# Scaled down LEF created by ScaleLEFMacro.pl
# Original LEF: 16nm/HDDP_1024X66M4B1.lef
# Don't forget to change metal layer LEF separately!

# Copyright (c) 1993 - 2021 ARM Limited. All Rights Reserved.
# Use of this Software is subject to the terms and conditions of the
# applicable license agreement with ARM Limited.

# PhyVGen V 8.22.0
# ARM Version r3p1
# Creation Date: Sat Sep 18 23:18:15 2021


# Memory Configuration:
# ~~~~~~~~~~~~~~~~~~~~~
#  -activity_factor 50 -atf off -back_biasing off -bits 66 -bmux on
# -bus_notation on -check_instname on -compiler_type dp -diodes on -drive 6
# -ema on -flexible_banking 1 -frequency 1000 -instname HDDP_1024X66M4B1
# -left_bus_delim "[" -lren_bankmask off -metal_stack 2Xa1Xd -mux 4 -mvt LP
# -name_case upper -pipeline off -power_gating off -power_type otc -prefix ""
# -pwr_gnd_rename vddpe:VDDPE,vddce:VDDCE,vsse:VSSE -rcols 2 -redundancy on
# -retention on -right_bus_delim "]" -rows_p_bl 256 -rrows 0 -scan on -ser none
# -site_def off -vmin_assist off -words 1024 -write_mask on -write_thru off
# -corners tt_0p80v_0p80v_25c
# 

VERSION 5.7 ;
BUSBITCHARS "[]" ;
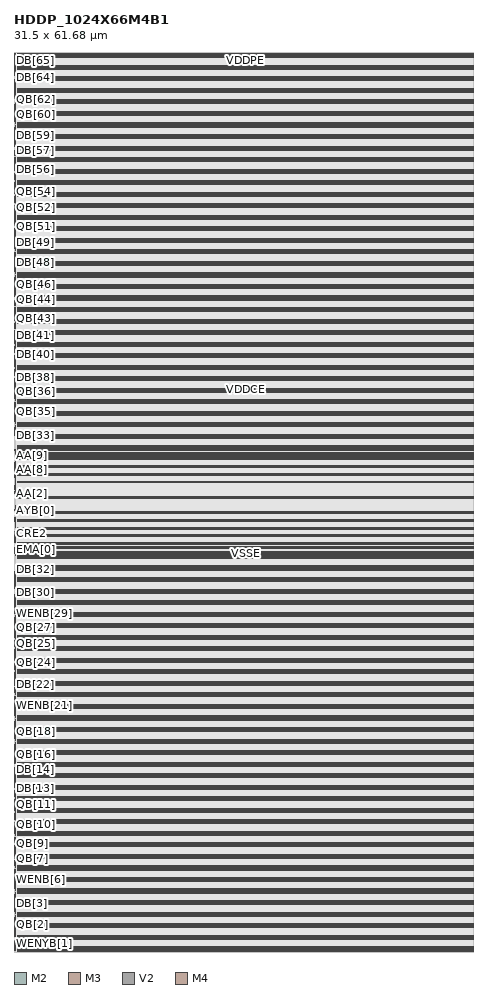
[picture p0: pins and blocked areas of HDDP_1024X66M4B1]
MACRO HDDP_1024X66M4B1
	FOREIGN HDDP_1024X66M4B1 0 0 ;
	SYMMETRY X Y ;
	SIZE 31.5 BY 61.68 ;
	CLASS BLOCK ;
	PIN AA[0]
		USE SIGNAL ;
		DIRECTION INPUT ;
		SHAPE ABUTMENT ;
		PORT
			 LAYER M2 ;
			RECT 0.0098 30.3184 0.0481 30.3561 ;
		END

		ANTENNAGATEAREA 0.00027817 ;
		ANTENNADIFFAREA 0.00194719 ;
		ANTENNAPARTIALMETALAREA 0.00195671 ;
	END AA[0]

	PIN AA[1]
		USE SIGNAL ;
		DIRECTION INPUT ;
		SHAPE ABUTMENT ;
		PORT
			 LAYER M2 ;
			RECT 0.0098 30.3812 0.0481 30.4188 ;
		END

		ANTENNAGATEAREA 0.00027817 ;
		ANTENNADIFFAREA 0.00194719 ;
		ANTENNAPARTIALMETALAREA 0.00195671 ;
	END AA[1]

	PIN AA[2]
		USE SIGNAL ;
		DIRECTION INPUT ;
		SHAPE ABUTMENT ;
		PORT
			 LAYER M2 ;
			RECT 0.0098 31.4353 0.0481 31.4729 ;
		END

		ANTENNAGATEAREA 0.00027817 ;
		ANTENNADIFFAREA 0.00194719 ;
		ANTENNAPARTIALMETALAREA 0.00195671 ;
	END AA[2]

	PIN AA[3]
		USE SIGNAL ;
		DIRECTION INPUT ;
		SHAPE ABUTMENT ;
		PORT
			 LAYER M2 ;
			RECT 0.0098 31.8996 0.0481 31.9373 ;
		END

		ANTENNAGATEAREA 0.00027817 ;
		ANTENNADIFFAREA 0.00194719 ;
		ANTENNAPARTIALMETALAREA 0.00195671 ;
	END AA[3]

	PIN AA[4]
		USE SIGNAL ;
		DIRECTION INPUT ;
		SHAPE ABUTMENT ;
		PORT
			 LAYER M2 ;
			RECT 0.0098 31.9624 0.0481 32 ;
		END

		ANTENNAGATEAREA 0.00027817 ;
		ANTENNADIFFAREA 0.00194719 ;
		ANTENNAPARTIALMETALAREA 0.00195671 ;
	END AA[4]

	PIN AA[5]
		USE SIGNAL ;
		DIRECTION INPUT ;
		SHAPE ABUTMENT ;
		PORT
			 LAYER M2 ;
			RECT 0.0098 32.4267 0.0481 32.4643 ;
		END

		ANTENNAGATEAREA 0.00027817 ;
		ANTENNADIFFAREA 0.00194719 ;
		ANTENNAPARTIALMETALAREA 0.00195671 ;
	END AA[5]

	PIN AA[6]
		USE SIGNAL ;
		DIRECTION INPUT ;
		SHAPE ABUTMENT ;
		PORT
			 LAYER M2 ;
			RECT 0.0098 32.4894 0.0481 32.5271 ;
		END

		ANTENNAGATEAREA 0.00027817 ;
		ANTENNADIFFAREA 0.00194719 ;
		ANTENNAPARTIALMETALAREA 0.00195671 ;
	END AA[6]

	PIN AA[7]
		USE SIGNAL ;
		DIRECTION INPUT ;
		SHAPE ABUTMENT ;
		PORT
			 LAYER M2 ;
			RECT 0.0098 32.9537 0.0481 32.9914 ;
		END

		ANTENNAGATEAREA 0.00027817 ;
		ANTENNADIFFAREA 0.00194719 ;
		ANTENNAPARTIALMETALAREA 0.00195671 ;
	END AA[7]

	PIN AA[8]
		USE SIGNAL ;
		DIRECTION INPUT ;
		SHAPE ABUTMENT ;
		PORT
			 LAYER M2 ;
			RECT 0.0098 33.0165 0.0481 33.0541 ;
		END

		ANTENNAGATEAREA 0.00027817 ;
		ANTENNADIFFAREA 0.00194719 ;
		ANTENNAPARTIALMETALAREA 0.00195671 ;
	END AA[8]

	PIN AA[9]
		USE SIGNAL ;
		DIRECTION INPUT ;
		SHAPE ABUTMENT ;
		PORT
			 LAYER M2 ;
			RECT 0.0098 33.4808 0.0481 33.5184 ;
		END

		ANTENNAGATEAREA 0.00027817 ;
		ANTENNADIFFAREA 0.00194719 ;
		ANTENNAPARTIALMETALAREA 0.00195671 ;
	END AA[9]

	PIN AB[0]
		USE SIGNAL ;
		DIRECTION INPUT ;
		SHAPE ABUTMENT ;
		PORT
			 LAYER M3 ;
			RECT 0.0714 30.1051 0.1097 30.2055 ;
		END

		ANTENNAGATEAREA 0.00027817 ;
		ANTENNADIFFAREA 0.00194719 ;
		ANTENNAPARTIALMETALAREA 0.00195671 ;
	END AB[0]

	PIN AB[1]
		USE SIGNAL ;
		DIRECTION INPUT ;
		SHAPE ABUTMENT ;
		PORT
			 LAYER M3 ;
			RECT 0.0714 30.5067 0.1097 30.6071 ;
		END

		ANTENNAGATEAREA 0.00027817 ;
		ANTENNADIFFAREA 0.00194719 ;
		ANTENNAPARTIALMETALAREA 0.00195671 ;
	END AB[1]

	PIN AB[2]
		USE SIGNAL ;
		DIRECTION INPUT ;
		SHAPE ABUTMENT ;
		PORT
			 LAYER M2 ;
			RECT 0.0098 34.3718 0.0481 34.4094 ;
		END

		ANTENNAGATEAREA 0.00027817 ;
		ANTENNADIFFAREA 0.00194719 ;
		ANTENNAPARTIALMETALAREA 0.00195671 ;
	END AB[2]

	PIN AB[3]
		USE SIGNAL ;
		DIRECTION INPUT ;
		SHAPE ABUTMENT ;
		PORT
			 LAYER M3 ;
			RECT 0.0714 31.7114 0.1097 31.8118 ;
		END

		ANTENNAGATEAREA 0.00027817 ;
		ANTENNADIFFAREA 0.00194719 ;
		ANTENNAPARTIALMETALAREA 0.00195671 ;
	END AB[3]

	PIN AB[4]
		USE SIGNAL ;
		DIRECTION INPUT ;
		SHAPE ABUTMENT ;
		PORT
			 LAYER M3 ;
			RECT 0.0714 32.0878 0.1097 32.1882 ;
		END

		ANTENNAGATEAREA 0.00027817 ;
		ANTENNADIFFAREA 0.00194719 ;
		ANTENNAPARTIALMETALAREA 0.00195671 ;
	END AB[4]

	PIN AB[5]
		USE SIGNAL ;
		DIRECTION INPUT ;
		SHAPE ABUTMENT ;
		PORT
			 LAYER M3 ;
			RECT 0.0714 32.2384 0.1097 32.3388 ;
		END

		ANTENNAGATEAREA 0.00027817 ;
		ANTENNADIFFAREA 0.00194719 ;
		ANTENNAPARTIALMETALAREA 0.00195671 ;
	END AB[5]

	PIN AB[6]
		USE SIGNAL ;
		DIRECTION INPUT ;
		SHAPE ABUTMENT ;
		PORT
			 LAYER M3 ;
			RECT 0.0714 32.6149 0.1097 32.7153 ;
		END

		ANTENNAGATEAREA 0.00027817 ;
		ANTENNADIFFAREA 0.00194719 ;
		ANTENNAPARTIALMETALAREA 0.00195671 ;
	END AB[6]

	PIN AB[7]
		USE SIGNAL ;
		DIRECTION INPUT ;
		SHAPE ABUTMENT ;
		PORT
			 LAYER M3 ;
			RECT 0.0714 32.7655 0.1097 32.8659 ;
		END

		ANTENNAGATEAREA 0.00027817 ;
		ANTENNADIFFAREA 0.00194719 ;
		ANTENNAPARTIALMETALAREA 0.00195671 ;
	END AB[7]

	PIN AB[8]
		USE SIGNAL ;
		DIRECTION INPUT ;
		SHAPE ABUTMENT ;
		PORT
			 LAYER M3 ;
			RECT 0.0714 33.142 0.1097 33.2424 ;
		END

		ANTENNAGATEAREA 0.00027817 ;
		ANTENNADIFFAREA 0.00194719 ;
		ANTENNAPARTIALMETALAREA 0.00195671 ;
	END AB[8]

	PIN AB[9]
		USE SIGNAL ;
		DIRECTION INPUT ;
		SHAPE ABUTMENT ;
		PORT
			 LAYER M3 ;
			RECT 0.0714 33.2925 0.1097 33.3929 ;
		END

		ANTENNAGATEAREA 0.00027817 ;
		ANTENNADIFFAREA 0.00194719 ;
		ANTENNAPARTIALMETALAREA 0.00195671 ;
	END AB[9]

	PIN AYA[0]
		USE SIGNAL ;
		DIRECTION OUTPUT ;
		SHAPE ABUTMENT ;
		PORT
			 LAYER M3 ;
			RECT 0.0714 30.2557 0.1097 30.3561 ;
		END

		ANTENNADIFFAREA 0.00194719 ;
		ANTENNAPARTIALMETALAREA 0.00195671 ;
	END AYA[0]

	PIN AYA[1]
		USE SIGNAL ;
		DIRECTION OUTPUT ;
		SHAPE ABUTMENT ;
		PORT
			 LAYER M3 ;
			RECT 0.0714 30.3812 0.1097 30.4816 ;
		END

		ANTENNADIFFAREA 0.00194719 ;
		ANTENNAPARTIALMETALAREA 0.00195671 ;
	END AYA[1]

	PIN AYA[2]
		USE SIGNAL ;
		DIRECTION OUTPUT ;
		SHAPE ABUTMENT ;
		PORT
			 LAYER M3 ;
			RECT 0.0714 31.4353 0.1097 31.5357 ;
		END

		ANTENNADIFFAREA 0.00194719 ;
		ANTENNAPARTIALMETALAREA 0.00195671 ;
	END AYA[2]

	PIN AYA[3]
		USE SIGNAL ;
		DIRECTION OUTPUT ;
		SHAPE ABUTMENT ;
		PORT
			 LAYER M3 ;
			RECT 0.0714 31.8369 0.1097 31.9373 ;
		END

		ANTENNADIFFAREA 0.00194719 ;
		ANTENNAPARTIALMETALAREA 0.00195671 ;
	END AYA[3]

	PIN AYA[4]
		USE SIGNAL ;
		DIRECTION OUTPUT ;
		SHAPE ABUTMENT ;
		PORT
			 LAYER M3 ;
			RECT 0.0714 31.9624 0.1097 32.0627 ;
		END

		ANTENNADIFFAREA 0.00194719 ;
		ANTENNAPARTIALMETALAREA 0.00195671 ;
	END AYA[4]

	PIN AYA[5]
		USE SIGNAL ;
		DIRECTION OUTPUT ;
		SHAPE ABUTMENT ;
		PORT
			 LAYER M3 ;
			RECT 0.0714 32.3639 0.1097 32.4643 ;
		END

		ANTENNADIFFAREA 0.00194719 ;
		ANTENNAPARTIALMETALAREA 0.00195671 ;
	END AYA[5]

	PIN AYA[6]
		USE SIGNAL ;
		DIRECTION OUTPUT ;
		SHAPE ABUTMENT ;
		PORT
			 LAYER M3 ;
			RECT 0.0714 32.4894 0.1097 32.5898 ;
		END

		ANTENNADIFFAREA 0.00194719 ;
		ANTENNAPARTIALMETALAREA 0.00195671 ;
	END AYA[6]

	PIN AYA[7]
		USE SIGNAL ;
		DIRECTION OUTPUT ;
		SHAPE ABUTMENT ;
		PORT
			 LAYER M3 ;
			RECT 0.0714 32.891 0.1097 32.9914 ;
		END

		ANTENNADIFFAREA 0.00194719 ;
		ANTENNAPARTIALMETALAREA 0.00195671 ;
	END AYA[7]

	PIN AYA[8]
		USE SIGNAL ;
		DIRECTION OUTPUT ;
		SHAPE ABUTMENT ;
		PORT
			 LAYER M3 ;
			RECT 0.0714 33.0165 0.1097 33.1169 ;
		END

		ANTENNADIFFAREA 0.00194719 ;
		ANTENNAPARTIALMETALAREA 0.00195671 ;
	END AYA[8]

	PIN AYA[9]
		USE SIGNAL ;
		DIRECTION OUTPUT ;
		SHAPE ABUTMENT ;
		PORT
			 LAYER M3 ;
			RECT 0.0714 33.418 0.1097 33.5184 ;
		END

		ANTENNADIFFAREA 0.00194719 ;
		ANTENNAPARTIALMETALAREA 0.00195671 ;
	END AYA[9]

	PIN AYB[0]
		USE SIGNAL ;
		DIRECTION OUTPUT ;
		SHAPE ABUTMENT ;
		PORT
			 LAYER M2 ;
			RECT 0.0098 30.2557 0.0481 30.2933 ;
		END

		ANTENNADIFFAREA 0.00194719 ;
		ANTENNAPARTIALMETALAREA 0.00195671 ;
	END AYB[0]

	PIN AYB[1]
		USE SIGNAL ;
		DIRECTION OUTPUT ;
		SHAPE ABUTMENT ;
		PORT
			 LAYER M2 ;
			RECT 0.0098 30.4439 0.0481 30.4816 ;
		END

		ANTENNADIFFAREA 0.00194719 ;
		ANTENNAPARTIALMETALAREA 0.00195671 ;
	END AYB[1]

	PIN AYB[2]
		USE SIGNAL ;
		DIRECTION OUTPUT ;
		SHAPE ABUTMENT ;
		PORT
			 LAYER M2 ;
			RECT 0.0098 31.498 0.0481 31.5357 ;
		END

		ANTENNADIFFAREA 0.00194719 ;
		ANTENNAPARTIALMETALAREA 0.00195671 ;
	END AYB[2]

	PIN AYB[3]
		USE SIGNAL ;
		DIRECTION OUTPUT ;
		SHAPE ABUTMENT ;
		PORT
			 LAYER M2 ;
			RECT 0.0098 31.8369 0.0481 31.8745 ;
		END

		ANTENNADIFFAREA 0.00194719 ;
		ANTENNAPARTIALMETALAREA 0.00195671 ;
	END AYB[3]

	PIN AYB[4]
		USE SIGNAL ;
		DIRECTION OUTPUT ;
		SHAPE ABUTMENT ;
		PORT
			 LAYER M2 ;
			RECT 0.0098 32.0251 0.0481 32.0627 ;
		END

		ANTENNADIFFAREA 0.00194719 ;
		ANTENNAPARTIALMETALAREA 0.00195671 ;
	END AYB[4]

	PIN AYB[5]
		USE SIGNAL ;
		DIRECTION OUTPUT ;
		SHAPE ABUTMENT ;
		PORT
			 LAYER M2 ;
			RECT 0.0098 32.3639 0.0481 32.4016 ;
		END

		ANTENNADIFFAREA 0.00194719 ;
		ANTENNAPARTIALMETALAREA 0.00195671 ;
	END AYB[5]

	PIN AYB[6]
		USE SIGNAL ;
		DIRECTION OUTPUT ;
		SHAPE ABUTMENT ;
		PORT
			 LAYER M2 ;
			RECT 0.0098 32.5522 0.0481 32.5898 ;
		END

		ANTENNADIFFAREA 0.00194719 ;
		ANTENNAPARTIALMETALAREA 0.00195671 ;
	END AYB[6]

	PIN AYB[7]
		USE SIGNAL ;
		DIRECTION OUTPUT ;
		SHAPE ABUTMENT ;
		PORT
			 LAYER M2 ;
			RECT 0.0098 32.891 0.0481 32.9286 ;
		END

		ANTENNADIFFAREA 0.00194719 ;
		ANTENNAPARTIALMETALAREA 0.00195671 ;
	END AYB[7]

	PIN AYB[8]
		USE SIGNAL ;
		DIRECTION OUTPUT ;
		SHAPE ABUTMENT ;
		PORT
			 LAYER M2 ;
			RECT 0.0098 33.0792 0.0481 33.1169 ;
		END

		ANTENNADIFFAREA 0.00194719 ;
		ANTENNAPARTIALMETALAREA 0.00195671 ;
	END AYB[8]

	PIN AYB[9]
		USE SIGNAL ;
		DIRECTION OUTPUT ;
		SHAPE ABUTMENT ;
		PORT
			 LAYER M2 ;
			RECT 0.0098 33.418 0.0481 33.4557 ;
		END

		ANTENNADIFFAREA 0.00194719 ;
		ANTENNAPARTIALMETALAREA 0.00195671 ;
	END AYB[9]

	PIN CENA
		USE SIGNAL ;
		DIRECTION INPUT ;
		SHAPE ABUTMENT ;
		PORT
			 LAYER M2 ;
			RECT 0.0098 33.5435 0.0481 33.5812 ;
		END

		ANTENNAGATEAREA 0.00027817 ;
		ANTENNADIFFAREA 0.00194719 ;
		ANTENNAPARTIALMETALAREA 0.00195671 ;
	END CENA

	PIN CENB
		USE SIGNAL ;
		DIRECTION INPUT ;
		SHAPE ABUTMENT ;
		PORT
			 LAYER M3 ;
			RECT 0.0714 33.669 0.1097 33.7694 ;
		END

		ANTENNAGATEAREA 0.00027817 ;
		ANTENNADIFFAREA 0.00194719 ;
		ANTENNAPARTIALMETALAREA 0.00195671 ;
	END CENB

	PIN CENYA
		USE SIGNAL ;
		DIRECTION OUTPUT ;
		SHAPE ABUTMENT ;
		PORT
			 LAYER M3 ;
			RECT 0.0714 33.5435 0.1097 33.6439 ;
		END

		ANTENNADIFFAREA 0.00194719 ;
		ANTENNAPARTIALMETALAREA 0.00195671 ;
	END CENYA

	PIN CENYB
		USE SIGNAL ;
		DIRECTION OUTPUT ;
		SHAPE ABUTMENT ;
		PORT
			 LAYER M2 ;
			RECT 0.0098 33.6063 0.0481 33.6439 ;
		END

		ANTENNADIFFAREA 0.00194719 ;
		ANTENNAPARTIALMETALAREA 0.00195671 ;
	END CENYB

	PIN CLK
		USE SIGNAL ;
		DIRECTION INPUT ;
		SHAPE ABUTMENT ;
		PORT
			 LAYER M3 ;
			RECT 0.0714 29.6533 0.1097 29.7537 ;
		END

		ANTENNAGATEAREA 0.00027817 ;
		ANTENNADIFFAREA 0.00194719 ;
		ANTENNAPARTIALMETALAREA 0.00195671 ;
	END CLK

	PIN CRE1
		USE SIGNAL ;
		DIRECTION INPUT ;
		SHAPE ABUTMENT ;
		PORT
			 LAYER M3 ;
			RECT 0.0714 28.0722 0.1097 28.1725 ;
		END

		ANTENNAGATEAREA 0.00027817 ;
		ANTENNADIFFAREA 0.00194719 ;
		ANTENNAPARTIALMETALAREA 0.00195671 ;
	END CRE1

	PIN CRE2
		USE SIGNAL ;
		DIRECTION INPUT ;
		SHAPE ABUTMENT ;
		PORT
			 LAYER M2 ;
			RECT 0.0098 28.6871 0.0481 28.7247 ;
		END

		ANTENNAGATEAREA 0.00027817 ;
		ANTENNADIFFAREA 0.00194719 ;
		ANTENNAPARTIALMETALAREA 0.00195671 ;
	END CRE2

	PIN DA[0]
		USE SIGNAL ;
		DIRECTION INPUT ;
		SHAPE ABUTMENT ;
		PORT
			 LAYER M2 ;
			RECT 0.0714 0.6024 0.1097 0.64 ;
			 LAYER M3 ;
			RECT 0.0714 0.5396 0.1097 0.64 ;
			 LAYER V2 ;
			RECT 0.0831 0.6153 0.098 0.6278 ;
		END

		ANTENNAGATEAREA 0.00027817 ;
		ANTENNADIFFAREA 0.00194719 ;
		ANTENNAPARTIALMETALAREA 0.00195671 ;
	END DA[0]

	PIN DA[10]
		USE SIGNAL ;
		DIRECTION INPUT ;
		SHAPE ABUTMENT ;
		PORT
			 LAYER M2 ;
			RECT 0.0714 8.5082 0.1097 8.5459 ;
			 LAYER M3 ;
			RECT 0.0714 8.4455 0.1097 8.5459 ;
			 LAYER V2 ;
			RECT 0.0831 8.5212 0.098 8.5337 ;
		END

		ANTENNAGATEAREA 0.00027817 ;
		ANTENNADIFFAREA 0.00194719 ;
		ANTENNAPARTIALMETALAREA 0.00195671 ;
	END DA[10]

	PIN DA[11]
		USE SIGNAL ;
		DIRECTION INPUT ;
		SHAPE ABUTMENT ;
		PORT
			 LAYER M2 ;
			RECT 0.0714 9.2988 0.1097 9.3365 ;
			 LAYER M3 ;
			RECT 0.0714 9.2361 0.1097 9.3365 ;
			 LAYER V2 ;
			RECT 0.0831 9.3118 0.098 9.3243 ;
		END

		ANTENNAGATEAREA 0.00027817 ;
		ANTENNADIFFAREA 0.00194719 ;
		ANTENNAPARTIALMETALAREA 0.00195671 ;
	END DA[11]

	PIN DA[12]
		USE SIGNAL ;
		DIRECTION INPUT ;
		SHAPE ABUTMENT ;
		PORT
			 LAYER M2 ;
			RECT 0.0714 10.0894 0.1097 10.1271 ;
			 LAYER M3 ;
			RECT 0.0714 10.0267 0.1097 10.1271 ;
			 LAYER V2 ;
			RECT 0.0831 10.1024 0.098 10.1149 ;
		END

		ANTENNAGATEAREA 0.00027817 ;
		ANTENNADIFFAREA 0.00194719 ;
		ANTENNAPARTIALMETALAREA 0.00195671 ;
	END DA[12]

	PIN DA[13]
		USE SIGNAL ;
		DIRECTION INPUT ;
		SHAPE ABUTMENT ;
		PORT
			 LAYER M2 ;
			RECT 0.0714 10.88 0.1097 10.9176 ;
			 LAYER M3 ;
			RECT 0.0714 10.8173 0.1097 10.9176 ;
			 LAYER V2 ;
			RECT 0.0831 10.8929 0.098 10.9055 ;
		END

		ANTENNAGATEAREA 0.00027817 ;
		ANTENNADIFFAREA 0.00194719 ;
		ANTENNAPARTIALMETALAREA 0.00195671 ;
	END DA[13]

	PIN DA[14]
		USE SIGNAL ;
		DIRECTION INPUT ;
		SHAPE ABUTMENT ;
		PORT
			 LAYER M2 ;
			RECT 0.0714 11.6706 0.1097 11.7082 ;
			 LAYER M3 ;
			RECT 0.0714 11.6078 0.1097 11.7082 ;
			 LAYER V2 ;
			RECT 0.0831 11.6835 0.098 11.6961 ;
		END

		ANTENNAGATEAREA 0.00027817 ;
		ANTENNADIFFAREA 0.00194719 ;
		ANTENNAPARTIALMETALAREA 0.00195671 ;
	END DA[14]

	PIN DA[15]
		USE SIGNAL ;
		DIRECTION INPUT ;
		SHAPE ABUTMENT ;
		PORT
			 LAYER M2 ;
			RECT 0.0714 12.4612 0.1097 12.4988 ;
			 LAYER M3 ;
			RECT 0.0714 12.3984 0.1097 12.4988 ;
			 LAYER V2 ;
			RECT 0.0831 12.4741 0.098 12.4867 ;
		END

		ANTENNAGATEAREA 0.00027817 ;
		ANTENNADIFFAREA 0.00194719 ;
		ANTENNAPARTIALMETALAREA 0.00195671 ;
	END DA[15]

	PIN DA[16]
		USE SIGNAL ;
		DIRECTION INPUT ;
		SHAPE ABUTMENT ;
		PORT
			 LAYER M2 ;
			RECT 0.0714 13.2518 0.1097 13.2894 ;
			 LAYER M3 ;
			RECT 0.0714 13.189 0.1097 13.2894 ;
			 LAYER V2 ;
			RECT 0.0831 13.2647 0.098 13.2773 ;
		END

		ANTENNAGATEAREA 0.00027817 ;
		ANTENNADIFFAREA 0.00194719 ;
		ANTENNAPARTIALMETALAREA 0.00195671 ;
	END DA[16]

	PIN DA[17]
		USE SIGNAL ;
		DIRECTION INPUT ;
		SHAPE ABUTMENT ;
		PORT
			 LAYER M2 ;
			RECT 0.0714 14.0424 0.1097 14.08 ;
			 LAYER M3 ;
			RECT 0.0714 13.9796 0.1097 14.08 ;
			 LAYER V2 ;
			RECT 0.0831 14.0553 0.098 14.0678 ;
		END

		ANTENNAGATEAREA 0.00027817 ;
		ANTENNADIFFAREA 0.00194719 ;
		ANTENNAPARTIALMETALAREA 0.00195671 ;
	END DA[17]

	PIN DA[18]
		USE SIGNAL ;
		DIRECTION INPUT ;
		SHAPE ABUTMENT ;
		PORT
			 LAYER M2 ;
			RECT 0.0714 14.8329 0.1097 14.8706 ;
			 LAYER M3 ;
			RECT 0.0714 14.7702 0.1097 14.8706 ;
			 LAYER V2 ;
			RECT 0.0831 14.8459 0.098 14.8584 ;
		END

		ANTENNAGATEAREA 0.00027817 ;
		ANTENNADIFFAREA 0.00194719 ;
		ANTENNAPARTIALMETALAREA 0.00195671 ;
	END DA[18]

	PIN DA[19]
		USE SIGNAL ;
		DIRECTION INPUT ;
		SHAPE ABUTMENT ;
		PORT
			 LAYER M2 ;
			RECT 0.0714 15.6235 0.1097 15.6612 ;
			 LAYER M3 ;
			RECT 0.0714 15.5608 0.1097 15.6612 ;
			 LAYER V2 ;
			RECT 0.0831 15.6365 0.098 15.649 ;
		END

		ANTENNAGATEAREA 0.00027817 ;
		ANTENNADIFFAREA 0.00194719 ;
		ANTENNAPARTIALMETALAREA 0.00195671 ;
	END DA[19]

	PIN DA[1]
		USE SIGNAL ;
		DIRECTION INPUT ;
		SHAPE ABUTMENT ;
		PORT
			 LAYER M2 ;
			RECT 0.0714 1.3929 0.1097 1.4306 ;
			 LAYER M3 ;
			RECT 0.0714 1.3302 0.1097 1.4306 ;
			 LAYER V2 ;
			RECT 0.0831 1.4059 0.098 1.4184 ;
		END

		ANTENNAGATEAREA 0.00027817 ;
		ANTENNADIFFAREA 0.00194719 ;
		ANTENNAPARTIALMETALAREA 0.00195671 ;
	END DA[1]

	PIN DA[20]
		USE SIGNAL ;
		DIRECTION INPUT ;
		SHAPE ABUTMENT ;
		PORT
			 LAYER M2 ;
			RECT 0.0714 16.4141 0.1097 16.4518 ;
			 LAYER M3 ;
			RECT 0.0714 16.3514 0.1097 16.4518 ;
			 LAYER V2 ;
			RECT 0.0831 16.4271 0.098 16.4396 ;
		END

		ANTENNAGATEAREA 0.00027817 ;
		ANTENNADIFFAREA 0.00194719 ;
		ANTENNAPARTIALMETALAREA 0.00195671 ;
	END DA[20]

	PIN DA[21]
		USE SIGNAL ;
		DIRECTION INPUT ;
		SHAPE ABUTMENT ;
		PORT
			 LAYER M2 ;
			RECT 0.0714 17.2047 0.1097 17.2424 ;
			 LAYER M3 ;
			RECT 0.0714 17.142 0.1097 17.2424 ;
			 LAYER V2 ;
			RECT 0.0831 17.2176 0.098 17.2302 ;
		END

		ANTENNAGATEAREA 0.00027817 ;
		ANTENNADIFFAREA 0.00194719 ;
		ANTENNAPARTIALMETALAREA 0.00195671 ;
	END DA[21]

	PIN DA[22]
		USE SIGNAL ;
		DIRECTION INPUT ;
		SHAPE ABUTMENT ;
		PORT
			 LAYER M2 ;
			RECT 0.0714 17.9953 0.1097 18.0329 ;
			 LAYER M3 ;
			RECT 0.0714 17.9325 0.1097 18.0329 ;
			 LAYER V2 ;
			RECT 0.0831 18.0082 0.098 18.0208 ;
		END

		ANTENNAGATEAREA 0.00027817 ;
		ANTENNADIFFAREA 0.00194719 ;
		ANTENNAPARTIALMETALAREA 0.00195671 ;
	END DA[22]

	PIN DA[23]
		USE SIGNAL ;
		DIRECTION INPUT ;
		SHAPE ABUTMENT ;
		PORT
			 LAYER M2 ;
			RECT 0.0714 18.7859 0.1097 18.8235 ;
			 LAYER M3 ;
			RECT 0.0714 18.7231 0.1097 18.8235 ;
			 LAYER V2 ;
			RECT 0.0831 18.7988 0.098 18.8114 ;
		END

		ANTENNAGATEAREA 0.00027817 ;
		ANTENNADIFFAREA 0.00194719 ;
		ANTENNAPARTIALMETALAREA 0.00195671 ;
	END DA[23]

	PIN DA[24]
		USE SIGNAL ;
		DIRECTION INPUT ;
		SHAPE ABUTMENT ;
		PORT
			 LAYER M2 ;
			RECT 0.0714 19.5765 0.1097 19.6141 ;
			 LAYER M3 ;
			RECT 0.0714 19.5137 0.1097 19.6141 ;
			 LAYER V2 ;
			RECT 0.0831 19.5894 0.098 19.602 ;
		END

		ANTENNAGATEAREA 0.00027817 ;
		ANTENNADIFFAREA 0.00194719 ;
		ANTENNAPARTIALMETALAREA 0.00195671 ;
	END DA[24]

	PIN DA[25]
		USE SIGNAL ;
		DIRECTION INPUT ;
		SHAPE ABUTMENT ;
		PORT
			 LAYER M2 ;
			RECT 0.0714 20.3671 0.1097 20.4047 ;
			 LAYER M3 ;
			RECT 0.0714 20.3043 0.1097 20.4047 ;
			 LAYER V2 ;
			RECT 0.0831 20.38 0.098 20.3925 ;
		END

		ANTENNAGATEAREA 0.00027817 ;
		ANTENNADIFFAREA 0.00194719 ;
		ANTENNAPARTIALMETALAREA 0.00195671 ;
	END DA[25]

	PIN DA[26]
		USE SIGNAL ;
		DIRECTION INPUT ;
		SHAPE ABUTMENT ;
		PORT
			 LAYER M2 ;
			RECT 0.0714 21.1576 0.1097 21.1953 ;
			 LAYER M3 ;
			RECT 0.0714 21.0949 0.1097 21.1953 ;
			 LAYER V2 ;
			RECT 0.0831 21.1706 0.098 21.1831 ;
		END

		ANTENNAGATEAREA 0.00027817 ;
		ANTENNADIFFAREA 0.00194719 ;
		ANTENNAPARTIALMETALAREA 0.00195671 ;
	END DA[26]

	PIN DA[27]
		USE SIGNAL ;
		DIRECTION INPUT ;
		SHAPE ABUTMENT ;
		PORT
			 LAYER M2 ;
			RECT 0.0714 21.9482 0.1097 21.9859 ;
			 LAYER M3 ;
			RECT 0.0714 21.8855 0.1097 21.9859 ;
			 LAYER V2 ;
			RECT 0.0831 21.9612 0.098 21.9737 ;
		END

		ANTENNAGATEAREA 0.00027817 ;
		ANTENNADIFFAREA 0.00194719 ;
		ANTENNAPARTIALMETALAREA 0.00195671 ;
	END DA[27]

	PIN DA[28]
		USE SIGNAL ;
		DIRECTION INPUT ;
		SHAPE ABUTMENT ;
		PORT
			 LAYER M2 ;
			RECT 0.0714 22.7388 0.1097 22.7765 ;
			 LAYER M3 ;
			RECT 0.0714 22.6761 0.1097 22.7765 ;
			 LAYER V2 ;
			RECT 0.0831 22.7518 0.098 22.7643 ;
		END

		ANTENNAGATEAREA 0.00027817 ;
		ANTENNADIFFAREA 0.00194719 ;
		ANTENNAPARTIALMETALAREA 0.00195671 ;
	END DA[28]

	PIN DA[29]
		USE SIGNAL ;
		DIRECTION INPUT ;
		SHAPE ABUTMENT ;
		PORT
			 LAYER M2 ;
			RECT 0.0714 23.5294 0.1097 23.5671 ;
			 LAYER M3 ;
			RECT 0.0714 23.4667 0.1097 23.5671 ;
			 LAYER V2 ;
			RECT 0.0831 23.5424 0.098 23.5549 ;
		END

		ANTENNAGATEAREA 0.00027817 ;
		ANTENNADIFFAREA 0.00194719 ;
		ANTENNAPARTIALMETALAREA 0.00195671 ;
	END DA[29]

	PIN DA[2]
		USE SIGNAL ;
		DIRECTION INPUT ;
		SHAPE ABUTMENT ;
		PORT
			 LAYER M2 ;
			RECT 0.0714 2.1835 0.1097 2.2212 ;
			 LAYER M3 ;
			RECT 0.0714 2.1208 0.1097 2.2212 ;
			 LAYER V2 ;
			RECT 0.0831 2.1965 0.098 2.209 ;
		END

		ANTENNAGATEAREA 0.00027817 ;
		ANTENNADIFFAREA 0.00194719 ;
		ANTENNAPARTIALMETALAREA 0.00195671 ;
	END DA[2]

	PIN DA[30]
		USE SIGNAL ;
		DIRECTION INPUT ;
		SHAPE ABUTMENT ;
		PORT
			 LAYER M2 ;
			RECT 0.0714 24.32 0.1097 24.3576 ;
			 LAYER M3 ;
			RECT 0.0714 24.2573 0.1097 24.3576 ;
			 LAYER V2 ;
			RECT 0.0831 24.3329 0.098 24.3455 ;
		END

		ANTENNAGATEAREA 0.00027817 ;
		ANTENNADIFFAREA 0.00194719 ;
		ANTENNAPARTIALMETALAREA 0.00195671 ;
	END DA[30]

	PIN DA[31]
		USE SIGNAL ;
		DIRECTION INPUT ;
		SHAPE ABUTMENT ;
		PORT
			 LAYER M2 ;
			RECT 0.0714 25.1106 0.1097 25.1482 ;
			 LAYER M3 ;
			RECT 0.0714 25.0478 0.1097 25.1482 ;
			 LAYER V2 ;
			RECT 0.0831 25.1235 0.098 25.1361 ;
		END

		ANTENNAGATEAREA 0.00027817 ;
		ANTENNADIFFAREA 0.00194719 ;
		ANTENNAPARTIALMETALAREA 0.00195671 ;
	END DA[31]

	PIN DA[32]
		USE SIGNAL ;
		DIRECTION INPUT ;
		SHAPE ABUTMENT ;
		PORT
			 LAYER M2 ;
			RECT 0.0714 25.9012 0.1097 25.9388 ;
			 LAYER M3 ;
			RECT 0.0714 25.8384 0.1097 25.9388 ;
			 LAYER V2 ;
			RECT 0.0831 25.9141 0.098 25.9267 ;
		END

		ANTENNAGATEAREA 0.00027817 ;
		ANTENNADIFFAREA 0.00194719 ;
		ANTENNAPARTIALMETALAREA 0.00195671 ;
	END DA[32]

	PIN DA[33]
		USE SIGNAL ;
		DIRECTION INPUT ;
		SHAPE ABUTMENT ;
		PORT
			 LAYER M2 ;
			RECT 0.0714 35.7082 0.1097 35.7459 ;
			 LAYER M3 ;
			RECT 0.0714 35.7082 0.1097 35.8086 ;
			 LAYER V2 ;
			RECT 0.0831 35.7204 0.098 35.7329 ;
		END

		ANTENNAGATEAREA 0.00027817 ;
		ANTENNADIFFAREA 0.00194719 ;
		ANTENNAPARTIALMETALAREA 0.00195671 ;
	END DA[33]

	PIN DA[34]
		USE SIGNAL ;
		DIRECTION INPUT ;
		SHAPE ABUTMENT ;
		PORT
			 LAYER M2 ;
			RECT 0.0714 36.4988 0.1097 36.5365 ;
			 LAYER M3 ;
			RECT 0.0714 36.4988 0.1097 36.5992 ;
			 LAYER V2 ;
			RECT 0.0831 36.511 0.098 36.5235 ;
		END

		ANTENNAGATEAREA 0.00027817 ;
		ANTENNADIFFAREA 0.00194719 ;
		ANTENNAPARTIALMETALAREA 0.00195671 ;
	END DA[34]

	PIN DA[35]
		USE SIGNAL ;
		DIRECTION INPUT ;
		SHAPE ABUTMENT ;
		PORT
			 LAYER M2 ;
			RECT 0.0714 37.2894 0.1097 37.3271 ;
			 LAYER M3 ;
			RECT 0.0714 37.2894 0.1097 37.3898 ;
			 LAYER V2 ;
			RECT 0.0831 37.3016 0.098 37.3141 ;
		END

		ANTENNAGATEAREA 0.00027817 ;
		ANTENNADIFFAREA 0.00194719 ;
		ANTENNAPARTIALMETALAREA 0.00195671 ;
	END DA[35]

	PIN DA[36]
		USE SIGNAL ;
		DIRECTION INPUT ;
		SHAPE ABUTMENT ;
		PORT
			 LAYER M2 ;
			RECT 0.0714 38.08 0.1097 38.1176 ;
			 LAYER M3 ;
			RECT 0.0714 38.08 0.1097 38.1804 ;
			 LAYER V2 ;
			RECT 0.0831 38.0922 0.098 38.1047 ;
		END

		ANTENNAGATEAREA 0.00027817 ;
		ANTENNADIFFAREA 0.00194719 ;
		ANTENNAPARTIALMETALAREA 0.00195671 ;
	END DA[36]

	PIN DA[37]
		USE SIGNAL ;
		DIRECTION INPUT ;
		SHAPE ABUTMENT ;
		PORT
			 LAYER M2 ;
			RECT 0.0714 38.8706 0.1097 38.9082 ;
			 LAYER M3 ;
			RECT 0.0714 38.8706 0.1097 38.971 ;
			 LAYER V2 ;
			RECT 0.0831 38.8827 0.098 38.8953 ;
		END

		ANTENNAGATEAREA 0.00027817 ;
		ANTENNADIFFAREA 0.00194719 ;
		ANTENNAPARTIALMETALAREA 0.00195671 ;
	END DA[37]

	PIN DA[38]
		USE SIGNAL ;
		DIRECTION INPUT ;
		SHAPE ABUTMENT ;
		PORT
			 LAYER M2 ;
			RECT 0.0714 39.6612 0.1097 39.6988 ;
			 LAYER M3 ;
			RECT 0.0714 39.6612 0.1097 39.7616 ;
			 LAYER V2 ;
			RECT 0.0831 39.6733 0.098 39.6859 ;
		END

		ANTENNAGATEAREA 0.00027817 ;
		ANTENNADIFFAREA 0.00194719 ;
		ANTENNAPARTIALMETALAREA 0.00195671 ;
	END DA[38]

	PIN DA[39]
		USE SIGNAL ;
		DIRECTION INPUT ;
		SHAPE ABUTMENT ;
		PORT
			 LAYER M2 ;
			RECT 0.0714 40.4518 0.1097 40.4894 ;
			 LAYER M3 ;
			RECT 0.0714 40.4518 0.1097 40.5522 ;
			 LAYER V2 ;
			RECT 0.0831 40.4639 0.098 40.4765 ;
		END

		ANTENNAGATEAREA 0.00027817 ;
		ANTENNADIFFAREA 0.00194719 ;
		ANTENNAPARTIALMETALAREA 0.00195671 ;
	END DA[39]

	PIN DA[3]
		USE SIGNAL ;
		DIRECTION INPUT ;
		SHAPE ABUTMENT ;
		PORT
			 LAYER M2 ;
			RECT 0.0714 2.9741 0.1097 3.0118 ;
			 LAYER M3 ;
			RECT 0.0714 2.9114 0.1097 3.0118 ;
			 LAYER V2 ;
			RECT 0.0831 2.9871 0.098 2.9996 ;
		END

		ANTENNAGATEAREA 0.00027817 ;
		ANTENNADIFFAREA 0.00194719 ;
		ANTENNAPARTIALMETALAREA 0.00195671 ;
	END DA[3]

	PIN DA[40]
		USE SIGNAL ;
		DIRECTION INPUT ;
		SHAPE ABUTMENT ;
		PORT
			 LAYER M2 ;
			RECT 0.0714 41.2424 0.1097 41.28 ;
			 LAYER M3 ;
			RECT 0.0714 41.2424 0.1097 41.3427 ;
			 LAYER V2 ;
			RECT 0.0831 41.2545 0.098 41.2671 ;
		END

		ANTENNAGATEAREA 0.00027817 ;
		ANTENNADIFFAREA 0.00194719 ;
		ANTENNAPARTIALMETALAREA 0.00195671 ;
	END DA[40]

	PIN DA[41]
		USE SIGNAL ;
		DIRECTION INPUT ;
		SHAPE ABUTMENT ;
		PORT
			 LAYER M2 ;
			RECT 0.0714 42.0329 0.1097 42.0706 ;
			 LAYER M3 ;
			RECT 0.0714 42.0329 0.1097 42.1333 ;
			 LAYER V2 ;
			RECT 0.0831 42.0451 0.098 42.0576 ;
		END

		ANTENNAGATEAREA 0.00027817 ;
		ANTENNADIFFAREA 0.00194719 ;
		ANTENNAPARTIALMETALAREA 0.00195671 ;
	END DA[41]

	PIN DA[42]
		USE SIGNAL ;
		DIRECTION INPUT ;
		SHAPE ABUTMENT ;
		PORT
			 LAYER M2 ;
			RECT 0.0714 42.8235 0.1097 42.8612 ;
			 LAYER M3 ;
			RECT 0.0714 42.8235 0.1097 42.9239 ;
			 LAYER V2 ;
			RECT 0.0831 42.8357 0.098 42.8482 ;
		END

		ANTENNAGATEAREA 0.00027817 ;
		ANTENNADIFFAREA 0.00194719 ;
		ANTENNAPARTIALMETALAREA 0.00195671 ;
	END DA[42]

	PIN DA[43]
		USE SIGNAL ;
		DIRECTION INPUT ;
		SHAPE ABUTMENT ;
		PORT
			 LAYER M2 ;
			RECT 0.0714 43.6141 0.1097 43.6518 ;
			 LAYER M3 ;
			RECT 0.0714 43.6141 0.1097 43.7145 ;
			 LAYER V2 ;
			RECT 0.0831 43.6263 0.098 43.6388 ;
		END

		ANTENNAGATEAREA 0.00027817 ;
		ANTENNADIFFAREA 0.00194719 ;
		ANTENNAPARTIALMETALAREA 0.00195671 ;
	END DA[43]

	PIN DA[44]
		USE SIGNAL ;
		DIRECTION INPUT ;
		SHAPE ABUTMENT ;
		PORT
			 LAYER M2 ;
			RECT 0.0714 44.4047 0.1097 44.4424 ;
			 LAYER M3 ;
			RECT 0.0714 44.4047 0.1097 44.5051 ;
			 LAYER V2 ;
			RECT 0.0831 44.4169 0.098 44.4294 ;
		END

		ANTENNAGATEAREA 0.00027817 ;
		ANTENNADIFFAREA 0.00194719 ;
		ANTENNAPARTIALMETALAREA 0.00195671 ;
	END DA[44]

	PIN DA[45]
		USE SIGNAL ;
		DIRECTION INPUT ;
		SHAPE ABUTMENT ;
		PORT
			 LAYER M2 ;
			RECT 0.0714 45.1953 0.1097 45.2329 ;
			 LAYER M3 ;
			RECT 0.0714 45.1953 0.1097 45.2957 ;
			 LAYER V2 ;
			RECT 0.0831 45.2075 0.098 45.22 ;
		END

		ANTENNAGATEAREA 0.00027817 ;
		ANTENNADIFFAREA 0.00194719 ;
		ANTENNAPARTIALMETALAREA 0.00195671 ;
	END DA[45]

	PIN DA[46]
		USE SIGNAL ;
		DIRECTION INPUT ;
		SHAPE ABUTMENT ;
		PORT
			 LAYER M2 ;
			RECT 0.0714 45.9859 0.1097 46.0235 ;
			 LAYER M3 ;
			RECT 0.0714 45.9859 0.1097 46.0863 ;
			 LAYER V2 ;
			RECT 0.0831 45.998 0.098 46.0106 ;
		END

		ANTENNAGATEAREA 0.00027817 ;
		ANTENNADIFFAREA 0.00194719 ;
		ANTENNAPARTIALMETALAREA 0.00195671 ;
	END DA[46]

	PIN DA[47]
		USE SIGNAL ;
		DIRECTION INPUT ;
		SHAPE ABUTMENT ;
		PORT
			 LAYER M2 ;
			RECT 0.0714 46.7765 0.1097 46.8141 ;
			 LAYER M3 ;
			RECT 0.0714 46.7765 0.1097 46.8769 ;
			 LAYER V2 ;
			RECT 0.0831 46.7886 0.098 46.8012 ;
		END

		ANTENNAGATEAREA 0.00027817 ;
		ANTENNADIFFAREA 0.00194719 ;
		ANTENNAPARTIALMETALAREA 0.00195671 ;
	END DA[47]

	PIN DA[48]
		USE SIGNAL ;
		DIRECTION INPUT ;
		SHAPE ABUTMENT ;
		PORT
			 LAYER M2 ;
			RECT 0.0714 47.5671 0.1097 47.6047 ;
			 LAYER M3 ;
			RECT 0.0714 47.5671 0.1097 47.6675 ;
			 LAYER V2 ;
			RECT 0.0831 47.5792 0.098 47.5918 ;
		END

		ANTENNAGATEAREA 0.00027817 ;
		ANTENNADIFFAREA 0.00194719 ;
		ANTENNAPARTIALMETALAREA 0.00195671 ;
	END DA[48]

	PIN DA[49]
		USE SIGNAL ;
		DIRECTION INPUT ;
		SHAPE ABUTMENT ;
		PORT
			 LAYER M2 ;
			RECT 0.0714 48.3576 0.1097 48.3953 ;
			 LAYER M3 ;
			RECT 0.0714 48.3576 0.1097 48.458 ;
			 LAYER V2 ;
			RECT 0.0831 48.3698 0.098 48.3824 ;
		END

		ANTENNAGATEAREA 0.00027817 ;
		ANTENNADIFFAREA 0.00194719 ;
		ANTENNAPARTIALMETALAREA 0.00195671 ;
	END DA[49]

	PIN DA[4]
		USE SIGNAL ;
		DIRECTION INPUT ;
		SHAPE ABUTMENT ;
		PORT
			 LAYER M2 ;
			RECT 0.0714 3.7647 0.1097 3.8024 ;
			 LAYER M3 ;
			RECT 0.0714 3.702 0.1097 3.8024 ;
			 LAYER V2 ;
			RECT 0.0831 3.7776 0.098 3.7902 ;
		END

		ANTENNAGATEAREA 0.00027817 ;
		ANTENNADIFFAREA 0.00194719 ;
		ANTENNAPARTIALMETALAREA 0.00195671 ;
	END DA[4]

	PIN DA[50]
		USE SIGNAL ;
		DIRECTION INPUT ;
		SHAPE ABUTMENT ;
		PORT
			 LAYER M2 ;
			RECT 0.0714 49.1482 0.1097 49.1859 ;
			 LAYER M3 ;
			RECT 0.0714 49.1482 0.1097 49.2486 ;
			 LAYER V2 ;
			RECT 0.0831 49.1604 0.098 49.1729 ;
		END

		ANTENNAGATEAREA 0.00027817 ;
		ANTENNADIFFAREA 0.00194719 ;
		ANTENNAPARTIALMETALAREA 0.00195671 ;
	END DA[50]

	PIN DA[51]
		USE SIGNAL ;
		DIRECTION INPUT ;
		SHAPE ABUTMENT ;
		PORT
			 LAYER M2 ;
			RECT 0.0714 49.9388 0.1097 49.9765 ;
			 LAYER M3 ;
			RECT 0.0714 49.9388 0.1097 50.0392 ;
			 LAYER V2 ;
			RECT 0.0831 49.951 0.098 49.9635 ;
		END

		ANTENNAGATEAREA 0.00027817 ;
		ANTENNADIFFAREA 0.00194719 ;
		ANTENNAPARTIALMETALAREA 0.00195671 ;
	END DA[51]

	PIN DA[52]
		USE SIGNAL ;
		DIRECTION INPUT ;
		SHAPE ABUTMENT ;
		PORT
			 LAYER M2 ;
			RECT 0.0714 50.7294 0.1097 50.7671 ;
			 LAYER M3 ;
			RECT 0.0714 50.7294 0.1097 50.8298 ;
			 LAYER V2 ;
			RECT 0.0831 50.7416 0.098 50.7541 ;
		END

		ANTENNAGATEAREA 0.00027817 ;
		ANTENNADIFFAREA 0.00194719 ;
		ANTENNAPARTIALMETALAREA 0.00195671 ;
	END DA[52]

	PIN DA[53]
		USE SIGNAL ;
		DIRECTION INPUT ;
		SHAPE ABUTMENT ;
		PORT
			 LAYER M2 ;
			RECT 0.0714 51.52 0.1097 51.5576 ;
			 LAYER M3 ;
			RECT 0.0714 51.52 0.1097 51.6204 ;
			 LAYER V2 ;
			RECT 0.0831 51.5322 0.098 51.5447 ;
		END

		ANTENNAGATEAREA 0.00027817 ;
		ANTENNADIFFAREA 0.00194719 ;
		ANTENNAPARTIALMETALAREA 0.00195671 ;
	END DA[53]

	PIN DA[54]
		USE SIGNAL ;
		DIRECTION INPUT ;
		SHAPE ABUTMENT ;
		PORT
			 LAYER M2 ;
			RECT 0.0714 52.3106 0.1097 52.3482 ;
			 LAYER M3 ;
			RECT 0.0714 52.3106 0.1097 52.411 ;
			 LAYER V2 ;
			RECT 0.0831 52.3227 0.098 52.3353 ;
		END

		ANTENNAGATEAREA 0.00027817 ;
		ANTENNADIFFAREA 0.00194719 ;
		ANTENNAPARTIALMETALAREA 0.00195671 ;
	END DA[54]

	PIN DA[55]
		USE SIGNAL ;
		DIRECTION INPUT ;
		SHAPE ABUTMENT ;
		PORT
			 LAYER M2 ;
			RECT 0.0714 53.1012 0.1097 53.1388 ;
			 LAYER M3 ;
			RECT 0.0714 53.1012 0.1097 53.2016 ;
			 LAYER V2 ;
			RECT 0.0831 53.1133 0.098 53.1259 ;
		END

		ANTENNAGATEAREA 0.00027817 ;
		ANTENNADIFFAREA 0.00194719 ;
		ANTENNAPARTIALMETALAREA 0.00195671 ;
	END DA[55]

	PIN DA[56]
		USE SIGNAL ;
		DIRECTION INPUT ;
		SHAPE ABUTMENT ;
		PORT
			 LAYER M2 ;
			RECT 0.0714 53.8918 0.1097 53.9294 ;
			 LAYER M3 ;
			RECT 0.0714 53.8918 0.1097 53.9922 ;
			 LAYER V2 ;
			RECT 0.0831 53.9039 0.098 53.9165 ;
		END

		ANTENNAGATEAREA 0.00027817 ;
		ANTENNADIFFAREA 0.00194719 ;
		ANTENNAPARTIALMETALAREA 0.00195671 ;
	END DA[56]

	PIN DA[57]
		USE SIGNAL ;
		DIRECTION INPUT ;
		SHAPE ABUTMENT ;
		PORT
			 LAYER M2 ;
			RECT 0.0714 54.6824 0.1097 54.72 ;
			 LAYER M3 ;
			RECT 0.0714 54.6824 0.1097 54.7827 ;
			 LAYER V2 ;
			RECT 0.0831 54.6945 0.098 54.7071 ;
		END

		ANTENNAGATEAREA 0.00027817 ;
		ANTENNADIFFAREA 0.00194719 ;
		ANTENNAPARTIALMETALAREA 0.00195671 ;
	END DA[57]

	PIN DA[58]
		USE SIGNAL ;
		DIRECTION INPUT ;
		SHAPE ABUTMENT ;
		PORT
			 LAYER M2 ;
			RECT 0.0714 55.4729 0.1097 55.5106 ;
			 LAYER M3 ;
			RECT 0.0714 55.4729 0.1097 55.5733 ;
			 LAYER V2 ;
			RECT 0.0831 55.4851 0.098 55.4976 ;
		END

		ANTENNAGATEAREA 0.00027817 ;
		ANTENNADIFFAREA 0.00194719 ;
		ANTENNAPARTIALMETALAREA 0.00195671 ;
	END DA[58]

	PIN DA[59]
		USE SIGNAL ;
		DIRECTION INPUT ;
		SHAPE ABUTMENT ;
		PORT
			 LAYER M2 ;
			RECT 0.0714 56.2635 0.1097 56.3012 ;
			 LAYER M3 ;
			RECT 0.0714 56.2635 0.1097 56.3639 ;
			 LAYER V2 ;
			RECT 0.0831 56.2757 0.098 56.2882 ;
		END

		ANTENNAGATEAREA 0.00027817 ;
		ANTENNADIFFAREA 0.00194719 ;
		ANTENNAPARTIALMETALAREA 0.00195671 ;
	END DA[59]

	PIN DA[5]
		USE SIGNAL ;
		DIRECTION INPUT ;
		SHAPE ABUTMENT ;
		PORT
			 LAYER M2 ;
			RECT 0.0714 4.5553 0.1097 4.5929 ;
			 LAYER M3 ;
			RECT 0.0714 4.4925 0.1097 4.5929 ;
			 LAYER V2 ;
			RECT 0.0831 4.5682 0.098 4.5808 ;
		END

		ANTENNAGATEAREA 0.00027817 ;
		ANTENNADIFFAREA 0.00194719 ;
		ANTENNAPARTIALMETALAREA 0.00195671 ;
	END DA[5]

	PIN DA[60]
		USE SIGNAL ;
		DIRECTION INPUT ;
		SHAPE ABUTMENT ;
		PORT
			 LAYER M2 ;
			RECT 0.0714 57.0541 0.1097 57.0918 ;
			 LAYER M3 ;
			RECT 0.0714 57.0541 0.1097 57.1545 ;
			 LAYER V2 ;
			RECT 0.0831 57.0663 0.098 57.0788 ;
		END

		ANTENNAGATEAREA 0.00027817 ;
		ANTENNADIFFAREA 0.00194719 ;
		ANTENNAPARTIALMETALAREA 0.00195671 ;
	END DA[60]

	PIN DA[61]
		USE SIGNAL ;
		DIRECTION INPUT ;
		SHAPE ABUTMENT ;
		PORT
			 LAYER M2 ;
			RECT 0.0714 57.8447 0.1097 57.8824 ;
			 LAYER M3 ;
			RECT 0.0714 57.8447 0.1097 57.9451 ;
			 LAYER V2 ;
			RECT 0.0831 57.8569 0.098 57.8694 ;
		END

		ANTENNAGATEAREA 0.00027817 ;
		ANTENNADIFFAREA 0.00194719 ;
		ANTENNAPARTIALMETALAREA 0.00195671 ;
	END DA[61]

	PIN DA[62]
		USE SIGNAL ;
		DIRECTION INPUT ;
		SHAPE ABUTMENT ;
		PORT
			 LAYER M2 ;
			RECT 0.0714 58.6353 0.1097 58.6729 ;
			 LAYER M3 ;
			RECT 0.0714 58.6353 0.1097 58.7357 ;
			 LAYER V2 ;
			RECT 0.0831 58.6475 0.098 58.66 ;
		END

		ANTENNAGATEAREA 0.00027817 ;
		ANTENNADIFFAREA 0.00194719 ;
		ANTENNAPARTIALMETALAREA 0.00195671 ;
	END DA[62]

	PIN DA[63]
		USE SIGNAL ;
		DIRECTION INPUT ;
		SHAPE ABUTMENT ;
		PORT
			 LAYER M2 ;
			RECT 0.0714 59.4259 0.1097 59.4635 ;
			 LAYER M3 ;
			RECT 0.0714 59.4259 0.1097 59.5263 ;
			 LAYER V2 ;
			RECT 0.0831 59.438 0.098 59.4506 ;
		END

		ANTENNAGATEAREA 0.00027817 ;
		ANTENNADIFFAREA 0.00194719 ;
		ANTENNAPARTIALMETALAREA 0.00195671 ;
	END DA[63]

	PIN DA[64]
		USE SIGNAL ;
		DIRECTION INPUT ;
		SHAPE ABUTMENT ;
		PORT
			 LAYER M2 ;
			RECT 0.0714 60.2165 0.1097 60.2541 ;
			 LAYER M3 ;
			RECT 0.0714 60.2165 0.1097 60.3169 ;
			 LAYER V2 ;
			RECT 0.0831 60.2286 0.098 60.2412 ;
		END

		ANTENNAGATEAREA 0.00027817 ;
		ANTENNADIFFAREA 0.00194719 ;
		ANTENNAPARTIALMETALAREA 0.00195671 ;
	END DA[64]

	PIN DA[65]
		USE SIGNAL ;
		DIRECTION INPUT ;
		SHAPE ABUTMENT ;
		PORT
			 LAYER M2 ;
			RECT 0.0714 61.0071 0.1097 61.0447 ;
			 LAYER M3 ;
			RECT 0.0714 61.0071 0.1097 61.1075 ;
			 LAYER V2 ;
			RECT 0.0831 61.0192 0.098 61.0318 ;
		END

		ANTENNAGATEAREA 0.00027817 ;
		ANTENNADIFFAREA 0.00194719 ;
		ANTENNAPARTIALMETALAREA 0.00195671 ;
	END DA[65]

	PIN DA[6]
		USE SIGNAL ;
		DIRECTION INPUT ;
		SHAPE ABUTMENT ;
		PORT
			 LAYER M2 ;
			RECT 0.0714 5.3459 0.1097 5.3835 ;
			 LAYER M3 ;
			RECT 0.0714 5.2831 0.1097 5.3835 ;
			 LAYER V2 ;
			RECT 0.0831 5.3588 0.098 5.3714 ;
		END

		ANTENNAGATEAREA 0.00027817 ;
		ANTENNADIFFAREA 0.00194719 ;
		ANTENNAPARTIALMETALAREA 0.00195671 ;
	END DA[6]

	PIN DA[7]
		USE SIGNAL ;
		DIRECTION INPUT ;
		SHAPE ABUTMENT ;
		PORT
			 LAYER M2 ;
			RECT 0.0714 6.1365 0.1097 6.1741 ;
			 LAYER M3 ;
			RECT 0.0714 6.0737 0.1097 6.1741 ;
			 LAYER V2 ;
			RECT 0.0831 6.1494 0.098 6.162 ;
		END

		ANTENNAGATEAREA 0.00027817 ;
		ANTENNADIFFAREA 0.00194719 ;
		ANTENNAPARTIALMETALAREA 0.00195671 ;
	END DA[7]

	PIN DA[8]
		USE SIGNAL ;
		DIRECTION INPUT ;
		SHAPE ABUTMENT ;
		PORT
			 LAYER M2 ;
			RECT 0.0714 6.9271 0.1097 6.9647 ;
			 LAYER M3 ;
			RECT 0.0714 6.8643 0.1097 6.9647 ;
			 LAYER V2 ;
			RECT 0.0831 6.94 0.098 6.9525 ;
		END

		ANTENNAGATEAREA 0.00027817 ;
		ANTENNADIFFAREA 0.00194719 ;
		ANTENNAPARTIALMETALAREA 0.00195671 ;
	END DA[8]

	PIN DA[9]
		USE SIGNAL ;
		DIRECTION INPUT ;
		SHAPE ABUTMENT ;
		PORT
			 LAYER M2 ;
			RECT 0.0714 7.7176 0.1097 7.7553 ;
			 LAYER M3 ;
			RECT 0.0714 7.6549 0.1097 7.7553 ;
			 LAYER V2 ;
			RECT 0.0831 7.7306 0.098 7.7431 ;
		END

		ANTENNAGATEAREA 0.00027817 ;
		ANTENNADIFFAREA 0.00194719 ;
		ANTENNAPARTIALMETALAREA 0.00195671 ;
	END DA[9]

	PIN DB[0]
		USE SIGNAL ;
		DIRECTION INPUT ;
		SHAPE ABUTMENT ;
		PORT
			 LAYER M2 ;
			RECT 0.0098 0.9035 0.0481 0.9412 ;
		END

		ANTENNAGATEAREA 0.00027817 ;
		ANTENNADIFFAREA 0.00194719 ;
		ANTENNAPARTIALMETALAREA 0.00195671 ;
	END DB[0]

	PIN DB[10]
		USE SIGNAL ;
		DIRECTION INPUT ;
		SHAPE ABUTMENT ;
		PORT
			 LAYER M2 ;
			RECT 0.0098 8.8094 0.0481 8.8471 ;
		END

		ANTENNAGATEAREA 0.00027817 ;
		ANTENNADIFFAREA 0.00194719 ;
		ANTENNAPARTIALMETALAREA 0.00195671 ;
	END DB[10]

	PIN DB[11]
		USE SIGNAL ;
		DIRECTION INPUT ;
		SHAPE ABUTMENT ;
		PORT
			 LAYER M2 ;
			RECT 0.0098 9.6 0.0481 9.6376 ;
		END

		ANTENNAGATEAREA 0.00027817 ;
		ANTENNADIFFAREA 0.00194719 ;
		ANTENNAPARTIALMETALAREA 0.00195671 ;
	END DB[11]

	PIN DB[12]
		USE SIGNAL ;
		DIRECTION INPUT ;
		SHAPE ABUTMENT ;
		PORT
			 LAYER M2 ;
			RECT 0.0098 10.3906 0.0481 10.4282 ;
		END

		ANTENNAGATEAREA 0.00027817 ;
		ANTENNADIFFAREA 0.00194719 ;
		ANTENNAPARTIALMETALAREA 0.00195671 ;
	END DB[12]

	PIN DB[13]
		USE SIGNAL ;
		DIRECTION INPUT ;
		SHAPE ABUTMENT ;
		PORT
			 LAYER M2 ;
			RECT 0.0098 11.1812 0.0481 11.2188 ;
		END

		ANTENNAGATEAREA 0.00027817 ;
		ANTENNADIFFAREA 0.00194719 ;
		ANTENNAPARTIALMETALAREA 0.00195671 ;
	END DB[13]

	PIN DB[14]
		USE SIGNAL ;
		DIRECTION INPUT ;
		SHAPE ABUTMENT ;
		PORT
			 LAYER M2 ;
			RECT 0.0098 11.9718 0.0481 12.0094 ;
		END

		ANTENNAGATEAREA 0.00027817 ;
		ANTENNADIFFAREA 0.00194719 ;
		ANTENNAPARTIALMETALAREA 0.00195671 ;
	END DB[14]

	PIN DB[15]
		USE SIGNAL ;
		DIRECTION INPUT ;
		SHAPE ABUTMENT ;
		PORT
			 LAYER M2 ;
			RECT 0.0098 12.7624 0.0481 12.8 ;
		END

		ANTENNAGATEAREA 0.00027817 ;
		ANTENNADIFFAREA 0.00194719 ;
		ANTENNAPARTIALMETALAREA 0.00195671 ;
	END DB[15]

	PIN DB[16]
		USE SIGNAL ;
		DIRECTION INPUT ;
		SHAPE ABUTMENT ;
		PORT
			 LAYER M2 ;
			RECT 0.0098 13.5529 0.0481 13.5906 ;
		END

		ANTENNAGATEAREA 0.00027817 ;
		ANTENNADIFFAREA 0.00194719 ;
		ANTENNAPARTIALMETALAREA 0.00195671 ;
	END DB[16]

	PIN DB[17]
		USE SIGNAL ;
		DIRECTION INPUT ;
		SHAPE ABUTMENT ;
		PORT
			 LAYER M2 ;
			RECT 0.0098 14.3435 0.0481 14.3812 ;
		END

		ANTENNAGATEAREA 0.00027817 ;
		ANTENNADIFFAREA 0.00194719 ;
		ANTENNAPARTIALMETALAREA 0.00195671 ;
	END DB[17]

	PIN DB[18]
		USE SIGNAL ;
		DIRECTION INPUT ;
		SHAPE ABUTMENT ;
		PORT
			 LAYER M2 ;
			RECT 0.0098 15.1341 0.0481 15.1718 ;
		END

		ANTENNAGATEAREA 0.00027817 ;
		ANTENNADIFFAREA 0.00194719 ;
		ANTENNAPARTIALMETALAREA 0.00195671 ;
	END DB[18]

	PIN DB[19]
		USE SIGNAL ;
		DIRECTION INPUT ;
		SHAPE ABUTMENT ;
		PORT
			 LAYER M2 ;
			RECT 0.0098 15.9247 0.0481 15.9624 ;
		END

		ANTENNAGATEAREA 0.00027817 ;
		ANTENNADIFFAREA 0.00194719 ;
		ANTENNAPARTIALMETALAREA 0.00195671 ;
	END DB[19]

	PIN DB[1]
		USE SIGNAL ;
		DIRECTION INPUT ;
		SHAPE ABUTMENT ;
		PORT
			 LAYER M2 ;
			RECT 0.0098 1.6941 0.0481 1.7318 ;
		END

		ANTENNAGATEAREA 0.00027817 ;
		ANTENNADIFFAREA 0.00194719 ;
		ANTENNAPARTIALMETALAREA 0.00195671 ;
	END DB[1]

	PIN DB[20]
		USE SIGNAL ;
		DIRECTION INPUT ;
		SHAPE ABUTMENT ;
		PORT
			 LAYER M2 ;
			RECT 0.0098 16.7153 0.0481 16.7529 ;
		END

		ANTENNAGATEAREA 0.00027817 ;
		ANTENNADIFFAREA 0.00194719 ;
		ANTENNAPARTIALMETALAREA 0.00195671 ;
	END DB[20]

	PIN DB[21]
		USE SIGNAL ;
		DIRECTION INPUT ;
		SHAPE ABUTMENT ;
		PORT
			 LAYER M2 ;
			RECT 0.0098 17.5059 0.0481 17.5435 ;
		END

		ANTENNAGATEAREA 0.00027817 ;
		ANTENNADIFFAREA 0.00194719 ;
		ANTENNAPARTIALMETALAREA 0.00195671 ;
	END DB[21]

	PIN DB[22]
		USE SIGNAL ;
		DIRECTION INPUT ;
		SHAPE ABUTMENT ;
		PORT
			 LAYER M2 ;
			RECT 0.0098 18.2965 0.0481 18.3341 ;
		END

		ANTENNAGATEAREA 0.00027817 ;
		ANTENNADIFFAREA 0.00194719 ;
		ANTENNAPARTIALMETALAREA 0.00195671 ;
	END DB[22]

	PIN DB[23]
		USE SIGNAL ;
		DIRECTION INPUT ;
		SHAPE ABUTMENT ;
		PORT
			 LAYER M2 ;
			RECT 0.0098 19.0871 0.0481 19.1247 ;
		END

		ANTENNAGATEAREA 0.00027817 ;
		ANTENNADIFFAREA 0.00194719 ;
		ANTENNAPARTIALMETALAREA 0.00195671 ;
	END DB[23]

	PIN DB[24]
		USE SIGNAL ;
		DIRECTION INPUT ;
		SHAPE ABUTMENT ;
		PORT
			 LAYER M2 ;
			RECT 0.0098 19.8776 0.0481 19.9153 ;
		END

		ANTENNAGATEAREA 0.00027817 ;
		ANTENNADIFFAREA 0.00194719 ;
		ANTENNAPARTIALMETALAREA 0.00195671 ;
	END DB[24]

	PIN DB[25]
		USE SIGNAL ;
		DIRECTION INPUT ;
		SHAPE ABUTMENT ;
		PORT
			 LAYER M2 ;
			RECT 0.0098 20.6682 0.0481 20.7059 ;
		END

		ANTENNAGATEAREA 0.00027817 ;
		ANTENNADIFFAREA 0.00194719 ;
		ANTENNAPARTIALMETALAREA 0.00195671 ;
	END DB[25]

	PIN DB[26]
		USE SIGNAL ;
		DIRECTION INPUT ;
		SHAPE ABUTMENT ;
		PORT
			 LAYER M2 ;
			RECT 0.0098 21.4588 0.0481 21.4965 ;
		END

		ANTENNAGATEAREA 0.00027817 ;
		ANTENNADIFFAREA 0.00194719 ;
		ANTENNAPARTIALMETALAREA 0.00195671 ;
	END DB[26]

	PIN DB[27]
		USE SIGNAL ;
		DIRECTION INPUT ;
		SHAPE ABUTMENT ;
		PORT
			 LAYER M2 ;
			RECT 0.0098 22.2494 0.0481 22.2871 ;
		END

		ANTENNAGATEAREA 0.00027817 ;
		ANTENNADIFFAREA 0.00194719 ;
		ANTENNAPARTIALMETALAREA 0.00195671 ;
	END DB[27]

	PIN DB[28]
		USE SIGNAL ;
		DIRECTION INPUT ;
		SHAPE ABUTMENT ;
		PORT
			 LAYER M2 ;
			RECT 0.0098 23.04 0.0481 23.0776 ;
		END

		ANTENNAGATEAREA 0.00027817 ;
		ANTENNADIFFAREA 0.00194719 ;
		ANTENNAPARTIALMETALAREA 0.00195671 ;
	END DB[28]

	PIN DB[29]
		USE SIGNAL ;
		DIRECTION INPUT ;
		SHAPE ABUTMENT ;
		PORT
			 LAYER M2 ;
			RECT 0.0098 23.8306 0.0481 23.8682 ;
		END

		ANTENNAGATEAREA 0.00027817 ;
		ANTENNADIFFAREA 0.00194719 ;
		ANTENNAPARTIALMETALAREA 0.00195671 ;
	END DB[29]

	PIN DB[2]
		USE SIGNAL ;
		DIRECTION INPUT ;
		SHAPE ABUTMENT ;
		PORT
			 LAYER M2 ;
			RECT 0.0098 2.4847 0.0481 2.5224 ;
		END

		ANTENNAGATEAREA 0.00027817 ;
		ANTENNADIFFAREA 0.00194719 ;
		ANTENNAPARTIALMETALAREA 0.00195671 ;
	END DB[2]

	PIN DB[30]
		USE SIGNAL ;
		DIRECTION INPUT ;
		SHAPE ABUTMENT ;
		PORT
			 LAYER M2 ;
			RECT 0.0098 24.6212 0.0481 24.6588 ;
		END

		ANTENNAGATEAREA 0.00027817 ;
		ANTENNADIFFAREA 0.00194719 ;
		ANTENNAPARTIALMETALAREA 0.00195671 ;
	END DB[30]

	PIN DB[31]
		USE SIGNAL ;
		DIRECTION INPUT ;
		SHAPE ABUTMENT ;
		PORT
			 LAYER M2 ;
			RECT 0.0098 25.4118 0.0481 25.4494 ;
		END

		ANTENNAGATEAREA 0.00027817 ;
		ANTENNADIFFAREA 0.00194719 ;
		ANTENNAPARTIALMETALAREA 0.00195671 ;
	END DB[31]

	PIN DB[32]
		USE SIGNAL ;
		DIRECTION INPUT ;
		SHAPE ABUTMENT ;
		PORT
			 LAYER M2 ;
			RECT 0.0098 26.2024 0.0481 26.24 ;
		END

		ANTENNAGATEAREA 0.00027817 ;
		ANTENNADIFFAREA 0.00194719 ;
		ANTENNAPARTIALMETALAREA 0.00195671 ;
	END DB[32]

	PIN DB[33]
		USE SIGNAL ;
		DIRECTION INPUT ;
		SHAPE ABUTMENT ;
		PORT
			 LAYER M2 ;
			RECT 0.0098 35.4071 0.0481 35.4447 ;
		END

		ANTENNAGATEAREA 0.00027817 ;
		ANTENNADIFFAREA 0.00194719 ;
		ANTENNAPARTIALMETALAREA 0.00195671 ;
	END DB[33]

	PIN DB[34]
		USE SIGNAL ;
		DIRECTION INPUT ;
		SHAPE ABUTMENT ;
		PORT
			 LAYER M2 ;
			RECT 0.0098 36.1976 0.0481 36.2353 ;
		END

		ANTENNAGATEAREA 0.00027817 ;
		ANTENNADIFFAREA 0.00194719 ;
		ANTENNAPARTIALMETALAREA 0.00195671 ;
	END DB[34]

	PIN DB[35]
		USE SIGNAL ;
		DIRECTION INPUT ;
		SHAPE ABUTMENT ;
		PORT
			 LAYER M2 ;
			RECT 0.0098 36.9882 0.0481 37.0259 ;
		END

		ANTENNAGATEAREA 0.00027817 ;
		ANTENNADIFFAREA 0.00194719 ;
		ANTENNAPARTIALMETALAREA 0.00195671 ;
	END DB[35]

	PIN DB[36]
		USE SIGNAL ;
		DIRECTION INPUT ;
		SHAPE ABUTMENT ;
		PORT
			 LAYER M2 ;
			RECT 0.0098 37.7788 0.0481 37.8165 ;
		END

		ANTENNAGATEAREA 0.00027817 ;
		ANTENNADIFFAREA 0.00194719 ;
		ANTENNAPARTIALMETALAREA 0.00195671 ;
	END DB[36]

	PIN DB[37]
		USE SIGNAL ;
		DIRECTION INPUT ;
		SHAPE ABUTMENT ;
		PORT
			 LAYER M2 ;
			RECT 0.0098 38.5694 0.0481 38.6071 ;
		END

		ANTENNAGATEAREA 0.00027817 ;
		ANTENNADIFFAREA 0.00194719 ;
		ANTENNAPARTIALMETALAREA 0.00195671 ;
	END DB[37]

	PIN DB[38]
		USE SIGNAL ;
		DIRECTION INPUT ;
		SHAPE ABUTMENT ;
		PORT
			 LAYER M2 ;
			RECT 0.0098 39.36 0.0481 39.3976 ;
		END

		ANTENNAGATEAREA 0.00027817 ;
		ANTENNADIFFAREA 0.00194719 ;
		ANTENNAPARTIALMETALAREA 0.00195671 ;
	END DB[38]

	PIN DB[39]
		USE SIGNAL ;
		DIRECTION INPUT ;
		SHAPE ABUTMENT ;
		PORT
			 LAYER M2 ;
			RECT 0.0098 40.1506 0.0481 40.1882 ;
		END

		ANTENNAGATEAREA 0.00027817 ;
		ANTENNADIFFAREA 0.00194719 ;
		ANTENNAPARTIALMETALAREA 0.00195671 ;
	END DB[39]

	PIN DB[3]
		USE SIGNAL ;
		DIRECTION INPUT ;
		SHAPE ABUTMENT ;
		PORT
			 LAYER M2 ;
			RECT 0.0098 3.2753 0.0481 3.3129 ;
		END

		ANTENNAGATEAREA 0.00027817 ;
		ANTENNADIFFAREA 0.00194719 ;
		ANTENNAPARTIALMETALAREA 0.00195671 ;
	END DB[3]

	PIN DB[40]
		USE SIGNAL ;
		DIRECTION INPUT ;
		SHAPE ABUTMENT ;
		PORT
			 LAYER M2 ;
			RECT 0.0098 40.9412 0.0481 40.9788 ;
		END

		ANTENNAGATEAREA 0.00027817 ;
		ANTENNADIFFAREA 0.00194719 ;
		ANTENNAPARTIALMETALAREA 0.00195671 ;
	END DB[40]

	PIN DB[41]
		USE SIGNAL ;
		DIRECTION INPUT ;
		SHAPE ABUTMENT ;
		PORT
			 LAYER M2 ;
			RECT 0.0098 41.7318 0.0481 41.7694 ;
		END

		ANTENNAGATEAREA 0.00027817 ;
		ANTENNADIFFAREA 0.00194719 ;
		ANTENNAPARTIALMETALAREA 0.00195671 ;
	END DB[41]

	PIN DB[42]
		USE SIGNAL ;
		DIRECTION INPUT ;
		SHAPE ABUTMENT ;
		PORT
			 LAYER M2 ;
			RECT 0.0098 42.5224 0.0481 42.56 ;
		END

		ANTENNAGATEAREA 0.00027817 ;
		ANTENNADIFFAREA 0.00194719 ;
		ANTENNAPARTIALMETALAREA 0.00195671 ;
	END DB[42]

	PIN DB[43]
		USE SIGNAL ;
		DIRECTION INPUT ;
		SHAPE ABUTMENT ;
		PORT
			 LAYER M2 ;
			RECT 0.0098 43.3129 0.0481 43.3506 ;
		END

		ANTENNAGATEAREA 0.00027817 ;
		ANTENNADIFFAREA 0.00194719 ;
		ANTENNAPARTIALMETALAREA 0.00195671 ;
	END DB[43]

	PIN DB[44]
		USE SIGNAL ;
		DIRECTION INPUT ;
		SHAPE ABUTMENT ;
		PORT
			 LAYER M2 ;
			RECT 0.0098 44.1035 0.0481 44.1412 ;
		END

		ANTENNAGATEAREA 0.00027817 ;
		ANTENNADIFFAREA 0.00194719 ;
		ANTENNAPARTIALMETALAREA 0.00195671 ;
	END DB[44]

	PIN DB[45]
		USE SIGNAL ;
		DIRECTION INPUT ;
		SHAPE ABUTMENT ;
		PORT
			 LAYER M2 ;
			RECT 0.0098 44.8941 0.0481 44.9318 ;
		END

		ANTENNAGATEAREA 0.00027817 ;
		ANTENNADIFFAREA 0.00194719 ;
		ANTENNAPARTIALMETALAREA 0.00195671 ;
	END DB[45]

	PIN DB[46]
		USE SIGNAL ;
		DIRECTION INPUT ;
		SHAPE ABUTMENT ;
		PORT
			 LAYER M2 ;
			RECT 0.0098 45.6847 0.0481 45.7224 ;
		END

		ANTENNAGATEAREA 0.00027817 ;
		ANTENNADIFFAREA 0.00194719 ;
		ANTENNAPARTIALMETALAREA 0.00195671 ;
	END DB[46]

	PIN DB[47]
		USE SIGNAL ;
		DIRECTION INPUT ;
		SHAPE ABUTMENT ;
		PORT
			 LAYER M2 ;
			RECT 0.0098 46.4753 0.0481 46.5129 ;
		END

		ANTENNAGATEAREA 0.00027817 ;
		ANTENNADIFFAREA 0.00194719 ;
		ANTENNAPARTIALMETALAREA 0.00195671 ;
	END DB[47]

	PIN DB[48]
		USE SIGNAL ;
		DIRECTION INPUT ;
		SHAPE ABUTMENT ;
		PORT
			 LAYER M2 ;
			RECT 0.0098 47.2659 0.0481 47.3035 ;
		END

		ANTENNAGATEAREA 0.00027817 ;
		ANTENNADIFFAREA 0.00194719 ;
		ANTENNAPARTIALMETALAREA 0.00195671 ;
	END DB[48]

	PIN DB[49]
		USE SIGNAL ;
		DIRECTION INPUT ;
		SHAPE ABUTMENT ;
		PORT
			 LAYER M2 ;
			RECT 0.0098 48.0565 0.0481 48.0941 ;
		END

		ANTENNAGATEAREA 0.00027817 ;
		ANTENNADIFFAREA 0.00194719 ;
		ANTENNAPARTIALMETALAREA 0.00195671 ;
	END DB[49]

	PIN DB[4]
		USE SIGNAL ;
		DIRECTION INPUT ;
		SHAPE ABUTMENT ;
		PORT
			 LAYER M2 ;
			RECT 0.0098 4.0659 0.0481 4.1035 ;
		END

		ANTENNAGATEAREA 0.00027817 ;
		ANTENNADIFFAREA 0.00194719 ;
		ANTENNAPARTIALMETALAREA 0.00195671 ;
	END DB[4]

	PIN DB[50]
		USE SIGNAL ;
		DIRECTION INPUT ;
		SHAPE ABUTMENT ;
		PORT
			 LAYER M2 ;
			RECT 0.0098 48.8471 0.0481 48.8847 ;
		END

		ANTENNAGATEAREA 0.00027817 ;
		ANTENNADIFFAREA 0.00194719 ;
		ANTENNAPARTIALMETALAREA 0.00195671 ;
	END DB[50]

	PIN DB[51]
		USE SIGNAL ;
		DIRECTION INPUT ;
		SHAPE ABUTMENT ;
		PORT
			 LAYER M2 ;
			RECT 0.0098 49.6376 0.0481 49.6753 ;
		END

		ANTENNAGATEAREA 0.00027817 ;
		ANTENNADIFFAREA 0.00194719 ;
		ANTENNAPARTIALMETALAREA 0.00195671 ;
	END DB[51]

	PIN DB[52]
		USE SIGNAL ;
		DIRECTION INPUT ;
		SHAPE ABUTMENT ;
		PORT
			 LAYER M2 ;
			RECT 0.0098 50.4282 0.0481 50.4659 ;
		END

		ANTENNAGATEAREA 0.00027817 ;
		ANTENNADIFFAREA 0.00194719 ;
		ANTENNAPARTIALMETALAREA 0.00195671 ;
	END DB[52]

	PIN DB[53]
		USE SIGNAL ;
		DIRECTION INPUT ;
		SHAPE ABUTMENT ;
		PORT
			 LAYER M2 ;
			RECT 0.0098 51.2188 0.0481 51.2565 ;
		END

		ANTENNAGATEAREA 0.00027817 ;
		ANTENNADIFFAREA 0.00194719 ;
		ANTENNAPARTIALMETALAREA 0.00195671 ;
	END DB[53]

	PIN DB[54]
		USE SIGNAL ;
		DIRECTION INPUT ;
		SHAPE ABUTMENT ;
		PORT
			 LAYER M2 ;
			RECT 0.0098 52.0094 0.0481 52.0471 ;
		END

		ANTENNAGATEAREA 0.00027817 ;
		ANTENNADIFFAREA 0.00194719 ;
		ANTENNAPARTIALMETALAREA 0.00195671 ;
	END DB[54]

	PIN DB[55]
		USE SIGNAL ;
		DIRECTION INPUT ;
		SHAPE ABUTMENT ;
		PORT
			 LAYER M2 ;
			RECT 0.0098 52.8 0.0481 52.8376 ;
		END

		ANTENNAGATEAREA 0.00027817 ;
		ANTENNADIFFAREA 0.00194719 ;
		ANTENNAPARTIALMETALAREA 0.00195671 ;
	END DB[55]

	PIN DB[56]
		USE SIGNAL ;
		DIRECTION INPUT ;
		SHAPE ABUTMENT ;
		PORT
			 LAYER M2 ;
			RECT 0.0098 53.5906 0.0481 53.6282 ;
		END

		ANTENNAGATEAREA 0.00027817 ;
		ANTENNADIFFAREA 0.00194719 ;
		ANTENNAPARTIALMETALAREA 0.00195671 ;
	END DB[56]

	PIN DB[57]
		USE SIGNAL ;
		DIRECTION INPUT ;
		SHAPE ABUTMENT ;
		PORT
			 LAYER M2 ;
			RECT 0.0098 54.3812 0.0481 54.4188 ;
		END

		ANTENNAGATEAREA 0.00027817 ;
		ANTENNADIFFAREA 0.00194719 ;
		ANTENNAPARTIALMETALAREA 0.00195671 ;
	END DB[57]

	PIN DB[58]
		USE SIGNAL ;
		DIRECTION INPUT ;
		SHAPE ABUTMENT ;
		PORT
			 LAYER M2 ;
			RECT 0.0098 55.1718 0.0481 55.2094 ;
		END

		ANTENNAGATEAREA 0.00027817 ;
		ANTENNADIFFAREA 0.00194719 ;
		ANTENNAPARTIALMETALAREA 0.00195671 ;
	END DB[58]

	PIN DB[59]
		USE SIGNAL ;
		DIRECTION INPUT ;
		SHAPE ABUTMENT ;
		PORT
			 LAYER M2 ;
			RECT 0.0098 55.9624 0.0481 56 ;
		END

		ANTENNAGATEAREA 0.00027817 ;
		ANTENNADIFFAREA 0.00194719 ;
		ANTENNAPARTIALMETALAREA 0.00195671 ;
	END DB[59]

	PIN DB[5]
		USE SIGNAL ;
		DIRECTION INPUT ;
		SHAPE ABUTMENT ;
		PORT
			 LAYER M2 ;
			RECT 0.0098 4.8565 0.0481 4.8941 ;
		END

		ANTENNAGATEAREA 0.00027817 ;
		ANTENNADIFFAREA 0.00194719 ;
		ANTENNAPARTIALMETALAREA 0.00195671 ;
	END DB[5]

	PIN DB[60]
		USE SIGNAL ;
		DIRECTION INPUT ;
		SHAPE ABUTMENT ;
		PORT
			 LAYER M2 ;
			RECT 0.0098 56.7529 0.0481 56.7906 ;
		END

		ANTENNAGATEAREA 0.00027817 ;
		ANTENNADIFFAREA 0.00194719 ;
		ANTENNAPARTIALMETALAREA 0.00195671 ;
	END DB[60]

	PIN DB[61]
		USE SIGNAL ;
		DIRECTION INPUT ;
		SHAPE ABUTMENT ;
		PORT
			 LAYER M2 ;
			RECT 0.0098 57.5435 0.0481 57.5812 ;
		END

		ANTENNAGATEAREA 0.00027817 ;
		ANTENNADIFFAREA 0.00194719 ;
		ANTENNAPARTIALMETALAREA 0.00195671 ;
	END DB[61]

	PIN DB[62]
		USE SIGNAL ;
		DIRECTION INPUT ;
		SHAPE ABUTMENT ;
		PORT
			 LAYER M2 ;
			RECT 0.0098 58.3341 0.0481 58.3718 ;
		END

		ANTENNAGATEAREA 0.00027817 ;
		ANTENNADIFFAREA 0.00194719 ;
		ANTENNAPARTIALMETALAREA 0.00195671 ;
	END DB[62]

	PIN DB[63]
		USE SIGNAL ;
		DIRECTION INPUT ;
		SHAPE ABUTMENT ;
		PORT
			 LAYER M2 ;
			RECT 0.0098 59.1247 0.0481 59.1624 ;
		END

		ANTENNAGATEAREA 0.00027817 ;
		ANTENNADIFFAREA 0.00194719 ;
		ANTENNAPARTIALMETALAREA 0.00195671 ;
	END DB[63]

	PIN DB[64]
		USE SIGNAL ;
		DIRECTION INPUT ;
		SHAPE ABUTMENT ;
		PORT
			 LAYER M2 ;
			RECT 0.0098 59.9153 0.0481 59.9529 ;
		END

		ANTENNAGATEAREA 0.00027817 ;
		ANTENNADIFFAREA 0.00194719 ;
		ANTENNAPARTIALMETALAREA 0.00195671 ;
	END DB[64]

	PIN DB[65]
		USE SIGNAL ;
		DIRECTION INPUT ;
		SHAPE ABUTMENT ;
		PORT
			 LAYER M2 ;
			RECT 0.0098 60.7059 0.0481 60.7435 ;
		END

		ANTENNAGATEAREA 0.00027817 ;
		ANTENNADIFFAREA 0.00194719 ;
		ANTENNAPARTIALMETALAREA 0.00195671 ;
	END DB[65]

	PIN DB[6]
		USE SIGNAL ;
		DIRECTION INPUT ;
		SHAPE ABUTMENT ;
		PORT
			 LAYER M2 ;
			RECT 0.0098 5.6471 0.0481 5.6847 ;
		END

		ANTENNAGATEAREA 0.00027817 ;
		ANTENNADIFFAREA 0.00194719 ;
		ANTENNAPARTIALMETALAREA 0.00195671 ;
	END DB[6]

	PIN DB[7]
		USE SIGNAL ;
		DIRECTION INPUT ;
		SHAPE ABUTMENT ;
		PORT
			 LAYER M2 ;
			RECT 0.0098 6.4376 0.0481 6.4753 ;
		END

		ANTENNAGATEAREA 0.00027817 ;
		ANTENNADIFFAREA 0.00194719 ;
		ANTENNAPARTIALMETALAREA 0.00195671 ;
	END DB[7]

	PIN DB[8]
		USE SIGNAL ;
		DIRECTION INPUT ;
		SHAPE ABUTMENT ;
		PORT
			 LAYER M2 ;
			RECT 0.0098 7.2282 0.0481 7.2659 ;
		END

		ANTENNAGATEAREA 0.00027817 ;
		ANTENNADIFFAREA 0.00194719 ;
		ANTENNAPARTIALMETALAREA 0.00195671 ;
	END DB[8]

	PIN DB[9]
		USE SIGNAL ;
		DIRECTION INPUT ;
		SHAPE ABUTMENT ;
		PORT
			 LAYER M2 ;
			RECT 0.0098 8.0188 0.0481 8.0565 ;
		END

		ANTENNAGATEAREA 0.00027817 ;
		ANTENNADIFFAREA 0.00194719 ;
		ANTENNAPARTIALMETALAREA 0.00195671 ;
	END DB[9]

	PIN DFTRAMBYP
		USE SIGNAL ;
		DIRECTION INPUT ;
		SHAPE ABUTMENT ;
		PORT
			 LAYER M2 ;
			RECT 0.0098 28.6243 0.0481 28.662 ;
		END

		ANTENNAGATEAREA 0.00027817 ;
		ANTENNADIFFAREA 0.00194719 ;
		ANTENNAPARTIALMETALAREA 0.00195671 ;
	END DFTRAMBYP

	PIN EMAP
		USE SIGNAL ;
		DIRECTION INPUT ;
		SHAPE ABUTMENT ;
		PORT
			 LAYER M2 ;
			RECT 0.0098 29.5027 0.0481 29.5404 ;
		END

		ANTENNAGATEAREA 0.00027817 ;
		ANTENNADIFFAREA 0.00194719 ;
		ANTENNAPARTIALMETALAREA 0.00195671 ;
	END EMAP

	PIN EMAS
		USE SIGNAL ;
		DIRECTION INPUT ;
		SHAPE ABUTMENT ;
		PORT
			 LAYER M3 ;
			RECT 0.0714 28.2227 0.1097 28.3231 ;
		END

		ANTENNAGATEAREA 0.00027817 ;
		ANTENNADIFFAREA 0.00194719 ;
		ANTENNAPARTIALMETALAREA 0.00195671 ;
	END EMAS

	PIN EMAW[0]
		USE SIGNAL ;
		DIRECTION INPUT ;
		SHAPE ABUTMENT ;
		PORT
			 LAYER M2 ;
			RECT 0.0098 28.2855 0.0481 28.3231 ;
		END

		ANTENNAGATEAREA 0.00027817 ;
		ANTENNADIFFAREA 0.00194719 ;
		ANTENNAPARTIALMETALAREA 0.00195671 ;
	END EMAW[0]

	PIN EMAW[1]
		USE SIGNAL ;
		DIRECTION INPUT ;
		SHAPE ABUTMENT ;
		PORT
			 LAYER M2 ;
			RECT 0.0098 28.2227 0.0481 28.2604 ;
		END

		ANTENNAGATEAREA 0.00027817 ;
		ANTENNADIFFAREA 0.00194719 ;
		ANTENNAPARTIALMETALAREA 0.00195671 ;
	END EMAW[1]

	PIN EMA[0]
		USE SIGNAL ;
		DIRECTION INPUT ;
		SHAPE ABUTMENT ;
		PORT
			 LAYER M2 ;
			RECT 0.0098 28.0722 0.0481 28.1098 ;
		END

		ANTENNAGATEAREA 0.00027817 ;
		ANTENNADIFFAREA 0.00194719 ;
		ANTENNAPARTIALMETALAREA 0.00195671 ;
	END EMA[0]

	PIN EMA[1]
		USE SIGNAL ;
		DIRECTION INPUT ;
		SHAPE ABUTMENT ;
		PORT
			 LAYER M2 ;
			RECT 0.0098 28.1349 0.0481 28.1725 ;
		END

		ANTENNAGATEAREA 0.00027817 ;
		ANTENNADIFFAREA 0.00194719 ;
		ANTENNAPARTIALMETALAREA 0.00195671 ;
	END EMA[1]

	PIN EMA[2]
		USE SIGNAL ;
		DIRECTION INPUT ;
		SHAPE ABUTMENT ;
		PORT
			 LAYER M3 ;
			RECT 0.0714 29.0761 0.1097 29.1765 ;
		END

		ANTENNAGATEAREA 0.00027817 ;
		ANTENNADIFFAREA 0.00194719 ;
		ANTENNAPARTIALMETALAREA 0.00195671 ;
	END EMA[2]

	PIN FCA1[0]
		USE SIGNAL ;
		DIRECTION INPUT ;
		SHAPE ABUTMENT ;
		PORT
			 LAYER M2 ;
			RECT 0.0098 31.6235 0.0481 31.6612 ;
		END

		ANTENNAGATEAREA 0.00027817 ;
		ANTENNADIFFAREA 0.00194719 ;
		ANTENNAPARTIALMETALAREA 0.00195671 ;
	END FCA1[0]

	PIN FCA1[1]
		USE SIGNAL ;
		DIRECTION INPUT ;
		SHAPE ABUTMENT ;
		PORT
			 LAYER M2 ;
			RECT 0.0098 27.3192 0.0481 27.4196 ;
			 LAYER M3 ;
			RECT 0.0098 27.3192 0.0481 27.4196 ;
			 LAYER V2 ;
			RECT 0.021 27.3941 0.0359 27.4067 ;
		END

		ANTENNAGATEAREA 0.00027817 ;
		ANTENNADIFFAREA 0.00194719 ;
		ANTENNAPARTIALMETALAREA 0.00195671 ;
	END FCA1[1]

	PIN FCA1[2]
		USE SIGNAL ;
		DIRECTION INPUT ;
		SHAPE ABUTMENT ;
		PORT
			 LAYER M2 ;
			RECT 0.0098 27.6831 0.0481 27.7208 ;
		END

		ANTENNAGATEAREA 0.00027817 ;
		ANTENNADIFFAREA 0.00194719 ;
		ANTENNAPARTIALMETALAREA 0.00195671 ;
	END FCA1[2]

	PIN FCA1[3]
		USE SIGNAL ;
		DIRECTION INPUT ;
		SHAPE ABUTMENT ;
		PORT
			 LAYER M3 ;
			RECT 0.0714 29.2267 0.1097 29.3271 ;
		END

		ANTENNAGATEAREA 0.00027817 ;
		ANTENNADIFFAREA 0.00194719 ;
		ANTENNAPARTIALMETALAREA 0.00195671 ;
	END FCA1[3]

	PIN FCA1[4]
		USE SIGNAL ;
		DIRECTION INPUT ;
		SHAPE ABUTMENT ;
		PORT
			 LAYER M2 ;
			RECT 0.0098 29.6533 0.0481 29.691 ;
		END

		ANTENNAGATEAREA 0.00027817 ;
		ANTENNADIFFAREA 0.00194719 ;
		ANTENNAPARTIALMETALAREA 0.00195671 ;
	END FCA1[4]

	PIN FCA1[5]
		USE SIGNAL ;
		DIRECTION INPUT ;
		SHAPE ABUTMENT ;
		PORT
			 LAYER M2 ;
			RECT 0.0098 27.4698 0.0481 27.5702 ;
			 LAYER M3 ;
			RECT 0.0098 27.4698 0.0481 27.5702 ;
			 LAYER V2 ;
			RECT 0.021 27.5447 0.0359 27.5573 ;
		END

		ANTENNAGATEAREA 0.00027817 ;
		ANTENNADIFFAREA 0.00194719 ;
		ANTENNAPARTIALMETALAREA 0.00195671 ;
	END FCA1[5]

	PIN FCA2[0]
		USE SIGNAL ;
		DIRECTION INPUT ;
		SHAPE ABUTMENT ;
		PORT
			 LAYER M3 ;
			RECT 0.0714 29.5027 0.1097 29.6031 ;
		END

		ANTENNAGATEAREA 0.00027817 ;
		ANTENNADIFFAREA 0.00194719 ;
		ANTENNAPARTIALMETALAREA 0.00195671 ;
	END FCA2[0]

	PIN FCA2[1]
		USE SIGNAL ;
		DIRECTION INPUT ;
		SHAPE ABUTMENT ;
		PORT
			 LAYER M2 ;
			RECT 0.0098 34.4345 0.0481 34.4722 ;
		END

		ANTENNAGATEAREA 0.00027817 ;
		ANTENNADIFFAREA 0.00194719 ;
		ANTENNAPARTIALMETALAREA 0.00195671 ;
	END FCA2[1]

	PIN FCA2[2]
		USE SIGNAL ;
		DIRECTION INPUT ;
		SHAPE ABUTMENT ;
		PORT
			 LAYER M2 ;
			RECT 0.0098 27.6204 0.0481 27.658 ;
		END

		ANTENNAGATEAREA 0.00027817 ;
		ANTENNADIFFAREA 0.00194719 ;
		ANTENNAPARTIALMETALAREA 0.00195671 ;
	END FCA2[2]

	PIN FCA2[3]
		USE SIGNAL ;
		DIRECTION INPUT ;
		SHAPE ABUTMENT ;
		PORT
			 LAYER M3 ;
			RECT 0.0714 34.0706 0.1097 34.171 ;
		END

		ANTENNAGATEAREA 0.00027817 ;
		ANTENNADIFFAREA 0.00194719 ;
		ANTENNAPARTIALMETALAREA 0.00195671 ;
	END FCA2[3]

	PIN FCA2[4]
		USE SIGNAL ;
		DIRECTION INPUT ;
		SHAPE ABUTMENT ;
		PORT
			 LAYER M2 ;
			RECT 0.0098 34.0706 0.0481 34.1082 ;
		END

		ANTENNAGATEAREA 0.00027817 ;
		ANTENNADIFFAREA 0.00194719 ;
		ANTENNAPARTIALMETALAREA 0.00195671 ;
	END FCA2[4]

	PIN FCA2[5]
		USE SIGNAL ;
		DIRECTION INPUT ;
		SHAPE ABUTMENT ;
		PORT
			 LAYER M2 ;
			RECT 0.0098 34.2839 0.0481 34.3216 ;
		END

		ANTENNAGATEAREA 0.00027817 ;
		ANTENNADIFFAREA 0.00194719 ;
		ANTENNAPARTIALMETALAREA 0.00195671 ;
	END FCA2[5]

	PIN GWENA
		USE SIGNAL ;
		DIRECTION INPUT ;
		SHAPE ABUTMENT ;
		PORT
			 LAYER M2 ;
			RECT 0.0098 28.4361 0.0481 28.4737 ;
			 LAYER M3 ;
			RECT 0.0098 28.3733 0.0481 28.4737 ;
			 LAYER V2 ;
			RECT 0.0215 28.4482 0.0364 28.4608 ;
		END

		ANTENNAGATEAREA 0.00027817 ;
		ANTENNADIFFAREA 0.00194719 ;
		ANTENNAPARTIALMETALAREA 0.00195671 ;
	END GWENA

	PIN GWENB
		USE SIGNAL ;
		DIRECTION INPUT ;
		SHAPE ABUTMENT ;
		PORT
			 LAYER M2 ;
			RECT 0.0098 28.7498 0.0481 28.7875 ;
			 LAYER M3 ;
			RECT 0.0098 28.7498 0.0481 28.8502 ;
			 LAYER V2 ;
			RECT 0.0215 28.7627 0.0364 28.7753 ;
		END

		ANTENNAGATEAREA 0.00027817 ;
		ANTENNADIFFAREA 0.00194719 ;
		ANTENNAPARTIALMETALAREA 0.00195671 ;
	END GWENB

	PIN GWENYA
		USE SIGNAL ;
		DIRECTION OUTPUT ;
		SHAPE ABUTMENT ;
		PORT
			 LAYER M2 ;
			RECT 0.0098 28.5616 0.0481 28.5992 ;
			 LAYER M3 ;
			RECT 0.0098 28.4988 0.0481 28.5992 ;
			 LAYER V2 ;
			RECT 0.0215 28.5737 0.0364 28.5863 ;
		END

		ANTENNADIFFAREA 0.00194719 ;
		ANTENNAPARTIALMETALAREA 0.00195671 ;
	END GWENYA

	PIN GWENYB
		USE SIGNAL ;
		DIRECTION OUTPUT ;
		SHAPE ABUTMENT ;
		PORT
			 LAYER M2 ;
			RECT 0.0714 28.8125 0.1097 28.8502 ;
			 LAYER M3 ;
			RECT 0.0714 28.7498 0.1097 28.8502 ;
			 LAYER V2 ;
			RECT 0.0831 28.8255 0.098 28.838 ;
		END

		ANTENNADIFFAREA 0.00194719 ;
		ANTENNAPARTIALMETALAREA 0.00195671 ;
	END GWENYB

	PIN QA[0]
		USE SIGNAL ;
		DIRECTION OUTPUT ;
		SHAPE ABUTMENT ;
		PORT
			 LAYER M2 ;
			RECT 0.0098 0.7278 0.0481 0.7655 ;
			 LAYER M3 ;
			RECT 0.0098 0.6651 0.0481 0.7655 ;
			 LAYER V2 ;
			RECT 0.0215 0.74 0.0364 0.7525 ;
		END

		ANTENNADIFFAREA 0.00194719 ;
		ANTENNAPARTIALMETALAREA 0.00195671 ;
	END QA[0]

	PIN QA[10]
		USE SIGNAL ;
		DIRECTION OUTPUT ;
		SHAPE ABUTMENT ;
		PORT
			 LAYER M2 ;
			RECT 0.0098 8.6337 0.0481 8.6714 ;
			 LAYER M3 ;
			RECT 0.0098 8.571 0.0481 8.6714 ;
			 LAYER V2 ;
			RECT 0.0215 8.6459 0.0364 8.6584 ;
		END

		ANTENNADIFFAREA 0.00194719 ;
		ANTENNAPARTIALMETALAREA 0.00195671 ;
	END QA[10]

	PIN QA[11]
		USE SIGNAL ;
		DIRECTION OUTPUT ;
		SHAPE ABUTMENT ;
		PORT
			 LAYER M2 ;
			RECT 0.0098 9.4243 0.0481 9.462 ;
			 LAYER M3 ;
			RECT 0.0098 9.3616 0.0481 9.462 ;
			 LAYER V2 ;
			RECT 0.0215 9.4365 0.0364 9.449 ;
		END

		ANTENNADIFFAREA 0.00194719 ;
		ANTENNAPARTIALMETALAREA 0.00195671 ;
	END QA[11]

	PIN QA[12]
		USE SIGNAL ;
		DIRECTION OUTPUT ;
		SHAPE ABUTMENT ;
		PORT
			 LAYER M2 ;
			RECT 0.0098 10.2149 0.0481 10.2525 ;
			 LAYER M3 ;
			RECT 0.0098 10.1522 0.0481 10.2525 ;
			 LAYER V2 ;
			RECT 0.0215 10.2271 0.0364 10.2396 ;
		END

		ANTENNADIFFAREA 0.00194719 ;
		ANTENNAPARTIALMETALAREA 0.00195671 ;
	END QA[12]

	PIN QA[13]
		USE SIGNAL ;
		DIRECTION OUTPUT ;
		SHAPE ABUTMENT ;
		PORT
			 LAYER M2 ;
			RECT 0.0098 11.0055 0.0481 11.0431 ;
			 LAYER M3 ;
			RECT 0.0098 10.9427 0.0481 11.0431 ;
			 LAYER V2 ;
			RECT 0.0215 11.0176 0.0364 11.0302 ;
		END

		ANTENNADIFFAREA 0.00194719 ;
		ANTENNAPARTIALMETALAREA 0.00195671 ;
	END QA[13]

	PIN QA[14]
		USE SIGNAL ;
		DIRECTION OUTPUT ;
		SHAPE ABUTMENT ;
		PORT
			 LAYER M2 ;
			RECT 0.0098 11.7961 0.0481 11.8337 ;
			 LAYER M3 ;
			RECT 0.0098 11.7333 0.0481 11.8337 ;
			 LAYER V2 ;
			RECT 0.0215 11.8082 0.0364 11.8208 ;
		END

		ANTENNADIFFAREA 0.00194719 ;
		ANTENNAPARTIALMETALAREA 0.00195671 ;
	END QA[14]

	PIN QA[15]
		USE SIGNAL ;
		DIRECTION OUTPUT ;
		SHAPE ABUTMENT ;
		PORT
			 LAYER M2 ;
			RECT 0.0098 12.5867 0.0481 12.6243 ;
			 LAYER M3 ;
			RECT 0.0098 12.5239 0.0481 12.6243 ;
			 LAYER V2 ;
			RECT 0.0215 12.5988 0.0364 12.6114 ;
		END

		ANTENNADIFFAREA 0.00194719 ;
		ANTENNAPARTIALMETALAREA 0.00195671 ;
	END QA[15]

	PIN QA[16]
		USE SIGNAL ;
		DIRECTION OUTPUT ;
		SHAPE ABUTMENT ;
		PORT
			 LAYER M2 ;
			RECT 0.0098 13.3773 0.0481 13.4149 ;
			 LAYER M3 ;
			RECT 0.0098 13.3145 0.0481 13.4149 ;
			 LAYER V2 ;
			RECT 0.0215 13.3894 0.0364 13.402 ;
		END

		ANTENNADIFFAREA 0.00194719 ;
		ANTENNAPARTIALMETALAREA 0.00195671 ;
	END QA[16]

	PIN QA[17]
		USE SIGNAL ;
		DIRECTION OUTPUT ;
		SHAPE ABUTMENT ;
		PORT
			 LAYER M2 ;
			RECT 0.0098 14.1678 0.0481 14.2055 ;
			 LAYER M3 ;
			RECT 0.0098 14.1051 0.0481 14.2055 ;
			 LAYER V2 ;
			RECT 0.0215 14.18 0.0364 14.1925 ;
		END

		ANTENNADIFFAREA 0.00194719 ;
		ANTENNAPARTIALMETALAREA 0.00195671 ;
	END QA[17]

	PIN QA[18]
		USE SIGNAL ;
		DIRECTION OUTPUT ;
		SHAPE ABUTMENT ;
		PORT
			 LAYER M2 ;
			RECT 0.0098 14.9584 0.0481 14.9961 ;
			 LAYER M3 ;
			RECT 0.0098 14.8957 0.0481 14.9961 ;
			 LAYER V2 ;
			RECT 0.0215 14.9706 0.0364 14.9831 ;
		END

		ANTENNADIFFAREA 0.00194719 ;
		ANTENNAPARTIALMETALAREA 0.00195671 ;
	END QA[18]

	PIN QA[19]
		USE SIGNAL ;
		DIRECTION OUTPUT ;
		SHAPE ABUTMENT ;
		PORT
			 LAYER M2 ;
			RECT 0.0098 15.749 0.0481 15.7867 ;
			 LAYER M3 ;
			RECT 0.0098 15.6863 0.0481 15.7867 ;
			 LAYER V2 ;
			RECT 0.0215 15.7612 0.0364 15.7737 ;
		END

		ANTENNADIFFAREA 0.00194719 ;
		ANTENNAPARTIALMETALAREA 0.00195671 ;
	END QA[19]

	PIN QA[1]
		USE SIGNAL ;
		DIRECTION OUTPUT ;
		SHAPE ABUTMENT ;
		PORT
			 LAYER M2 ;
			RECT 0.0098 1.5184 0.0481 1.5561 ;
			 LAYER M3 ;
			RECT 0.0098 1.4557 0.0481 1.5561 ;
			 LAYER V2 ;
			RECT 0.0215 1.5306 0.0364 1.5431 ;
		END

		ANTENNADIFFAREA 0.00194719 ;
		ANTENNAPARTIALMETALAREA 0.00195671 ;
	END QA[1]

	PIN QA[20]
		USE SIGNAL ;
		DIRECTION OUTPUT ;
		SHAPE ABUTMENT ;
		PORT
			 LAYER M2 ;
			RECT 0.0098 16.5396 0.0481 16.5773 ;
			 LAYER M3 ;
			RECT 0.0098 16.4769 0.0481 16.5773 ;
			 LAYER V2 ;
			RECT 0.0215 16.5518 0.0364 16.5643 ;
		END

		ANTENNADIFFAREA 0.00194719 ;
		ANTENNAPARTIALMETALAREA 0.00195671 ;
	END QA[20]

	PIN QA[21]
		USE SIGNAL ;
		DIRECTION OUTPUT ;
		SHAPE ABUTMENT ;
		PORT
			 LAYER M2 ;
			RECT 0.0098 17.3302 0.0481 17.3678 ;
			 LAYER M3 ;
			RECT 0.0098 17.2675 0.0481 17.3678 ;
			 LAYER V2 ;
			RECT 0.0215 17.3424 0.0364 17.3549 ;
		END

		ANTENNADIFFAREA 0.00194719 ;
		ANTENNAPARTIALMETALAREA 0.00195671 ;
	END QA[21]

	PIN QA[22]
		USE SIGNAL ;
		DIRECTION OUTPUT ;
		SHAPE ABUTMENT ;
		PORT
			 LAYER M2 ;
			RECT 0.0098 18.1208 0.0481 18.1584 ;
			 LAYER M3 ;
			RECT 0.0098 18.058 0.0481 18.1584 ;
			 LAYER V2 ;
			RECT 0.0215 18.1329 0.0364 18.1455 ;
		END

		ANTENNADIFFAREA 0.00194719 ;
		ANTENNAPARTIALMETALAREA 0.00195671 ;
	END QA[22]

	PIN QA[23]
		USE SIGNAL ;
		DIRECTION OUTPUT ;
		SHAPE ABUTMENT ;
		PORT
			 LAYER M2 ;
			RECT 0.0098 18.9114 0.0481 18.949 ;
			 LAYER M3 ;
			RECT 0.0098 18.8486 0.0481 18.949 ;
			 LAYER V2 ;
			RECT 0.0215 18.9235 0.0364 18.9361 ;
		END

		ANTENNADIFFAREA 0.00194719 ;
		ANTENNAPARTIALMETALAREA 0.00195671 ;
	END QA[23]

	PIN QA[24]
		USE SIGNAL ;
		DIRECTION OUTPUT ;
		SHAPE ABUTMENT ;
		PORT
			 LAYER M2 ;
			RECT 0.0098 19.702 0.0481 19.7396 ;
			 LAYER M3 ;
			RECT 0.0098 19.6392 0.0481 19.7396 ;
			 LAYER V2 ;
			RECT 0.0215 19.7141 0.0364 19.7267 ;
		END

		ANTENNADIFFAREA 0.00194719 ;
		ANTENNAPARTIALMETALAREA 0.00195671 ;
	END QA[24]

	PIN QA[25]
		USE SIGNAL ;
		DIRECTION OUTPUT ;
		SHAPE ABUTMENT ;
		PORT
			 LAYER M2 ;
			RECT 0.0098 20.4925 0.0481 20.5302 ;
			 LAYER M3 ;
			RECT 0.0098 20.4298 0.0481 20.5302 ;
			 LAYER V2 ;
			RECT 0.0215 20.5047 0.0364 20.5173 ;
		END

		ANTENNADIFFAREA 0.00194719 ;
		ANTENNAPARTIALMETALAREA 0.00195671 ;
	END QA[25]

	PIN QA[26]
		USE SIGNAL ;
		DIRECTION OUTPUT ;
		SHAPE ABUTMENT ;
		PORT
			 LAYER M2 ;
			RECT 0.0098 21.2831 0.0481 21.3208 ;
			 LAYER M3 ;
			RECT 0.0098 21.2204 0.0481 21.3208 ;
			 LAYER V2 ;
			RECT 0.0215 21.2953 0.0364 21.3078 ;
		END

		ANTENNADIFFAREA 0.00194719 ;
		ANTENNAPARTIALMETALAREA 0.00195671 ;
	END QA[26]

	PIN QA[27]
		USE SIGNAL ;
		DIRECTION OUTPUT ;
		SHAPE ABUTMENT ;
		PORT
			 LAYER M2 ;
			RECT 0.0098 22.0737 0.0481 22.1114 ;
			 LAYER M3 ;
			RECT 0.0098 22.011 0.0481 22.1114 ;
			 LAYER V2 ;
			RECT 0.0215 22.0859 0.0364 22.0984 ;
		END

		ANTENNADIFFAREA 0.00194719 ;
		ANTENNAPARTIALMETALAREA 0.00195671 ;
	END QA[27]

	PIN QA[28]
		USE SIGNAL ;
		DIRECTION OUTPUT ;
		SHAPE ABUTMENT ;
		PORT
			 LAYER M2 ;
			RECT 0.0098 22.8643 0.0481 22.902 ;
			 LAYER M3 ;
			RECT 0.0098 22.8016 0.0481 22.902 ;
			 LAYER V2 ;
			RECT 0.0215 22.8765 0.0364 22.889 ;
		END

		ANTENNADIFFAREA 0.00194719 ;
		ANTENNAPARTIALMETALAREA 0.00195671 ;
	END QA[28]

	PIN QA[29]
		USE SIGNAL ;
		DIRECTION OUTPUT ;
		SHAPE ABUTMENT ;
		PORT
			 LAYER M2 ;
			RECT 0.0098 23.6549 0.0481 23.6925 ;
			 LAYER M3 ;
			RECT 0.0098 23.5922 0.0481 23.6925 ;
			 LAYER V2 ;
			RECT 0.0215 23.6671 0.0364 23.6796 ;
		END

		ANTENNADIFFAREA 0.00194719 ;
		ANTENNAPARTIALMETALAREA 0.00195671 ;
	END QA[29]

	PIN QA[2]
		USE SIGNAL ;
		DIRECTION OUTPUT ;
		SHAPE ABUTMENT ;
		PORT
			 LAYER M2 ;
			RECT 0.0098 2.309 0.0481 2.3467 ;
			 LAYER M3 ;
			RECT 0.0098 2.2463 0.0481 2.3467 ;
			 LAYER V2 ;
			RECT 0.0215 2.3212 0.0364 2.3337 ;
		END

		ANTENNADIFFAREA 0.00194719 ;
		ANTENNAPARTIALMETALAREA 0.00195671 ;
	END QA[2]

	PIN QA[30]
		USE SIGNAL ;
		DIRECTION OUTPUT ;
		SHAPE ABUTMENT ;
		PORT
			 LAYER M2 ;
			RECT 0.0098 24.4455 0.0481 24.4831 ;
			 LAYER M3 ;
			RECT 0.0098 24.3827 0.0481 24.4831 ;
			 LAYER V2 ;
			RECT 0.0215 24.4576 0.0364 24.4702 ;
		END

		ANTENNADIFFAREA 0.00194719 ;
		ANTENNAPARTIALMETALAREA 0.00195671 ;
	END QA[30]

	PIN QA[31]
		USE SIGNAL ;
		DIRECTION OUTPUT ;
		SHAPE ABUTMENT ;
		PORT
			 LAYER M2 ;
			RECT 0.0098 25.2361 0.0481 25.2737 ;
			 LAYER M3 ;
			RECT 0.0098 25.1733 0.0481 25.2737 ;
			 LAYER V2 ;
			RECT 0.0215 25.2482 0.0364 25.2608 ;
		END

		ANTENNADIFFAREA 0.00194719 ;
		ANTENNAPARTIALMETALAREA 0.00195671 ;
	END QA[31]

	PIN QA[32]
		USE SIGNAL ;
		DIRECTION OUTPUT ;
		SHAPE ABUTMENT ;
		PORT
			 LAYER M2 ;
			RECT 0.0098 26.0267 0.0481 26.0643 ;
			 LAYER M3 ;
			RECT 0.0098 25.9639 0.0481 26.0643 ;
			 LAYER V2 ;
			RECT 0.0215 26.0388 0.0364 26.0514 ;
		END

		ANTENNADIFFAREA 0.00194719 ;
		ANTENNAPARTIALMETALAREA 0.00195671 ;
	END QA[32]

	PIN QA[33]
		USE SIGNAL ;
		DIRECTION OUTPUT ;
		SHAPE ABUTMENT ;
		PORT
			 LAYER M2 ;
			RECT 0.0098 35.5827 0.0481 35.6204 ;
			 LAYER M3 ;
			RECT 0.0098 35.5827 0.0481 35.6831 ;
			 LAYER V2 ;
			RECT 0.0215 35.5957 0.0364 35.6082 ;
		END

		ANTENNADIFFAREA 0.00194719 ;
		ANTENNAPARTIALMETALAREA 0.00195671 ;
	END QA[33]

	PIN QA[34]
		USE SIGNAL ;
		DIRECTION OUTPUT ;
		SHAPE ABUTMENT ;
		PORT
			 LAYER M2 ;
			RECT 0.0098 36.3733 0.0481 36.411 ;
			 LAYER M3 ;
			RECT 0.0098 36.3733 0.0481 36.4737 ;
			 LAYER V2 ;
			RECT 0.0215 36.3863 0.0364 36.3988 ;
		END

		ANTENNADIFFAREA 0.00194719 ;
		ANTENNAPARTIALMETALAREA 0.00195671 ;
	END QA[34]

	PIN QA[35]
		USE SIGNAL ;
		DIRECTION OUTPUT ;
		SHAPE ABUTMENT ;
		PORT
			 LAYER M2 ;
			RECT 0.0098 37.1639 0.0481 37.2016 ;
			 LAYER M3 ;
			RECT 0.0098 37.1639 0.0481 37.2643 ;
			 LAYER V2 ;
			RECT 0.0215 37.1769 0.0364 37.1894 ;
		END

		ANTENNADIFFAREA 0.00194719 ;
		ANTENNAPARTIALMETALAREA 0.00195671 ;
	END QA[35]

	PIN QA[36]
		USE SIGNAL ;
		DIRECTION OUTPUT ;
		SHAPE ABUTMENT ;
		PORT
			 LAYER M2 ;
			RECT 0.0098 37.9545 0.0481 37.9922 ;
			 LAYER M3 ;
			RECT 0.0098 37.9545 0.0481 38.0549 ;
			 LAYER V2 ;
			RECT 0.0215 37.9675 0.0364 37.98 ;
		END

		ANTENNADIFFAREA 0.00194719 ;
		ANTENNAPARTIALMETALAREA 0.00195671 ;
	END QA[36]

	PIN QA[37]
		USE SIGNAL ;
		DIRECTION OUTPUT ;
		SHAPE ABUTMENT ;
		PORT
			 LAYER M2 ;
			RECT 0.0098 38.7451 0.0481 38.7827 ;
			 LAYER M3 ;
			RECT 0.0098 38.7451 0.0481 38.8455 ;
			 LAYER V2 ;
			RECT 0.0215 38.758 0.0364 38.7706 ;
		END

		ANTENNADIFFAREA 0.00194719 ;
		ANTENNAPARTIALMETALAREA 0.00195671 ;
	END QA[37]

	PIN QA[38]
		USE SIGNAL ;
		DIRECTION OUTPUT ;
		SHAPE ABUTMENT ;
		PORT
			 LAYER M2 ;
			RECT 0.0098 39.5357 0.0481 39.5733 ;
			 LAYER M3 ;
			RECT 0.0098 39.5357 0.0481 39.6361 ;
			 LAYER V2 ;
			RECT 0.0215 39.5486 0.0364 39.5612 ;
		END

		ANTENNADIFFAREA 0.00194719 ;
		ANTENNAPARTIALMETALAREA 0.00195671 ;
	END QA[38]

	PIN QA[39]
		USE SIGNAL ;
		DIRECTION OUTPUT ;
		SHAPE ABUTMENT ;
		PORT
			 LAYER M2 ;
			RECT 0.0098 40.3263 0.0481 40.3639 ;
			 LAYER M3 ;
			RECT 0.0098 40.3263 0.0481 40.4267 ;
			 LAYER V2 ;
			RECT 0.0215 40.3392 0.0364 40.3518 ;
		END

		ANTENNADIFFAREA 0.00194719 ;
		ANTENNAPARTIALMETALAREA 0.00195671 ;
	END QA[39]

	PIN QA[3]
		USE SIGNAL ;
		DIRECTION OUTPUT ;
		SHAPE ABUTMENT ;
		PORT
			 LAYER M2 ;
			RECT 0.0098 3.0996 0.0481 3.1373 ;
			 LAYER M3 ;
			RECT 0.0098 3.0369 0.0481 3.1373 ;
			 LAYER V2 ;
			RECT 0.0215 3.1118 0.0364 3.1243 ;
		END

		ANTENNADIFFAREA 0.00194719 ;
		ANTENNAPARTIALMETALAREA 0.00195671 ;
	END QA[3]

	PIN QA[40]
		USE SIGNAL ;
		DIRECTION OUTPUT ;
		SHAPE ABUTMENT ;
		PORT
			 LAYER M2 ;
			RECT 0.0098 41.1169 0.0481 41.1545 ;
			 LAYER M3 ;
			RECT 0.0098 41.1169 0.0481 41.2173 ;
			 LAYER V2 ;
			RECT 0.0215 41.1298 0.0364 41.1424 ;
		END

		ANTENNADIFFAREA 0.00194719 ;
		ANTENNAPARTIALMETALAREA 0.00195671 ;
	END QA[40]

	PIN QA[41]
		USE SIGNAL ;
		DIRECTION OUTPUT ;
		SHAPE ABUTMENT ;
		PORT
			 LAYER M2 ;
			RECT 0.0098 41.9075 0.0481 41.9451 ;
			 LAYER M3 ;
			RECT 0.0098 41.9075 0.0481 42.0078 ;
			 LAYER V2 ;
			RECT 0.0215 41.9204 0.0364 41.9329 ;
		END

		ANTENNADIFFAREA 0.00194719 ;
		ANTENNAPARTIALMETALAREA 0.00195671 ;
	END QA[41]

	PIN QA[42]
		USE SIGNAL ;
		DIRECTION OUTPUT ;
		SHAPE ABUTMENT ;
		PORT
			 LAYER M2 ;
			RECT 0.0098 42.698 0.0481 42.7357 ;
			 LAYER M3 ;
			RECT 0.0098 42.698 0.0481 42.7984 ;
			 LAYER V2 ;
			RECT 0.0215 42.711 0.0364 42.7235 ;
		END

		ANTENNADIFFAREA 0.00194719 ;
		ANTENNAPARTIALMETALAREA 0.00195671 ;
	END QA[42]

	PIN QA[43]
		USE SIGNAL ;
		DIRECTION OUTPUT ;
		SHAPE ABUTMENT ;
		PORT
			 LAYER M2 ;
			RECT 0.0098 43.4886 0.0481 43.5263 ;
			 LAYER M3 ;
			RECT 0.0098 43.4886 0.0481 43.589 ;
			 LAYER V2 ;
			RECT 0.0215 43.5016 0.0364 43.5141 ;
		END

		ANTENNADIFFAREA 0.00194719 ;
		ANTENNAPARTIALMETALAREA 0.00195671 ;
	END QA[43]

	PIN QA[44]
		USE SIGNAL ;
		DIRECTION OUTPUT ;
		SHAPE ABUTMENT ;
		PORT
			 LAYER M2 ;
			RECT 0.0098 44.2792 0.0481 44.3169 ;
			 LAYER M3 ;
			RECT 0.0098 44.2792 0.0481 44.3796 ;
			 LAYER V2 ;
			RECT 0.0215 44.2922 0.0364 44.3047 ;
		END

		ANTENNADIFFAREA 0.00194719 ;
		ANTENNAPARTIALMETALAREA 0.00195671 ;
	END QA[44]

	PIN QA[45]
		USE SIGNAL ;
		DIRECTION OUTPUT ;
		SHAPE ABUTMENT ;
		PORT
			 LAYER M2 ;
			RECT 0.0098 45.0698 0.0481 45.1075 ;
			 LAYER M3 ;
			RECT 0.0098 45.0698 0.0481 45.1702 ;
			 LAYER V2 ;
			RECT 0.0215 45.0827 0.0364 45.0953 ;
		END

		ANTENNADIFFAREA 0.00194719 ;
		ANTENNAPARTIALMETALAREA 0.00195671 ;
	END QA[45]

	PIN QA[46]
		USE SIGNAL ;
		DIRECTION OUTPUT ;
		SHAPE ABUTMENT ;
		PORT
			 LAYER M2 ;
			RECT 0.0098 45.8604 0.0481 45.898 ;
			 LAYER M3 ;
			RECT 0.0098 45.8604 0.0481 45.9608 ;
			 LAYER V2 ;
			RECT 0.0215 45.8733 0.0364 45.8859 ;
		END

		ANTENNADIFFAREA 0.00194719 ;
		ANTENNAPARTIALMETALAREA 0.00195671 ;
	END QA[46]

	PIN QA[47]
		USE SIGNAL ;
		DIRECTION OUTPUT ;
		SHAPE ABUTMENT ;
		PORT
			 LAYER M2 ;
			RECT 0.0098 46.651 0.0481 46.6886 ;
			 LAYER M3 ;
			RECT 0.0098 46.651 0.0481 46.7514 ;
			 LAYER V2 ;
			RECT 0.0215 46.6639 0.0364 46.6765 ;
		END

		ANTENNADIFFAREA 0.00194719 ;
		ANTENNAPARTIALMETALAREA 0.00195671 ;
	END QA[47]

	PIN QA[48]
		USE SIGNAL ;
		DIRECTION OUTPUT ;
		SHAPE ABUTMENT ;
		PORT
			 LAYER M2 ;
			RECT 0.0098 47.4416 0.0481 47.4792 ;
			 LAYER M3 ;
			RECT 0.0098 47.4416 0.0481 47.542 ;
			 LAYER V2 ;
			RECT 0.0215 47.4545 0.0364 47.4671 ;
		END

		ANTENNADIFFAREA 0.00194719 ;
		ANTENNAPARTIALMETALAREA 0.00195671 ;
	END QA[48]

	PIN QA[49]
		USE SIGNAL ;
		DIRECTION OUTPUT ;
		SHAPE ABUTMENT ;
		PORT
			 LAYER M2 ;
			RECT 0.0098 48.2322 0.0481 48.2698 ;
			 LAYER M3 ;
			RECT 0.0098 48.2322 0.0481 48.3325 ;
			 LAYER V2 ;
			RECT 0.0215 48.2451 0.0364 48.2576 ;
		END

		ANTENNADIFFAREA 0.00194719 ;
		ANTENNAPARTIALMETALAREA 0.00195671 ;
	END QA[49]

	PIN QA[4]
		USE SIGNAL ;
		DIRECTION OUTPUT ;
		SHAPE ABUTMENT ;
		PORT
			 LAYER M2 ;
			RECT 0.0098 3.8902 0.0481 3.9278 ;
			 LAYER M3 ;
			RECT 0.0098 3.8275 0.0481 3.9278 ;
			 LAYER V2 ;
			RECT 0.0215 3.9024 0.0364 3.9149 ;
		END

		ANTENNADIFFAREA 0.00194719 ;
		ANTENNAPARTIALMETALAREA 0.00195671 ;
	END QA[4]

	PIN QA[50]
		USE SIGNAL ;
		DIRECTION OUTPUT ;
		SHAPE ABUTMENT ;
		PORT
			 LAYER M2 ;
			RECT 0.0098 49.0227 0.0481 49.0604 ;
			 LAYER M3 ;
			RECT 0.0098 49.0227 0.0481 49.1231 ;
			 LAYER V2 ;
			RECT 0.0215 49.0357 0.0364 49.0482 ;
		END

		ANTENNADIFFAREA 0.00194719 ;
		ANTENNAPARTIALMETALAREA 0.00195671 ;
	END QA[50]

	PIN QA[51]
		USE SIGNAL ;
		DIRECTION OUTPUT ;
		SHAPE ABUTMENT ;
		PORT
			 LAYER M2 ;
			RECT 0.0098 49.8133 0.0481 49.851 ;
			 LAYER M3 ;
			RECT 0.0098 49.8133 0.0481 49.9137 ;
			 LAYER V2 ;
			RECT 0.0215 49.8263 0.0364 49.8388 ;
		END

		ANTENNADIFFAREA 0.00194719 ;
		ANTENNAPARTIALMETALAREA 0.00195671 ;
	END QA[51]

	PIN QA[52]
		USE SIGNAL ;
		DIRECTION OUTPUT ;
		SHAPE ABUTMENT ;
		PORT
			 LAYER M2 ;
			RECT 0.0098 50.6039 0.0481 50.6416 ;
			 LAYER M3 ;
			RECT 0.0098 50.6039 0.0481 50.7043 ;
			 LAYER V2 ;
			RECT 0.0215 50.6169 0.0364 50.6294 ;
		END

		ANTENNADIFFAREA 0.00194719 ;
		ANTENNAPARTIALMETALAREA 0.00195671 ;
	END QA[52]

	PIN QA[53]
		USE SIGNAL ;
		DIRECTION OUTPUT ;
		SHAPE ABUTMENT ;
		PORT
			 LAYER M2 ;
			RECT 0.0098 51.3945 0.0481 51.4322 ;
			 LAYER M3 ;
			RECT 0.0098 51.3945 0.0481 51.4949 ;
			 LAYER V2 ;
			RECT 0.0215 51.4075 0.0364 51.42 ;
		END

		ANTENNADIFFAREA 0.00194719 ;
		ANTENNAPARTIALMETALAREA 0.00195671 ;
	END QA[53]

	PIN QA[54]
		USE SIGNAL ;
		DIRECTION OUTPUT ;
		SHAPE ABUTMENT ;
		PORT
			 LAYER M2 ;
			RECT 0.0098 52.1851 0.0481 52.2227 ;
			 LAYER M3 ;
			RECT 0.0098 52.1851 0.0481 52.2855 ;
			 LAYER V2 ;
			RECT 0.0215 52.198 0.0364 52.2106 ;
		END

		ANTENNADIFFAREA 0.00194719 ;
		ANTENNAPARTIALMETALAREA 0.00195671 ;
	END QA[54]

	PIN QA[55]
		USE SIGNAL ;
		DIRECTION OUTPUT ;
		SHAPE ABUTMENT ;
		PORT
			 LAYER M2 ;
			RECT 0.0098 52.9757 0.0481 53.0133 ;
			 LAYER M3 ;
			RECT 0.0098 52.9757 0.0481 53.0761 ;
			 LAYER V2 ;
			RECT 0.0215 52.9886 0.0364 53.0012 ;
		END

		ANTENNADIFFAREA 0.00194719 ;
		ANTENNAPARTIALMETALAREA 0.00195671 ;
	END QA[55]

	PIN QA[56]
		USE SIGNAL ;
		DIRECTION OUTPUT ;
		SHAPE ABUTMENT ;
		PORT
			 LAYER M2 ;
			RECT 0.0098 53.7663 0.0481 53.8039 ;
			 LAYER M3 ;
			RECT 0.0098 53.7663 0.0481 53.8667 ;
			 LAYER V2 ;
			RECT 0.0215 53.7792 0.0364 53.7918 ;
		END

		ANTENNADIFFAREA 0.00194719 ;
		ANTENNAPARTIALMETALAREA 0.00195671 ;
	END QA[56]

	PIN QA[57]
		USE SIGNAL ;
		DIRECTION OUTPUT ;
		SHAPE ABUTMENT ;
		PORT
			 LAYER M2 ;
			RECT 0.0098 54.5569 0.0481 54.5945 ;
			 LAYER M3 ;
			RECT 0.0098 54.5569 0.0481 54.6573 ;
			 LAYER V2 ;
			RECT 0.0215 54.5698 0.0364 54.5824 ;
		END

		ANTENNADIFFAREA 0.00194719 ;
		ANTENNAPARTIALMETALAREA 0.00195671 ;
	END QA[57]

	PIN QA[58]
		USE SIGNAL ;
		DIRECTION OUTPUT ;
		SHAPE ABUTMENT ;
		PORT
			 LAYER M2 ;
			RECT 0.0098 55.3475 0.0481 55.3851 ;
			 LAYER M3 ;
			RECT 0.0098 55.3475 0.0481 55.4478 ;
			 LAYER V2 ;
			RECT 0.0215 55.3604 0.0364 55.3729 ;
		END

		ANTENNADIFFAREA 0.00194719 ;
		ANTENNAPARTIALMETALAREA 0.00195671 ;
	END QA[58]

	PIN QA[59]
		USE SIGNAL ;
		DIRECTION OUTPUT ;
		SHAPE ABUTMENT ;
		PORT
			 LAYER M2 ;
			RECT 0.0098 56.138 0.0481 56.1757 ;
			 LAYER M3 ;
			RECT 0.0098 56.138 0.0481 56.2384 ;
			 LAYER V2 ;
			RECT 0.0215 56.151 0.0364 56.1635 ;
		END

		ANTENNADIFFAREA 0.00194719 ;
		ANTENNAPARTIALMETALAREA 0.00195671 ;
	END QA[59]

	PIN QA[5]
		USE SIGNAL ;
		DIRECTION OUTPUT ;
		SHAPE ABUTMENT ;
		PORT
			 LAYER M2 ;
			RECT 0.0098 4.6808 0.0481 4.7184 ;
			 LAYER M3 ;
			RECT 0.0098 4.618 0.0481 4.7184 ;
			 LAYER V2 ;
			RECT 0.0215 4.6929 0.0364 4.7055 ;
		END

		ANTENNADIFFAREA 0.00194719 ;
		ANTENNAPARTIALMETALAREA 0.00195671 ;
	END QA[5]

	PIN QA[60]
		USE SIGNAL ;
		DIRECTION OUTPUT ;
		SHAPE ABUTMENT ;
		PORT
			 LAYER M2 ;
			RECT 0.0098 56.9286 0.0481 56.9663 ;
			 LAYER M3 ;
			RECT 0.0098 56.9286 0.0481 57.029 ;
			 LAYER V2 ;
			RECT 0.0215 56.9416 0.0364 56.9541 ;
		END

		ANTENNADIFFAREA 0.00194719 ;
		ANTENNAPARTIALMETALAREA 0.00195671 ;
	END QA[60]

	PIN QA[61]
		USE SIGNAL ;
		DIRECTION OUTPUT ;
		SHAPE ABUTMENT ;
		PORT
			 LAYER M2 ;
			RECT 0.0098 57.7192 0.0481 57.7569 ;
			 LAYER M3 ;
			RECT 0.0098 57.7192 0.0481 57.8196 ;
			 LAYER V2 ;
			RECT 0.0215 57.7322 0.0364 57.7447 ;
		END

		ANTENNADIFFAREA 0.00194719 ;
		ANTENNAPARTIALMETALAREA 0.00195671 ;
	END QA[61]

	PIN QA[62]
		USE SIGNAL ;
		DIRECTION OUTPUT ;
		SHAPE ABUTMENT ;
		PORT
			 LAYER M2 ;
			RECT 0.0098 58.5098 0.0481 58.5475 ;
			 LAYER M3 ;
			RECT 0.0098 58.5098 0.0481 58.6102 ;
			 LAYER V2 ;
			RECT 0.0215 58.5227 0.0364 58.5353 ;
		END

		ANTENNADIFFAREA 0.00194719 ;
		ANTENNAPARTIALMETALAREA 0.00195671 ;
	END QA[62]

	PIN QA[63]
		USE SIGNAL ;
		DIRECTION OUTPUT ;
		SHAPE ABUTMENT ;
		PORT
			 LAYER M2 ;
			RECT 0.0098 59.3004 0.0481 59.338 ;
			 LAYER M3 ;
			RECT 0.0098 59.3004 0.0481 59.4008 ;
			 LAYER V2 ;
			RECT 0.0215 59.3133 0.0364 59.3259 ;
		END

		ANTENNADIFFAREA 0.00194719 ;
		ANTENNAPARTIALMETALAREA 0.00195671 ;
	END QA[63]

	PIN QA[64]
		USE SIGNAL ;
		DIRECTION OUTPUT ;
		SHAPE ABUTMENT ;
		PORT
			 LAYER M2 ;
			RECT 0.0098 60.091 0.0481 60.1286 ;
			 LAYER M3 ;
			RECT 0.0098 60.091 0.0481 60.1914 ;
			 LAYER V2 ;
			RECT 0.0215 60.1039 0.0364 60.1165 ;
		END

		ANTENNADIFFAREA 0.00194719 ;
		ANTENNAPARTIALMETALAREA 0.00195671 ;
	END QA[64]

	PIN QA[65]
		USE SIGNAL ;
		DIRECTION OUTPUT ;
		SHAPE ABUTMENT ;
		PORT
			 LAYER M2 ;
			RECT 0.0098 60.8816 0.0481 60.9192 ;
			 LAYER M3 ;
			RECT 0.0098 60.8816 0.0481 60.982 ;
			 LAYER V2 ;
			RECT 0.0215 60.8945 0.0364 60.9071 ;
		END

		ANTENNADIFFAREA 0.00194719 ;
		ANTENNAPARTIALMETALAREA 0.00195671 ;
	END QA[65]

	PIN QA[6]
		USE SIGNAL ;
		DIRECTION OUTPUT ;
		SHAPE ABUTMENT ;
		PORT
			 LAYER M2 ;
			RECT 0.0098 5.4714 0.0481 5.509 ;
			 LAYER M3 ;
			RECT 0.0098 5.4086 0.0481 5.509 ;
			 LAYER V2 ;
			RECT 0.0215 5.4835 0.0364 5.4961 ;
		END

		ANTENNADIFFAREA 0.00194719 ;
		ANTENNAPARTIALMETALAREA 0.00195671 ;
	END QA[6]

	PIN QA[7]
		USE SIGNAL ;
		DIRECTION OUTPUT ;
		SHAPE ABUTMENT ;
		PORT
			 LAYER M2 ;
			RECT 0.0098 6.262 0.0481 6.2996 ;
			 LAYER M3 ;
			RECT 0.0098 6.1992 0.0481 6.2996 ;
			 LAYER V2 ;
			RECT 0.0215 6.2741 0.0364 6.2867 ;
		END

		ANTENNADIFFAREA 0.00194719 ;
		ANTENNAPARTIALMETALAREA 0.00195671 ;
	END QA[7]

	PIN QA[8]
		USE SIGNAL ;
		DIRECTION OUTPUT ;
		SHAPE ABUTMENT ;
		PORT
			 LAYER M2 ;
			RECT 0.0098 7.0525 0.0481 7.0902 ;
			 LAYER M3 ;
			RECT 0.0098 6.9898 0.0481 7.0902 ;
			 LAYER V2 ;
			RECT 0.0215 7.0647 0.0364 7.0773 ;
		END

		ANTENNADIFFAREA 0.00194719 ;
		ANTENNAPARTIALMETALAREA 0.00195671 ;
	END QA[8]

	PIN QA[9]
		USE SIGNAL ;
		DIRECTION OUTPUT ;
		SHAPE ABUTMENT ;
		PORT
			 LAYER M2 ;
			RECT 0.0098 7.8431 0.0481 7.8808 ;
			 LAYER M3 ;
			RECT 0.0098 7.7804 0.0481 7.8808 ;
			 LAYER V2 ;
			RECT 0.0215 7.8553 0.0364 7.8678 ;
		END

		ANTENNADIFFAREA 0.00194719 ;
		ANTENNAPARTIALMETALAREA 0.00195671 ;
	END QA[9]

	PIN QB[0]
		USE SIGNAL ;
		DIRECTION OUTPUT ;
		SHAPE ABUTMENT ;
		PORT
			 LAYER M2 ;
			RECT 0.0098 0.8408 0.0481 0.8784 ;
		END

		ANTENNADIFFAREA 0.00194719 ;
		ANTENNAPARTIALMETALAREA 0.00195671 ;
	END QB[0]

	PIN QB[10]
		USE SIGNAL ;
		DIRECTION OUTPUT ;
		SHAPE ABUTMENT ;
		PORT
			 LAYER M2 ;
			RECT 0.0098 8.7467 0.0481 8.7843 ;
		END

		ANTENNADIFFAREA 0.00194719 ;
		ANTENNAPARTIALMETALAREA 0.00195671 ;
	END QB[10]

	PIN QB[11]
		USE SIGNAL ;
		DIRECTION OUTPUT ;
		SHAPE ABUTMENT ;
		PORT
			 LAYER M2 ;
			RECT 0.0098 9.5373 0.0481 9.5749 ;
		END

		ANTENNADIFFAREA 0.00194719 ;
		ANTENNAPARTIALMETALAREA 0.00195671 ;
	END QB[11]

	PIN QB[12]
		USE SIGNAL ;
		DIRECTION OUTPUT ;
		SHAPE ABUTMENT ;
		PORT
			 LAYER M2 ;
			RECT 0.0098 10.3278 0.0481 10.3655 ;
		END

		ANTENNADIFFAREA 0.00194719 ;
		ANTENNAPARTIALMETALAREA 0.00195671 ;
	END QB[12]

	PIN QB[13]
		USE SIGNAL ;
		DIRECTION OUTPUT ;
		SHAPE ABUTMENT ;
		PORT
			 LAYER M2 ;
			RECT 0.0098 11.1184 0.0481 11.1561 ;
		END

		ANTENNADIFFAREA 0.00194719 ;
		ANTENNAPARTIALMETALAREA 0.00195671 ;
	END QB[13]

	PIN QB[14]
		USE SIGNAL ;
		DIRECTION OUTPUT ;
		SHAPE ABUTMENT ;
		PORT
			 LAYER M2 ;
			RECT 0.0098 11.909 0.0481 11.9467 ;
		END

		ANTENNADIFFAREA 0.00194719 ;
		ANTENNAPARTIALMETALAREA 0.00195671 ;
	END QB[14]

	PIN QB[15]
		USE SIGNAL ;
		DIRECTION OUTPUT ;
		SHAPE ABUTMENT ;
		PORT
			 LAYER M2 ;
			RECT 0.0098 12.6996 0.0481 12.7373 ;
		END

		ANTENNADIFFAREA 0.00194719 ;
		ANTENNAPARTIALMETALAREA 0.00195671 ;
	END QB[15]

	PIN QB[16]
		USE SIGNAL ;
		DIRECTION OUTPUT ;
		SHAPE ABUTMENT ;
		PORT
			 LAYER M2 ;
			RECT 0.0098 13.4902 0.0481 13.5278 ;
		END

		ANTENNADIFFAREA 0.00194719 ;
		ANTENNAPARTIALMETALAREA 0.00195671 ;
	END QB[16]

	PIN QB[17]
		USE SIGNAL ;
		DIRECTION OUTPUT ;
		SHAPE ABUTMENT ;
		PORT
			 LAYER M2 ;
			RECT 0.0098 14.2808 0.0481 14.3184 ;
		END

		ANTENNADIFFAREA 0.00194719 ;
		ANTENNAPARTIALMETALAREA 0.00195671 ;
	END QB[17]

	PIN QB[18]
		USE SIGNAL ;
		DIRECTION OUTPUT ;
		SHAPE ABUTMENT ;
		PORT
			 LAYER M2 ;
			RECT 0.0098 15.0714 0.0481 15.109 ;
		END

		ANTENNADIFFAREA 0.00194719 ;
		ANTENNAPARTIALMETALAREA 0.00195671 ;
	END QB[18]

	PIN QB[19]
		USE SIGNAL ;
		DIRECTION OUTPUT ;
		SHAPE ABUTMENT ;
		PORT
			 LAYER M2 ;
			RECT 0.0098 15.862 0.0481 15.8996 ;
		END

		ANTENNADIFFAREA 0.00194719 ;
		ANTENNAPARTIALMETALAREA 0.00195671 ;
	END QB[19]

	PIN QB[1]
		USE SIGNAL ;
		DIRECTION OUTPUT ;
		SHAPE ABUTMENT ;
		PORT
			 LAYER M2 ;
			RECT 0.0098 1.6314 0.0481 1.669 ;
		END

		ANTENNADIFFAREA 0.00194719 ;
		ANTENNAPARTIALMETALAREA 0.00195671 ;
	END QB[1]

	PIN QB[20]
		USE SIGNAL ;
		DIRECTION OUTPUT ;
		SHAPE ABUTMENT ;
		PORT
			 LAYER M2 ;
			RECT 0.0098 16.6525 0.0481 16.6902 ;
		END

		ANTENNADIFFAREA 0.00194719 ;
		ANTENNAPARTIALMETALAREA 0.00195671 ;
	END QB[20]

	PIN QB[21]
		USE SIGNAL ;
		DIRECTION OUTPUT ;
		SHAPE ABUTMENT ;
		PORT
			 LAYER M2 ;
			RECT 0.0098 17.4431 0.0481 17.4808 ;
		END

		ANTENNADIFFAREA 0.00194719 ;
		ANTENNAPARTIALMETALAREA 0.00195671 ;
	END QB[21]

	PIN QB[22]
		USE SIGNAL ;
		DIRECTION OUTPUT ;
		SHAPE ABUTMENT ;
		PORT
			 LAYER M2 ;
			RECT 0.0098 18.2337 0.0481 18.2714 ;
		END

		ANTENNADIFFAREA 0.00194719 ;
		ANTENNAPARTIALMETALAREA 0.00195671 ;
	END QB[22]

	PIN QB[23]
		USE SIGNAL ;
		DIRECTION OUTPUT ;
		SHAPE ABUTMENT ;
		PORT
			 LAYER M2 ;
			RECT 0.0098 19.0243 0.0481 19.062 ;
		END

		ANTENNADIFFAREA 0.00194719 ;
		ANTENNAPARTIALMETALAREA 0.00195671 ;
	END QB[23]

	PIN QB[24]
		USE SIGNAL ;
		DIRECTION OUTPUT ;
		SHAPE ABUTMENT ;
		PORT
			 LAYER M2 ;
			RECT 0.0098 19.8149 0.0481 19.8525 ;
		END

		ANTENNADIFFAREA 0.00194719 ;
		ANTENNAPARTIALMETALAREA 0.00195671 ;
	END QB[24]

	PIN QB[25]
		USE SIGNAL ;
		DIRECTION OUTPUT ;
		SHAPE ABUTMENT ;
		PORT
			 LAYER M2 ;
			RECT 0.0098 20.6055 0.0481 20.6431 ;
		END

		ANTENNADIFFAREA 0.00194719 ;
		ANTENNAPARTIALMETALAREA 0.00195671 ;
	END QB[25]

	PIN QB[26]
		USE SIGNAL ;
		DIRECTION OUTPUT ;
		SHAPE ABUTMENT ;
		PORT
			 LAYER M2 ;
			RECT 0.0098 21.3961 0.0481 21.4337 ;
		END

		ANTENNADIFFAREA 0.00194719 ;
		ANTENNAPARTIALMETALAREA 0.00195671 ;
	END QB[26]

	PIN QB[27]
		USE SIGNAL ;
		DIRECTION OUTPUT ;
		SHAPE ABUTMENT ;
		PORT
			 LAYER M2 ;
			RECT 0.0098 22.1867 0.0481 22.2243 ;
		END

		ANTENNADIFFAREA 0.00194719 ;
		ANTENNAPARTIALMETALAREA 0.00195671 ;
	END QB[27]

	PIN QB[28]
		USE SIGNAL ;
		DIRECTION OUTPUT ;
		SHAPE ABUTMENT ;
		PORT
			 LAYER M2 ;
			RECT 0.0098 22.9773 0.0481 23.0149 ;
		END

		ANTENNADIFFAREA 0.00194719 ;
		ANTENNAPARTIALMETALAREA 0.00195671 ;
	END QB[28]

	PIN QB[29]
		USE SIGNAL ;
		DIRECTION OUTPUT ;
		SHAPE ABUTMENT ;
		PORT
			 LAYER M2 ;
			RECT 0.0098 23.7678 0.0481 23.8055 ;
		END

		ANTENNADIFFAREA 0.00194719 ;
		ANTENNAPARTIALMETALAREA 0.00195671 ;
	END QB[29]

	PIN QB[2]
		USE SIGNAL ;
		DIRECTION OUTPUT ;
		SHAPE ABUTMENT ;
		PORT
			 LAYER M2 ;
			RECT 0.0098 2.422 0.0481 2.4596 ;
		END

		ANTENNADIFFAREA 0.00194719 ;
		ANTENNAPARTIALMETALAREA 0.00195671 ;
	END QB[2]

	PIN QB[30]
		USE SIGNAL ;
		DIRECTION OUTPUT ;
		SHAPE ABUTMENT ;
		PORT
			 LAYER M2 ;
			RECT 0.0098 24.5584 0.0481 24.5961 ;
		END

		ANTENNADIFFAREA 0.00194719 ;
		ANTENNAPARTIALMETALAREA 0.00195671 ;
	END QB[30]

	PIN QB[31]
		USE SIGNAL ;
		DIRECTION OUTPUT ;
		SHAPE ABUTMENT ;
		PORT
			 LAYER M2 ;
			RECT 0.0098 25.349 0.0481 25.3867 ;
		END

		ANTENNADIFFAREA 0.00194719 ;
		ANTENNAPARTIALMETALAREA 0.00195671 ;
	END QB[31]

	PIN QB[32]
		USE SIGNAL ;
		DIRECTION OUTPUT ;
		SHAPE ABUTMENT ;
		PORT
			 LAYER M2 ;
			RECT 0.0098 26.1396 0.0481 26.1773 ;
		END

		ANTENNADIFFAREA 0.00194719 ;
		ANTENNAPARTIALMETALAREA 0.00195671 ;
	END QB[32]

	PIN QB[33]
		USE SIGNAL ;
		DIRECTION OUTPUT ;
		SHAPE ABUTMENT ;
		PORT
			 LAYER M2 ;
			RECT 0.0098 35.4698 0.0481 35.5075 ;
		END

		ANTENNADIFFAREA 0.00194719 ;
		ANTENNAPARTIALMETALAREA 0.00195671 ;
	END QB[33]

	PIN QB[34]
		USE SIGNAL ;
		DIRECTION OUTPUT ;
		SHAPE ABUTMENT ;
		PORT
			 LAYER M2 ;
			RECT 0.0098 36.2604 0.0481 36.298 ;
		END

		ANTENNADIFFAREA 0.00194719 ;
		ANTENNAPARTIALMETALAREA 0.00195671 ;
	END QB[34]

	PIN QB[35]
		USE SIGNAL ;
		DIRECTION OUTPUT ;
		SHAPE ABUTMENT ;
		PORT
			 LAYER M2 ;
			RECT 0.0098 37.051 0.0481 37.0886 ;
		END

		ANTENNADIFFAREA 0.00194719 ;
		ANTENNAPARTIALMETALAREA 0.00195671 ;
	END QB[35]

	PIN QB[36]
		USE SIGNAL ;
		DIRECTION OUTPUT ;
		SHAPE ABUTMENT ;
		PORT
			 LAYER M2 ;
			RECT 0.0098 37.8416 0.0481 37.8792 ;
		END

		ANTENNADIFFAREA 0.00194719 ;
		ANTENNAPARTIALMETALAREA 0.00195671 ;
	END QB[36]

	PIN QB[37]
		USE SIGNAL ;
		DIRECTION OUTPUT ;
		SHAPE ABUTMENT ;
		PORT
			 LAYER M2 ;
			RECT 0.0098 38.6322 0.0481 38.6698 ;
		END

		ANTENNADIFFAREA 0.00194719 ;
		ANTENNAPARTIALMETALAREA 0.00195671 ;
	END QB[37]

	PIN QB[38]
		USE SIGNAL ;
		DIRECTION OUTPUT ;
		SHAPE ABUTMENT ;
		PORT
			 LAYER M2 ;
			RECT 0.0098 39.4227 0.0481 39.4604 ;
		END

		ANTENNADIFFAREA 0.00194719 ;
		ANTENNAPARTIALMETALAREA 0.00195671 ;
	END QB[38]

	PIN QB[39]
		USE SIGNAL ;
		DIRECTION OUTPUT ;
		SHAPE ABUTMENT ;
		PORT
			 LAYER M2 ;
			RECT 0.0098 40.2133 0.0481 40.251 ;
		END

		ANTENNADIFFAREA 0.00194719 ;
		ANTENNAPARTIALMETALAREA 0.00195671 ;
	END QB[39]

	PIN QB[3]
		USE SIGNAL ;
		DIRECTION OUTPUT ;
		SHAPE ABUTMENT ;
		PORT
			 LAYER M2 ;
			RECT 0.0098 3.2125 0.0481 3.2502 ;
		END

		ANTENNADIFFAREA 0.00194719 ;
		ANTENNAPARTIALMETALAREA 0.00195671 ;
	END QB[3]

	PIN QB[40]
		USE SIGNAL ;
		DIRECTION OUTPUT ;
		SHAPE ABUTMENT ;
		PORT
			 LAYER M2 ;
			RECT 0.0098 41.0039 0.0481 41.0416 ;
		END

		ANTENNADIFFAREA 0.00194719 ;
		ANTENNAPARTIALMETALAREA 0.00195671 ;
	END QB[40]

	PIN QB[41]
		USE SIGNAL ;
		DIRECTION OUTPUT ;
		SHAPE ABUTMENT ;
		PORT
			 LAYER M2 ;
			RECT 0.0098 41.7945 0.0481 41.8322 ;
		END

		ANTENNADIFFAREA 0.00194719 ;
		ANTENNAPARTIALMETALAREA 0.00195671 ;
	END QB[41]

	PIN QB[42]
		USE SIGNAL ;
		DIRECTION OUTPUT ;
		SHAPE ABUTMENT ;
		PORT
			 LAYER M2 ;
			RECT 0.0098 42.5851 0.0481 42.6227 ;
		END

		ANTENNADIFFAREA 0.00194719 ;
		ANTENNAPARTIALMETALAREA 0.00195671 ;
	END QB[42]

	PIN QB[43]
		USE SIGNAL ;
		DIRECTION OUTPUT ;
		SHAPE ABUTMENT ;
		PORT
			 LAYER M2 ;
			RECT 0.0098 43.3757 0.0481 43.4133 ;
		END

		ANTENNADIFFAREA 0.00194719 ;
		ANTENNAPARTIALMETALAREA 0.00195671 ;
	END QB[43]

	PIN QB[44]
		USE SIGNAL ;
		DIRECTION OUTPUT ;
		SHAPE ABUTMENT ;
		PORT
			 LAYER M2 ;
			RECT 0.0098 44.1663 0.0481 44.2039 ;
		END

		ANTENNADIFFAREA 0.00194719 ;
		ANTENNAPARTIALMETALAREA 0.00195671 ;
	END QB[44]

	PIN QB[45]
		USE SIGNAL ;
		DIRECTION OUTPUT ;
		SHAPE ABUTMENT ;
		PORT
			 LAYER M2 ;
			RECT 0.0098 44.9569 0.0481 44.9945 ;
		END

		ANTENNADIFFAREA 0.00194719 ;
		ANTENNAPARTIALMETALAREA 0.00195671 ;
	END QB[45]

	PIN QB[46]
		USE SIGNAL ;
		DIRECTION OUTPUT ;
		SHAPE ABUTMENT ;
		PORT
			 LAYER M2 ;
			RECT 0.0098 45.7475 0.0481 45.7851 ;
		END

		ANTENNADIFFAREA 0.00194719 ;
		ANTENNAPARTIALMETALAREA 0.00195671 ;
	END QB[46]

	PIN QB[47]
		USE SIGNAL ;
		DIRECTION OUTPUT ;
		SHAPE ABUTMENT ;
		PORT
			 LAYER M2 ;
			RECT 0.0098 46.538 0.0481 46.5757 ;
		END

		ANTENNADIFFAREA 0.00194719 ;
		ANTENNAPARTIALMETALAREA 0.00195671 ;
	END QB[47]

	PIN QB[48]
		USE SIGNAL ;
		DIRECTION OUTPUT ;
		SHAPE ABUTMENT ;
		PORT
			 LAYER M2 ;
			RECT 0.0098 47.3286 0.0481 47.3663 ;
		END

		ANTENNADIFFAREA 0.00194719 ;
		ANTENNAPARTIALMETALAREA 0.00195671 ;
	END QB[48]

	PIN QB[49]
		USE SIGNAL ;
		DIRECTION OUTPUT ;
		SHAPE ABUTMENT ;
		PORT
			 LAYER M2 ;
			RECT 0.0098 48.1192 0.0481 48.1569 ;
		END

		ANTENNADIFFAREA 0.00194719 ;
		ANTENNAPARTIALMETALAREA 0.00195671 ;
	END QB[49]

	PIN QB[4]
		USE SIGNAL ;
		DIRECTION OUTPUT ;
		SHAPE ABUTMENT ;
		PORT
			 LAYER M2 ;
			RECT 0.0098 4.0031 0.0481 4.0408 ;
		END

		ANTENNADIFFAREA 0.00194719 ;
		ANTENNAPARTIALMETALAREA 0.00195671 ;
	END QB[4]

	PIN QB[50]
		USE SIGNAL ;
		DIRECTION OUTPUT ;
		SHAPE ABUTMENT ;
		PORT
			 LAYER M2 ;
			RECT 0.0098 48.9098 0.0481 48.9475 ;
		END

		ANTENNADIFFAREA 0.00194719 ;
		ANTENNAPARTIALMETALAREA 0.00195671 ;
	END QB[50]

	PIN QB[51]
		USE SIGNAL ;
		DIRECTION OUTPUT ;
		SHAPE ABUTMENT ;
		PORT
			 LAYER M2 ;
			RECT 0.0098 49.7004 0.0481 49.738 ;
		END

		ANTENNADIFFAREA 0.00194719 ;
		ANTENNAPARTIALMETALAREA 0.00195671 ;
	END QB[51]

	PIN QB[52]
		USE SIGNAL ;
		DIRECTION OUTPUT ;
		SHAPE ABUTMENT ;
		PORT
			 LAYER M2 ;
			RECT 0.0098 50.491 0.0481 50.5286 ;
		END

		ANTENNADIFFAREA 0.00194719 ;
		ANTENNAPARTIALMETALAREA 0.00195671 ;
	END QB[52]

	PIN QB[53]
		USE SIGNAL ;
		DIRECTION OUTPUT ;
		SHAPE ABUTMENT ;
		PORT
			 LAYER M2 ;
			RECT 0.0098 51.2816 0.0481 51.3192 ;
		END

		ANTENNADIFFAREA 0.00194719 ;
		ANTENNAPARTIALMETALAREA 0.00195671 ;
	END QB[53]

	PIN QB[54]
		USE SIGNAL ;
		DIRECTION OUTPUT ;
		SHAPE ABUTMENT ;
		PORT
			 LAYER M2 ;
			RECT 0.0098 52.0722 0.0481 52.1098 ;
		END

		ANTENNADIFFAREA 0.00194719 ;
		ANTENNAPARTIALMETALAREA 0.00195671 ;
	END QB[54]

	PIN QB[55]
		USE SIGNAL ;
		DIRECTION OUTPUT ;
		SHAPE ABUTMENT ;
		PORT
			 LAYER M2 ;
			RECT 0.0098 52.8627 0.0481 52.9004 ;
		END

		ANTENNADIFFAREA 0.00194719 ;
		ANTENNAPARTIALMETALAREA 0.00195671 ;
	END QB[55]

	PIN QB[56]
		USE SIGNAL ;
		DIRECTION OUTPUT ;
		SHAPE ABUTMENT ;
		PORT
			 LAYER M2 ;
			RECT 0.0098 53.6533 0.0481 53.691 ;
		END

		ANTENNADIFFAREA 0.00194719 ;
		ANTENNAPARTIALMETALAREA 0.00195671 ;
	END QB[56]

	PIN QB[57]
		USE SIGNAL ;
		DIRECTION OUTPUT ;
		SHAPE ABUTMENT ;
		PORT
			 LAYER M2 ;
			RECT 0.0098 54.4439 0.0481 54.4816 ;
		END

		ANTENNADIFFAREA 0.00194719 ;
		ANTENNAPARTIALMETALAREA 0.00195671 ;
	END QB[57]

	PIN QB[58]
		USE SIGNAL ;
		DIRECTION OUTPUT ;
		SHAPE ABUTMENT ;
		PORT
			 LAYER M2 ;
			RECT 0.0098 55.2345 0.0481 55.2722 ;
		END

		ANTENNADIFFAREA 0.00194719 ;
		ANTENNAPARTIALMETALAREA 0.00195671 ;
	END QB[58]

	PIN QB[59]
		USE SIGNAL ;
		DIRECTION OUTPUT ;
		SHAPE ABUTMENT ;
		PORT
			 LAYER M2 ;
			RECT 0.0098 56.0251 0.0481 56.0627 ;
		END

		ANTENNADIFFAREA 0.00194719 ;
		ANTENNAPARTIALMETALAREA 0.00195671 ;
	END QB[59]

	PIN QB[5]
		USE SIGNAL ;
		DIRECTION OUTPUT ;
		SHAPE ABUTMENT ;
		PORT
			 LAYER M2 ;
			RECT 0.0098 4.7937 0.0481 4.8314 ;
		END

		ANTENNADIFFAREA 0.00194719 ;
		ANTENNAPARTIALMETALAREA 0.00195671 ;
	END QB[5]

	PIN QB[60]
		USE SIGNAL ;
		DIRECTION OUTPUT ;
		SHAPE ABUTMENT ;
		PORT
			 LAYER M2 ;
			RECT 0.0098 56.8157 0.0481 56.8533 ;
		END

		ANTENNADIFFAREA 0.00194719 ;
		ANTENNAPARTIALMETALAREA 0.00195671 ;
	END QB[60]

	PIN QB[61]
		USE SIGNAL ;
		DIRECTION OUTPUT ;
		SHAPE ABUTMENT ;
		PORT
			 LAYER M2 ;
			RECT 0.0098 57.6063 0.0481 57.6439 ;
		END

		ANTENNADIFFAREA 0.00194719 ;
		ANTENNAPARTIALMETALAREA 0.00195671 ;
	END QB[61]

	PIN QB[62]
		USE SIGNAL ;
		DIRECTION OUTPUT ;
		SHAPE ABUTMENT ;
		PORT
			 LAYER M2 ;
			RECT 0.0098 58.3969 0.0481 58.4345 ;
		END

		ANTENNADIFFAREA 0.00194719 ;
		ANTENNAPARTIALMETALAREA 0.00195671 ;
	END QB[62]

	PIN QB[63]
		USE SIGNAL ;
		DIRECTION OUTPUT ;
		SHAPE ABUTMENT ;
		PORT
			 LAYER M2 ;
			RECT 0.0098 59.1875 0.0481 59.2251 ;
		END

		ANTENNADIFFAREA 0.00194719 ;
		ANTENNAPARTIALMETALAREA 0.00195671 ;
	END QB[63]

	PIN QB[64]
		USE SIGNAL ;
		DIRECTION OUTPUT ;
		SHAPE ABUTMENT ;
		PORT
			 LAYER M2 ;
			RECT 0.0098 59.978 0.0481 60.0157 ;
		END

		ANTENNADIFFAREA 0.00194719 ;
		ANTENNAPARTIALMETALAREA 0.00195671 ;
	END QB[64]

	PIN QB[65]
		USE SIGNAL ;
		DIRECTION OUTPUT ;
		SHAPE ABUTMENT ;
		PORT
			 LAYER M2 ;
			RECT 0.0098 60.7686 0.0481 60.8063 ;
		END

		ANTENNADIFFAREA 0.00194719 ;
		ANTENNAPARTIALMETALAREA 0.00195671 ;
	END QB[65]

	PIN QB[6]
		USE SIGNAL ;
		DIRECTION OUTPUT ;
		SHAPE ABUTMENT ;
		PORT
			 LAYER M2 ;
			RECT 0.0098 5.5843 0.0481 5.622 ;
		END

		ANTENNADIFFAREA 0.00194719 ;
		ANTENNAPARTIALMETALAREA 0.00195671 ;
	END QB[6]

	PIN QB[7]
		USE SIGNAL ;
		DIRECTION OUTPUT ;
		SHAPE ABUTMENT ;
		PORT
			 LAYER M2 ;
			RECT 0.0098 6.3749 0.0481 6.4125 ;
		END

		ANTENNADIFFAREA 0.00194719 ;
		ANTENNAPARTIALMETALAREA 0.00195671 ;
	END QB[7]

	PIN QB[8]
		USE SIGNAL ;
		DIRECTION OUTPUT ;
		SHAPE ABUTMENT ;
		PORT
			 LAYER M2 ;
			RECT 0.0098 7.1655 0.0481 7.2031 ;
		END

		ANTENNADIFFAREA 0.00194719 ;
		ANTENNAPARTIALMETALAREA 0.00195671 ;
	END QB[8]

	PIN QB[9]
		USE SIGNAL ;
		DIRECTION OUTPUT ;
		SHAPE ABUTMENT ;
		PORT
			 LAYER M2 ;
			RECT 0.0098 7.9561 0.0481 7.9937 ;
		END

		ANTENNADIFFAREA 0.00194719 ;
		ANTENNAPARTIALMETALAREA 0.00195671 ;
	END QB[9]

	PIN RET1N
		USE SIGNAL ;
		DIRECTION INPUT ;
		SHAPE ABUTMENT ;
		PORT
			 LAYER M2 ;
			RECT 0.0098 29.0761 0.0481 29.1137 ;
		END

		ANTENNAGATEAREA 0.00027817 ;
		ANTENNADIFFAREA 0.00194719 ;
		ANTENNAPARTIALMETALAREA 0.00195671 ;
	END RET1N

	PIN SE
		USE SIGNAL ;
		DIRECTION INPUT ;
		SHAPE ABUTMENT ;
		PORT
			 LAYER M2 ;
			RECT 0.0098 34.1333 0.0481 34.171 ;
		END

		ANTENNAGATEAREA 0.00027817 ;
		ANTENNADIFFAREA 0.00194719 ;
		ANTENNAPARTIALMETALAREA 0.00195671 ;
	END SE

	PIN SIA[0]
		USE SIGNAL ;
		DIRECTION INPUT ;
		SHAPE ABUTMENT ;
		PORT
			 LAYER M2 ;
			RECT 0.0714 0.1506 0.1097 0.1882 ;
			 LAYER M3 ;
			RECT 0.0714 0.0878 0.1097 0.1882 ;
			 LAYER V2 ;
			RECT 0.0831 0.1635 0.098 0.1761 ;
		END

		ANTENNAGATEAREA 0.00027817 ;
		ANTENNADIFFAREA 0.00194719 ;
		ANTENNAPARTIALMETALAREA 0.00195671 ;
	END SIA[0]

	PIN SIA[1]
		USE SIGNAL ;
		DIRECTION INPUT ;
		SHAPE ABUTMENT ;
		PORT
			 LAYER M2 ;
			RECT 0.0714 61.4588 0.1097 61.4965 ;
			 LAYER M3 ;
			RECT 0.0714 61.4588 0.1097 61.5592 ;
			 LAYER V2 ;
			RECT 0.0831 61.471 0.098 61.4835 ;
		END

		ANTENNAGATEAREA 0.00027817 ;
		ANTENNADIFFAREA 0.00194719 ;
		ANTENNAPARTIALMETALAREA 0.00195671 ;
	END SIA[1]

	PIN SIB[0]
		USE SIGNAL ;
		DIRECTION INPUT ;
		SHAPE ABUTMENT ;
		PORT
			 LAYER M2 ;
			RECT 0.0098 0.0878 0.0481 0.1255 ;
			 LAYER M3 ;
			RECT 0.0098 0.0878 0.0481 0.1882 ;
			 LAYER V2 ;
			RECT 0.0215 0.1008 0.0364 0.1133 ;
		END

		ANTENNAGATEAREA 0.00027817 ;
		ANTENNADIFFAREA 0.00194719 ;
		ANTENNAPARTIALMETALAREA 0.00195671 ;
	END SIB[0]

	PIN SIB[1]
		USE SIGNAL ;
		DIRECTION INPUT ;
		SHAPE ABUTMENT ;
		PORT
			 LAYER M2 ;
			RECT 0.0098 61.5216 0.0481 61.5592 ;
			 LAYER M3 ;
			RECT 0.0098 61.4588 0.0481 61.5592 ;
			 LAYER V2 ;
			RECT 0.0215 61.5337 0.0364 61.5463 ;
		END

		ANTENNAGATEAREA 0.00027817 ;
		ANTENNADIFFAREA 0.00194719 ;
		ANTENNAPARTIALMETALAREA 0.00195671 ;
	END SIB[1]

	PIN SOA[0]
		USE SIGNAL ;
		DIRECTION OUTPUT ;
		SHAPE ABUTMENT ;
		PORT
			 LAYER M3 ;
			RECT 0.0714 27.6204 0.1097 27.7208 ;
		END

		ANTENNADIFFAREA 0.00194719 ;
		ANTENNAPARTIALMETALAREA 0.00195671 ;
	END SOA[0]

	PIN SOA[1]
		USE SIGNAL ;
		DIRECTION OUTPUT ;
		SHAPE ABUTMENT ;
		PORT
			 LAYER M3 ;
			RECT 0.0714 34.2212 0.1097 34.3216 ;
		END

		ANTENNADIFFAREA 0.00194719 ;
		ANTENNAPARTIALMETALAREA 0.00195671 ;
	END SOA[1]

	PIN SOB[0]
		USE SIGNAL ;
		DIRECTION OUTPUT ;
		SHAPE ABUTMENT ;
		PORT
			 LAYER M2 ;
			RECT 0.0714 28.4988 0.1097 28.5365 ;
			 LAYER M3 ;
			RECT 0.0714 28.4988 0.1097 28.5992 ;
			 LAYER V2 ;
			RECT 0.0831 28.511 0.098 28.5235 ;
		END

		ANTENNADIFFAREA 0.00194719 ;
		ANTENNAPARTIALMETALAREA 0.00195671 ;
	END SOB[0]

	PIN SOB[1]
		USE SIGNAL ;
		DIRECTION OUTPUT ;
		SHAPE ABUTMENT ;
		PORT
			 LAYER M2 ;
			RECT 0.0714 29.44 0.1097 29.4776 ;
			 LAYER M3 ;
			RECT 0.0714 29.3773 0.1097 29.4776 ;
			 LAYER V2 ;
			RECT 0.0831 29.4529 0.098 29.4655 ;
		END

		ANTENNADIFFAREA 0.00194719 ;
		ANTENNAPARTIALMETALAREA 0.00195671 ;
	END SOB[1]

	PIN STOV
		USE SIGNAL ;
		DIRECTION INPUT ;
		SHAPE ABUTMENT ;
		PORT
			 LAYER M2 ;
			RECT 0.0098 29.7161 0.0481 29.7537 ;
		END

		ANTENNAGATEAREA 0.00027817 ;
		ANTENNADIFFAREA 0.00194719 ;
		ANTENNAPARTIALMETALAREA 0.00195671 ;
	END STOV

	PIN STOVAB
		USE SIGNAL ;
		DIRECTION INPUT ;
		SHAPE ABUTMENT ;
		PORT
			 LAYER M3 ;
			RECT 0.0714 31.1843 0.1097 31.2847 ;
		END

		ANTENNAGATEAREA 0.00027817 ;
		ANTENNADIFFAREA 0.00194719 ;
		ANTENNAPARTIALMETALAREA 0.00195671 ;
	END STOVAB

	PIN TAA[0]
		USE SIGNAL ;
		DIRECTION INPUT ;
		SHAPE ABUTMENT ;
		PORT
			 LAYER M2 ;
			RECT 0.0098 30.1678 0.0481 30.2055 ;
		END

		ANTENNAGATEAREA 0.00027817 ;
		ANTENNADIFFAREA 0.00194719 ;
		ANTENNAPARTIALMETALAREA 0.00195671 ;
	END TAA[0]

	PIN TAA[1]
		USE SIGNAL ;
		DIRECTION INPUT ;
		SHAPE ABUTMENT ;
		PORT
			 LAYER M2 ;
			RECT 0.0098 30.5067 0.0481 30.5443 ;
		END

		ANTENNAGATEAREA 0.00027817 ;
		ANTENNADIFFAREA 0.00194719 ;
		ANTENNAPARTIALMETALAREA 0.00195671 ;
	END TAA[1]

	PIN TAA[2]
		USE SIGNAL ;
		DIRECTION INPUT ;
		SHAPE ABUTMENT ;
		PORT
			 LAYER M3 ;
			RECT 0.0714 34.3718 0.1097 34.4722 ;
		END

		ANTENNAGATEAREA 0.00027817 ;
		ANTENNADIFFAREA 0.00194719 ;
		ANTENNAPARTIALMETALAREA 0.00195671 ;
	END TAA[2]

	PIN TAA[3]
		USE SIGNAL ;
		DIRECTION INPUT ;
		SHAPE ABUTMENT ;
		PORT
			 LAYER M2 ;
			RECT 0.0098 31.7741 0.0481 31.8118 ;
		END

		ANTENNAGATEAREA 0.00027817 ;
		ANTENNADIFFAREA 0.00194719 ;
		ANTENNAPARTIALMETALAREA 0.00195671 ;
	END TAA[3]

	PIN TAA[4]
		USE SIGNAL ;
		DIRECTION INPUT ;
		SHAPE ABUTMENT ;
		PORT
			 LAYER M2 ;
			RECT 0.0098 32.0878 0.0481 32.1255 ;
		END

		ANTENNAGATEAREA 0.00027817 ;
		ANTENNADIFFAREA 0.00194719 ;
		ANTENNAPARTIALMETALAREA 0.00195671 ;
	END TAA[4]

	PIN TAA[5]
		USE SIGNAL ;
		DIRECTION INPUT ;
		SHAPE ABUTMENT ;
		PORT
			 LAYER M2 ;
			RECT 0.0098 32.3012 0.0481 32.3388 ;
		END

		ANTENNAGATEAREA 0.00027817 ;
		ANTENNADIFFAREA 0.00194719 ;
		ANTENNAPARTIALMETALAREA 0.00195671 ;
	END TAA[5]

	PIN TAA[6]
		USE SIGNAL ;
		DIRECTION INPUT ;
		SHAPE ABUTMENT ;
		PORT
			 LAYER M2 ;
			RECT 0.0098 32.6149 0.0481 32.6525 ;
		END

		ANTENNAGATEAREA 0.00027817 ;
		ANTENNADIFFAREA 0.00194719 ;
		ANTENNAPARTIALMETALAREA 0.00195671 ;
	END TAA[6]

	PIN TAA[7]
		USE SIGNAL ;
		DIRECTION INPUT ;
		SHAPE ABUTMENT ;
		PORT
			 LAYER M2 ;
			RECT 0.0098 32.8282 0.0481 32.8659 ;
		END

		ANTENNAGATEAREA 0.00027817 ;
		ANTENNADIFFAREA 0.00194719 ;
		ANTENNAPARTIALMETALAREA 0.00195671 ;
	END TAA[7]

	PIN TAA[8]
		USE SIGNAL ;
		DIRECTION INPUT ;
		SHAPE ABUTMENT ;
		PORT
			 LAYER M2 ;
			RECT 0.0098 33.142 0.0481 33.1796 ;
		END

		ANTENNAGATEAREA 0.00027817 ;
		ANTENNADIFFAREA 0.00194719 ;
		ANTENNAPARTIALMETALAREA 0.00195671 ;
	END TAA[8]

	PIN TAA[9]
		USE SIGNAL ;
		DIRECTION INPUT ;
		SHAPE ABUTMENT ;
		PORT
			 LAYER M2 ;
			RECT 0.0098 33.3553 0.0481 33.3929 ;
		END

		ANTENNAGATEAREA 0.00027817 ;
		ANTENNADIFFAREA 0.00194719 ;
		ANTENNAPARTIALMETALAREA 0.00195671 ;
	END TAA[9]

	PIN TAB[0]
		USE SIGNAL ;
		DIRECTION INPUT ;
		SHAPE ABUTMENT ;
		PORT
			 LAYER M2 ;
			RECT 0.0098 30.1051 0.0481 30.1427 ;
		END

		ANTENNAGATEAREA 0.00027817 ;
		ANTENNADIFFAREA 0.00194719 ;
		ANTENNAPARTIALMETALAREA 0.00195671 ;
	END TAB[0]

	PIN TAB[1]
		USE SIGNAL ;
		DIRECTION INPUT ;
		SHAPE ABUTMENT ;
		PORT
			 LAYER M2 ;
			RECT 0.0098 30.5694 0.0481 30.6071 ;
		END

		ANTENNAGATEAREA 0.00027817 ;
		ANTENNADIFFAREA 0.00194719 ;
		ANTENNAPARTIALMETALAREA 0.00195671 ;
	END TAB[1]

	PIN TAB[2]
		USE SIGNAL ;
		DIRECTION INPUT ;
		SHAPE ABUTMENT ;
		PORT
			 LAYER M3 ;
			RECT 0.0714 31.5608 0.1097 31.6612 ;
		END

		ANTENNAGATEAREA 0.00027817 ;
		ANTENNADIFFAREA 0.00194719 ;
		ANTENNAPARTIALMETALAREA 0.00195671 ;
	END TAB[2]

	PIN TAB[3]
		USE SIGNAL ;
		DIRECTION INPUT ;
		SHAPE ABUTMENT ;
		PORT
			 LAYER M2 ;
			RECT 0.0098 31.7114 0.0481 31.749 ;
		END

		ANTENNAGATEAREA 0.00027817 ;
		ANTENNADIFFAREA 0.00194719 ;
		ANTENNAPARTIALMETALAREA 0.00195671 ;
	END TAB[3]

	PIN TAB[4]
		USE SIGNAL ;
		DIRECTION INPUT ;
		SHAPE ABUTMENT ;
		PORT
			 LAYER M2 ;
			RECT 0.0098 32.1506 0.0481 32.1882 ;
		END

		ANTENNAGATEAREA 0.00027817 ;
		ANTENNADIFFAREA 0.00194719 ;
		ANTENNAPARTIALMETALAREA 0.00195671 ;
	END TAB[4]

	PIN TAB[5]
		USE SIGNAL ;
		DIRECTION INPUT ;
		SHAPE ABUTMENT ;
		PORT
			 LAYER M2 ;
			RECT 0.0098 32.2384 0.0481 32.2761 ;
		END

		ANTENNAGATEAREA 0.00027817 ;
		ANTENNADIFFAREA 0.00194719 ;
		ANTENNAPARTIALMETALAREA 0.00195671 ;
	END TAB[5]

	PIN TAB[6]
		USE SIGNAL ;
		DIRECTION INPUT ;
		SHAPE ABUTMENT ;
		PORT
			 LAYER M2 ;
			RECT 0.0098 32.6776 0.0481 32.7153 ;
		END

		ANTENNAGATEAREA 0.00027817 ;
		ANTENNADIFFAREA 0.00194719 ;
		ANTENNAPARTIALMETALAREA 0.00195671 ;
	END TAB[6]

	PIN TAB[7]
		USE SIGNAL ;
		DIRECTION INPUT ;
		SHAPE ABUTMENT ;
		PORT
			 LAYER M2 ;
			RECT 0.0098 32.7655 0.0481 32.8031 ;
		END

		ANTENNAGATEAREA 0.00027817 ;
		ANTENNADIFFAREA 0.00194719 ;
		ANTENNAPARTIALMETALAREA 0.00195671 ;
	END TAB[7]

	PIN TAB[8]
		USE SIGNAL ;
		DIRECTION INPUT ;
		SHAPE ABUTMENT ;
		PORT
			 LAYER M2 ;
			RECT 0.0098 33.2047 0.0481 33.2424 ;
		END

		ANTENNAGATEAREA 0.00027817 ;
		ANTENNADIFFAREA 0.00194719 ;
		ANTENNAPARTIALMETALAREA 0.00195671 ;
	END TAB[8]

	PIN TAB[9]
		USE SIGNAL ;
		DIRECTION INPUT ;
		SHAPE ABUTMENT ;
		PORT
			 LAYER M2 ;
			RECT 0.0098 33.2925 0.0481 33.3302 ;
		END

		ANTENNAGATEAREA 0.00027817 ;
		ANTENNADIFFAREA 0.00194719 ;
		ANTENNAPARTIALMETALAREA 0.00195671 ;
	END TAB[9]

	PIN TCENA
		USE SIGNAL ;
		DIRECTION INPUT ;
		SHAPE ABUTMENT ;
		PORT
			 LAYER M2 ;
			RECT 0.0098 33.669 0.0481 33.7067 ;
		END

		ANTENNAGATEAREA 0.00027817 ;
		ANTENNADIFFAREA 0.00194719 ;
		ANTENNAPARTIALMETALAREA 0.00195671 ;
	END TCENA

	PIN TCENB
		USE SIGNAL ;
		DIRECTION INPUT ;
		SHAPE ABUTMENT ;
		PORT
			 LAYER M2 ;
			RECT 0.0098 33.7318 0.0481 33.7694 ;
		END

		ANTENNAGATEAREA 0.00027817 ;
		ANTENNADIFFAREA 0.00194719 ;
		ANTENNAPARTIALMETALAREA 0.00195671 ;
	END TCENB

	PIN TDA[0]
		USE SIGNAL ;
		DIRECTION INPUT ;
		SHAPE ABUTMENT ;
		PORT
			 LAYER M2 ;
			RECT 0.0714 0.6651 0.1097 0.7027 ;
			 LAYER M3 ;
			RECT 0.0714 0.6651 0.1097 0.7655 ;
			 LAYER V2 ;
			RECT 0.0831 0.6773 0.098 0.6898 ;
		END

		ANTENNAGATEAREA 0.00027817 ;
		ANTENNADIFFAREA 0.00194719 ;
		ANTENNAPARTIALMETALAREA 0.00195671 ;
	END TDA[0]

	PIN TDA[10]
		USE SIGNAL ;
		DIRECTION INPUT ;
		SHAPE ABUTMENT ;
		PORT
			 LAYER M2 ;
			RECT 0.0714 8.571 0.1097 8.6086 ;
			 LAYER M3 ;
			RECT 0.0714 8.571 0.1097 8.6714 ;
			 LAYER V2 ;
			RECT 0.0831 8.5831 0.098 8.5957 ;
		END

		ANTENNAGATEAREA 0.00027817 ;
		ANTENNADIFFAREA 0.00194719 ;
		ANTENNAPARTIALMETALAREA 0.00195671 ;
	END TDA[10]

	PIN TDA[11]
		USE SIGNAL ;
		DIRECTION INPUT ;
		SHAPE ABUTMENT ;
		PORT
			 LAYER M2 ;
			RECT 0.0714 9.3616 0.1097 9.3992 ;
			 LAYER M3 ;
			RECT 0.0714 9.3616 0.1097 9.462 ;
			 LAYER V2 ;
			RECT 0.0831 9.3737 0.098 9.3863 ;
		END

		ANTENNAGATEAREA 0.00027817 ;
		ANTENNADIFFAREA 0.00194719 ;
		ANTENNAPARTIALMETALAREA 0.00195671 ;
	END TDA[11]

	PIN TDA[12]
		USE SIGNAL ;
		DIRECTION INPUT ;
		SHAPE ABUTMENT ;
		PORT
			 LAYER M2 ;
			RECT 0.0714 10.1522 0.1097 10.1898 ;
			 LAYER M3 ;
			RECT 0.0714 10.1522 0.1097 10.2525 ;
			 LAYER V2 ;
			RECT 0.0831 10.1643 0.098 10.1769 ;
		END

		ANTENNAGATEAREA 0.00027817 ;
		ANTENNADIFFAREA 0.00194719 ;
		ANTENNAPARTIALMETALAREA 0.00195671 ;
	END TDA[12]

	PIN TDA[13]
		USE SIGNAL ;
		DIRECTION INPUT ;
		SHAPE ABUTMENT ;
		PORT
			 LAYER M2 ;
			RECT 0.0714 10.9427 0.1097 10.9804 ;
			 LAYER M3 ;
			RECT 0.0714 10.9427 0.1097 11.0431 ;
			 LAYER V2 ;
			RECT 0.0831 10.9549 0.098 10.9675 ;
		END

		ANTENNAGATEAREA 0.00027817 ;
		ANTENNADIFFAREA 0.00194719 ;
		ANTENNAPARTIALMETALAREA 0.00195671 ;
	END TDA[13]

	PIN TDA[14]
		USE SIGNAL ;
		DIRECTION INPUT ;
		SHAPE ABUTMENT ;
		PORT
			 LAYER M2 ;
			RECT 0.0714 11.7333 0.1097 11.771 ;
			 LAYER M3 ;
			RECT 0.0714 11.7333 0.1097 11.8337 ;
			 LAYER V2 ;
			RECT 0.0831 11.7455 0.098 11.758 ;
		END

		ANTENNAGATEAREA 0.00027817 ;
		ANTENNADIFFAREA 0.00194719 ;
		ANTENNAPARTIALMETALAREA 0.00195671 ;
	END TDA[14]

	PIN TDA[15]
		USE SIGNAL ;
		DIRECTION INPUT ;
		SHAPE ABUTMENT ;
		PORT
			 LAYER M2 ;
			RECT 0.0714 12.5239 0.1097 12.5616 ;
			 LAYER M3 ;
			RECT 0.0714 12.5239 0.1097 12.6243 ;
			 LAYER V2 ;
			RECT 0.0831 12.5361 0.098 12.5486 ;
		END

		ANTENNAGATEAREA 0.00027817 ;
		ANTENNADIFFAREA 0.00194719 ;
		ANTENNAPARTIALMETALAREA 0.00195671 ;
	END TDA[15]

	PIN TDA[16]
		USE SIGNAL ;
		DIRECTION INPUT ;
		SHAPE ABUTMENT ;
		PORT
			 LAYER M2 ;
			RECT 0.0714 13.3145 0.1097 13.3522 ;
			 LAYER M3 ;
			RECT 0.0714 13.3145 0.1097 13.4149 ;
			 LAYER V2 ;
			RECT 0.0831 13.3267 0.098 13.3392 ;
		END

		ANTENNAGATEAREA 0.00027817 ;
		ANTENNADIFFAREA 0.00194719 ;
		ANTENNAPARTIALMETALAREA 0.00195671 ;
	END TDA[16]

	PIN TDA[17]
		USE SIGNAL ;
		DIRECTION INPUT ;
		SHAPE ABUTMENT ;
		PORT
			 LAYER M2 ;
			RECT 0.0714 14.1051 0.1097 14.1427 ;
			 LAYER M3 ;
			RECT 0.0714 14.1051 0.1097 14.2055 ;
			 LAYER V2 ;
			RECT 0.0831 14.1173 0.098 14.1298 ;
		END

		ANTENNAGATEAREA 0.00027817 ;
		ANTENNADIFFAREA 0.00194719 ;
		ANTENNAPARTIALMETALAREA 0.00195671 ;
	END TDA[17]

	PIN TDA[18]
		USE SIGNAL ;
		DIRECTION INPUT ;
		SHAPE ABUTMENT ;
		PORT
			 LAYER M2 ;
			RECT 0.0714 14.8957 0.1097 14.9333 ;
			 LAYER M3 ;
			RECT 0.0714 14.8957 0.1097 14.9961 ;
			 LAYER V2 ;
			RECT 0.0831 14.9078 0.098 14.9204 ;
		END

		ANTENNAGATEAREA 0.00027817 ;
		ANTENNADIFFAREA 0.00194719 ;
		ANTENNAPARTIALMETALAREA 0.00195671 ;
	END TDA[18]

	PIN TDA[19]
		USE SIGNAL ;
		DIRECTION INPUT ;
		SHAPE ABUTMENT ;
		PORT
			 LAYER M2 ;
			RECT 0.0714 15.6863 0.1097 15.7239 ;
			 LAYER M3 ;
			RECT 0.0714 15.6863 0.1097 15.7867 ;
			 LAYER V2 ;
			RECT 0.0831 15.6984 0.098 15.711 ;
		END

		ANTENNAGATEAREA 0.00027817 ;
		ANTENNADIFFAREA 0.00194719 ;
		ANTENNAPARTIALMETALAREA 0.00195671 ;
	END TDA[19]

	PIN TDA[1]
		USE SIGNAL ;
		DIRECTION INPUT ;
		SHAPE ABUTMENT ;
		PORT
			 LAYER M2 ;
			RECT 0.0714 1.4557 0.1097 1.4933 ;
			 LAYER M3 ;
			RECT 0.0714 1.4557 0.1097 1.5561 ;
			 LAYER V2 ;
			RECT 0.0831 1.4678 0.098 1.4804 ;
		END

		ANTENNAGATEAREA 0.00027817 ;
		ANTENNADIFFAREA 0.00194719 ;
		ANTENNAPARTIALMETALAREA 0.00195671 ;
	END TDA[1]

	PIN TDA[20]
		USE SIGNAL ;
		DIRECTION INPUT ;
		SHAPE ABUTMENT ;
		PORT
			 LAYER M2 ;
			RECT 0.0714 16.4769 0.1097 16.5145 ;
			 LAYER M3 ;
			RECT 0.0714 16.4769 0.1097 16.5773 ;
			 LAYER V2 ;
			RECT 0.0831 16.489 0.098 16.5016 ;
		END

		ANTENNAGATEAREA 0.00027817 ;
		ANTENNADIFFAREA 0.00194719 ;
		ANTENNAPARTIALMETALAREA 0.00195671 ;
	END TDA[20]

	PIN TDA[21]
		USE SIGNAL ;
		DIRECTION INPUT ;
		SHAPE ABUTMENT ;
		PORT
			 LAYER M2 ;
			RECT 0.0714 17.2675 0.1097 17.3051 ;
			 LAYER M3 ;
			RECT 0.0714 17.2675 0.1097 17.3678 ;
			 LAYER V2 ;
			RECT 0.0831 17.2796 0.098 17.2922 ;
		END

		ANTENNAGATEAREA 0.00027817 ;
		ANTENNADIFFAREA 0.00194719 ;
		ANTENNAPARTIALMETALAREA 0.00195671 ;
	END TDA[21]

	PIN TDA[22]
		USE SIGNAL ;
		DIRECTION INPUT ;
		SHAPE ABUTMENT ;
		PORT
			 LAYER M2 ;
			RECT 0.0714 18.058 0.1097 18.0957 ;
			 LAYER M3 ;
			RECT 0.0714 18.058 0.1097 18.1584 ;
			 LAYER V2 ;
			RECT 0.0831 18.0702 0.098 18.0827 ;
		END

		ANTENNAGATEAREA 0.00027817 ;
		ANTENNADIFFAREA 0.00194719 ;
		ANTENNAPARTIALMETALAREA 0.00195671 ;
	END TDA[22]

	PIN TDA[23]
		USE SIGNAL ;
		DIRECTION INPUT ;
		SHAPE ABUTMENT ;
		PORT
			 LAYER M2 ;
			RECT 0.0714 18.8486 0.1097 18.8863 ;
			 LAYER M3 ;
			RECT 0.0714 18.8486 0.1097 18.949 ;
			 LAYER V2 ;
			RECT 0.0831 18.8608 0.098 18.8733 ;
		END

		ANTENNAGATEAREA 0.00027817 ;
		ANTENNADIFFAREA 0.00194719 ;
		ANTENNAPARTIALMETALAREA 0.00195671 ;
	END TDA[23]

	PIN TDA[24]
		USE SIGNAL ;
		DIRECTION INPUT ;
		SHAPE ABUTMENT ;
		PORT
			 LAYER M2 ;
			RECT 0.0714 19.6392 0.1097 19.6769 ;
			 LAYER M3 ;
			RECT 0.0714 19.6392 0.1097 19.7396 ;
			 LAYER V2 ;
			RECT 0.0831 19.6514 0.098 19.6639 ;
		END

		ANTENNAGATEAREA 0.00027817 ;
		ANTENNADIFFAREA 0.00194719 ;
		ANTENNAPARTIALMETALAREA 0.00195671 ;
	END TDA[24]

	PIN TDA[25]
		USE SIGNAL ;
		DIRECTION INPUT ;
		SHAPE ABUTMENT ;
		PORT
			 LAYER M2 ;
			RECT 0.0714 20.4298 0.1097 20.4675 ;
			 LAYER M3 ;
			RECT 0.0714 20.4298 0.1097 20.5302 ;
			 LAYER V2 ;
			RECT 0.0831 20.442 0.098 20.4545 ;
		END

		ANTENNAGATEAREA 0.00027817 ;
		ANTENNADIFFAREA 0.00194719 ;
		ANTENNAPARTIALMETALAREA 0.00195671 ;
	END TDA[25]

	PIN TDA[26]
		USE SIGNAL ;
		DIRECTION INPUT ;
		SHAPE ABUTMENT ;
		PORT
			 LAYER M2 ;
			RECT 0.0714 21.2204 0.1097 21.258 ;
			 LAYER M3 ;
			RECT 0.0714 21.2204 0.1097 21.3208 ;
			 LAYER V2 ;
			RECT 0.0831 21.2325 0.098 21.2451 ;
		END

		ANTENNAGATEAREA 0.00027817 ;
		ANTENNADIFFAREA 0.00194719 ;
		ANTENNAPARTIALMETALAREA 0.00195671 ;
	END TDA[26]

	PIN TDA[27]
		USE SIGNAL ;
		DIRECTION INPUT ;
		SHAPE ABUTMENT ;
		PORT
			 LAYER M2 ;
			RECT 0.0714 22.011 0.1097 22.0486 ;
			 LAYER M3 ;
			RECT 0.0714 22.011 0.1097 22.1114 ;
			 LAYER V2 ;
			RECT 0.0831 22.0231 0.098 22.0357 ;
		END

		ANTENNAGATEAREA 0.00027817 ;
		ANTENNADIFFAREA 0.00194719 ;
		ANTENNAPARTIALMETALAREA 0.00195671 ;
	END TDA[27]

	PIN TDA[28]
		USE SIGNAL ;
		DIRECTION INPUT ;
		SHAPE ABUTMENT ;
		PORT
			 LAYER M2 ;
			RECT 0.0714 22.8016 0.1097 22.8392 ;
			 LAYER M3 ;
			RECT 0.0714 22.8016 0.1097 22.902 ;
			 LAYER V2 ;
			RECT 0.0831 22.8137 0.098 22.8263 ;
		END

		ANTENNAGATEAREA 0.00027817 ;
		ANTENNADIFFAREA 0.00194719 ;
		ANTENNAPARTIALMETALAREA 0.00195671 ;
	END TDA[28]

	PIN TDA[29]
		USE SIGNAL ;
		DIRECTION INPUT ;
		SHAPE ABUTMENT ;
		PORT
			 LAYER M2 ;
			RECT 0.0714 23.5922 0.1097 23.6298 ;
			 LAYER M3 ;
			RECT 0.0714 23.5922 0.1097 23.6925 ;
			 LAYER V2 ;
			RECT 0.0831 23.6043 0.098 23.6169 ;
		END

		ANTENNAGATEAREA 0.00027817 ;
		ANTENNADIFFAREA 0.00194719 ;
		ANTENNAPARTIALMETALAREA 0.00195671 ;
	END TDA[29]

	PIN TDA[2]
		USE SIGNAL ;
		DIRECTION INPUT ;
		SHAPE ABUTMENT ;
		PORT
			 LAYER M2 ;
			RECT 0.0714 2.2463 0.1097 2.2839 ;
			 LAYER M3 ;
			RECT 0.0714 2.2463 0.1097 2.3467 ;
			 LAYER V2 ;
			RECT 0.0831 2.2584 0.098 2.271 ;
		END

		ANTENNAGATEAREA 0.00027817 ;
		ANTENNADIFFAREA 0.00194719 ;
		ANTENNAPARTIALMETALAREA 0.00195671 ;
	END TDA[2]

	PIN TDA[30]
		USE SIGNAL ;
		DIRECTION INPUT ;
		SHAPE ABUTMENT ;
		PORT
			 LAYER M2 ;
			RECT 0.0714 24.3827 0.1097 24.4204 ;
			 LAYER M3 ;
			RECT 0.0714 24.3827 0.1097 24.4831 ;
			 LAYER V2 ;
			RECT 0.0831 24.3949 0.098 24.4075 ;
		END

		ANTENNAGATEAREA 0.00027817 ;
		ANTENNADIFFAREA 0.00194719 ;
		ANTENNAPARTIALMETALAREA 0.00195671 ;
	END TDA[30]

	PIN TDA[31]
		USE SIGNAL ;
		DIRECTION INPUT ;
		SHAPE ABUTMENT ;
		PORT
			 LAYER M2 ;
			RECT 0.0714 25.1733 0.1097 25.211 ;
			 LAYER M3 ;
			RECT 0.0714 25.1733 0.1097 25.2737 ;
			 LAYER V2 ;
			RECT 0.0831 25.1855 0.098 25.198 ;
		END

		ANTENNAGATEAREA 0.00027817 ;
		ANTENNADIFFAREA 0.00194719 ;
		ANTENNAPARTIALMETALAREA 0.00195671 ;
	END TDA[31]

	PIN TDA[32]
		USE SIGNAL ;
		DIRECTION INPUT ;
		SHAPE ABUTMENT ;
		PORT
			 LAYER M2 ;
			RECT 0.0714 25.9639 0.1097 26.0016 ;
			 LAYER M3 ;
			RECT 0.0714 25.9639 0.1097 26.0643 ;
			 LAYER V2 ;
			RECT 0.0831 25.9761 0.098 25.9886 ;
		END

		ANTENNAGATEAREA 0.00027817 ;
		ANTENNADIFFAREA 0.00194719 ;
		ANTENNAPARTIALMETALAREA 0.00195671 ;
	END TDA[32]

	PIN TDA[33]
		USE SIGNAL ;
		DIRECTION INPUT ;
		SHAPE ABUTMENT ;
		PORT
			 LAYER M2 ;
			RECT 0.0714 35.6455 0.1097 35.6831 ;
			 LAYER M3 ;
			RECT 0.0714 35.5827 0.1097 35.6831 ;
			 LAYER V2 ;
			RECT 0.0831 35.6584 0.098 35.671 ;
		END

		ANTENNAGATEAREA 0.00027817 ;
		ANTENNADIFFAREA 0.00194719 ;
		ANTENNAPARTIALMETALAREA 0.00195671 ;
	END TDA[33]

	PIN TDA[34]
		USE SIGNAL ;
		DIRECTION INPUT ;
		SHAPE ABUTMENT ;
		PORT
			 LAYER M2 ;
			RECT 0.0714 36.4361 0.1097 36.4737 ;
			 LAYER M3 ;
			RECT 0.0714 36.3733 0.1097 36.4737 ;
			 LAYER V2 ;
			RECT 0.0831 36.449 0.098 36.4616 ;
		END

		ANTENNAGATEAREA 0.00027817 ;
		ANTENNADIFFAREA 0.00194719 ;
		ANTENNAPARTIALMETALAREA 0.00195671 ;
	END TDA[34]

	PIN TDA[35]
		USE SIGNAL ;
		DIRECTION INPUT ;
		SHAPE ABUTMENT ;
		PORT
			 LAYER M2 ;
			RECT 0.0714 37.2267 0.1097 37.2643 ;
			 LAYER M3 ;
			RECT 0.0714 37.1639 0.1097 37.2643 ;
			 LAYER V2 ;
			RECT 0.0831 37.2396 0.098 37.2522 ;
		END

		ANTENNAGATEAREA 0.00027817 ;
		ANTENNADIFFAREA 0.00194719 ;
		ANTENNAPARTIALMETALAREA 0.00195671 ;
	END TDA[35]

	PIN TDA[36]
		USE SIGNAL ;
		DIRECTION INPUT ;
		SHAPE ABUTMENT ;
		PORT
			 LAYER M2 ;
			RECT 0.0714 38.0173 0.1097 38.0549 ;
			 LAYER M3 ;
			RECT 0.0714 37.9545 0.1097 38.0549 ;
			 LAYER V2 ;
			RECT 0.0831 38.0302 0.098 38.0427 ;
		END

		ANTENNAGATEAREA 0.00027817 ;
		ANTENNADIFFAREA 0.00194719 ;
		ANTENNAPARTIALMETALAREA 0.00195671 ;
	END TDA[36]

	PIN TDA[37]
		USE SIGNAL ;
		DIRECTION INPUT ;
		SHAPE ABUTMENT ;
		PORT
			 LAYER M2 ;
			RECT 0.0714 38.8078 0.1097 38.8455 ;
			 LAYER M3 ;
			RECT 0.0714 38.7451 0.1097 38.8455 ;
			 LAYER V2 ;
			RECT 0.0831 38.8208 0.098 38.8333 ;
		END

		ANTENNAGATEAREA 0.00027817 ;
		ANTENNADIFFAREA 0.00194719 ;
		ANTENNAPARTIALMETALAREA 0.00195671 ;
	END TDA[37]

	PIN TDA[38]
		USE SIGNAL ;
		DIRECTION INPUT ;
		SHAPE ABUTMENT ;
		PORT
			 LAYER M2 ;
			RECT 0.0714 39.5984 0.1097 39.6361 ;
			 LAYER M3 ;
			RECT 0.0714 39.5357 0.1097 39.6361 ;
			 LAYER V2 ;
			RECT 0.0831 39.6114 0.098 39.6239 ;
		END

		ANTENNAGATEAREA 0.00027817 ;
		ANTENNADIFFAREA 0.00194719 ;
		ANTENNAPARTIALMETALAREA 0.00195671 ;
	END TDA[38]

	PIN TDA[39]
		USE SIGNAL ;
		DIRECTION INPUT ;
		SHAPE ABUTMENT ;
		PORT
			 LAYER M2 ;
			RECT 0.0714 40.389 0.1097 40.4267 ;
			 LAYER M3 ;
			RECT 0.0714 40.3263 0.1097 40.4267 ;
			 LAYER V2 ;
			RECT 0.0831 40.402 0.098 40.4145 ;
		END

		ANTENNAGATEAREA 0.00027817 ;
		ANTENNADIFFAREA 0.00194719 ;
		ANTENNAPARTIALMETALAREA 0.00195671 ;
	END TDA[39]

	PIN TDA[3]
		USE SIGNAL ;
		DIRECTION INPUT ;
		SHAPE ABUTMENT ;
		PORT
			 LAYER M2 ;
			RECT 0.0714 3.0369 0.1097 3.0745 ;
			 LAYER M3 ;
			RECT 0.0714 3.0369 0.1097 3.1373 ;
			 LAYER V2 ;
			RECT 0.0831 3.049 0.098 3.0616 ;
		END

		ANTENNAGATEAREA 0.00027817 ;
		ANTENNADIFFAREA 0.00194719 ;
		ANTENNAPARTIALMETALAREA 0.00195671 ;
	END TDA[3]

	PIN TDA[40]
		USE SIGNAL ;
		DIRECTION INPUT ;
		SHAPE ABUTMENT ;
		PORT
			 LAYER M2 ;
			RECT 0.0714 41.1796 0.1097 41.2173 ;
			 LAYER M3 ;
			RECT 0.0714 41.1169 0.1097 41.2173 ;
			 LAYER V2 ;
			RECT 0.0831 41.1925 0.098 41.2051 ;
		END

		ANTENNAGATEAREA 0.00027817 ;
		ANTENNADIFFAREA 0.00194719 ;
		ANTENNAPARTIALMETALAREA 0.00195671 ;
	END TDA[40]

	PIN TDA[41]
		USE SIGNAL ;
		DIRECTION INPUT ;
		SHAPE ABUTMENT ;
		PORT
			 LAYER M2 ;
			RECT 0.0714 41.9702 0.1097 42.0078 ;
			 LAYER M3 ;
			RECT 0.0714 41.9075 0.1097 42.0078 ;
			 LAYER V2 ;
			RECT 0.0831 41.9831 0.098 41.9957 ;
		END

		ANTENNAGATEAREA 0.00027817 ;
		ANTENNADIFFAREA 0.00194719 ;
		ANTENNAPARTIALMETALAREA 0.00195671 ;
	END TDA[41]

	PIN TDA[42]
		USE SIGNAL ;
		DIRECTION INPUT ;
		SHAPE ABUTMENT ;
		PORT
			 LAYER M2 ;
			RECT 0.0714 42.7608 0.1097 42.7984 ;
			 LAYER M3 ;
			RECT 0.0714 42.698 0.1097 42.7984 ;
			 LAYER V2 ;
			RECT 0.0831 42.7737 0.098 42.7863 ;
		END

		ANTENNAGATEAREA 0.00027817 ;
		ANTENNADIFFAREA 0.00194719 ;
		ANTENNAPARTIALMETALAREA 0.00195671 ;
	END TDA[42]

	PIN TDA[43]
		USE SIGNAL ;
		DIRECTION INPUT ;
		SHAPE ABUTMENT ;
		PORT
			 LAYER M2 ;
			RECT 0.0714 43.5514 0.1097 43.589 ;
			 LAYER M3 ;
			RECT 0.0714 43.4886 0.1097 43.589 ;
			 LAYER V2 ;
			RECT 0.0831 43.5643 0.098 43.5769 ;
		END

		ANTENNAGATEAREA 0.00027817 ;
		ANTENNADIFFAREA 0.00194719 ;
		ANTENNAPARTIALMETALAREA 0.00195671 ;
	END TDA[43]

	PIN TDA[44]
		USE SIGNAL ;
		DIRECTION INPUT ;
		SHAPE ABUTMENT ;
		PORT
			 LAYER M2 ;
			RECT 0.0714 44.342 0.1097 44.3796 ;
			 LAYER M3 ;
			RECT 0.0714 44.2792 0.1097 44.3796 ;
			 LAYER V2 ;
			RECT 0.0831 44.3549 0.098 44.3675 ;
		END

		ANTENNAGATEAREA 0.00027817 ;
		ANTENNADIFFAREA 0.00194719 ;
		ANTENNAPARTIALMETALAREA 0.00195671 ;
	END TDA[44]

	PIN TDA[45]
		USE SIGNAL ;
		DIRECTION INPUT ;
		SHAPE ABUTMENT ;
		PORT
			 LAYER M2 ;
			RECT 0.0714 45.1325 0.1097 45.1702 ;
			 LAYER M3 ;
			RECT 0.0714 45.0698 0.1097 45.1702 ;
			 LAYER V2 ;
			RECT 0.0831 45.1455 0.098 45.158 ;
		END

		ANTENNAGATEAREA 0.00027817 ;
		ANTENNADIFFAREA 0.00194719 ;
		ANTENNAPARTIALMETALAREA 0.00195671 ;
	END TDA[45]

	PIN TDA[46]
		USE SIGNAL ;
		DIRECTION INPUT ;
		SHAPE ABUTMENT ;
		PORT
			 LAYER M2 ;
			RECT 0.0714 45.9231 0.1097 45.9608 ;
			 LAYER M3 ;
			RECT 0.0714 45.8604 0.1097 45.9608 ;
			 LAYER V2 ;
			RECT 0.0831 45.9361 0.098 45.9486 ;
		END

		ANTENNAGATEAREA 0.00027817 ;
		ANTENNADIFFAREA 0.00194719 ;
		ANTENNAPARTIALMETALAREA 0.00195671 ;
	END TDA[46]

	PIN TDA[47]
		USE SIGNAL ;
		DIRECTION INPUT ;
		SHAPE ABUTMENT ;
		PORT
			 LAYER M2 ;
			RECT 0.0714 46.7137 0.1097 46.7514 ;
			 LAYER M3 ;
			RECT 0.0714 46.651 0.1097 46.7514 ;
			 LAYER V2 ;
			RECT 0.0831 46.7267 0.098 46.7392 ;
		END

		ANTENNAGATEAREA 0.00027817 ;
		ANTENNADIFFAREA 0.00194719 ;
		ANTENNAPARTIALMETALAREA 0.00195671 ;
	END TDA[47]

	PIN TDA[48]
		USE SIGNAL ;
		DIRECTION INPUT ;
		SHAPE ABUTMENT ;
		PORT
			 LAYER M2 ;
			RECT 0.0714 47.5043 0.1097 47.542 ;
			 LAYER M3 ;
			RECT 0.0714 47.4416 0.1097 47.542 ;
			 LAYER V2 ;
			RECT 0.0831 47.5173 0.098 47.5298 ;
		END

		ANTENNAGATEAREA 0.00027817 ;
		ANTENNADIFFAREA 0.00194719 ;
		ANTENNAPARTIALMETALAREA 0.00195671 ;
	END TDA[48]

	PIN TDA[49]
		USE SIGNAL ;
		DIRECTION INPUT ;
		SHAPE ABUTMENT ;
		PORT
			 LAYER M2 ;
			RECT 0.0714 48.2949 0.1097 48.3325 ;
			 LAYER M3 ;
			RECT 0.0714 48.2322 0.1097 48.3325 ;
			 LAYER V2 ;
			RECT 0.0831 48.3078 0.098 48.3204 ;
		END

		ANTENNAGATEAREA 0.00027817 ;
		ANTENNADIFFAREA 0.00194719 ;
		ANTENNAPARTIALMETALAREA 0.00195671 ;
	END TDA[49]

	PIN TDA[4]
		USE SIGNAL ;
		DIRECTION INPUT ;
		SHAPE ABUTMENT ;
		PORT
			 LAYER M2 ;
			RECT 0.0714 3.8275 0.1097 3.8651 ;
			 LAYER M3 ;
			RECT 0.0714 3.8275 0.1097 3.9278 ;
			 LAYER V2 ;
			RECT 0.0831 3.8396 0.098 3.8522 ;
		END

		ANTENNAGATEAREA 0.00027817 ;
		ANTENNADIFFAREA 0.00194719 ;
		ANTENNAPARTIALMETALAREA 0.00195671 ;
	END TDA[4]

	PIN TDA[50]
		USE SIGNAL ;
		DIRECTION INPUT ;
		SHAPE ABUTMENT ;
		PORT
			 LAYER M2 ;
			RECT 0.0714 49.0855 0.1097 49.1231 ;
			 LAYER M3 ;
			RECT 0.0714 49.0227 0.1097 49.1231 ;
			 LAYER V2 ;
			RECT 0.0831 49.0984 0.098 49.111 ;
		END

		ANTENNAGATEAREA 0.00027817 ;
		ANTENNADIFFAREA 0.00194719 ;
		ANTENNAPARTIALMETALAREA 0.00195671 ;
	END TDA[50]

	PIN TDA[51]
		USE SIGNAL ;
		DIRECTION INPUT ;
		SHAPE ABUTMENT ;
		PORT
			 LAYER M2 ;
			RECT 0.0714 49.8761 0.1097 49.9137 ;
			 LAYER M3 ;
			RECT 0.0714 49.8133 0.1097 49.9137 ;
			 LAYER V2 ;
			RECT 0.0831 49.889 0.098 49.9016 ;
		END

		ANTENNAGATEAREA 0.00027817 ;
		ANTENNADIFFAREA 0.00194719 ;
		ANTENNAPARTIALMETALAREA 0.00195671 ;
	END TDA[51]

	PIN TDA[52]
		USE SIGNAL ;
		DIRECTION INPUT ;
		SHAPE ABUTMENT ;
		PORT
			 LAYER M2 ;
			RECT 0.0714 50.6667 0.1097 50.7043 ;
			 LAYER M3 ;
			RECT 0.0714 50.6039 0.1097 50.7043 ;
			 LAYER V2 ;
			RECT 0.0831 50.6796 0.098 50.6922 ;
		END

		ANTENNAGATEAREA 0.00027817 ;
		ANTENNADIFFAREA 0.00194719 ;
		ANTENNAPARTIALMETALAREA 0.00195671 ;
	END TDA[52]

	PIN TDA[53]
		USE SIGNAL ;
		DIRECTION INPUT ;
		SHAPE ABUTMENT ;
		PORT
			 LAYER M2 ;
			RECT 0.0714 51.4573 0.1097 51.4949 ;
			 LAYER M3 ;
			RECT 0.0714 51.3945 0.1097 51.4949 ;
			 LAYER V2 ;
			RECT 0.0831 51.4702 0.098 51.4827 ;
		END

		ANTENNAGATEAREA 0.00027817 ;
		ANTENNADIFFAREA 0.00194719 ;
		ANTENNAPARTIALMETALAREA 0.00195671 ;
	END TDA[53]

	PIN TDA[54]
		USE SIGNAL ;
		DIRECTION INPUT ;
		SHAPE ABUTMENT ;
		PORT
			 LAYER M2 ;
			RECT 0.0714 52.2478 0.1097 52.2855 ;
			 LAYER M3 ;
			RECT 0.0714 52.1851 0.1097 52.2855 ;
			 LAYER V2 ;
			RECT 0.0831 52.2608 0.098 52.2733 ;
		END

		ANTENNAGATEAREA 0.00027817 ;
		ANTENNADIFFAREA 0.00194719 ;
		ANTENNAPARTIALMETALAREA 0.00195671 ;
	END TDA[54]

	PIN TDA[55]
		USE SIGNAL ;
		DIRECTION INPUT ;
		SHAPE ABUTMENT ;
		PORT
			 LAYER M2 ;
			RECT 0.0714 53.0384 0.1097 53.0761 ;
			 LAYER M3 ;
			RECT 0.0714 52.9757 0.1097 53.0761 ;
			 LAYER V2 ;
			RECT 0.0831 53.0514 0.098 53.0639 ;
		END

		ANTENNAGATEAREA 0.00027817 ;
		ANTENNADIFFAREA 0.00194719 ;
		ANTENNAPARTIALMETALAREA 0.00195671 ;
	END TDA[55]

	PIN TDA[56]
		USE SIGNAL ;
		DIRECTION INPUT ;
		SHAPE ABUTMENT ;
		PORT
			 LAYER M2 ;
			RECT 0.0714 53.829 0.1097 53.8667 ;
			 LAYER M3 ;
			RECT 0.0714 53.7663 0.1097 53.8667 ;
			 LAYER V2 ;
			RECT 0.0831 53.842 0.098 53.8545 ;
		END

		ANTENNAGATEAREA 0.00027817 ;
		ANTENNADIFFAREA 0.00194719 ;
		ANTENNAPARTIALMETALAREA 0.00195671 ;
	END TDA[56]

	PIN TDA[57]
		USE SIGNAL ;
		DIRECTION INPUT ;
		SHAPE ABUTMENT ;
		PORT
			 LAYER M2 ;
			RECT 0.0714 54.6196 0.1097 54.6573 ;
			 LAYER M3 ;
			RECT 0.0714 54.5569 0.1097 54.6573 ;
			 LAYER V2 ;
			RECT 0.0831 54.6325 0.098 54.6451 ;
		END

		ANTENNAGATEAREA 0.00027817 ;
		ANTENNADIFFAREA 0.00194719 ;
		ANTENNAPARTIALMETALAREA 0.00195671 ;
	END TDA[57]

	PIN TDA[58]
		USE SIGNAL ;
		DIRECTION INPUT ;
		SHAPE ABUTMENT ;
		PORT
			 LAYER M2 ;
			RECT 0.0714 55.4102 0.1097 55.4478 ;
			 LAYER M3 ;
			RECT 0.0714 55.3475 0.1097 55.4478 ;
			 LAYER V2 ;
			RECT 0.0831 55.4231 0.098 55.4357 ;
		END

		ANTENNAGATEAREA 0.00027817 ;
		ANTENNADIFFAREA 0.00194719 ;
		ANTENNAPARTIALMETALAREA 0.00195671 ;
	END TDA[58]

	PIN TDA[59]
		USE SIGNAL ;
		DIRECTION INPUT ;
		SHAPE ABUTMENT ;
		PORT
			 LAYER M2 ;
			RECT 0.0714 56.2008 0.1097 56.2384 ;
			 LAYER M3 ;
			RECT 0.0714 56.138 0.1097 56.2384 ;
			 LAYER V2 ;
			RECT 0.0831 56.2137 0.098 56.2263 ;
		END

		ANTENNAGATEAREA 0.00027817 ;
		ANTENNADIFFAREA 0.00194719 ;
		ANTENNAPARTIALMETALAREA 0.00195671 ;
	END TDA[59]

	PIN TDA[5]
		USE SIGNAL ;
		DIRECTION INPUT ;
		SHAPE ABUTMENT ;
		PORT
			 LAYER M2 ;
			RECT 0.0714 4.618 0.1097 4.6557 ;
			 LAYER M3 ;
			RECT 0.0714 4.618 0.1097 4.7184 ;
			 LAYER V2 ;
			RECT 0.0831 4.6302 0.098 4.6427 ;
		END

		ANTENNAGATEAREA 0.00027817 ;
		ANTENNADIFFAREA 0.00194719 ;
		ANTENNAPARTIALMETALAREA 0.00195671 ;
	END TDA[5]

	PIN TDA[60]
		USE SIGNAL ;
		DIRECTION INPUT ;
		SHAPE ABUTMENT ;
		PORT
			 LAYER M2 ;
			RECT 0.0714 56.9914 0.1097 57.029 ;
			 LAYER M3 ;
			RECT 0.0714 56.9286 0.1097 57.029 ;
			 LAYER V2 ;
			RECT 0.0831 57.0043 0.098 57.0169 ;
		END

		ANTENNAGATEAREA 0.00027817 ;
		ANTENNADIFFAREA 0.00194719 ;
		ANTENNAPARTIALMETALAREA 0.00195671 ;
	END TDA[60]

	PIN TDA[61]
		USE SIGNAL ;
		DIRECTION INPUT ;
		SHAPE ABUTMENT ;
		PORT
			 LAYER M2 ;
			RECT 0.0714 57.782 0.1097 57.8196 ;
			 LAYER M3 ;
			RECT 0.0714 57.7192 0.1097 57.8196 ;
			 LAYER V2 ;
			RECT 0.0831 57.7949 0.098 57.8075 ;
		END

		ANTENNAGATEAREA 0.00027817 ;
		ANTENNADIFFAREA 0.00194719 ;
		ANTENNAPARTIALMETALAREA 0.00195671 ;
	END TDA[61]

	PIN TDA[62]
		USE SIGNAL ;
		DIRECTION INPUT ;
		SHAPE ABUTMENT ;
		PORT
			 LAYER M2 ;
			RECT 0.0714 58.5725 0.1097 58.6102 ;
			 LAYER M3 ;
			RECT 0.0714 58.5098 0.1097 58.6102 ;
			 LAYER V2 ;
			RECT 0.0831 58.5855 0.098 58.598 ;
		END

		ANTENNAGATEAREA 0.00027817 ;
		ANTENNADIFFAREA 0.00194719 ;
		ANTENNAPARTIALMETALAREA 0.00195671 ;
	END TDA[62]

	PIN TDA[63]
		USE SIGNAL ;
		DIRECTION INPUT ;
		SHAPE ABUTMENT ;
		PORT
			 LAYER M2 ;
			RECT 0.0714 59.3631 0.1097 59.4008 ;
			 LAYER M3 ;
			RECT 0.0714 59.3004 0.1097 59.4008 ;
			 LAYER V2 ;
			RECT 0.0831 59.3761 0.098 59.3886 ;
		END

		ANTENNAGATEAREA 0.00027817 ;
		ANTENNADIFFAREA 0.00194719 ;
		ANTENNAPARTIALMETALAREA 0.00195671 ;
	END TDA[63]

	PIN TDA[64]
		USE SIGNAL ;
		DIRECTION INPUT ;
		SHAPE ABUTMENT ;
		PORT
			 LAYER M2 ;
			RECT 0.0714 60.1537 0.1097 60.1914 ;
			 LAYER M3 ;
			RECT 0.0714 60.091 0.1097 60.1914 ;
			 LAYER V2 ;
			RECT 0.0831 60.1667 0.098 60.1792 ;
		END

		ANTENNAGATEAREA 0.00027817 ;
		ANTENNADIFFAREA 0.00194719 ;
		ANTENNAPARTIALMETALAREA 0.00195671 ;
	END TDA[64]

	PIN TDA[65]
		USE SIGNAL ;
		DIRECTION INPUT ;
		SHAPE ABUTMENT ;
		PORT
			 LAYER M2 ;
			RECT 0.0714 60.9443 0.1097 60.982 ;
			 LAYER M3 ;
			RECT 0.0714 60.8816 0.1097 60.982 ;
			 LAYER V2 ;
			RECT 0.0831 60.9573 0.098 60.9698 ;
		END

		ANTENNAGATEAREA 0.00027817 ;
		ANTENNADIFFAREA 0.00194719 ;
		ANTENNAPARTIALMETALAREA 0.00195671 ;
	END TDA[65]

	PIN TDA[6]
		USE SIGNAL ;
		DIRECTION INPUT ;
		SHAPE ABUTMENT ;
		PORT
			 LAYER M2 ;
			RECT 0.0714 5.4086 0.1097 5.4463 ;
			 LAYER M3 ;
			RECT 0.0714 5.4086 0.1097 5.509 ;
			 LAYER V2 ;
			RECT 0.0831 5.4208 0.098 5.4333 ;
		END

		ANTENNAGATEAREA 0.00027817 ;
		ANTENNADIFFAREA 0.00194719 ;
		ANTENNAPARTIALMETALAREA 0.00195671 ;
	END TDA[6]

	PIN TDA[7]
		USE SIGNAL ;
		DIRECTION INPUT ;
		SHAPE ABUTMENT ;
		PORT
			 LAYER M2 ;
			RECT 0.0714 6.1992 0.1097 6.2369 ;
			 LAYER M3 ;
			RECT 0.0714 6.1992 0.1097 6.2996 ;
			 LAYER V2 ;
			RECT 0.0831 6.2114 0.098 6.2239 ;
		END

		ANTENNAGATEAREA 0.00027817 ;
		ANTENNADIFFAREA 0.00194719 ;
		ANTENNAPARTIALMETALAREA 0.00195671 ;
	END TDA[7]

	PIN TDA[8]
		USE SIGNAL ;
		DIRECTION INPUT ;
		SHAPE ABUTMENT ;
		PORT
			 LAYER M2 ;
			RECT 0.0714 6.9898 0.1097 7.0275 ;
			 LAYER M3 ;
			RECT 0.0714 6.9898 0.1097 7.0902 ;
			 LAYER V2 ;
			RECT 0.0831 7.002 0.098 7.0145 ;
		END

		ANTENNAGATEAREA 0.00027817 ;
		ANTENNADIFFAREA 0.00194719 ;
		ANTENNAPARTIALMETALAREA 0.00195671 ;
	END TDA[8]

	PIN TDA[9]
		USE SIGNAL ;
		DIRECTION INPUT ;
		SHAPE ABUTMENT ;
		PORT
			 LAYER M2 ;
			RECT 0.0714 7.7804 0.1097 7.818 ;
			 LAYER M3 ;
			RECT 0.0714 7.7804 0.1097 7.8808 ;
			 LAYER V2 ;
			RECT 0.0831 7.7925 0.098 7.8051 ;
		END

		ANTENNAGATEAREA 0.00027817 ;
		ANTENNADIFFAREA 0.00194719 ;
		ANTENNAPARTIALMETALAREA 0.00195671 ;
	END TDA[9]

	PIN TDB[0]
		USE SIGNAL ;
		DIRECTION INPUT ;
		SHAPE ABUTMENT ;
		PORT
			 LAYER M3 ;
			RECT 0.0714 0.8408 0.1097 0.9412 ;
		END

		ANTENNAGATEAREA 0.00027817 ;
		ANTENNADIFFAREA 0.00194719 ;
		ANTENNAPARTIALMETALAREA 0.00195671 ;
	END TDB[0]

	PIN TDB[10]
		USE SIGNAL ;
		DIRECTION INPUT ;
		SHAPE ABUTMENT ;
		PORT
			 LAYER M3 ;
			RECT 0.0714 8.7467 0.1097 8.8471 ;
		END

		ANTENNAGATEAREA 0.00027817 ;
		ANTENNADIFFAREA 0.00194719 ;
		ANTENNAPARTIALMETALAREA 0.00195671 ;
	END TDB[10]

	PIN TDB[11]
		USE SIGNAL ;
		DIRECTION INPUT ;
		SHAPE ABUTMENT ;
		PORT
			 LAYER M3 ;
			RECT 0.0714 9.5373 0.1097 9.6376 ;
		END

		ANTENNAGATEAREA 0.00027817 ;
		ANTENNADIFFAREA 0.00194719 ;
		ANTENNAPARTIALMETALAREA 0.00195671 ;
	END TDB[11]

	PIN TDB[12]
		USE SIGNAL ;
		DIRECTION INPUT ;
		SHAPE ABUTMENT ;
		PORT
			 LAYER M3 ;
			RECT 0.0714 10.3278 0.1097 10.4282 ;
		END

		ANTENNAGATEAREA 0.00027817 ;
		ANTENNADIFFAREA 0.00194719 ;
		ANTENNAPARTIALMETALAREA 0.00195671 ;
	END TDB[12]

	PIN TDB[13]
		USE SIGNAL ;
		DIRECTION INPUT ;
		SHAPE ABUTMENT ;
		PORT
			 LAYER M3 ;
			RECT 0.0714 11.1184 0.1097 11.2188 ;
		END

		ANTENNAGATEAREA 0.00027817 ;
		ANTENNADIFFAREA 0.00194719 ;
		ANTENNAPARTIALMETALAREA 0.00195671 ;
	END TDB[13]

	PIN TDB[14]
		USE SIGNAL ;
		DIRECTION INPUT ;
		SHAPE ABUTMENT ;
		PORT
			 LAYER M3 ;
			RECT 0.0714 11.909 0.1097 12.0094 ;
		END

		ANTENNAGATEAREA 0.00027817 ;
		ANTENNADIFFAREA 0.00194719 ;
		ANTENNAPARTIALMETALAREA 0.00195671 ;
	END TDB[14]

	PIN TDB[15]
		USE SIGNAL ;
		DIRECTION INPUT ;
		SHAPE ABUTMENT ;
		PORT
			 LAYER M3 ;
			RECT 0.0714 12.6996 0.1097 12.8 ;
		END

		ANTENNAGATEAREA 0.00027817 ;
		ANTENNADIFFAREA 0.00194719 ;
		ANTENNAPARTIALMETALAREA 0.00195671 ;
	END TDB[15]

	PIN TDB[16]
		USE SIGNAL ;
		DIRECTION INPUT ;
		SHAPE ABUTMENT ;
		PORT
			 LAYER M3 ;
			RECT 0.0714 13.4902 0.1097 13.5906 ;
		END

		ANTENNAGATEAREA 0.00027817 ;
		ANTENNADIFFAREA 0.00194719 ;
		ANTENNAPARTIALMETALAREA 0.00195671 ;
	END TDB[16]

	PIN TDB[17]
		USE SIGNAL ;
		DIRECTION INPUT ;
		SHAPE ABUTMENT ;
		PORT
			 LAYER M3 ;
			RECT 0.0714 14.2808 0.1097 14.3812 ;
		END

		ANTENNAGATEAREA 0.00027817 ;
		ANTENNADIFFAREA 0.00194719 ;
		ANTENNAPARTIALMETALAREA 0.00195671 ;
	END TDB[17]

	PIN TDB[18]
		USE SIGNAL ;
		DIRECTION INPUT ;
		SHAPE ABUTMENT ;
		PORT
			 LAYER M3 ;
			RECT 0.0714 15.0714 0.1097 15.1718 ;
		END

		ANTENNAGATEAREA 0.00027817 ;
		ANTENNADIFFAREA 0.00194719 ;
		ANTENNAPARTIALMETALAREA 0.00195671 ;
	END TDB[18]

	PIN TDB[19]
		USE SIGNAL ;
		DIRECTION INPUT ;
		SHAPE ABUTMENT ;
		PORT
			 LAYER M3 ;
			RECT 0.0714 15.862 0.1097 15.9624 ;
		END

		ANTENNAGATEAREA 0.00027817 ;
		ANTENNADIFFAREA 0.00194719 ;
		ANTENNAPARTIALMETALAREA 0.00195671 ;
	END TDB[19]

	PIN TDB[1]
		USE SIGNAL ;
		DIRECTION INPUT ;
		SHAPE ABUTMENT ;
		PORT
			 LAYER M3 ;
			RECT 0.0714 1.6314 0.1097 1.7318 ;
		END

		ANTENNAGATEAREA 0.00027817 ;
		ANTENNADIFFAREA 0.00194719 ;
		ANTENNAPARTIALMETALAREA 0.00195671 ;
	END TDB[1]

	PIN TDB[20]
		USE SIGNAL ;
		DIRECTION INPUT ;
		SHAPE ABUTMENT ;
		PORT
			 LAYER M3 ;
			RECT 0.0714 16.6525 0.1097 16.7529 ;
		END

		ANTENNAGATEAREA 0.00027817 ;
		ANTENNADIFFAREA 0.00194719 ;
		ANTENNAPARTIALMETALAREA 0.00195671 ;
	END TDB[20]

	PIN TDB[21]
		USE SIGNAL ;
		DIRECTION INPUT ;
		SHAPE ABUTMENT ;
		PORT
			 LAYER M3 ;
			RECT 0.0714 17.4431 0.1097 17.5435 ;
		END

		ANTENNAGATEAREA 0.00027817 ;
		ANTENNADIFFAREA 0.00194719 ;
		ANTENNAPARTIALMETALAREA 0.00195671 ;
	END TDB[21]

	PIN TDB[22]
		USE SIGNAL ;
		DIRECTION INPUT ;
		SHAPE ABUTMENT ;
		PORT
			 LAYER M3 ;
			RECT 0.0714 18.2337 0.1097 18.3341 ;
		END

		ANTENNAGATEAREA 0.00027817 ;
		ANTENNADIFFAREA 0.00194719 ;
		ANTENNAPARTIALMETALAREA 0.00195671 ;
	END TDB[22]

	PIN TDB[23]
		USE SIGNAL ;
		DIRECTION INPUT ;
		SHAPE ABUTMENT ;
		PORT
			 LAYER M3 ;
			RECT 0.0714 19.0243 0.1097 19.1247 ;
		END

		ANTENNAGATEAREA 0.00027817 ;
		ANTENNADIFFAREA 0.00194719 ;
		ANTENNAPARTIALMETALAREA 0.00195671 ;
	END TDB[23]

	PIN TDB[24]
		USE SIGNAL ;
		DIRECTION INPUT ;
		SHAPE ABUTMENT ;
		PORT
			 LAYER M3 ;
			RECT 0.0714 19.8149 0.1097 19.9153 ;
		END

		ANTENNAGATEAREA 0.00027817 ;
		ANTENNADIFFAREA 0.00194719 ;
		ANTENNAPARTIALMETALAREA 0.00195671 ;
	END TDB[24]

	PIN TDB[25]
		USE SIGNAL ;
		DIRECTION INPUT ;
		SHAPE ABUTMENT ;
		PORT
			 LAYER M3 ;
			RECT 0.0714 20.6055 0.1097 20.7059 ;
		END

		ANTENNAGATEAREA 0.00027817 ;
		ANTENNADIFFAREA 0.00194719 ;
		ANTENNAPARTIALMETALAREA 0.00195671 ;
	END TDB[25]

	PIN TDB[26]
		USE SIGNAL ;
		DIRECTION INPUT ;
		SHAPE ABUTMENT ;
		PORT
			 LAYER M3 ;
			RECT 0.0714 21.3961 0.1097 21.4965 ;
		END

		ANTENNAGATEAREA 0.00027817 ;
		ANTENNADIFFAREA 0.00194719 ;
		ANTENNAPARTIALMETALAREA 0.00195671 ;
	END TDB[26]

	PIN TDB[27]
		USE SIGNAL ;
		DIRECTION INPUT ;
		SHAPE ABUTMENT ;
		PORT
			 LAYER M3 ;
			RECT 0.0714 22.1867 0.1097 22.2871 ;
		END

		ANTENNAGATEAREA 0.00027817 ;
		ANTENNADIFFAREA 0.00194719 ;
		ANTENNAPARTIALMETALAREA 0.00195671 ;
	END TDB[27]

	PIN TDB[28]
		USE SIGNAL ;
		DIRECTION INPUT ;
		SHAPE ABUTMENT ;
		PORT
			 LAYER M3 ;
			RECT 0.0714 22.9773 0.1097 23.0776 ;
		END

		ANTENNAGATEAREA 0.00027817 ;
		ANTENNADIFFAREA 0.00194719 ;
		ANTENNAPARTIALMETALAREA 0.00195671 ;
	END TDB[28]

	PIN TDB[29]
		USE SIGNAL ;
		DIRECTION INPUT ;
		SHAPE ABUTMENT ;
		PORT
			 LAYER M3 ;
			RECT 0.0714 23.7678 0.1097 23.8682 ;
		END

		ANTENNAGATEAREA 0.00027817 ;
		ANTENNADIFFAREA 0.00194719 ;
		ANTENNAPARTIALMETALAREA 0.00195671 ;
	END TDB[29]

	PIN TDB[2]
		USE SIGNAL ;
		DIRECTION INPUT ;
		SHAPE ABUTMENT ;
		PORT
			 LAYER M3 ;
			RECT 0.0714 2.422 0.1097 2.5224 ;
		END

		ANTENNAGATEAREA 0.00027817 ;
		ANTENNADIFFAREA 0.00194719 ;
		ANTENNAPARTIALMETALAREA 0.00195671 ;
	END TDB[2]

	PIN TDB[30]
		USE SIGNAL ;
		DIRECTION INPUT ;
		SHAPE ABUTMENT ;
		PORT
			 LAYER M3 ;
			RECT 0.0714 24.5584 0.1097 24.6588 ;
		END

		ANTENNAGATEAREA 0.00027817 ;
		ANTENNADIFFAREA 0.00194719 ;
		ANTENNAPARTIALMETALAREA 0.00195671 ;
	END TDB[30]

	PIN TDB[31]
		USE SIGNAL ;
		DIRECTION INPUT ;
		SHAPE ABUTMENT ;
		PORT
			 LAYER M3 ;
			RECT 0.0714 25.349 0.1097 25.4494 ;
		END

		ANTENNAGATEAREA 0.00027817 ;
		ANTENNADIFFAREA 0.00194719 ;
		ANTENNAPARTIALMETALAREA 0.00195671 ;
	END TDB[31]

	PIN TDB[32]
		USE SIGNAL ;
		DIRECTION INPUT ;
		SHAPE ABUTMENT ;
		PORT
			 LAYER M3 ;
			RECT 0.0714 26.1396 0.1097 26.24 ;
		END

		ANTENNAGATEAREA 0.00027817 ;
		ANTENNADIFFAREA 0.00194719 ;
		ANTENNAPARTIALMETALAREA 0.00195671 ;
	END TDB[32]

	PIN TDB[33]
		USE SIGNAL ;
		DIRECTION INPUT ;
		SHAPE ABUTMENT ;
		PORT
			 LAYER M3 ;
			RECT 0.0714 35.4071 0.1097 35.5075 ;
		END

		ANTENNAGATEAREA 0.00027817 ;
		ANTENNADIFFAREA 0.00194719 ;
		ANTENNAPARTIALMETALAREA 0.00195671 ;
	END TDB[33]

	PIN TDB[34]
		USE SIGNAL ;
		DIRECTION INPUT ;
		SHAPE ABUTMENT ;
		PORT
			 LAYER M3 ;
			RECT 0.0714 36.1976 0.1097 36.298 ;
		END

		ANTENNAGATEAREA 0.00027817 ;
		ANTENNADIFFAREA 0.00194719 ;
		ANTENNAPARTIALMETALAREA 0.00195671 ;
	END TDB[34]

	PIN TDB[35]
		USE SIGNAL ;
		DIRECTION INPUT ;
		SHAPE ABUTMENT ;
		PORT
			 LAYER M3 ;
			RECT 0.0714 36.9882 0.1097 37.0886 ;
		END

		ANTENNAGATEAREA 0.00027817 ;
		ANTENNADIFFAREA 0.00194719 ;
		ANTENNAPARTIALMETALAREA 0.00195671 ;
	END TDB[35]

	PIN TDB[36]
		USE SIGNAL ;
		DIRECTION INPUT ;
		SHAPE ABUTMENT ;
		PORT
			 LAYER M3 ;
			RECT 0.0714 37.7788 0.1097 37.8792 ;
		END

		ANTENNAGATEAREA 0.00027817 ;
		ANTENNADIFFAREA 0.00194719 ;
		ANTENNAPARTIALMETALAREA 0.00195671 ;
	END TDB[36]

	PIN TDB[37]
		USE SIGNAL ;
		DIRECTION INPUT ;
		SHAPE ABUTMENT ;
		PORT
			 LAYER M3 ;
			RECT 0.0714 38.5694 0.1097 38.6698 ;
		END

		ANTENNAGATEAREA 0.00027817 ;
		ANTENNADIFFAREA 0.00194719 ;
		ANTENNAPARTIALMETALAREA 0.00195671 ;
	END TDB[37]

	PIN TDB[38]
		USE SIGNAL ;
		DIRECTION INPUT ;
		SHAPE ABUTMENT ;
		PORT
			 LAYER M3 ;
			RECT 0.0714 39.36 0.1097 39.4604 ;
		END

		ANTENNAGATEAREA 0.00027817 ;
		ANTENNADIFFAREA 0.00194719 ;
		ANTENNAPARTIALMETALAREA 0.00195671 ;
	END TDB[38]

	PIN TDB[39]
		USE SIGNAL ;
		DIRECTION INPUT ;
		SHAPE ABUTMENT ;
		PORT
			 LAYER M3 ;
			RECT 0.0714 40.1506 0.1097 40.251 ;
		END

		ANTENNAGATEAREA 0.00027817 ;
		ANTENNADIFFAREA 0.00194719 ;
		ANTENNAPARTIALMETALAREA 0.00195671 ;
	END TDB[39]

	PIN TDB[3]
		USE SIGNAL ;
		DIRECTION INPUT ;
		SHAPE ABUTMENT ;
		PORT
			 LAYER M3 ;
			RECT 0.0714 3.2125 0.1097 3.3129 ;
		END

		ANTENNAGATEAREA 0.00027817 ;
		ANTENNADIFFAREA 0.00194719 ;
		ANTENNAPARTIALMETALAREA 0.00195671 ;
	END TDB[3]

	PIN TDB[40]
		USE SIGNAL ;
		DIRECTION INPUT ;
		SHAPE ABUTMENT ;
		PORT
			 LAYER M3 ;
			RECT 0.0714 40.9412 0.1097 41.0416 ;
		END

		ANTENNAGATEAREA 0.00027817 ;
		ANTENNADIFFAREA 0.00194719 ;
		ANTENNAPARTIALMETALAREA 0.00195671 ;
	END TDB[40]

	PIN TDB[41]
		USE SIGNAL ;
		DIRECTION INPUT ;
		SHAPE ABUTMENT ;
		PORT
			 LAYER M3 ;
			RECT 0.0714 41.7318 0.1097 41.8322 ;
		END

		ANTENNAGATEAREA 0.00027817 ;
		ANTENNADIFFAREA 0.00194719 ;
		ANTENNAPARTIALMETALAREA 0.00195671 ;
	END TDB[41]

	PIN TDB[42]
		USE SIGNAL ;
		DIRECTION INPUT ;
		SHAPE ABUTMENT ;
		PORT
			 LAYER M3 ;
			RECT 0.0714 42.5224 0.1097 42.6227 ;
		END

		ANTENNAGATEAREA 0.00027817 ;
		ANTENNADIFFAREA 0.00194719 ;
		ANTENNAPARTIALMETALAREA 0.00195671 ;
	END TDB[42]

	PIN TDB[43]
		USE SIGNAL ;
		DIRECTION INPUT ;
		SHAPE ABUTMENT ;
		PORT
			 LAYER M3 ;
			RECT 0.0714 43.3129 0.1097 43.4133 ;
		END

		ANTENNAGATEAREA 0.00027817 ;
		ANTENNADIFFAREA 0.00194719 ;
		ANTENNAPARTIALMETALAREA 0.00195671 ;
	END TDB[43]

	PIN TDB[44]
		USE SIGNAL ;
		DIRECTION INPUT ;
		SHAPE ABUTMENT ;
		PORT
			 LAYER M3 ;
			RECT 0.0714 44.1035 0.1097 44.2039 ;
		END

		ANTENNAGATEAREA 0.00027817 ;
		ANTENNADIFFAREA 0.00194719 ;
		ANTENNAPARTIALMETALAREA 0.00195671 ;
	END TDB[44]

	PIN TDB[45]
		USE SIGNAL ;
		DIRECTION INPUT ;
		SHAPE ABUTMENT ;
		PORT
			 LAYER M3 ;
			RECT 0.0714 44.8941 0.1097 44.9945 ;
		END

		ANTENNAGATEAREA 0.00027817 ;
		ANTENNADIFFAREA 0.00194719 ;
		ANTENNAPARTIALMETALAREA 0.00195671 ;
	END TDB[45]

	PIN TDB[46]
		USE SIGNAL ;
		DIRECTION INPUT ;
		SHAPE ABUTMENT ;
		PORT
			 LAYER M3 ;
			RECT 0.0714 45.6847 0.1097 45.7851 ;
		END

		ANTENNAGATEAREA 0.00027817 ;
		ANTENNADIFFAREA 0.00194719 ;
		ANTENNAPARTIALMETALAREA 0.00195671 ;
	END TDB[46]

	PIN TDB[47]
		USE SIGNAL ;
		DIRECTION INPUT ;
		SHAPE ABUTMENT ;
		PORT
			 LAYER M3 ;
			RECT 0.0714 46.4753 0.1097 46.5757 ;
		END

		ANTENNAGATEAREA 0.00027817 ;
		ANTENNADIFFAREA 0.00194719 ;
		ANTENNAPARTIALMETALAREA 0.00195671 ;
	END TDB[47]

	PIN TDB[48]
		USE SIGNAL ;
		DIRECTION INPUT ;
		SHAPE ABUTMENT ;
		PORT
			 LAYER M3 ;
			RECT 0.0714 47.2659 0.1097 47.3663 ;
		END

		ANTENNAGATEAREA 0.00027817 ;
		ANTENNADIFFAREA 0.00194719 ;
		ANTENNAPARTIALMETALAREA 0.00195671 ;
	END TDB[48]

	PIN TDB[49]
		USE SIGNAL ;
		DIRECTION INPUT ;
		SHAPE ABUTMENT ;
		PORT
			 LAYER M3 ;
			RECT 0.0714 48.0565 0.1097 48.1569 ;
		END

		ANTENNAGATEAREA 0.00027817 ;
		ANTENNADIFFAREA 0.00194719 ;
		ANTENNAPARTIALMETALAREA 0.00195671 ;
	END TDB[49]

	PIN TDB[4]
		USE SIGNAL ;
		DIRECTION INPUT ;
		SHAPE ABUTMENT ;
		PORT
			 LAYER M3 ;
			RECT 0.0714 4.0031 0.1097 4.1035 ;
		END

		ANTENNAGATEAREA 0.00027817 ;
		ANTENNADIFFAREA 0.00194719 ;
		ANTENNAPARTIALMETALAREA 0.00195671 ;
	END TDB[4]

	PIN TDB[50]
		USE SIGNAL ;
		DIRECTION INPUT ;
		SHAPE ABUTMENT ;
		PORT
			 LAYER M3 ;
			RECT 0.0714 48.8471 0.1097 48.9475 ;
		END

		ANTENNAGATEAREA 0.00027817 ;
		ANTENNADIFFAREA 0.00194719 ;
		ANTENNAPARTIALMETALAREA 0.00195671 ;
	END TDB[50]

	PIN TDB[51]
		USE SIGNAL ;
		DIRECTION INPUT ;
		SHAPE ABUTMENT ;
		PORT
			 LAYER M3 ;
			RECT 0.0714 49.6376 0.1097 49.738 ;
		END

		ANTENNAGATEAREA 0.00027817 ;
		ANTENNADIFFAREA 0.00194719 ;
		ANTENNAPARTIALMETALAREA 0.00195671 ;
	END TDB[51]

	PIN TDB[52]
		USE SIGNAL ;
		DIRECTION INPUT ;
		SHAPE ABUTMENT ;
		PORT
			 LAYER M3 ;
			RECT 0.0714 50.4282 0.1097 50.5286 ;
		END

		ANTENNAGATEAREA 0.00027817 ;
		ANTENNADIFFAREA 0.00194719 ;
		ANTENNAPARTIALMETALAREA 0.00195671 ;
	END TDB[52]

	PIN TDB[53]
		USE SIGNAL ;
		DIRECTION INPUT ;
		SHAPE ABUTMENT ;
		PORT
			 LAYER M3 ;
			RECT 0.0714 51.2188 0.1097 51.3192 ;
		END

		ANTENNAGATEAREA 0.00027817 ;
		ANTENNADIFFAREA 0.00194719 ;
		ANTENNAPARTIALMETALAREA 0.00195671 ;
	END TDB[53]

	PIN TDB[54]
		USE SIGNAL ;
		DIRECTION INPUT ;
		SHAPE ABUTMENT ;
		PORT
			 LAYER M3 ;
			RECT 0.0714 52.0094 0.1097 52.1098 ;
		END

		ANTENNAGATEAREA 0.00027817 ;
		ANTENNADIFFAREA 0.00194719 ;
		ANTENNAPARTIALMETALAREA 0.00195671 ;
	END TDB[54]

	PIN TDB[55]
		USE SIGNAL ;
		DIRECTION INPUT ;
		SHAPE ABUTMENT ;
		PORT
			 LAYER M3 ;
			RECT 0.0714 52.8 0.1097 52.9004 ;
		END

		ANTENNAGATEAREA 0.00027817 ;
		ANTENNADIFFAREA 0.00194719 ;
		ANTENNAPARTIALMETALAREA 0.00195671 ;
	END TDB[55]

	PIN TDB[56]
		USE SIGNAL ;
		DIRECTION INPUT ;
		SHAPE ABUTMENT ;
		PORT
			 LAYER M3 ;
			RECT 0.0714 53.5906 0.1097 53.691 ;
		END

		ANTENNAGATEAREA 0.00027817 ;
		ANTENNADIFFAREA 0.00194719 ;
		ANTENNAPARTIALMETALAREA 0.00195671 ;
	END TDB[56]

	PIN TDB[57]
		USE SIGNAL ;
		DIRECTION INPUT ;
		SHAPE ABUTMENT ;
		PORT
			 LAYER M3 ;
			RECT 0.0714 54.3812 0.1097 54.4816 ;
		END

		ANTENNAGATEAREA 0.00027817 ;
		ANTENNADIFFAREA 0.00194719 ;
		ANTENNAPARTIALMETALAREA 0.00195671 ;
	END TDB[57]

	PIN TDB[58]
		USE SIGNAL ;
		DIRECTION INPUT ;
		SHAPE ABUTMENT ;
		PORT
			 LAYER M3 ;
			RECT 0.0714 55.1718 0.1097 55.2722 ;
		END

		ANTENNAGATEAREA 0.00027817 ;
		ANTENNADIFFAREA 0.00194719 ;
		ANTENNAPARTIALMETALAREA 0.00195671 ;
	END TDB[58]

	PIN TDB[59]
		USE SIGNAL ;
		DIRECTION INPUT ;
		SHAPE ABUTMENT ;
		PORT
			 LAYER M3 ;
			RECT 0.0714 55.9624 0.1097 56.0627 ;
		END

		ANTENNAGATEAREA 0.00027817 ;
		ANTENNADIFFAREA 0.00194719 ;
		ANTENNAPARTIALMETALAREA 0.00195671 ;
	END TDB[59]

	PIN TDB[5]
		USE SIGNAL ;
		DIRECTION INPUT ;
		SHAPE ABUTMENT ;
		PORT
			 LAYER M3 ;
			RECT 0.0714 4.7937 0.1097 4.8941 ;
		END

		ANTENNAGATEAREA 0.00027817 ;
		ANTENNADIFFAREA 0.00194719 ;
		ANTENNAPARTIALMETALAREA 0.00195671 ;
	END TDB[5]

	PIN TDB[60]
		USE SIGNAL ;
		DIRECTION INPUT ;
		SHAPE ABUTMENT ;
		PORT
			 LAYER M3 ;
			RECT 0.0714 56.7529 0.1097 56.8533 ;
		END

		ANTENNAGATEAREA 0.00027817 ;
		ANTENNADIFFAREA 0.00194719 ;
		ANTENNAPARTIALMETALAREA 0.00195671 ;
	END TDB[60]

	PIN TDB[61]
		USE SIGNAL ;
		DIRECTION INPUT ;
		SHAPE ABUTMENT ;
		PORT
			 LAYER M3 ;
			RECT 0.0714 57.5435 0.1097 57.6439 ;
		END

		ANTENNAGATEAREA 0.00027817 ;
		ANTENNADIFFAREA 0.00194719 ;
		ANTENNAPARTIALMETALAREA 0.00195671 ;
	END TDB[61]

	PIN TDB[62]
		USE SIGNAL ;
		DIRECTION INPUT ;
		SHAPE ABUTMENT ;
		PORT
			 LAYER M3 ;
			RECT 0.0714 58.3341 0.1097 58.4345 ;
		END

		ANTENNAGATEAREA 0.00027817 ;
		ANTENNADIFFAREA 0.00194719 ;
		ANTENNAPARTIALMETALAREA 0.00195671 ;
	END TDB[62]

	PIN TDB[63]
		USE SIGNAL ;
		DIRECTION INPUT ;
		SHAPE ABUTMENT ;
		PORT
			 LAYER M3 ;
			RECT 0.0714 59.1247 0.1097 59.2251 ;
		END

		ANTENNAGATEAREA 0.00027817 ;
		ANTENNADIFFAREA 0.00194719 ;
		ANTENNAPARTIALMETALAREA 0.00195671 ;
	END TDB[63]

	PIN TDB[64]
		USE SIGNAL ;
		DIRECTION INPUT ;
		SHAPE ABUTMENT ;
		PORT
			 LAYER M3 ;
			RECT 0.0714 59.9153 0.1097 60.0157 ;
		END

		ANTENNAGATEAREA 0.00027817 ;
		ANTENNADIFFAREA 0.00194719 ;
		ANTENNAPARTIALMETALAREA 0.00195671 ;
	END TDB[64]

	PIN TDB[65]
		USE SIGNAL ;
		DIRECTION INPUT ;
		SHAPE ABUTMENT ;
		PORT
			 LAYER M3 ;
			RECT 0.0714 60.7059 0.1097 60.8063 ;
		END

		ANTENNAGATEAREA 0.00027817 ;
		ANTENNADIFFAREA 0.00194719 ;
		ANTENNAPARTIALMETALAREA 0.00195671 ;
	END TDB[65]

	PIN TDB[6]
		USE SIGNAL ;
		DIRECTION INPUT ;
		SHAPE ABUTMENT ;
		PORT
			 LAYER M3 ;
			RECT 0.0714 5.5843 0.1097 5.6847 ;
		END

		ANTENNAGATEAREA 0.00027817 ;
		ANTENNADIFFAREA 0.00194719 ;
		ANTENNAPARTIALMETALAREA 0.00195671 ;
	END TDB[6]

	PIN TDB[7]
		USE SIGNAL ;
		DIRECTION INPUT ;
		SHAPE ABUTMENT ;
		PORT
			 LAYER M3 ;
			RECT 0.0714 6.3749 0.1097 6.4753 ;
		END

		ANTENNAGATEAREA 0.00027817 ;
		ANTENNADIFFAREA 0.00194719 ;
		ANTENNAPARTIALMETALAREA 0.00195671 ;
	END TDB[7]

	PIN TDB[8]
		USE SIGNAL ;
		DIRECTION INPUT ;
		SHAPE ABUTMENT ;
		PORT
			 LAYER M3 ;
			RECT 0.0714 7.1655 0.1097 7.2659 ;
		END

		ANTENNAGATEAREA 0.00027817 ;
		ANTENNADIFFAREA 0.00194719 ;
		ANTENNAPARTIALMETALAREA 0.00195671 ;
	END TDB[8]

	PIN TDB[9]
		USE SIGNAL ;
		DIRECTION INPUT ;
		SHAPE ABUTMENT ;
		PORT
			 LAYER M3 ;
			RECT 0.0714 7.9561 0.1097 8.0565 ;
		END

		ANTENNAGATEAREA 0.00027817 ;
		ANTENNADIFFAREA 0.00194719 ;
		ANTENNAPARTIALMETALAREA 0.00195671 ;
	END TDB[9]

	PIN TEN
		USE SIGNAL ;
		DIRECTION INPUT ;
		SHAPE ABUTMENT ;
		PORT
			 LAYER M2 ;
			RECT 0.0098 29.1388 0.0481 29.1765 ;
		END

		ANTENNAGATEAREA 0.00027817 ;
		ANTENNADIFFAREA 0.00194719 ;
		ANTENNAPARTIALMETALAREA 0.00195671 ;
	END TEN

	PIN TGWENA
		USE SIGNAL ;
		DIRECTION INPUT ;
		SHAPE ABUTMENT ;
		PORT
			 LAYER M2 ;
			RECT 0.0714 28.3733 0.1097 28.411 ;
			 LAYER M3 ;
			RECT 0.0714 28.3733 0.1097 28.4737 ;
			 LAYER V2 ;
			RECT 0.0831 28.3855 0.098 28.398 ;
		END

		ANTENNAGATEAREA 0.00027817 ;
		ANTENNADIFFAREA 0.00194719 ;
		ANTENNAPARTIALMETALAREA 0.00195671 ;
	END TGWENA

	PIN TGWENB
		USE SIGNAL ;
		DIRECTION INPUT ;
		SHAPE ABUTMENT ;
		PORT
			 LAYER M2 ;
			RECT 0.0714 27.1686 0.1097 27.2063 ;
			 LAYER M3 ;
			RECT 0.0714 27.1686 0.1097 27.269 ;
			 LAYER V2 ;
			RECT 0.0831 27.1808 0.098 27.1933 ;
		END

		ANTENNAGATEAREA 0.00027817 ;
		ANTENNADIFFAREA 0.00194719 ;
		ANTENNAPARTIALMETALAREA 0.00195671 ;
	END TGWENB

	PIN TWENA[0]
		USE SIGNAL ;
		DIRECTION INPUT ;
		SHAPE ABUTMENT ;
		PORT
			 LAYER M2 ;
			RECT 0.0714 0.4518 0.1097 0.4894 ;
			 LAYER M3 ;
			RECT 0.0714 0.389 0.1097 0.4894 ;
			 LAYER V2 ;
			RECT 0.0831 0.4647 0.098 0.4773 ;
		END

		ANTENNAGATEAREA 0.00027817 ;
		ANTENNADIFFAREA 0.00194719 ;
		ANTENNAPARTIALMETALAREA 0.00195671 ;
	END TWENA[0]

	PIN TWENA[10]
		USE SIGNAL ;
		DIRECTION INPUT ;
		SHAPE ABUTMENT ;
		PORT
			 LAYER M2 ;
			RECT 0.0714 8.3576 0.1097 8.3953 ;
			 LAYER M3 ;
			RECT 0.0714 8.2949 0.1097 8.3953 ;
			 LAYER V2 ;
			RECT 0.0831 8.3706 0.098 8.3831 ;
		END

		ANTENNAGATEAREA 0.00027817 ;
		ANTENNADIFFAREA 0.00194719 ;
		ANTENNAPARTIALMETALAREA 0.00195671 ;
	END TWENA[10]

	PIN TWENA[11]
		USE SIGNAL ;
		DIRECTION INPUT ;
		SHAPE ABUTMENT ;
		PORT
			 LAYER M2 ;
			RECT 0.0714 9.1482 0.1097 9.1859 ;
			 LAYER M3 ;
			RECT 0.0714 9.0855 0.1097 9.1859 ;
			 LAYER V2 ;
			RECT 0.0831 9.1612 0.098 9.1737 ;
		END

		ANTENNAGATEAREA 0.00027817 ;
		ANTENNADIFFAREA 0.00194719 ;
		ANTENNAPARTIALMETALAREA 0.00195671 ;
	END TWENA[11]

	PIN TWENA[12]
		USE SIGNAL ;
		DIRECTION INPUT ;
		SHAPE ABUTMENT ;
		PORT
			 LAYER M2 ;
			RECT 0.0714 9.9388 0.1097 9.9765 ;
			 LAYER M3 ;
			RECT 0.0714 9.8761 0.1097 9.9765 ;
			 LAYER V2 ;
			RECT 0.0831 9.9518 0.098 9.9643 ;
		END

		ANTENNAGATEAREA 0.00027817 ;
		ANTENNADIFFAREA 0.00194719 ;
		ANTENNAPARTIALMETALAREA 0.00195671 ;
	END TWENA[12]

	PIN TWENA[13]
		USE SIGNAL ;
		DIRECTION INPUT ;
		SHAPE ABUTMENT ;
		PORT
			 LAYER M2 ;
			RECT 0.0714 10.7294 0.1097 10.7671 ;
			 LAYER M3 ;
			RECT 0.0714 10.6667 0.1097 10.7671 ;
			 LAYER V2 ;
			RECT 0.0831 10.7424 0.098 10.7549 ;
		END

		ANTENNAGATEAREA 0.00027817 ;
		ANTENNADIFFAREA 0.00194719 ;
		ANTENNAPARTIALMETALAREA 0.00195671 ;
	END TWENA[13]

	PIN TWENA[14]
		USE SIGNAL ;
		DIRECTION INPUT ;
		SHAPE ABUTMENT ;
		PORT
			 LAYER M2 ;
			RECT 0.0714 11.52 0.1097 11.5576 ;
			 LAYER M3 ;
			RECT 0.0714 11.4573 0.1097 11.5576 ;
			 LAYER V2 ;
			RECT 0.0831 11.5329 0.098 11.5455 ;
		END

		ANTENNAGATEAREA 0.00027817 ;
		ANTENNADIFFAREA 0.00194719 ;
		ANTENNAPARTIALMETALAREA 0.00195671 ;
	END TWENA[14]

	PIN TWENA[15]
		USE SIGNAL ;
		DIRECTION INPUT ;
		SHAPE ABUTMENT ;
		PORT
			 LAYER M2 ;
			RECT 0.0714 12.3106 0.1097 12.3482 ;
			 LAYER M3 ;
			RECT 0.0714 12.2478 0.1097 12.3482 ;
			 LAYER V2 ;
			RECT 0.0831 12.3235 0.098 12.3361 ;
		END

		ANTENNAGATEAREA 0.00027817 ;
		ANTENNADIFFAREA 0.00194719 ;
		ANTENNAPARTIALMETALAREA 0.00195671 ;
	END TWENA[15]

	PIN TWENA[16]
		USE SIGNAL ;
		DIRECTION INPUT ;
		SHAPE ABUTMENT ;
		PORT
			 LAYER M2 ;
			RECT 0.0714 13.1012 0.1097 13.1388 ;
			 LAYER M3 ;
			RECT 0.0714 13.0384 0.1097 13.1388 ;
			 LAYER V2 ;
			RECT 0.0831 13.1141 0.098 13.1267 ;
		END

		ANTENNAGATEAREA 0.00027817 ;
		ANTENNADIFFAREA 0.00194719 ;
		ANTENNAPARTIALMETALAREA 0.00195671 ;
	END TWENA[16]

	PIN TWENA[17]
		USE SIGNAL ;
		DIRECTION INPUT ;
		SHAPE ABUTMENT ;
		PORT
			 LAYER M2 ;
			RECT 0.0714 13.8918 0.1097 13.9294 ;
			 LAYER M3 ;
			RECT 0.0714 13.829 0.1097 13.9294 ;
			 LAYER V2 ;
			RECT 0.0831 13.9047 0.098 13.9173 ;
		END

		ANTENNAGATEAREA 0.00027817 ;
		ANTENNADIFFAREA 0.00194719 ;
		ANTENNAPARTIALMETALAREA 0.00195671 ;
	END TWENA[17]

	PIN TWENA[18]
		USE SIGNAL ;
		DIRECTION INPUT ;
		SHAPE ABUTMENT ;
		PORT
			 LAYER M2 ;
			RECT 0.0714 14.6824 0.1097 14.72 ;
			 LAYER M3 ;
			RECT 0.0714 14.6196 0.1097 14.72 ;
			 LAYER V2 ;
			RECT 0.0831 14.6953 0.098 14.7078 ;
		END

		ANTENNAGATEAREA 0.00027817 ;
		ANTENNADIFFAREA 0.00194719 ;
		ANTENNAPARTIALMETALAREA 0.00195671 ;
	END TWENA[18]

	PIN TWENA[19]
		USE SIGNAL ;
		DIRECTION INPUT ;
		SHAPE ABUTMENT ;
		PORT
			 LAYER M2 ;
			RECT 0.0714 15.4729 0.1097 15.5106 ;
			 LAYER M3 ;
			RECT 0.0714 15.4102 0.1097 15.5106 ;
			 LAYER V2 ;
			RECT 0.0831 15.4859 0.098 15.4984 ;
		END

		ANTENNAGATEAREA 0.00027817 ;
		ANTENNADIFFAREA 0.00194719 ;
		ANTENNAPARTIALMETALAREA 0.00195671 ;
	END TWENA[19]

	PIN TWENA[1]
		USE SIGNAL ;
		DIRECTION INPUT ;
		SHAPE ABUTMENT ;
		PORT
			 LAYER M2 ;
			RECT 0.0714 1.2424 0.1097 1.28 ;
			 LAYER M3 ;
			RECT 0.0714 1.1796 0.1097 1.28 ;
			 LAYER V2 ;
			RECT 0.0831 1.2553 0.098 1.2678 ;
		END

		ANTENNAGATEAREA 0.00027817 ;
		ANTENNADIFFAREA 0.00194719 ;
		ANTENNAPARTIALMETALAREA 0.00195671 ;
	END TWENA[1]

	PIN TWENA[20]
		USE SIGNAL ;
		DIRECTION INPUT ;
		SHAPE ABUTMENT ;
		PORT
			 LAYER M2 ;
			RECT 0.0714 16.2635 0.1097 16.3012 ;
			 LAYER M3 ;
			RECT 0.0714 16.2008 0.1097 16.3012 ;
			 LAYER V2 ;
			RECT 0.0831 16.2765 0.098 16.289 ;
		END

		ANTENNAGATEAREA 0.00027817 ;
		ANTENNADIFFAREA 0.00194719 ;
		ANTENNAPARTIALMETALAREA 0.00195671 ;
	END TWENA[20]

	PIN TWENA[21]
		USE SIGNAL ;
		DIRECTION INPUT ;
		SHAPE ABUTMENT ;
		PORT
			 LAYER M2 ;
			RECT 0.0714 17.0541 0.1097 17.0918 ;
			 LAYER M3 ;
			RECT 0.0714 16.9914 0.1097 17.0918 ;
			 LAYER V2 ;
			RECT 0.0831 17.0671 0.098 17.0796 ;
		END

		ANTENNAGATEAREA 0.00027817 ;
		ANTENNADIFFAREA 0.00194719 ;
		ANTENNAPARTIALMETALAREA 0.00195671 ;
	END TWENA[21]

	PIN TWENA[22]
		USE SIGNAL ;
		DIRECTION INPUT ;
		SHAPE ABUTMENT ;
		PORT
			 LAYER M2 ;
			RECT 0.0714 17.8447 0.1097 17.8824 ;
			 LAYER M3 ;
			RECT 0.0714 17.782 0.1097 17.8824 ;
			 LAYER V2 ;
			RECT 0.0831 17.8576 0.098 17.8702 ;
		END

		ANTENNAGATEAREA 0.00027817 ;
		ANTENNADIFFAREA 0.00194719 ;
		ANTENNAPARTIALMETALAREA 0.00195671 ;
	END TWENA[22]

	PIN TWENA[23]
		USE SIGNAL ;
		DIRECTION INPUT ;
		SHAPE ABUTMENT ;
		PORT
			 LAYER M2 ;
			RECT 0.0714 18.6353 0.1097 18.6729 ;
			 LAYER M3 ;
			RECT 0.0714 18.5725 0.1097 18.6729 ;
			 LAYER V2 ;
			RECT 0.0831 18.6482 0.098 18.6608 ;
		END

		ANTENNAGATEAREA 0.00027817 ;
		ANTENNADIFFAREA 0.00194719 ;
		ANTENNAPARTIALMETALAREA 0.00195671 ;
	END TWENA[23]

	PIN TWENA[24]
		USE SIGNAL ;
		DIRECTION INPUT ;
		SHAPE ABUTMENT ;
		PORT
			 LAYER M2 ;
			RECT 0.0714 19.4259 0.1097 19.4635 ;
			 LAYER M3 ;
			RECT 0.0714 19.3631 0.1097 19.4635 ;
			 LAYER V2 ;
			RECT 0.0831 19.4388 0.098 19.4514 ;
		END

		ANTENNAGATEAREA 0.00027817 ;
		ANTENNADIFFAREA 0.00194719 ;
		ANTENNAPARTIALMETALAREA 0.00195671 ;
	END TWENA[24]

	PIN TWENA[25]
		USE SIGNAL ;
		DIRECTION INPUT ;
		SHAPE ABUTMENT ;
		PORT
			 LAYER M2 ;
			RECT 0.0714 20.2165 0.1097 20.2541 ;
			 LAYER M3 ;
			RECT 0.0714 20.1537 0.1097 20.2541 ;
			 LAYER V2 ;
			RECT 0.0831 20.2294 0.098 20.242 ;
		END

		ANTENNAGATEAREA 0.00027817 ;
		ANTENNADIFFAREA 0.00194719 ;
		ANTENNAPARTIALMETALAREA 0.00195671 ;
	END TWENA[25]

	PIN TWENA[26]
		USE SIGNAL ;
		DIRECTION INPUT ;
		SHAPE ABUTMENT ;
		PORT
			 LAYER M2 ;
			RECT 0.0714 21.0071 0.1097 21.0447 ;
			 LAYER M3 ;
			RECT 0.0714 20.9443 0.1097 21.0447 ;
			 LAYER V2 ;
			RECT 0.0831 21.02 0.098 21.0325 ;
		END

		ANTENNAGATEAREA 0.00027817 ;
		ANTENNADIFFAREA 0.00194719 ;
		ANTENNAPARTIALMETALAREA 0.00195671 ;
	END TWENA[26]

	PIN TWENA[27]
		USE SIGNAL ;
		DIRECTION INPUT ;
		SHAPE ABUTMENT ;
		PORT
			 LAYER M2 ;
			RECT 0.0714 21.7976 0.1097 21.8353 ;
			 LAYER M3 ;
			RECT 0.0714 21.7349 0.1097 21.8353 ;
			 LAYER V2 ;
			RECT 0.0831 21.8106 0.098 21.8231 ;
		END

		ANTENNAGATEAREA 0.00027817 ;
		ANTENNADIFFAREA 0.00194719 ;
		ANTENNAPARTIALMETALAREA 0.00195671 ;
	END TWENA[27]

	PIN TWENA[28]
		USE SIGNAL ;
		DIRECTION INPUT ;
		SHAPE ABUTMENT ;
		PORT
			 LAYER M2 ;
			RECT 0.0714 22.5882 0.1097 22.6259 ;
			 LAYER M3 ;
			RECT 0.0714 22.5255 0.1097 22.6259 ;
			 LAYER V2 ;
			RECT 0.0831 22.6012 0.098 22.6137 ;
		END

		ANTENNAGATEAREA 0.00027817 ;
		ANTENNADIFFAREA 0.00194719 ;
		ANTENNAPARTIALMETALAREA 0.00195671 ;
	END TWENA[28]

	PIN TWENA[29]
		USE SIGNAL ;
		DIRECTION INPUT ;
		SHAPE ABUTMENT ;
		PORT
			 LAYER M2 ;
			RECT 0.0714 23.3788 0.1097 23.4165 ;
			 LAYER M3 ;
			RECT 0.0714 23.3161 0.1097 23.4165 ;
			 LAYER V2 ;
			RECT 0.0831 23.3918 0.098 23.4043 ;
		END

		ANTENNAGATEAREA 0.00027817 ;
		ANTENNADIFFAREA 0.00194719 ;
		ANTENNAPARTIALMETALAREA 0.00195671 ;
	END TWENA[29]

	PIN TWENA[2]
		USE SIGNAL ;
		DIRECTION INPUT ;
		SHAPE ABUTMENT ;
		PORT
			 LAYER M2 ;
			RECT 0.0714 2.0329 0.1097 2.0706 ;
			 LAYER M3 ;
			RECT 0.0714 1.9702 0.1097 2.0706 ;
			 LAYER V2 ;
			RECT 0.0831 2.0459 0.098 2.0584 ;
		END

		ANTENNAGATEAREA 0.00027817 ;
		ANTENNADIFFAREA 0.00194719 ;
		ANTENNAPARTIALMETALAREA 0.00195671 ;
	END TWENA[2]

	PIN TWENA[30]
		USE SIGNAL ;
		DIRECTION INPUT ;
		SHAPE ABUTMENT ;
		PORT
			 LAYER M2 ;
			RECT 0.0714 24.1694 0.1097 24.2071 ;
			 LAYER M3 ;
			RECT 0.0714 24.1067 0.1097 24.2071 ;
			 LAYER V2 ;
			RECT 0.0831 24.1824 0.098 24.1949 ;
		END

		ANTENNAGATEAREA 0.00027817 ;
		ANTENNADIFFAREA 0.00194719 ;
		ANTENNAPARTIALMETALAREA 0.00195671 ;
	END TWENA[30]

	PIN TWENA[31]
		USE SIGNAL ;
		DIRECTION INPUT ;
		SHAPE ABUTMENT ;
		PORT
			 LAYER M2 ;
			RECT 0.0714 24.96 0.1097 24.9976 ;
			 LAYER M3 ;
			RECT 0.0714 24.8973 0.1097 24.9976 ;
			 LAYER V2 ;
			RECT 0.0831 24.9729 0.098 24.9855 ;
		END

		ANTENNAGATEAREA 0.00027817 ;
		ANTENNADIFFAREA 0.00194719 ;
		ANTENNAPARTIALMETALAREA 0.00195671 ;
	END TWENA[31]

	PIN TWENA[32]
		USE SIGNAL ;
		DIRECTION INPUT ;
		SHAPE ABUTMENT ;
		PORT
			 LAYER M2 ;
			RECT 0.0714 25.7506 0.1097 25.7882 ;
			 LAYER M3 ;
			RECT 0.0714 25.6878 0.1097 25.7882 ;
			 LAYER V2 ;
			RECT 0.0831 25.7635 0.098 25.7761 ;
		END

		ANTENNAGATEAREA 0.00027817 ;
		ANTENNADIFFAREA 0.00194719 ;
		ANTENNAPARTIALMETALAREA 0.00195671 ;
	END TWENA[32]

	PIN TWENA[33]
		USE SIGNAL ;
		DIRECTION INPUT ;
		SHAPE ABUTMENT ;
		PORT
			 LAYER M2 ;
			RECT 0.0714 35.8588 0.1097 35.8965 ;
			 LAYER M3 ;
			RECT 0.0714 35.8588 0.1097 35.9592 ;
			 LAYER V2 ;
			RECT 0.0831 35.871 0.098 35.8835 ;
		END

		ANTENNAGATEAREA 0.00027817 ;
		ANTENNADIFFAREA 0.00194719 ;
		ANTENNAPARTIALMETALAREA 0.00195671 ;
	END TWENA[33]

	PIN TWENA[34]
		USE SIGNAL ;
		DIRECTION INPUT ;
		SHAPE ABUTMENT ;
		PORT
			 LAYER M2 ;
			RECT 0.0714 36.6494 0.1097 36.6871 ;
			 LAYER M3 ;
			RECT 0.0714 36.6494 0.1097 36.7498 ;
			 LAYER V2 ;
			RECT 0.0831 36.6616 0.098 36.6741 ;
		END

		ANTENNAGATEAREA 0.00027817 ;
		ANTENNADIFFAREA 0.00194719 ;
		ANTENNAPARTIALMETALAREA 0.00195671 ;
	END TWENA[34]

	PIN TWENA[35]
		USE SIGNAL ;
		DIRECTION INPUT ;
		SHAPE ABUTMENT ;
		PORT
			 LAYER M2 ;
			RECT 0.0714 37.44 0.1097 37.4776 ;
			 LAYER M3 ;
			RECT 0.0714 37.44 0.1097 37.5404 ;
			 LAYER V2 ;
			RECT 0.0831 37.4522 0.098 37.4647 ;
		END

		ANTENNAGATEAREA 0.00027817 ;
		ANTENNADIFFAREA 0.00194719 ;
		ANTENNAPARTIALMETALAREA 0.00195671 ;
	END TWENA[35]

	PIN TWENA[36]
		USE SIGNAL ;
		DIRECTION INPUT ;
		SHAPE ABUTMENT ;
		PORT
			 LAYER M2 ;
			RECT 0.0714 38.2306 0.1097 38.2682 ;
			 LAYER M3 ;
			RECT 0.0714 38.2306 0.1097 38.331 ;
			 LAYER V2 ;
			RECT 0.0831 38.2427 0.098 38.2553 ;
		END

		ANTENNAGATEAREA 0.00027817 ;
		ANTENNADIFFAREA 0.00194719 ;
		ANTENNAPARTIALMETALAREA 0.00195671 ;
	END TWENA[36]

	PIN TWENA[37]
		USE SIGNAL ;
		DIRECTION INPUT ;
		SHAPE ABUTMENT ;
		PORT
			 LAYER M2 ;
			RECT 0.0714 39.0212 0.1097 39.0588 ;
			 LAYER M3 ;
			RECT 0.0714 39.0212 0.1097 39.1216 ;
			 LAYER V2 ;
			RECT 0.0831 39.0333 0.098 39.0459 ;
		END

		ANTENNAGATEAREA 0.00027817 ;
		ANTENNADIFFAREA 0.00194719 ;
		ANTENNAPARTIALMETALAREA 0.00195671 ;
	END TWENA[37]

	PIN TWENA[38]
		USE SIGNAL ;
		DIRECTION INPUT ;
		SHAPE ABUTMENT ;
		PORT
			 LAYER M2 ;
			RECT 0.0714 39.8118 0.1097 39.8494 ;
			 LAYER M3 ;
			RECT 0.0714 39.8118 0.1097 39.9122 ;
			 LAYER V2 ;
			RECT 0.0831 39.8239 0.098 39.8365 ;
		END

		ANTENNAGATEAREA 0.00027817 ;
		ANTENNADIFFAREA 0.00194719 ;
		ANTENNAPARTIALMETALAREA 0.00195671 ;
	END TWENA[38]

	PIN TWENA[39]
		USE SIGNAL ;
		DIRECTION INPUT ;
		SHAPE ABUTMENT ;
		PORT
			 LAYER M2 ;
			RECT 0.0714 40.6024 0.1097 40.64 ;
			 LAYER M3 ;
			RECT 0.0714 40.6024 0.1097 40.7027 ;
			 LAYER V2 ;
			RECT 0.0831 40.6145 0.098 40.6271 ;
		END

		ANTENNAGATEAREA 0.00027817 ;
		ANTENNADIFFAREA 0.00194719 ;
		ANTENNAPARTIALMETALAREA 0.00195671 ;
	END TWENA[39]

	PIN TWENA[3]
		USE SIGNAL ;
		DIRECTION INPUT ;
		SHAPE ABUTMENT ;
		PORT
			 LAYER M2 ;
			RECT 0.0714 2.8235 0.1097 2.8612 ;
			 LAYER M3 ;
			RECT 0.0714 2.7608 0.1097 2.8612 ;
			 LAYER V2 ;
			RECT 0.0831 2.8365 0.098 2.849 ;
		END

		ANTENNAGATEAREA 0.00027817 ;
		ANTENNADIFFAREA 0.00194719 ;
		ANTENNAPARTIALMETALAREA 0.00195671 ;
	END TWENA[3]

	PIN TWENA[40]
		USE SIGNAL ;
		DIRECTION INPUT ;
		SHAPE ABUTMENT ;
		PORT
			 LAYER M2 ;
			RECT 0.0714 41.3929 0.1097 41.4306 ;
			 LAYER M3 ;
			RECT 0.0714 41.3929 0.1097 41.4933 ;
			 LAYER V2 ;
			RECT 0.0831 41.4051 0.098 41.4176 ;
		END

		ANTENNAGATEAREA 0.00027817 ;
		ANTENNADIFFAREA 0.00194719 ;
		ANTENNAPARTIALMETALAREA 0.00195671 ;
	END TWENA[40]

	PIN TWENA[41]
		USE SIGNAL ;
		DIRECTION INPUT ;
		SHAPE ABUTMENT ;
		PORT
			 LAYER M2 ;
			RECT 0.0714 42.1835 0.1097 42.2212 ;
			 LAYER M3 ;
			RECT 0.0714 42.1835 0.1097 42.2839 ;
			 LAYER V2 ;
			RECT 0.0831 42.1957 0.098 42.2082 ;
		END

		ANTENNAGATEAREA 0.00027817 ;
		ANTENNADIFFAREA 0.00194719 ;
		ANTENNAPARTIALMETALAREA 0.00195671 ;
	END TWENA[41]

	PIN TWENA[42]
		USE SIGNAL ;
		DIRECTION INPUT ;
		SHAPE ABUTMENT ;
		PORT
			 LAYER M2 ;
			RECT 0.0714 42.9741 0.1097 43.0118 ;
			 LAYER M3 ;
			RECT 0.0714 42.9741 0.1097 43.0745 ;
			 LAYER V2 ;
			RECT 0.0831 42.9863 0.098 42.9988 ;
		END

		ANTENNAGATEAREA 0.00027817 ;
		ANTENNADIFFAREA 0.00194719 ;
		ANTENNAPARTIALMETALAREA 0.00195671 ;
	END TWENA[42]

	PIN TWENA[43]
		USE SIGNAL ;
		DIRECTION INPUT ;
		SHAPE ABUTMENT ;
		PORT
			 LAYER M2 ;
			RECT 0.0714 43.7647 0.1097 43.8024 ;
			 LAYER M3 ;
			RECT 0.0714 43.7647 0.1097 43.8651 ;
			 LAYER V2 ;
			RECT 0.0831 43.7769 0.098 43.7894 ;
		END

		ANTENNAGATEAREA 0.00027817 ;
		ANTENNADIFFAREA 0.00194719 ;
		ANTENNAPARTIALMETALAREA 0.00195671 ;
	END TWENA[43]

	PIN TWENA[44]
		USE SIGNAL ;
		DIRECTION INPUT ;
		SHAPE ABUTMENT ;
		PORT
			 LAYER M2 ;
			RECT 0.0714 44.5553 0.1097 44.5929 ;
			 LAYER M3 ;
			RECT 0.0714 44.5553 0.1097 44.6557 ;
			 LAYER V2 ;
			RECT 0.0831 44.5675 0.098 44.58 ;
		END

		ANTENNAGATEAREA 0.00027817 ;
		ANTENNADIFFAREA 0.00194719 ;
		ANTENNAPARTIALMETALAREA 0.00195671 ;
	END TWENA[44]

	PIN TWENA[45]
		USE SIGNAL ;
		DIRECTION INPUT ;
		SHAPE ABUTMENT ;
		PORT
			 LAYER M2 ;
			RECT 0.0714 45.3459 0.1097 45.3835 ;
			 LAYER M3 ;
			RECT 0.0714 45.3459 0.1097 45.4463 ;
			 LAYER V2 ;
			RECT 0.0831 45.358 0.098 45.3706 ;
		END

		ANTENNAGATEAREA 0.00027817 ;
		ANTENNADIFFAREA 0.00194719 ;
		ANTENNAPARTIALMETALAREA 0.00195671 ;
	END TWENA[45]

	PIN TWENA[46]
		USE SIGNAL ;
		DIRECTION INPUT ;
		SHAPE ABUTMENT ;
		PORT
			 LAYER M2 ;
			RECT 0.0714 46.1365 0.1097 46.1741 ;
			 LAYER M3 ;
			RECT 0.0714 46.1365 0.1097 46.2369 ;
			 LAYER V2 ;
			RECT 0.0831 46.1486 0.098 46.1612 ;
		END

		ANTENNAGATEAREA 0.00027817 ;
		ANTENNADIFFAREA 0.00194719 ;
		ANTENNAPARTIALMETALAREA 0.00195671 ;
	END TWENA[46]

	PIN TWENA[47]
		USE SIGNAL ;
		DIRECTION INPUT ;
		SHAPE ABUTMENT ;
		PORT
			 LAYER M2 ;
			RECT 0.0714 46.9271 0.1097 46.9647 ;
			 LAYER M3 ;
			RECT 0.0714 46.9271 0.1097 47.0275 ;
			 LAYER V2 ;
			RECT 0.0831 46.9392 0.098 46.9518 ;
		END

		ANTENNAGATEAREA 0.00027817 ;
		ANTENNADIFFAREA 0.00194719 ;
		ANTENNAPARTIALMETALAREA 0.00195671 ;
	END TWENA[47]

	PIN TWENA[48]
		USE SIGNAL ;
		DIRECTION INPUT ;
		SHAPE ABUTMENT ;
		PORT
			 LAYER M2 ;
			RECT 0.0714 47.7176 0.1097 47.7553 ;
			 LAYER M3 ;
			RECT 0.0714 47.7176 0.1097 47.818 ;
			 LAYER V2 ;
			RECT 0.0831 47.7298 0.098 47.7424 ;
		END

		ANTENNAGATEAREA 0.00027817 ;
		ANTENNADIFFAREA 0.00194719 ;
		ANTENNAPARTIALMETALAREA 0.00195671 ;
	END TWENA[48]

	PIN TWENA[49]
		USE SIGNAL ;
		DIRECTION INPUT ;
		SHAPE ABUTMENT ;
		PORT
			 LAYER M2 ;
			RECT 0.0714 48.5082 0.1097 48.5459 ;
			 LAYER M3 ;
			RECT 0.0714 48.5082 0.1097 48.6086 ;
			 LAYER V2 ;
			RECT 0.0831 48.5204 0.098 48.5329 ;
		END

		ANTENNAGATEAREA 0.00027817 ;
		ANTENNADIFFAREA 0.00194719 ;
		ANTENNAPARTIALMETALAREA 0.00195671 ;
	END TWENA[49]

	PIN TWENA[4]
		USE SIGNAL ;
		DIRECTION INPUT ;
		SHAPE ABUTMENT ;
		PORT
			 LAYER M2 ;
			RECT 0.0714 3.6141 0.1097 3.6518 ;
			 LAYER M3 ;
			RECT 0.0714 3.5514 0.1097 3.6518 ;
			 LAYER V2 ;
			RECT 0.0831 3.6271 0.098 3.6396 ;
		END

		ANTENNAGATEAREA 0.00027817 ;
		ANTENNADIFFAREA 0.00194719 ;
		ANTENNAPARTIALMETALAREA 0.00195671 ;
	END TWENA[4]

	PIN TWENA[50]
		USE SIGNAL ;
		DIRECTION INPUT ;
		SHAPE ABUTMENT ;
		PORT
			 LAYER M2 ;
			RECT 0.0714 49.2988 0.1097 49.3365 ;
			 LAYER M3 ;
			RECT 0.0714 49.2988 0.1097 49.3992 ;
			 LAYER V2 ;
			RECT 0.0831 49.311 0.098 49.3235 ;
		END

		ANTENNAGATEAREA 0.00027817 ;
		ANTENNADIFFAREA 0.00194719 ;
		ANTENNAPARTIALMETALAREA 0.00195671 ;
	END TWENA[50]

	PIN TWENA[51]
		USE SIGNAL ;
		DIRECTION INPUT ;
		SHAPE ABUTMENT ;
		PORT
			 LAYER M2 ;
			RECT 0.0714 50.0894 0.1097 50.1271 ;
			 LAYER M3 ;
			RECT 0.0714 50.0894 0.1097 50.1898 ;
			 LAYER V2 ;
			RECT 0.0831 50.1016 0.098 50.1141 ;
		END

		ANTENNAGATEAREA 0.00027817 ;
		ANTENNADIFFAREA 0.00194719 ;
		ANTENNAPARTIALMETALAREA 0.00195671 ;
	END TWENA[51]

	PIN TWENA[52]
		USE SIGNAL ;
		DIRECTION INPUT ;
		SHAPE ABUTMENT ;
		PORT
			 LAYER M2 ;
			RECT 0.0714 50.88 0.1097 50.9176 ;
			 LAYER M3 ;
			RECT 0.0714 50.88 0.1097 50.9804 ;
			 LAYER V2 ;
			RECT 0.0831 50.8922 0.098 50.9047 ;
		END

		ANTENNAGATEAREA 0.00027817 ;
		ANTENNADIFFAREA 0.00194719 ;
		ANTENNAPARTIALMETALAREA 0.00195671 ;
	END TWENA[52]

	PIN TWENA[53]
		USE SIGNAL ;
		DIRECTION INPUT ;
		SHAPE ABUTMENT ;
		PORT
			 LAYER M2 ;
			RECT 0.0714 51.6706 0.1097 51.7082 ;
			 LAYER M3 ;
			RECT 0.0714 51.6706 0.1097 51.771 ;
			 LAYER V2 ;
			RECT 0.0831 51.6827 0.098 51.6953 ;
		END

		ANTENNAGATEAREA 0.00027817 ;
		ANTENNADIFFAREA 0.00194719 ;
		ANTENNAPARTIALMETALAREA 0.00195671 ;
	END TWENA[53]

	PIN TWENA[54]
		USE SIGNAL ;
		DIRECTION INPUT ;
		SHAPE ABUTMENT ;
		PORT
			 LAYER M2 ;
			RECT 0.0714 52.4612 0.1097 52.4988 ;
			 LAYER M3 ;
			RECT 0.0714 52.4612 0.1097 52.5616 ;
			 LAYER V2 ;
			RECT 0.0831 52.4733 0.098 52.4859 ;
		END

		ANTENNAGATEAREA 0.00027817 ;
		ANTENNADIFFAREA 0.00194719 ;
		ANTENNAPARTIALMETALAREA 0.00195671 ;
	END TWENA[54]

	PIN TWENA[55]
		USE SIGNAL ;
		DIRECTION INPUT ;
		SHAPE ABUTMENT ;
		PORT
			 LAYER M2 ;
			RECT 0.0714 53.2518 0.1097 53.2894 ;
			 LAYER M3 ;
			RECT 0.0714 53.2518 0.1097 53.3522 ;
			 LAYER V2 ;
			RECT 0.0831 53.2639 0.098 53.2765 ;
		END

		ANTENNAGATEAREA 0.00027817 ;
		ANTENNADIFFAREA 0.00194719 ;
		ANTENNAPARTIALMETALAREA 0.00195671 ;
	END TWENA[55]

	PIN TWENA[56]
		USE SIGNAL ;
		DIRECTION INPUT ;
		SHAPE ABUTMENT ;
		PORT
			 LAYER M2 ;
			RECT 0.0714 54.0424 0.1097 54.08 ;
			 LAYER M3 ;
			RECT 0.0714 54.0424 0.1097 54.1427 ;
			 LAYER V2 ;
			RECT 0.0831 54.0545 0.098 54.0671 ;
		END

		ANTENNAGATEAREA 0.00027817 ;
		ANTENNADIFFAREA 0.00194719 ;
		ANTENNAPARTIALMETALAREA 0.00195671 ;
	END TWENA[56]

	PIN TWENA[57]
		USE SIGNAL ;
		DIRECTION INPUT ;
		SHAPE ABUTMENT ;
		PORT
			 LAYER M2 ;
			RECT 0.0714 54.8329 0.1097 54.8706 ;
			 LAYER M3 ;
			RECT 0.0714 54.8329 0.1097 54.9333 ;
			 LAYER V2 ;
			RECT 0.0831 54.8451 0.098 54.8576 ;
		END

		ANTENNAGATEAREA 0.00027817 ;
		ANTENNADIFFAREA 0.00194719 ;
		ANTENNAPARTIALMETALAREA 0.00195671 ;
	END TWENA[57]

	PIN TWENA[58]
		USE SIGNAL ;
		DIRECTION INPUT ;
		SHAPE ABUTMENT ;
		PORT
			 LAYER M2 ;
			RECT 0.0714 55.6235 0.1097 55.6612 ;
			 LAYER M3 ;
			RECT 0.0714 55.6235 0.1097 55.7239 ;
			 LAYER V2 ;
			RECT 0.0831 55.6357 0.098 55.6482 ;
		END

		ANTENNAGATEAREA 0.00027817 ;
		ANTENNADIFFAREA 0.00194719 ;
		ANTENNAPARTIALMETALAREA 0.00195671 ;
	END TWENA[58]

	PIN TWENA[59]
		USE SIGNAL ;
		DIRECTION INPUT ;
		SHAPE ABUTMENT ;
		PORT
			 LAYER M2 ;
			RECT 0.0714 56.4141 0.1097 56.4518 ;
			 LAYER M3 ;
			RECT 0.0714 56.4141 0.1097 56.5145 ;
			 LAYER V2 ;
			RECT 0.0831 56.4263 0.098 56.4388 ;
		END

		ANTENNAGATEAREA 0.00027817 ;
		ANTENNADIFFAREA 0.00194719 ;
		ANTENNAPARTIALMETALAREA 0.00195671 ;
	END TWENA[59]

	PIN TWENA[5]
		USE SIGNAL ;
		DIRECTION INPUT ;
		SHAPE ABUTMENT ;
		PORT
			 LAYER M2 ;
			RECT 0.0714 4.4047 0.1097 4.4424 ;
			 LAYER M3 ;
			RECT 0.0714 4.342 0.1097 4.4424 ;
			 LAYER V2 ;
			RECT 0.0831 4.4176 0.098 4.4302 ;
		END

		ANTENNAGATEAREA 0.00027817 ;
		ANTENNADIFFAREA 0.00194719 ;
		ANTENNAPARTIALMETALAREA 0.00195671 ;
	END TWENA[5]

	PIN TWENA[60]
		USE SIGNAL ;
		DIRECTION INPUT ;
		SHAPE ABUTMENT ;
		PORT
			 LAYER M2 ;
			RECT 0.0714 57.2047 0.1097 57.2424 ;
			 LAYER M3 ;
			RECT 0.0714 57.2047 0.1097 57.3051 ;
			 LAYER V2 ;
			RECT 0.0831 57.2169 0.098 57.2294 ;
		END

		ANTENNAGATEAREA 0.00027817 ;
		ANTENNADIFFAREA 0.00194719 ;
		ANTENNAPARTIALMETALAREA 0.00195671 ;
	END TWENA[60]

	PIN TWENA[61]
		USE SIGNAL ;
		DIRECTION INPUT ;
		SHAPE ABUTMENT ;
		PORT
			 LAYER M2 ;
			RECT 0.0714 57.9953 0.1097 58.0329 ;
			 LAYER M3 ;
			RECT 0.0714 57.9953 0.1097 58.0957 ;
			 LAYER V2 ;
			RECT 0.0831 58.0075 0.098 58.02 ;
		END

		ANTENNAGATEAREA 0.00027817 ;
		ANTENNADIFFAREA 0.00194719 ;
		ANTENNAPARTIALMETALAREA 0.00195671 ;
	END TWENA[61]

	PIN TWENA[62]
		USE SIGNAL ;
		DIRECTION INPUT ;
		SHAPE ABUTMENT ;
		PORT
			 LAYER M2 ;
			RECT 0.0714 58.7859 0.1097 58.8235 ;
			 LAYER M3 ;
			RECT 0.0714 58.7859 0.1097 58.8863 ;
			 LAYER V2 ;
			RECT 0.0831 58.798 0.098 58.8106 ;
		END

		ANTENNAGATEAREA 0.00027817 ;
		ANTENNADIFFAREA 0.00194719 ;
		ANTENNAPARTIALMETALAREA 0.00195671 ;
	END TWENA[62]

	PIN TWENA[63]
		USE SIGNAL ;
		DIRECTION INPUT ;
		SHAPE ABUTMENT ;
		PORT
			 LAYER M2 ;
			RECT 0.0714 59.5765 0.1097 59.6141 ;
			 LAYER M3 ;
			RECT 0.0714 59.5765 0.1097 59.6769 ;
			 LAYER V2 ;
			RECT 0.0831 59.5886 0.098 59.6012 ;
		END

		ANTENNAGATEAREA 0.00027817 ;
		ANTENNADIFFAREA 0.00194719 ;
		ANTENNAPARTIALMETALAREA 0.00195671 ;
	END TWENA[63]

	PIN TWENA[64]
		USE SIGNAL ;
		DIRECTION INPUT ;
		SHAPE ABUTMENT ;
		PORT
			 LAYER M2 ;
			RECT 0.0714 60.3671 0.1097 60.4047 ;
			 LAYER M3 ;
			RECT 0.0714 60.3671 0.1097 60.4675 ;
			 LAYER V2 ;
			RECT 0.0831 60.3792 0.098 60.3918 ;
		END

		ANTENNAGATEAREA 0.00027817 ;
		ANTENNADIFFAREA 0.00194719 ;
		ANTENNAPARTIALMETALAREA 0.00195671 ;
	END TWENA[64]

	PIN TWENA[65]
		USE SIGNAL ;
		DIRECTION INPUT ;
		SHAPE ABUTMENT ;
		PORT
			 LAYER M2 ;
			RECT 0.0714 61.1576 0.1097 61.1953 ;
			 LAYER M3 ;
			RECT 0.0714 61.1576 0.1097 61.258 ;
			 LAYER V2 ;
			RECT 0.0831 61.1698 0.098 61.1824 ;
		END

		ANTENNAGATEAREA 0.00027817 ;
		ANTENNADIFFAREA 0.00194719 ;
		ANTENNAPARTIALMETALAREA 0.00195671 ;
	END TWENA[65]

	PIN TWENA[6]
		USE SIGNAL ;
		DIRECTION INPUT ;
		SHAPE ABUTMENT ;
		PORT
			 LAYER M2 ;
			RECT 0.0714 5.1953 0.1097 5.2329 ;
			 LAYER M3 ;
			RECT 0.0714 5.1325 0.1097 5.2329 ;
			 LAYER V2 ;
			RECT 0.0831 5.2082 0.098 5.2208 ;
		END

		ANTENNAGATEAREA 0.00027817 ;
		ANTENNADIFFAREA 0.00194719 ;
		ANTENNAPARTIALMETALAREA 0.00195671 ;
	END TWENA[6]

	PIN TWENA[7]
		USE SIGNAL ;
		DIRECTION INPUT ;
		SHAPE ABUTMENT ;
		PORT
			 LAYER M2 ;
			RECT 0.0714 5.9859 0.1097 6.0235 ;
			 LAYER M3 ;
			RECT 0.0714 5.9231 0.1097 6.0235 ;
			 LAYER V2 ;
			RECT 0.0831 5.9988 0.098 6.0114 ;
		END

		ANTENNAGATEAREA 0.00027817 ;
		ANTENNADIFFAREA 0.00194719 ;
		ANTENNAPARTIALMETALAREA 0.00195671 ;
	END TWENA[7]

	PIN TWENA[8]
		USE SIGNAL ;
		DIRECTION INPUT ;
		SHAPE ABUTMENT ;
		PORT
			 LAYER M2 ;
			RECT 0.0714 6.7765 0.1097 6.8141 ;
			 LAYER M3 ;
			RECT 0.0714 6.7137 0.1097 6.8141 ;
			 LAYER V2 ;
			RECT 0.0831 6.7894 0.098 6.802 ;
		END

		ANTENNAGATEAREA 0.00027817 ;
		ANTENNADIFFAREA 0.00194719 ;
		ANTENNAPARTIALMETALAREA 0.00195671 ;
	END TWENA[8]

	PIN TWENA[9]
		USE SIGNAL ;
		DIRECTION INPUT ;
		SHAPE ABUTMENT ;
		PORT
			 LAYER M2 ;
			RECT 0.0714 7.5671 0.1097 7.6047 ;
			 LAYER M3 ;
			RECT 0.0714 7.5043 0.1097 7.6047 ;
			 LAYER V2 ;
			RECT 0.0831 7.58 0.098 7.5925 ;
		END

		ANTENNAGATEAREA 0.00027817 ;
		ANTENNADIFFAREA 0.00194719 ;
		ANTENNAPARTIALMETALAREA 0.00195671 ;
	END TWENA[9]

	PIN TWENB[0]
		USE SIGNAL ;
		DIRECTION INPUT ;
		SHAPE ABUTMENT ;
		PORT
			 LAYER M3 ;
			RECT 0.0714 0.2384 0.1097 0.3388 ;
		END

		ANTENNAGATEAREA 0.00027817 ;
		ANTENNADIFFAREA 0.00194719 ;
		ANTENNAPARTIALMETALAREA 0.00195671 ;
	END TWENB[0]

	PIN TWENB[10]
		USE SIGNAL ;
		DIRECTION INPUT ;
		SHAPE ABUTMENT ;
		PORT
			 LAYER M3 ;
			RECT 0.0714 8.1443 0.1097 8.2447 ;
		END

		ANTENNAGATEAREA 0.00027817 ;
		ANTENNADIFFAREA 0.00194719 ;
		ANTENNAPARTIALMETALAREA 0.00195671 ;
	END TWENB[10]

	PIN TWENB[11]
		USE SIGNAL ;
		DIRECTION INPUT ;
		SHAPE ABUTMENT ;
		PORT
			 LAYER M3 ;
			RECT 0.0714 8.9349 0.1097 9.0353 ;
		END

		ANTENNAGATEAREA 0.00027817 ;
		ANTENNADIFFAREA 0.00194719 ;
		ANTENNAPARTIALMETALAREA 0.00195671 ;
	END TWENB[11]

	PIN TWENB[12]
		USE SIGNAL ;
		DIRECTION INPUT ;
		SHAPE ABUTMENT ;
		PORT
			 LAYER M3 ;
			RECT 0.0714 9.7255 0.1097 9.8259 ;
		END

		ANTENNAGATEAREA 0.00027817 ;
		ANTENNADIFFAREA 0.00194719 ;
		ANTENNAPARTIALMETALAREA 0.00195671 ;
	END TWENB[12]

	PIN TWENB[13]
		USE SIGNAL ;
		DIRECTION INPUT ;
		SHAPE ABUTMENT ;
		PORT
			 LAYER M3 ;
			RECT 0.0714 10.5161 0.1097 10.6165 ;
		END

		ANTENNAGATEAREA 0.00027817 ;
		ANTENNADIFFAREA 0.00194719 ;
		ANTENNAPARTIALMETALAREA 0.00195671 ;
	END TWENB[13]

	PIN TWENB[14]
		USE SIGNAL ;
		DIRECTION INPUT ;
		SHAPE ABUTMENT ;
		PORT
			 LAYER M3 ;
			RECT 0.0714 11.3067 0.1097 11.4071 ;
		END

		ANTENNAGATEAREA 0.00027817 ;
		ANTENNADIFFAREA 0.00194719 ;
		ANTENNAPARTIALMETALAREA 0.00195671 ;
	END TWENB[14]

	PIN TWENB[15]
		USE SIGNAL ;
		DIRECTION INPUT ;
		SHAPE ABUTMENT ;
		PORT
			 LAYER M3 ;
			RECT 0.0714 12.0973 0.1097 12.1976 ;
		END

		ANTENNAGATEAREA 0.00027817 ;
		ANTENNADIFFAREA 0.00194719 ;
		ANTENNAPARTIALMETALAREA 0.00195671 ;
	END TWENB[15]

	PIN TWENB[16]
		USE SIGNAL ;
		DIRECTION INPUT ;
		SHAPE ABUTMENT ;
		PORT
			 LAYER M3 ;
			RECT 0.0714 12.8878 0.1097 12.9882 ;
		END

		ANTENNAGATEAREA 0.00027817 ;
		ANTENNADIFFAREA 0.00194719 ;
		ANTENNAPARTIALMETALAREA 0.00195671 ;
	END TWENB[16]

	PIN TWENB[17]
		USE SIGNAL ;
		DIRECTION INPUT ;
		SHAPE ABUTMENT ;
		PORT
			 LAYER M3 ;
			RECT 0.0714 13.6784 0.1097 13.7788 ;
		END

		ANTENNAGATEAREA 0.00027817 ;
		ANTENNADIFFAREA 0.00194719 ;
		ANTENNAPARTIALMETALAREA 0.00195671 ;
	END TWENB[17]

	PIN TWENB[18]
		USE SIGNAL ;
		DIRECTION INPUT ;
		SHAPE ABUTMENT ;
		PORT
			 LAYER M3 ;
			RECT 0.0714 14.469 0.1097 14.5694 ;
		END

		ANTENNAGATEAREA 0.00027817 ;
		ANTENNADIFFAREA 0.00194719 ;
		ANTENNAPARTIALMETALAREA 0.00195671 ;
	END TWENB[18]

	PIN TWENB[19]
		USE SIGNAL ;
		DIRECTION INPUT ;
		SHAPE ABUTMENT ;
		PORT
			 LAYER M3 ;
			RECT 0.0714 15.2596 0.1097 15.36 ;
		END

		ANTENNAGATEAREA 0.00027817 ;
		ANTENNADIFFAREA 0.00194719 ;
		ANTENNAPARTIALMETALAREA 0.00195671 ;
	END TWENB[19]

	PIN TWENB[1]
		USE SIGNAL ;
		DIRECTION INPUT ;
		SHAPE ABUTMENT ;
		PORT
			 LAYER M3 ;
			RECT 0.0714 1.029 0.1097 1.1294 ;
		END

		ANTENNAGATEAREA 0.00027817 ;
		ANTENNADIFFAREA 0.00194719 ;
		ANTENNAPARTIALMETALAREA 0.00195671 ;
	END TWENB[1]

	PIN TWENB[20]
		USE SIGNAL ;
		DIRECTION INPUT ;
		SHAPE ABUTMENT ;
		PORT
			 LAYER M3 ;
			RECT 0.0714 16.0502 0.1097 16.1506 ;
		END

		ANTENNAGATEAREA 0.00027817 ;
		ANTENNADIFFAREA 0.00194719 ;
		ANTENNAPARTIALMETALAREA 0.00195671 ;
	END TWENB[20]

	PIN TWENB[21]
		USE SIGNAL ;
		DIRECTION INPUT ;
		SHAPE ABUTMENT ;
		PORT
			 LAYER M3 ;
			RECT 0.0714 16.8408 0.1097 16.9412 ;
		END

		ANTENNAGATEAREA 0.00027817 ;
		ANTENNADIFFAREA 0.00194719 ;
		ANTENNAPARTIALMETALAREA 0.00195671 ;
	END TWENB[21]

	PIN TWENB[22]
		USE SIGNAL ;
		DIRECTION INPUT ;
		SHAPE ABUTMENT ;
		PORT
			 LAYER M3 ;
			RECT 0.0714 17.6314 0.1097 17.7318 ;
		END

		ANTENNAGATEAREA 0.00027817 ;
		ANTENNADIFFAREA 0.00194719 ;
		ANTENNAPARTIALMETALAREA 0.00195671 ;
	END TWENB[22]

	PIN TWENB[23]
		USE SIGNAL ;
		DIRECTION INPUT ;
		SHAPE ABUTMENT ;
		PORT
			 LAYER M3 ;
			RECT 0.0714 18.422 0.1097 18.5224 ;
		END

		ANTENNAGATEAREA 0.00027817 ;
		ANTENNADIFFAREA 0.00194719 ;
		ANTENNAPARTIALMETALAREA 0.00195671 ;
	END TWENB[23]

	PIN TWENB[24]
		USE SIGNAL ;
		DIRECTION INPUT ;
		SHAPE ABUTMENT ;
		PORT
			 LAYER M3 ;
			RECT 0.0714 19.2125 0.1097 19.3129 ;
		END

		ANTENNAGATEAREA 0.00027817 ;
		ANTENNADIFFAREA 0.00194719 ;
		ANTENNAPARTIALMETALAREA 0.00195671 ;
	END TWENB[24]

	PIN TWENB[25]
		USE SIGNAL ;
		DIRECTION INPUT ;
		SHAPE ABUTMENT ;
		PORT
			 LAYER M3 ;
			RECT 0.0714 20.0031 0.1097 20.1035 ;
		END

		ANTENNAGATEAREA 0.00027817 ;
		ANTENNADIFFAREA 0.00194719 ;
		ANTENNAPARTIALMETALAREA 0.00195671 ;
	END TWENB[25]

	PIN TWENB[26]
		USE SIGNAL ;
		DIRECTION INPUT ;
		SHAPE ABUTMENT ;
		PORT
			 LAYER M3 ;
			RECT 0.0714 20.7937 0.1097 20.8941 ;
		END

		ANTENNAGATEAREA 0.00027817 ;
		ANTENNADIFFAREA 0.00194719 ;
		ANTENNAPARTIALMETALAREA 0.00195671 ;
	END TWENB[26]

	PIN TWENB[27]
		USE SIGNAL ;
		DIRECTION INPUT ;
		SHAPE ABUTMENT ;
		PORT
			 LAYER M3 ;
			RECT 0.0714 21.5843 0.1097 21.6847 ;
		END

		ANTENNAGATEAREA 0.00027817 ;
		ANTENNADIFFAREA 0.00194719 ;
		ANTENNAPARTIALMETALAREA 0.00195671 ;
	END TWENB[27]

	PIN TWENB[28]
		USE SIGNAL ;
		DIRECTION INPUT ;
		SHAPE ABUTMENT ;
		PORT
			 LAYER M3 ;
			RECT 0.0714 22.3749 0.1097 22.4753 ;
		END

		ANTENNAGATEAREA 0.00027817 ;
		ANTENNADIFFAREA 0.00194719 ;
		ANTENNAPARTIALMETALAREA 0.00195671 ;
	END TWENB[28]

	PIN TWENB[29]
		USE SIGNAL ;
		DIRECTION INPUT ;
		SHAPE ABUTMENT ;
		PORT
			 LAYER M3 ;
			RECT 0.0714 23.1655 0.1097 23.2659 ;
		END

		ANTENNAGATEAREA 0.00027817 ;
		ANTENNADIFFAREA 0.00194719 ;
		ANTENNAPARTIALMETALAREA 0.00195671 ;
	END TWENB[29]

	PIN TWENB[2]
		USE SIGNAL ;
		DIRECTION INPUT ;
		SHAPE ABUTMENT ;
		PORT
			 LAYER M3 ;
			RECT 0.0714 1.8196 0.1097 1.92 ;
		END

		ANTENNAGATEAREA 0.00027817 ;
		ANTENNADIFFAREA 0.00194719 ;
		ANTENNAPARTIALMETALAREA 0.00195671 ;
	END TWENB[2]

	PIN TWENB[30]
		USE SIGNAL ;
		DIRECTION INPUT ;
		SHAPE ABUTMENT ;
		PORT
			 LAYER M3 ;
			RECT 0.0714 23.9561 0.1097 24.0565 ;
		END

		ANTENNAGATEAREA 0.00027817 ;
		ANTENNADIFFAREA 0.00194719 ;
		ANTENNAPARTIALMETALAREA 0.00195671 ;
	END TWENB[30]

	PIN TWENB[31]
		USE SIGNAL ;
		DIRECTION INPUT ;
		SHAPE ABUTMENT ;
		PORT
			 LAYER M3 ;
			RECT 0.0714 24.7467 0.1097 24.8471 ;
		END

		ANTENNAGATEAREA 0.00027817 ;
		ANTENNADIFFAREA 0.00194719 ;
		ANTENNAPARTIALMETALAREA 0.00195671 ;
	END TWENB[31]

	PIN TWENB[32]
		USE SIGNAL ;
		DIRECTION INPUT ;
		SHAPE ABUTMENT ;
		PORT
			 LAYER M3 ;
			RECT 0.0714 25.5373 0.1097 25.6376 ;
		END

		ANTENNAGATEAREA 0.00027817 ;
		ANTENNADIFFAREA 0.00194719 ;
		ANTENNAPARTIALMETALAREA 0.00195671 ;
	END TWENB[32]

	PIN TWENB[33]
		USE SIGNAL ;
		DIRECTION INPUT ;
		SHAPE ABUTMENT ;
		PORT
			 LAYER M3 ;
			RECT 0.0714 36.0094 0.1097 36.1098 ;
		END

		ANTENNAGATEAREA 0.00027817 ;
		ANTENNADIFFAREA 0.00194719 ;
		ANTENNAPARTIALMETALAREA 0.00195671 ;
	END TWENB[33]

	PIN TWENB[34]
		USE SIGNAL ;
		DIRECTION INPUT ;
		SHAPE ABUTMENT ;
		PORT
			 LAYER M3 ;
			RECT 0.0714 36.8 0.1097 36.9004 ;
		END

		ANTENNAGATEAREA 0.00027817 ;
		ANTENNADIFFAREA 0.00194719 ;
		ANTENNAPARTIALMETALAREA 0.00195671 ;
	END TWENB[34]

	PIN TWENB[35]
		USE SIGNAL ;
		DIRECTION INPUT ;
		SHAPE ABUTMENT ;
		PORT
			 LAYER M3 ;
			RECT 0.0714 37.5906 0.1097 37.691 ;
		END

		ANTENNAGATEAREA 0.00027817 ;
		ANTENNADIFFAREA 0.00194719 ;
		ANTENNAPARTIALMETALAREA 0.00195671 ;
	END TWENB[35]

	PIN TWENB[36]
		USE SIGNAL ;
		DIRECTION INPUT ;
		SHAPE ABUTMENT ;
		PORT
			 LAYER M3 ;
			RECT 0.0714 38.3812 0.1097 38.4816 ;
		END

		ANTENNAGATEAREA 0.00027817 ;
		ANTENNADIFFAREA 0.00194719 ;
		ANTENNAPARTIALMETALAREA 0.00195671 ;
	END TWENB[36]

	PIN TWENB[37]
		USE SIGNAL ;
		DIRECTION INPUT ;
		SHAPE ABUTMENT ;
		PORT
			 LAYER M3 ;
			RECT 0.0714 39.1718 0.1097 39.2722 ;
		END

		ANTENNAGATEAREA 0.00027817 ;
		ANTENNADIFFAREA 0.00194719 ;
		ANTENNAPARTIALMETALAREA 0.00195671 ;
	END TWENB[37]

	PIN TWENB[38]
		USE SIGNAL ;
		DIRECTION INPUT ;
		SHAPE ABUTMENT ;
		PORT
			 LAYER M3 ;
			RECT 0.0714 39.9624 0.1097 40.0627 ;
		END

		ANTENNAGATEAREA 0.00027817 ;
		ANTENNADIFFAREA 0.00194719 ;
		ANTENNAPARTIALMETALAREA 0.00195671 ;
	END TWENB[38]

	PIN TWENB[39]
		USE SIGNAL ;
		DIRECTION INPUT ;
		SHAPE ABUTMENT ;
		PORT
			 LAYER M3 ;
			RECT 0.0714 40.7529 0.1097 40.8533 ;
		END

		ANTENNAGATEAREA 0.00027817 ;
		ANTENNADIFFAREA 0.00194719 ;
		ANTENNAPARTIALMETALAREA 0.00195671 ;
	END TWENB[39]

	PIN TWENB[3]
		USE SIGNAL ;
		DIRECTION INPUT ;
		SHAPE ABUTMENT ;
		PORT
			 LAYER M3 ;
			RECT 0.0714 2.6102 0.1097 2.7106 ;
		END

		ANTENNAGATEAREA 0.00027817 ;
		ANTENNADIFFAREA 0.00194719 ;
		ANTENNAPARTIALMETALAREA 0.00195671 ;
	END TWENB[3]

	PIN TWENB[40]
		USE SIGNAL ;
		DIRECTION INPUT ;
		SHAPE ABUTMENT ;
		PORT
			 LAYER M3 ;
			RECT 0.0714 41.5435 0.1097 41.6439 ;
		END

		ANTENNAGATEAREA 0.00027817 ;
		ANTENNADIFFAREA 0.00194719 ;
		ANTENNAPARTIALMETALAREA 0.00195671 ;
	END TWENB[40]

	PIN TWENB[41]
		USE SIGNAL ;
		DIRECTION INPUT ;
		SHAPE ABUTMENT ;
		PORT
			 LAYER M3 ;
			RECT 0.0714 42.3341 0.1097 42.4345 ;
		END

		ANTENNAGATEAREA 0.00027817 ;
		ANTENNADIFFAREA 0.00194719 ;
		ANTENNAPARTIALMETALAREA 0.00195671 ;
	END TWENB[41]

	PIN TWENB[42]
		USE SIGNAL ;
		DIRECTION INPUT ;
		SHAPE ABUTMENT ;
		PORT
			 LAYER M3 ;
			RECT 0.0714 43.1247 0.1097 43.2251 ;
		END

		ANTENNAGATEAREA 0.00027817 ;
		ANTENNADIFFAREA 0.00194719 ;
		ANTENNAPARTIALMETALAREA 0.00195671 ;
	END TWENB[42]

	PIN TWENB[43]
		USE SIGNAL ;
		DIRECTION INPUT ;
		SHAPE ABUTMENT ;
		PORT
			 LAYER M3 ;
			RECT 0.0714 43.9153 0.1097 44.0157 ;
		END

		ANTENNAGATEAREA 0.00027817 ;
		ANTENNADIFFAREA 0.00194719 ;
		ANTENNAPARTIALMETALAREA 0.00195671 ;
	END TWENB[43]

	PIN TWENB[44]
		USE SIGNAL ;
		DIRECTION INPUT ;
		SHAPE ABUTMENT ;
		PORT
			 LAYER M3 ;
			RECT 0.0714 44.7059 0.1097 44.8063 ;
		END

		ANTENNAGATEAREA 0.00027817 ;
		ANTENNADIFFAREA 0.00194719 ;
		ANTENNAPARTIALMETALAREA 0.00195671 ;
	END TWENB[44]

	PIN TWENB[45]
		USE SIGNAL ;
		DIRECTION INPUT ;
		SHAPE ABUTMENT ;
		PORT
			 LAYER M3 ;
			RECT 0.0714 45.4965 0.1097 45.5969 ;
		END

		ANTENNAGATEAREA 0.00027817 ;
		ANTENNADIFFAREA 0.00194719 ;
		ANTENNAPARTIALMETALAREA 0.00195671 ;
	END TWENB[45]

	PIN TWENB[46]
		USE SIGNAL ;
		DIRECTION INPUT ;
		SHAPE ABUTMENT ;
		PORT
			 LAYER M3 ;
			RECT 0.0714 46.2871 0.1097 46.3875 ;
		END

		ANTENNAGATEAREA 0.00027817 ;
		ANTENNADIFFAREA 0.00194719 ;
		ANTENNAPARTIALMETALAREA 0.00195671 ;
	END TWENB[46]

	PIN TWENB[47]
		USE SIGNAL ;
		DIRECTION INPUT ;
		SHAPE ABUTMENT ;
		PORT
			 LAYER M3 ;
			RECT 0.0714 47.0776 0.1097 47.178 ;
		END

		ANTENNAGATEAREA 0.00027817 ;
		ANTENNADIFFAREA 0.00194719 ;
		ANTENNAPARTIALMETALAREA 0.00195671 ;
	END TWENB[47]

	PIN TWENB[48]
		USE SIGNAL ;
		DIRECTION INPUT ;
		SHAPE ABUTMENT ;
		PORT
			 LAYER M3 ;
			RECT 0.0714 47.8682 0.1097 47.9686 ;
		END

		ANTENNAGATEAREA 0.00027817 ;
		ANTENNADIFFAREA 0.00194719 ;
		ANTENNAPARTIALMETALAREA 0.00195671 ;
	END TWENB[48]

	PIN TWENB[49]
		USE SIGNAL ;
		DIRECTION INPUT ;
		SHAPE ABUTMENT ;
		PORT
			 LAYER M3 ;
			RECT 0.0714 48.6588 0.1097 48.7592 ;
		END

		ANTENNAGATEAREA 0.00027817 ;
		ANTENNADIFFAREA 0.00194719 ;
		ANTENNAPARTIALMETALAREA 0.00195671 ;
	END TWENB[49]

	PIN TWENB[4]
		USE SIGNAL ;
		DIRECTION INPUT ;
		SHAPE ABUTMENT ;
		PORT
			 LAYER M3 ;
			RECT 0.0714 3.4008 0.1097 3.5012 ;
		END

		ANTENNAGATEAREA 0.00027817 ;
		ANTENNADIFFAREA 0.00194719 ;
		ANTENNAPARTIALMETALAREA 0.00195671 ;
	END TWENB[4]

	PIN TWENB[50]
		USE SIGNAL ;
		DIRECTION INPUT ;
		SHAPE ABUTMENT ;
		PORT
			 LAYER M3 ;
			RECT 0.0714 49.4494 0.1097 49.5498 ;
		END

		ANTENNAGATEAREA 0.00027817 ;
		ANTENNADIFFAREA 0.00194719 ;
		ANTENNAPARTIALMETALAREA 0.00195671 ;
	END TWENB[50]

	PIN TWENB[51]
		USE SIGNAL ;
		DIRECTION INPUT ;
		SHAPE ABUTMENT ;
		PORT
			 LAYER M3 ;
			RECT 0.0714 50.24 0.1097 50.3404 ;
		END

		ANTENNAGATEAREA 0.00027817 ;
		ANTENNADIFFAREA 0.00194719 ;
		ANTENNAPARTIALMETALAREA 0.00195671 ;
	END TWENB[51]

	PIN TWENB[52]
		USE SIGNAL ;
		DIRECTION INPUT ;
		SHAPE ABUTMENT ;
		PORT
			 LAYER M3 ;
			RECT 0.0714 51.0306 0.1097 51.131 ;
		END

		ANTENNAGATEAREA 0.00027817 ;
		ANTENNADIFFAREA 0.00194719 ;
		ANTENNAPARTIALMETALAREA 0.00195671 ;
	END TWENB[52]

	PIN TWENB[53]
		USE SIGNAL ;
		DIRECTION INPUT ;
		SHAPE ABUTMENT ;
		PORT
			 LAYER M3 ;
			RECT 0.0714 51.8212 0.1097 51.9216 ;
		END

		ANTENNAGATEAREA 0.00027817 ;
		ANTENNADIFFAREA 0.00194719 ;
		ANTENNAPARTIALMETALAREA 0.00195671 ;
	END TWENB[53]

	PIN TWENB[54]
		USE SIGNAL ;
		DIRECTION INPUT ;
		SHAPE ABUTMENT ;
		PORT
			 LAYER M3 ;
			RECT 0.0714 52.6118 0.1097 52.7122 ;
		END

		ANTENNAGATEAREA 0.00027817 ;
		ANTENNADIFFAREA 0.00194719 ;
		ANTENNAPARTIALMETALAREA 0.00195671 ;
	END TWENB[54]

	PIN TWENB[55]
		USE SIGNAL ;
		DIRECTION INPUT ;
		SHAPE ABUTMENT ;
		PORT
			 LAYER M3 ;
			RECT 0.0714 53.4024 0.1097 53.5027 ;
		END

		ANTENNAGATEAREA 0.00027817 ;
		ANTENNADIFFAREA 0.00194719 ;
		ANTENNAPARTIALMETALAREA 0.00195671 ;
	END TWENB[55]

	PIN TWENB[56]
		USE SIGNAL ;
		DIRECTION INPUT ;
		SHAPE ABUTMENT ;
		PORT
			 LAYER M3 ;
			RECT 0.0714 54.1929 0.1097 54.2933 ;
		END

		ANTENNAGATEAREA 0.00027817 ;
		ANTENNADIFFAREA 0.00194719 ;
		ANTENNAPARTIALMETALAREA 0.00195671 ;
	END TWENB[56]

	PIN TWENB[57]
		USE SIGNAL ;
		DIRECTION INPUT ;
		SHAPE ABUTMENT ;
		PORT
			 LAYER M3 ;
			RECT 0.0714 54.9835 0.1097 55.0839 ;
		END

		ANTENNAGATEAREA 0.00027817 ;
		ANTENNADIFFAREA 0.00194719 ;
		ANTENNAPARTIALMETALAREA 0.00195671 ;
	END TWENB[57]

	PIN TWENB[58]
		USE SIGNAL ;
		DIRECTION INPUT ;
		SHAPE ABUTMENT ;
		PORT
			 LAYER M3 ;
			RECT 0.0714 55.7741 0.1097 55.8745 ;
		END

		ANTENNAGATEAREA 0.00027817 ;
		ANTENNADIFFAREA 0.00194719 ;
		ANTENNAPARTIALMETALAREA 0.00195671 ;
	END TWENB[58]

	PIN TWENB[59]
		USE SIGNAL ;
		DIRECTION INPUT ;
		SHAPE ABUTMENT ;
		PORT
			 LAYER M3 ;
			RECT 0.0714 56.5647 0.1097 56.6651 ;
		END

		ANTENNAGATEAREA 0.00027817 ;
		ANTENNADIFFAREA 0.00194719 ;
		ANTENNAPARTIALMETALAREA 0.00195671 ;
	END TWENB[59]

	PIN TWENB[5]
		USE SIGNAL ;
		DIRECTION INPUT ;
		SHAPE ABUTMENT ;
		PORT
			 LAYER M3 ;
			RECT 0.0714 4.1914 0.1097 4.2918 ;
		END

		ANTENNAGATEAREA 0.00027817 ;
		ANTENNADIFFAREA 0.00194719 ;
		ANTENNAPARTIALMETALAREA 0.00195671 ;
	END TWENB[5]

	PIN TWENB[60]
		USE SIGNAL ;
		DIRECTION INPUT ;
		SHAPE ABUTMENT ;
		PORT
			 LAYER M3 ;
			RECT 0.0714 57.3553 0.1097 57.4557 ;
		END

		ANTENNAGATEAREA 0.00027817 ;
		ANTENNADIFFAREA 0.00194719 ;
		ANTENNAPARTIALMETALAREA 0.00195671 ;
	END TWENB[60]

	PIN TWENB[61]
		USE SIGNAL ;
		DIRECTION INPUT ;
		SHAPE ABUTMENT ;
		PORT
			 LAYER M3 ;
			RECT 0.0714 58.1459 0.1097 58.2463 ;
		END

		ANTENNAGATEAREA 0.00027817 ;
		ANTENNADIFFAREA 0.00194719 ;
		ANTENNAPARTIALMETALAREA 0.00195671 ;
	END TWENB[61]

	PIN TWENB[62]
		USE SIGNAL ;
		DIRECTION INPUT ;
		SHAPE ABUTMENT ;
		PORT
			 LAYER M3 ;
			RECT 0.0714 58.9365 0.1097 59.0369 ;
		END

		ANTENNAGATEAREA 0.00027817 ;
		ANTENNADIFFAREA 0.00194719 ;
		ANTENNAPARTIALMETALAREA 0.00195671 ;
	END TWENB[62]

	PIN TWENB[63]
		USE SIGNAL ;
		DIRECTION INPUT ;
		SHAPE ABUTMENT ;
		PORT
			 LAYER M3 ;
			RECT 0.0714 59.7271 0.1097 59.8275 ;
		END

		ANTENNAGATEAREA 0.00027817 ;
		ANTENNADIFFAREA 0.00194719 ;
		ANTENNAPARTIALMETALAREA 0.00195671 ;
	END TWENB[63]

	PIN TWENB[64]
		USE SIGNAL ;
		DIRECTION INPUT ;
		SHAPE ABUTMENT ;
		PORT
			 LAYER M3 ;
			RECT 0.0714 60.5176 0.1097 60.618 ;
		END

		ANTENNAGATEAREA 0.00027817 ;
		ANTENNADIFFAREA 0.00194719 ;
		ANTENNAPARTIALMETALAREA 0.00195671 ;
	END TWENB[64]

	PIN TWENB[65]
		USE SIGNAL ;
		DIRECTION INPUT ;
		SHAPE ABUTMENT ;
		PORT
			 LAYER M3 ;
			RECT 0.0714 61.3082 0.1097 61.4086 ;
		END

		ANTENNAGATEAREA 0.00027817 ;
		ANTENNADIFFAREA 0.00194719 ;
		ANTENNAPARTIALMETALAREA 0.00195671 ;
	END TWENB[65]

	PIN TWENB[6]
		USE SIGNAL ;
		DIRECTION INPUT ;
		SHAPE ABUTMENT ;
		PORT
			 LAYER M3 ;
			RECT 0.0714 4.982 0.1097 5.0824 ;
		END

		ANTENNAGATEAREA 0.00027817 ;
		ANTENNADIFFAREA 0.00194719 ;
		ANTENNAPARTIALMETALAREA 0.00195671 ;
	END TWENB[6]

	PIN TWENB[7]
		USE SIGNAL ;
		DIRECTION INPUT ;
		SHAPE ABUTMENT ;
		PORT
			 LAYER M3 ;
			RECT 0.0714 5.7725 0.1097 5.8729 ;
		END

		ANTENNAGATEAREA 0.00027817 ;
		ANTENNADIFFAREA 0.00194719 ;
		ANTENNAPARTIALMETALAREA 0.00195671 ;
	END TWENB[7]

	PIN TWENB[8]
		USE SIGNAL ;
		DIRECTION INPUT ;
		SHAPE ABUTMENT ;
		PORT
			 LAYER M3 ;
			RECT 0.0714 6.5631 0.1097 6.6635 ;
		END

		ANTENNAGATEAREA 0.00027817 ;
		ANTENNADIFFAREA 0.00194719 ;
		ANTENNAPARTIALMETALAREA 0.00195671 ;
	END TWENB[8]

	PIN TWENB[9]
		USE SIGNAL ;
		DIRECTION INPUT ;
		SHAPE ABUTMENT ;
		PORT
			 LAYER M3 ;
			RECT 0.0714 7.3537 0.1097 7.4541 ;
		END

		ANTENNAGATEAREA 0.00027817 ;
		ANTENNADIFFAREA 0.00194719 ;
		ANTENNAPARTIALMETALAREA 0.00195671 ;
	END TWENB[9]

	PIN VDDCE
		USE POWER ;
		DIRECTION INOUT ;
		PORT
			 LAYER M4 ;
			RECT 0.2105 60.6463 31.521 60.6933 ;
		END

		PORT
			 LAYER M4 ;
			RECT 0.2105 59.8557 31.521 59.9027 ;
		END

		PORT
			 LAYER M4 ;
			RECT 0.2105 41.6722 31.521 41.7192 ;
		END

		PORT
			 LAYER M4 ;
			RECT 0.2105 40.8816 31.521 40.9286 ;
		END

		PORT
			 LAYER M4 ;
			RECT 0.2105 40.091 31.521 40.138 ;
		END

		PORT
			 LAYER M4 ;
			RECT 0.2105 39.3004 31.521 39.3475 ;
		END

		PORT
			 LAYER M4 ;
			RECT 0.2105 38.5098 31.521 38.5569 ;
		END

		PORT
			 LAYER M4 ;
			RECT 0.2105 37.7192 31.521 37.7663 ;
		END

		PORT
			 LAYER M4 ;
			RECT 0.2105 36.9286 31.521 36.9757 ;
		END

		PORT
			 LAYER M4 ;
			RECT 0.2105 36.138 31.521 36.1851 ;
		END

		PORT
			 LAYER M4 ;
			RECT 0.2105 35.3475 31.521 35.3945 ;
		END

		PORT
			 LAYER M4 ;
			RECT 0.2105 34.5569 31.521 34.6039 ;
		END

		PORT
			 LAYER M4 ;
			RECT 0.2105 59.0651 31.521 59.1122 ;
		END

		PORT
			 LAYER M4 ;
			RECT 0.2105 27.0431 31.521 27.0902 ;
		END

		PORT
			 LAYER M4 ;
			RECT 0.2105 26.2525 31.521 26.2996 ;
		END

		PORT
			 LAYER M4 ;
			RECT 0.2105 58.2745 31.521 58.3216 ;
		END

		PORT
			 LAYER M4 ;
			RECT 0.2105 25.462 31.521 25.509 ;
		END

		PORT
			 LAYER M4 ;
			RECT 0.2105 24.6714 31.521 24.7184 ;
		END

		PORT
			 LAYER M4 ;
			RECT 0.2105 23.8808 31.521 23.9278 ;
		END

		PORT
			 LAYER M4 ;
			RECT 0.2105 23.0902 31.521 23.1373 ;
		END

		PORT
			 LAYER M4 ;
			RECT 0.2105 22.2996 31.521 22.3467 ;
		END

		PORT
			 LAYER M4 ;
			RECT 0.2105 21.509 31.521 21.5561 ;
		END

		PORT
			 LAYER M4 ;
			RECT 0.2105 20.7184 31.521 20.7655 ;
		END

		PORT
			 LAYER M4 ;
			RECT 0.2105 19.9278 31.521 19.9749 ;
		END

		PORT
			 LAYER M4 ;
			RECT 0.2105 19.1373 31.521 19.1843 ;
		END

		PORT
			 LAYER M4 ;
			RECT 0.2105 18.3467 31.521 18.3937 ;
		END

		PORT
			 LAYER M4 ;
			RECT 0.2105 57.4839 31.521 57.531 ;
		END

		PORT
			 LAYER M4 ;
			RECT 0.2105 17.5561 31.521 17.6031 ;
		END

		PORT
			 LAYER M4 ;
			RECT 0.2105 16.7655 31.521 16.8125 ;
		END

		PORT
			 LAYER M4 ;
			RECT 0.2105 15.9749 31.521 16.022 ;
		END

		PORT
			 LAYER M4 ;
			RECT 0.2105 15.1843 31.521 15.2314 ;
		END

		PORT
			 LAYER M4 ;
			RECT 0.2105 14.3937 31.521 14.4408 ;
		END

		PORT
			 LAYER M4 ;
			RECT 0.2105 13.6031 31.521 13.6502 ;
		END

		PORT
			 LAYER M4 ;
			RECT 0.2105 12.8125 31.521 12.8596 ;
		END

		PORT
			 LAYER M4 ;
			RECT 0.2105 12.022 31.521 12.069 ;
		END

		PORT
			 LAYER M4 ;
			RECT 0.2105 11.2314 31.521 11.2784 ;
		END

		PORT
			 LAYER M4 ;
			RECT 0.2105 10.4408 31.521 10.4878 ;
		END

		PORT
			 LAYER M4 ;
			RECT 0.2105 56.6933 31.521 56.7404 ;
		END

		PORT
			 LAYER M4 ;
			RECT 0.2105 9.6502 31.521 9.6973 ;
		END

		PORT
			 LAYER M4 ;
			RECT 0.2105 8.8596 31.521 8.9067 ;
		END

		PORT
			 LAYER M4 ;
			RECT 0.2105 8.069 31.521 8.1161 ;
		END

		PORT
			 LAYER M4 ;
			RECT 0.2105 7.2784 31.521 7.3255 ;
		END

		PORT
			 LAYER M4 ;
			RECT 0.2105 6.4878 31.521 6.5349 ;
		END

		PORT
			 LAYER M4 ;
			RECT 0.2105 5.6973 31.521 5.7443 ;
		END

		PORT
			 LAYER M4 ;
			RECT 0.2105 4.9067 31.521 4.9537 ;
		END

		PORT
			 LAYER M4 ;
			RECT 0.2105 4.1161 31.521 4.1631 ;
		END

		PORT
			 LAYER M4 ;
			RECT 0.2105 3.3255 31.521 3.3725 ;
		END

		PORT
			 LAYER M4 ;
			RECT 0.2105 2.5349 31.521 2.582 ;
		END

		PORT
			 LAYER M4 ;
			RECT 0.2105 55.9027 31.521 55.9498 ;
		END

		PORT
			 LAYER M4 ;
			RECT 0.2105 1.7443 31.521 1.7914 ;
		END

		PORT
			 LAYER M4 ;
			RECT 0.2105 0.9537 31.521 1.0008 ;
		END

		PORT
			 LAYER M4 ;
			RECT 0.2105 55.1122 31.521 55.1592 ;
		END

		PORT
			 LAYER M4 ;
			RECT 0.2105 54.3216 31.521 54.3686 ;
		END

		PORT
			 LAYER M4 ;
			RECT 0.2105 53.531 31.521 53.578 ;
		END

		PORT
			 LAYER M4 ;
			RECT 0.2105 52.7404 31.521 52.7875 ;
		END

		PORT
			 LAYER M4 ;
			RECT 0.2105 51.9498 31.521 51.9969 ;
		END

		PORT
			 LAYER M4 ;
			RECT 0.2105 51.1592 31.521 51.2063 ;
		END

		PORT
			 LAYER M4 ;
			RECT 0.2105 50.3686 31.521 50.4157 ;
		END

		PORT
			 LAYER M4 ;
			RECT 0.2105 49.578 31.521 49.6251 ;
		END

		PORT
			 LAYER M4 ;
			RECT 0.2105 48.7875 31.521 48.8345 ;
		END

		PORT
			 LAYER M4 ;
			RECT 0.2105 47.9969 31.521 48.0439 ;
		END

		PORT
			 LAYER M4 ;
			RECT 0.2105 47.2063 31.521 47.2533 ;
		END

		PORT
			 LAYER M4 ;
			RECT 0.2105 46.4157 31.521 46.4627 ;
		END

		PORT
			 LAYER M4 ;
			RECT 0.2105 45.6251 31.521 45.6722 ;
		END

		PORT
			 LAYER M4 ;
			RECT 0.2105 44.8345 31.521 44.8816 ;
		END

		PORT
			 LAYER M4 ;
			RECT 0.2105 44.0439 31.521 44.091 ;
		END

		PORT
			 LAYER M4 ;
			RECT 0.2105 43.2533 31.521 43.3004 ;
		END

		PORT
			 LAYER M4 ;
			RECT 0.2105 42.4627 31.521 42.5098 ;
		END

		PORT
			 LAYER M4 ;
			RECT 0.2105 27.6345 31.521 27.6816 ;
		END

		PORT
			 LAYER M4 ;
			RECT 0.2105 27.9263 31.521 27.9733 ;
		END

		PORT
			 LAYER M4 ;
			RECT 0.2105 33.8808 31.521 33.9278 ;
		END

		PORT
			 LAYER M4 ;
			RECT 0.2105 34.1725 31.521 34.2196 ;
		END

		PORT
			 LAYER M4 ;
			RECT 0.2105 27.1843 31.521 27.2157 ;
		END

		PORT
			 LAYER M4 ;
			RECT 0.2105 34.4314 31.521 34.4627 ;
		END

		PORT
			 LAYER M4 ;
			RECT 0.2105 61.4369 31.521 61.4682 ;
		END

		PORT
			 LAYER M4 ;
			RECT 0.2105 0.1788 31.521 0.2102 ;
		END

	END VDDCE

	PIN VDDPE
		USE POWER ;
		DIRECTION INOUT ;
		PORT
			 LAYER M4 ;
			RECT 0.2105 61.28 31.521 61.3271 ;
		END

		PORT
			 LAYER M4 ;
			RECT 0.2105 42.3059 31.521 42.3529 ;
		END

		PORT
			 LAYER M4 ;
			RECT 0.2105 41.5153 31.521 41.5624 ;
		END

		PORT
			 LAYER M4 ;
			RECT 0.2105 40.7247 31.521 40.7718 ;
		END

		PORT
			 LAYER M4 ;
			RECT 0.2105 39.9341 31.521 39.9812 ;
		END

		PORT
			 LAYER M4 ;
			RECT 0.2105 39.1435 31.521 39.1906 ;
		END

		PORT
			 LAYER M4 ;
			RECT 0.2105 59.6988 31.521 59.7459 ;
		END

		PORT
			 LAYER M4 ;
			RECT 0.2105 38.3529 31.521 38.4 ;
		END

		PORT
			 LAYER M4 ;
			RECT 0.2105 37.5624 31.521 37.6094 ;
		END

		PORT
			 LAYER M4 ;
			RECT 0.2105 36.7718 31.521 36.8188 ;
		END

		PORT
			 LAYER M4 ;
			RECT 0.2105 35.9812 31.521 36.0282 ;
		END

		PORT
			 LAYER M4 ;
			RECT 0.2105 35.1906 31.521 35.2376 ;
		END

		PORT
			 LAYER M4 ;
			RECT 0.2105 58.9082 31.521 58.9553 ;
		END

		PORT
			 LAYER M4 ;
			RECT 0.2105 26.4094 31.521 26.4565 ;
		END

		PORT
			 LAYER M4 ;
			RECT 0.2105 25.6188 31.521 25.6659 ;
		END

		PORT
			 LAYER M4 ;
			RECT 0.2105 24.8282 31.521 24.8753 ;
		END

		PORT
			 LAYER M4 ;
			RECT 0.2105 24.0376 31.521 24.0847 ;
		END

		PORT
			 LAYER M4 ;
			RECT 0.2105 23.2471 31.521 23.2941 ;
		END

		PORT
			 LAYER M4 ;
			RECT 0.2105 22.4565 31.521 22.5035 ;
		END

		PORT
			 LAYER M4 ;
			RECT 0.2105 21.6659 31.521 21.7129 ;
		END

		PORT
			 LAYER M4 ;
			RECT 0.2105 58.1176 31.521 58.1647 ;
		END

		PORT
			 LAYER M4 ;
			RECT 0.2105 20.8753 31.521 20.9224 ;
		END

		PORT
			 LAYER M4 ;
			RECT 0.2105 20.0847 31.521 20.1318 ;
		END

		PORT
			 LAYER M4 ;
			RECT 0.2105 19.2941 31.521 19.3412 ;
		END

		PORT
			 LAYER M4 ;
			RECT 0.2105 18.5035 31.521 18.5506 ;
		END

		PORT
			 LAYER M4 ;
			RECT 0.2105 17.7129 31.521 17.76 ;
		END

		PORT
			 LAYER M4 ;
			RECT 0.2105 16.9224 31.521 16.9694 ;
		END

		PORT
			 LAYER M4 ;
			RECT 0.2105 16.1318 31.521 16.1788 ;
		END

		PORT
			 LAYER M4 ;
			RECT 0.2105 15.3412 31.521 15.3882 ;
		END

		PORT
			 LAYER M4 ;
			RECT 0.2105 14.5506 31.521 14.5976 ;
		END

		PORT
			 LAYER M4 ;
			RECT 0.2105 13.76 31.521 13.8071 ;
		END

		PORT
			 LAYER M4 ;
			RECT 0.2105 57.3271 31.521 57.3741 ;
		END

		PORT
			 LAYER M4 ;
			RECT 0.2105 12.9694 31.521 13.0165 ;
		END

		PORT
			 LAYER M4 ;
			RECT 0.2105 12.1788 31.521 12.2259 ;
		END

		PORT
			 LAYER M4 ;
			RECT 0.2105 11.3882 31.521 11.4353 ;
		END

		PORT
			 LAYER M4 ;
			RECT 0.2105 10.5976 31.521 10.6447 ;
		END

		PORT
			 LAYER M4 ;
			RECT 0.2105 9.8071 31.521 9.8541 ;
		END

		PORT
			 LAYER M4 ;
			RECT 0.2105 9.0165 31.521 9.0635 ;
		END

		PORT
			 LAYER M4 ;
			RECT 0.2105 8.2259 31.521 8.2729 ;
		END

		PORT
			 LAYER M4 ;
			RECT 0.2105 7.4353 31.521 7.4824 ;
		END

		PORT
			 LAYER M4 ;
			RECT 0.2105 6.6447 31.521 6.6918 ;
		END

		PORT
			 LAYER M4 ;
			RECT 0.2105 5.8541 31.521 5.9012 ;
		END

		PORT
			 LAYER M4 ;
			RECT 0.2105 56.5365 31.521 56.5835 ;
		END

		PORT
			 LAYER M4 ;
			RECT 0.2105 5.0635 31.521 5.1106 ;
		END

		PORT
			 LAYER M4 ;
			RECT 0.2105 4.2729 31.521 4.32 ;
		END

		PORT
			 LAYER M4 ;
			RECT 0.2105 3.4824 31.521 3.5294 ;
		END

		PORT
			 LAYER M4 ;
			RECT 0.2105 2.6918 31.521 2.7388 ;
		END

		PORT
			 LAYER M4 ;
			RECT 0.2105 1.9012 31.521 1.9482 ;
		END

		PORT
			 LAYER M4 ;
			RECT 0.2105 1.1106 31.521 1.1576 ;
		END

		PORT
			 LAYER M4 ;
			RECT 0.2105 0.32 31.521 0.3671 ;
		END

		PORT
			 LAYER M4 ;
			RECT 0.2105 55.7459 31.521 55.7929 ;
		END

		PORT
			 LAYER M4 ;
			RECT 0.2105 54.9553 31.521 55.0024 ;
		END

		PORT
			 LAYER M4 ;
			RECT 0.2105 54.1647 31.521 54.2118 ;
		END

		PORT
			 LAYER M4 ;
			RECT 0.2105 53.3741 31.521 53.4212 ;
		END

		PORT
			 LAYER M4 ;
			RECT 0.2105 52.5835 31.521 52.6306 ;
		END

		PORT
			 LAYER M4 ;
			RECT 0.2105 51.7929 31.521 51.84 ;
		END

		PORT
			 LAYER M4 ;
			RECT 0.2105 51.0024 31.521 51.0494 ;
		END

		PORT
			 LAYER M4 ;
			RECT 0.2105 50.2118 31.521 50.2588 ;
		END

		PORT
			 LAYER M4 ;
			RECT 0.2105 49.4212 31.521 49.4682 ;
		END

		PORT
			 LAYER M4 ;
			RECT 0.2105 48.6306 31.521 48.6776 ;
		END

		PORT
			 LAYER M4 ;
			RECT 0.2105 47.84 31.521 47.8871 ;
		END

		PORT
			 LAYER M4 ;
			RECT 0.2105 47.0494 31.521 47.0965 ;
		END

		PORT
			 LAYER M4 ;
			RECT 0.2105 60.4894 31.521 60.5365 ;
		END

		PORT
			 LAYER M4 ;
			RECT 0.2105 46.2588 31.521 46.3059 ;
		END

		PORT
			 LAYER M4 ;
			RECT 0.2105 45.4682 31.521 45.5153 ;
		END

		PORT
			 LAYER M4 ;
			RECT 0.2105 44.6776 31.521 44.7247 ;
		END

		PORT
			 LAYER M4 ;
			RECT 0.2105 43.8871 31.521 43.9341 ;
		END

		PORT
			 LAYER M4 ;
			RECT 0.2105 43.0965 31.521 43.1435 ;
		END

		PORT
			 LAYER M4 ;
			RECT 0.2105 60.7247 31.521 60.7718 ;
		END

		PORT
			 LAYER M4 ;
			RECT 0.2105 41.7506 31.521 41.7976 ;
		END

		PORT
			 LAYER M4 ;
			RECT 0.2105 40.96 31.521 41.0071 ;
		END

		PORT
			 LAYER M4 ;
			RECT 0.2105 40.1694 31.521 40.2165 ;
		END

		PORT
			 LAYER M4 ;
			RECT 0.2105 39.3788 31.521 39.4259 ;
		END

		PORT
			 LAYER M4 ;
			RECT 0.2105 38.5882 31.521 38.6353 ;
		END

		PORT
			 LAYER M4 ;
			RECT 0.2105 37.7976 31.521 37.8447 ;
		END

		PORT
			 LAYER M4 ;
			RECT 0.2105 37.0071 31.521 37.0541 ;
		END

		PORT
			 LAYER M4 ;
			RECT 0.2105 36.2165 31.521 36.2635 ;
		END

		PORT
			 LAYER M4 ;
			RECT 0.2105 59.1435 31.521 59.1906 ;
		END

		PORT
			 LAYER M4 ;
			RECT 0.2105 35.4259 31.521 35.4729 ;
		END

		PORT
			 LAYER M4 ;
			RECT 0.2105 34.6353 31.521 34.6824 ;
		END

		PORT
			 LAYER M4 ;
			RECT 0.2105 58.3529 31.521 58.4 ;
		END

		PORT
			 LAYER M4 ;
			RECT 0.2105 26.9647 31.521 27.0118 ;
		END

		PORT
			 LAYER M4 ;
			RECT 0.2105 26.1741 31.521 26.2212 ;
		END

		PORT
			 LAYER M4 ;
			RECT 0.2105 25.3835 31.521 25.4306 ;
		END

		PORT
			 LAYER M4 ;
			RECT 0.2105 24.5929 31.521 24.64 ;
		END

		PORT
			 LAYER M4 ;
			RECT 0.2105 23.8024 31.521 23.8494 ;
		END

		PORT
			 LAYER M4 ;
			RECT 0.2105 23.0118 31.521 23.0588 ;
		END

		PORT
			 LAYER M4 ;
			RECT 0.2105 22.2212 31.521 22.2682 ;
		END

		PORT
			 LAYER M4 ;
			RECT 0.2105 21.4306 31.521 21.4776 ;
		END

		PORT
			 LAYER M4 ;
			RECT 0.2105 20.64 31.521 20.6871 ;
		END

		PORT
			 LAYER M4 ;
			RECT 0.2105 57.5624 31.521 57.6094 ;
		END

		PORT
			 LAYER M4 ;
			RECT 0.2105 19.8494 31.521 19.8965 ;
		END

		PORT
			 LAYER M4 ;
			RECT 0.2105 19.0588 31.521 19.1059 ;
		END

		PORT
			 LAYER M4 ;
			RECT 0.2105 18.2682 31.521 18.3153 ;
		END

		PORT
			 LAYER M4 ;
			RECT 0.2105 17.4776 31.521 17.5247 ;
		END

		PORT
			 LAYER M4 ;
			RECT 0.2105 16.6871 31.521 16.7341 ;
		END

		PORT
			 LAYER M4 ;
			RECT 0.2105 15.8965 31.521 15.9435 ;
		END

		PORT
			 LAYER M4 ;
			RECT 0.2105 15.1059 31.521 15.1529 ;
		END

		PORT
			 LAYER M4 ;
			RECT 0.2105 14.3153 31.521 14.3624 ;
		END

		PORT
			 LAYER M4 ;
			RECT 0.2105 13.5247 31.521 13.5718 ;
		END

		PORT
			 LAYER M4 ;
			RECT 0.2105 12.7341 31.521 12.7812 ;
		END

		PORT
			 LAYER M4 ;
			RECT 0.2105 56.7718 31.521 56.8188 ;
		END

		PORT
			 LAYER M4 ;
			RECT 0.2105 11.9435 31.521 11.9906 ;
		END

		PORT
			 LAYER M4 ;
			RECT 0.2105 11.1529 31.521 11.2 ;
		END

		PORT
			 LAYER M4 ;
			RECT 0.2105 10.3624 31.521 10.4094 ;
		END

		PORT
			 LAYER M4 ;
			RECT 0.2105 9.5718 31.521 9.6188 ;
		END

		PORT
			 LAYER M4 ;
			RECT 0.2105 8.7812 31.521 8.8282 ;
		END

		PORT
			 LAYER M4 ;
			RECT 0.2105 7.9906 31.521 8.0376 ;
		END

		PORT
			 LAYER M4 ;
			RECT 0.2105 7.2 31.521 7.2471 ;
		END

		PORT
			 LAYER M4 ;
			RECT 0.2105 6.4094 31.521 6.4565 ;
		END

		PORT
			 LAYER M4 ;
			RECT 0.2105 5.6188 31.521 5.6659 ;
		END

		PORT
			 LAYER M4 ;
			RECT 0.2105 4.8282 31.521 4.8753 ;
		END

		PORT
			 LAYER M4 ;
			RECT 0.2105 55.9812 31.521 56.0282 ;
		END

		PORT
			 LAYER M4 ;
			RECT 0.2105 4.0376 31.521 4.0847 ;
		END

		PORT
			 LAYER M4 ;
			RECT 0.2105 3.2471 31.521 3.2941 ;
		END

		PORT
			 LAYER M4 ;
			RECT 0.2105 2.4565 31.521 2.5035 ;
		END

		PORT
			 LAYER M4 ;
			RECT 0.2105 1.6659 31.521 1.7129 ;
		END

		PORT
			 LAYER M4 ;
			RECT 0.2105 0.8753 31.521 0.9224 ;
		END

		PORT
			 LAYER M4 ;
			RECT 0.2105 55.1906 31.521 55.2376 ;
		END

		PORT
			 LAYER M4 ;
			RECT 0.2105 54.4 31.521 54.4471 ;
		END

		PORT
			 LAYER M4 ;
			RECT 0.2105 53.6094 31.521 53.6565 ;
		END

		PORT
			 LAYER M4 ;
			RECT 0.2105 52.8188 31.521 52.8659 ;
		END

		PORT
			 LAYER M4 ;
			RECT 0.2105 52.0282 31.521 52.0753 ;
		END

		PORT
			 LAYER M4 ;
			RECT 0.2105 51.2376 31.521 51.2847 ;
		END

		PORT
			 LAYER M4 ;
			RECT 0.2105 50.4471 31.521 50.4941 ;
		END

		PORT
			 LAYER M4 ;
			RECT 0.2105 49.6565 31.521 49.7035 ;
		END

		PORT
			 LAYER M4 ;
			RECT 0.2105 48.8659 31.521 48.9129 ;
		END

		PORT
			 LAYER M4 ;
			RECT 0.2105 48.0753 31.521 48.1224 ;
		END

		PORT
			 LAYER M4 ;
			RECT 0.2105 47.2847 31.521 47.3318 ;
		END

		PORT
			 LAYER M4 ;
			RECT 0.2105 46.4941 31.521 46.5412 ;
		END

		PORT
			 LAYER M4 ;
			RECT 0.2105 45.7035 31.521 45.7506 ;
		END

		PORT
			 LAYER M4 ;
			RECT 0.2105 44.9129 31.521 44.96 ;
		END

		PORT
			 LAYER M4 ;
			RECT 0.2105 44.1224 31.521 44.1694 ;
		END

		PORT
			 LAYER M4 ;
			RECT 0.2105 59.9341 31.521 59.9812 ;
		END

		PORT
			 LAYER M4 ;
			RECT 0.2105 43.3318 31.521 43.3788 ;
		END

		PORT
			 LAYER M4 ;
			RECT 0.2105 42.5412 31.521 42.5882 ;
		END

		PORT
			 LAYER M4 ;
			RECT 0.2105 27.3882 31.521 27.4353 ;
		END

		PORT
			 LAYER M4 ;
			RECT 0.2105 28.0047 31.521 28.0518 ;
		END

		PORT
			 LAYER M4 ;
			RECT 0.2105 28.5318 31.521 28.5788 ;
		END

		PORT
			 LAYER M4 ;
			RECT 0.2105 29.0588 31.521 29.1059 ;
		END

		PORT
			 LAYER M4 ;
			RECT 0.2105 29.5859 31.521 29.6329 ;
		END

		PORT
			 LAYER M4 ;
			RECT 0.2105 30.1129 31.521 30.16 ;
		END

		PORT
			 LAYER M4 ;
			RECT 0.2105 31.1671 31.521 31.2141 ;
		END

		PORT
			 LAYER M4 ;
			RECT 0.2105 32.2212 31.521 32.2682 ;
		END

		PORT
			 LAYER M4 ;
			RECT 0.2105 32.7482 31.521 32.7953 ;
		END

		PORT
			 LAYER M4 ;
			RECT 0.2105 33.2753 31.521 33.3224 ;
		END

		PORT
			 LAYER M4 ;
			RECT 0.2105 33.8024 31.521 33.8494 ;
		END

		PORT
			 LAYER M4 ;
			RECT 0.2105 33.9592 31.521 34.0063 ;
		END

		PORT
			 LAYER M4 ;
			RECT 0.2105 27.2471 31.521 27.2784 ;
		END

		PORT
			 LAYER M4 ;
			RECT 0.2105 34.3686 31.521 34.4 ;
		END

		PORT
			 LAYER M4 ;
			RECT 0.2105 61.5624 31.521 61.5937 ;
		END

		PORT
			 LAYER M4 ;
			RECT 0.2105 0.0533 31.521 0.0847 ;
		END

	END VDDPE

	PIN VSSE
		USE GROUND ;
		DIRECTION INOUT ;
		PORT
			 LAYER M4 ;
			RECT 0.2105 27.1216 31.521 27.1529 ;
		END

		PORT
			 LAYER M4 ;
			RECT 0.2105 34.4941 31.521 34.5255 ;
		END

		PORT
			 LAYER M4 ;
			RECT 0.2105 61.4996 31.521 61.531 ;
		END

		PORT
			 LAYER M4 ;
			RECT 0.2105 0.1161 31.521 0.1475 ;
		END

		PORT
			 LAYER M4 ;
			RECT 0.2105 27.3098 31.521 27.3569 ;
		END

		PORT
			 LAYER M4 ;
			RECT 0.2105 27.7129 31.521 27.76 ;
		END

		PORT
			 LAYER M4 ;
			RECT 0.2105 28.4533 31.521 28.5004 ;
		END

		PORT
			 LAYER M4 ;
			RECT 0.2105 28.9804 31.521 29.0275 ;
		END

		PORT
			 LAYER M4 ;
			RECT 0.2105 29.5075 31.521 29.5545 ;
		END

		PORT
			 LAYER M4 ;
			RECT 0.2105 30.0345 31.521 30.0816 ;
		END

		PORT
			 LAYER M4 ;
			RECT 0.2105 31.0886 31.521 31.1357 ;
		END

		PORT
			 LAYER M4 ;
			RECT 0.2105 32.1427 31.521 32.1898 ;
		END

		PORT
			 LAYER M4 ;
			RECT 0.2105 32.6698 31.521 32.7169 ;
		END

		PORT
			 LAYER M4 ;
			RECT 0.2105 33.1969 31.521 33.2439 ;
		END

		PORT
			 LAYER M4 ;
			RECT 0.2105 33.7239 31.521 33.771 ;
		END

		PORT
			 LAYER M4 ;
			RECT 0.2105 34.0941 31.521 34.1412 ;
		END

		PORT
			 LAYER M4 ;
			RECT 0.2105 61.3584 31.521 61.4055 ;
		END

		PORT
			 LAYER M4 ;
			RECT 0.2105 41.5937 31.521 41.6408 ;
		END

		PORT
			 LAYER M4 ;
			RECT 0.2105 40.8031 31.521 40.8502 ;
		END

		PORT
			 LAYER M4 ;
			RECT 0.2105 59.7773 31.521 59.8243 ;
		END

		PORT
			 LAYER M4 ;
			RECT 0.2105 40.0125 31.521 40.0596 ;
		END

		PORT
			 LAYER M4 ;
			RECT 0.2105 39.222 31.521 39.269 ;
		END

		PORT
			 LAYER M4 ;
			RECT 0.2105 38.4314 31.521 38.4784 ;
		END

		PORT
			 LAYER M4 ;
			RECT 0.2105 37.6408 31.521 37.6878 ;
		END

		PORT
			 LAYER M4 ;
			RECT 0.2105 36.8502 31.521 36.8973 ;
		END

		PORT
			 LAYER M4 ;
			RECT 0.2105 36.0596 31.521 36.1067 ;
		END

		PORT
			 LAYER M4 ;
			RECT 0.2105 35.269 31.521 35.3161 ;
		END

		PORT
			 LAYER M4 ;
			RECT 0.2105 58.9867 31.521 59.0337 ;
		END

		PORT
			 LAYER M4 ;
			RECT 0.2105 26.331 31.521 26.378 ;
		END

		PORT
			 LAYER M4 ;
			RECT 0.2105 25.5404 31.521 25.5875 ;
		END

		PORT
			 LAYER M4 ;
			RECT 0.2105 24.7498 31.521 24.7969 ;
		END

		PORT
			 LAYER M4 ;
			RECT 0.2105 23.9592 31.521 24.0063 ;
		END

		PORT
			 LAYER M4 ;
			RECT 0.2105 58.1961 31.521 58.2431 ;
		END

		PORT
			 LAYER M4 ;
			RECT 0.2105 23.1686 31.521 23.2157 ;
		END

		PORT
			 LAYER M4 ;
			RECT 0.2105 22.378 31.521 22.4251 ;
		END

		PORT
			 LAYER M4 ;
			RECT 0.2105 21.5875 31.521 21.6345 ;
		END

		PORT
			 LAYER M4 ;
			RECT 0.2105 20.7969 31.521 20.8439 ;
		END

		PORT
			 LAYER M4 ;
			RECT 0.2105 20.0063 31.521 20.0533 ;
		END

		PORT
			 LAYER M4 ;
			RECT 0.2105 19.2157 31.521 19.2627 ;
		END

		PORT
			 LAYER M4 ;
			RECT 0.2105 18.4251 31.521 18.4722 ;
		END

		PORT
			 LAYER M4 ;
			RECT 0.2105 17.6345 31.521 17.6816 ;
		END

		PORT
			 LAYER M4 ;
			RECT 0.2105 16.8439 31.521 16.891 ;
		END

		PORT
			 LAYER M4 ;
			RECT 0.2105 16.0533 31.521 16.1004 ;
		END

		PORT
			 LAYER M4 ;
			RECT 0.2105 57.4055 31.521 57.4525 ;
		END

		PORT
			 LAYER M4 ;
			RECT 0.2105 15.2627 31.521 15.3098 ;
		END

		PORT
			 LAYER M4 ;
			RECT 0.2105 14.4722 31.521 14.5192 ;
		END

		PORT
			 LAYER M4 ;
			RECT 0.2105 13.6816 31.521 13.7286 ;
		END

		PORT
			 LAYER M4 ;
			RECT 0.2105 12.891 31.521 12.938 ;
		END

		PORT
			 LAYER M4 ;
			RECT 0.2105 12.1004 31.521 12.1475 ;
		END

		PORT
			 LAYER M4 ;
			RECT 0.2105 11.3098 31.521 11.3569 ;
		END

		PORT
			 LAYER M4 ;
			RECT 0.2105 10.5192 31.521 10.5663 ;
		END

		PORT
			 LAYER M4 ;
			RECT 0.2105 9.7286 31.521 9.7757 ;
		END

		PORT
			 LAYER M4 ;
			RECT 0.2105 8.938 31.521 8.9851 ;
		END

		PORT
			 LAYER M4 ;
			RECT 0.2105 8.1475 31.521 8.1945 ;
		END

		PORT
			 LAYER M4 ;
			RECT 0.2105 56.6149 31.521 56.662 ;
		END

		PORT
			 LAYER M4 ;
			RECT 0.2105 7.3569 31.521 7.4039 ;
		END

		PORT
			 LAYER M4 ;
			RECT 0.2105 6.5663 31.521 6.6133 ;
		END

		PORT
			 LAYER M4 ;
			RECT 0.2105 5.7757 31.521 5.8227 ;
		END

		PORT
			 LAYER M4 ;
			RECT 0.2105 4.9851 31.521 5.0322 ;
		END

		PORT
			 LAYER M4 ;
			RECT 0.2105 4.1945 31.521 4.2416 ;
		END

		PORT
			 LAYER M4 ;
			RECT 0.2105 3.4039 31.521 3.451 ;
		END

		PORT
			 LAYER M4 ;
			RECT 0.2105 2.6133 31.521 2.6604 ;
		END

		PORT
			 LAYER M4 ;
			RECT 0.2105 1.8227 31.521 1.8698 ;
		END

		PORT
			 LAYER M4 ;
			RECT 0.2105 1.0322 31.521 1.0792 ;
		END

		PORT
			 LAYER M4 ;
			RECT 0.2105 0.2416 31.521 0.2886 ;
		END

		PORT
			 LAYER M4 ;
			RECT 0.2105 55.8243 31.521 55.8714 ;
		END

		PORT
			 LAYER M4 ;
			RECT 0.2105 55.0337 31.521 55.0808 ;
		END

		PORT
			 LAYER M4 ;
			RECT 0.2105 54.2431 31.521 54.2902 ;
		END

		PORT
			 LAYER M4 ;
			RECT 0.2105 53.4525 31.521 53.4996 ;
		END

		PORT
			 LAYER M4 ;
			RECT 0.2105 52.662 31.521 52.709 ;
		END

		PORT
			 LAYER M4 ;
			RECT 0.2105 51.8714 31.521 51.9184 ;
		END

		PORT
			 LAYER M4 ;
			RECT 0.2105 51.0808 31.521 51.1278 ;
		END

		PORT
			 LAYER M4 ;
			RECT 0.2105 50.2902 31.521 50.3373 ;
		END

		PORT
			 LAYER M4 ;
			RECT 0.2105 49.4996 31.521 49.5467 ;
		END

		PORT
			 LAYER M4 ;
			RECT 0.2105 48.709 31.521 48.7561 ;
		END

		PORT
			 LAYER M4 ;
			RECT 0.2105 60.5678 31.521 60.6149 ;
		END

		PORT
			 LAYER M4 ;
			RECT 0.2105 47.9184 31.521 47.9655 ;
		END

		PORT
			 LAYER M4 ;
			RECT 0.2105 47.1278 31.521 47.1749 ;
		END

		PORT
			 LAYER M4 ;
			RECT 0.2105 46.3373 31.521 46.3843 ;
		END

		PORT
			 LAYER M4 ;
			RECT 0.2105 45.5467 31.521 45.5937 ;
		END

		PORT
			 LAYER M4 ;
			RECT 0.2105 44.7561 31.521 44.8031 ;
		END

		PORT
			 LAYER M4 ;
			RECT 0.2105 43.9655 31.521 44.0125 ;
		END

		PORT
			 LAYER M4 ;
			RECT 0.2105 43.1749 31.521 43.222 ;
		END

		PORT
			 LAYER M4 ;
			RECT 0.2105 42.3843 31.521 42.4314 ;
		END

	END VSSE

	PIN WENA[0]
		USE SIGNAL ;
		DIRECTION INPUT ;
		SHAPE ABUTMENT ;
		PORT
			 LAYER M2 ;
			RECT 0.0098 0.389 0.0481 0.4267 ;
			 LAYER M3 ;
			RECT 0.0098 0.389 0.0481 0.4894 ;
			 LAYER V2 ;
			RECT 0.0215 0.402 0.0364 0.4145 ;
		END

		ANTENNAGATEAREA 0.00027817 ;
		ANTENNADIFFAREA 0.00194719 ;
		ANTENNAPARTIALMETALAREA 0.00195671 ;
	END WENA[0]

	PIN WENA[10]
		USE SIGNAL ;
		DIRECTION INPUT ;
		SHAPE ABUTMENT ;
		PORT
			 LAYER M2 ;
			RECT 0.0098 8.2949 0.0481 8.3325 ;
			 LAYER M3 ;
			RECT 0.0098 8.2949 0.0481 8.3953 ;
			 LAYER V2 ;
			RECT 0.0215 8.3078 0.0364 8.3204 ;
		END

		ANTENNAGATEAREA 0.00027817 ;
		ANTENNADIFFAREA 0.00194719 ;
		ANTENNAPARTIALMETALAREA 0.00195671 ;
	END WENA[10]

	PIN WENA[11]
		USE SIGNAL ;
		DIRECTION INPUT ;
		SHAPE ABUTMENT ;
		PORT
			 LAYER M2 ;
			RECT 0.0098 9.0855 0.0481 9.1231 ;
			 LAYER M3 ;
			RECT 0.0098 9.0855 0.0481 9.1859 ;
			 LAYER V2 ;
			RECT 0.0215 9.0984 0.0364 9.111 ;
		END

		ANTENNAGATEAREA 0.00027817 ;
		ANTENNADIFFAREA 0.00194719 ;
		ANTENNAPARTIALMETALAREA 0.00195671 ;
	END WENA[11]

	PIN WENA[12]
		USE SIGNAL ;
		DIRECTION INPUT ;
		SHAPE ABUTMENT ;
		PORT
			 LAYER M2 ;
			RECT 0.0098 9.8761 0.0481 9.9137 ;
			 LAYER M3 ;
			RECT 0.0098 9.8761 0.0481 9.9765 ;
			 LAYER V2 ;
			RECT 0.0215 9.889 0.0364 9.9016 ;
		END

		ANTENNAGATEAREA 0.00027817 ;
		ANTENNADIFFAREA 0.00194719 ;
		ANTENNAPARTIALMETALAREA 0.00195671 ;
	END WENA[12]

	PIN WENA[13]
		USE SIGNAL ;
		DIRECTION INPUT ;
		SHAPE ABUTMENT ;
		PORT
			 LAYER M2 ;
			RECT 0.0098 10.6667 0.0481 10.7043 ;
			 LAYER M3 ;
			RECT 0.0098 10.6667 0.0481 10.7671 ;
			 LAYER V2 ;
			RECT 0.0215 10.6796 0.0364 10.6922 ;
		END

		ANTENNAGATEAREA 0.00027817 ;
		ANTENNADIFFAREA 0.00194719 ;
		ANTENNAPARTIALMETALAREA 0.00195671 ;
	END WENA[13]

	PIN WENA[14]
		USE SIGNAL ;
		DIRECTION INPUT ;
		SHAPE ABUTMENT ;
		PORT
			 LAYER M2 ;
			RECT 0.0098 11.4573 0.0481 11.4949 ;
			 LAYER M3 ;
			RECT 0.0098 11.4573 0.0481 11.5576 ;
			 LAYER V2 ;
			RECT 0.0215 11.4702 0.0364 11.4827 ;
		END

		ANTENNAGATEAREA 0.00027817 ;
		ANTENNADIFFAREA 0.00194719 ;
		ANTENNAPARTIALMETALAREA 0.00195671 ;
	END WENA[14]

	PIN WENA[15]
		USE SIGNAL ;
		DIRECTION INPUT ;
		SHAPE ABUTMENT ;
		PORT
			 LAYER M2 ;
			RECT 0.0098 12.2478 0.0481 12.2855 ;
			 LAYER M3 ;
			RECT 0.0098 12.2478 0.0481 12.3482 ;
			 LAYER V2 ;
			RECT 0.0215 12.2608 0.0364 12.2733 ;
		END

		ANTENNAGATEAREA 0.00027817 ;
		ANTENNADIFFAREA 0.00194719 ;
		ANTENNAPARTIALMETALAREA 0.00195671 ;
	END WENA[15]

	PIN WENA[16]
		USE SIGNAL ;
		DIRECTION INPUT ;
		SHAPE ABUTMENT ;
		PORT
			 LAYER M2 ;
			RECT 0.0098 13.0384 0.0481 13.0761 ;
			 LAYER M3 ;
			RECT 0.0098 13.0384 0.0481 13.1388 ;
			 LAYER V2 ;
			RECT 0.0215 13.0514 0.0364 13.0639 ;
		END

		ANTENNAGATEAREA 0.00027817 ;
		ANTENNADIFFAREA 0.00194719 ;
		ANTENNAPARTIALMETALAREA 0.00195671 ;
	END WENA[16]

	PIN WENA[17]
		USE SIGNAL ;
		DIRECTION INPUT ;
		SHAPE ABUTMENT ;
		PORT
			 LAYER M2 ;
			RECT 0.0098 13.829 0.0481 13.8667 ;
			 LAYER M3 ;
			RECT 0.0098 13.829 0.0481 13.9294 ;
			 LAYER V2 ;
			RECT 0.0215 13.842 0.0364 13.8545 ;
		END

		ANTENNAGATEAREA 0.00027817 ;
		ANTENNADIFFAREA 0.00194719 ;
		ANTENNAPARTIALMETALAREA 0.00195671 ;
	END WENA[17]

	PIN WENA[18]
		USE SIGNAL ;
		DIRECTION INPUT ;
		SHAPE ABUTMENT ;
		PORT
			 LAYER M2 ;
			RECT 0.0098 14.6196 0.0481 14.6573 ;
			 LAYER M3 ;
			RECT 0.0098 14.6196 0.0481 14.72 ;
			 LAYER V2 ;
			RECT 0.0215 14.6325 0.0364 14.6451 ;
		END

		ANTENNAGATEAREA 0.00027817 ;
		ANTENNADIFFAREA 0.00194719 ;
		ANTENNAPARTIALMETALAREA 0.00195671 ;
	END WENA[18]

	PIN WENA[19]
		USE SIGNAL ;
		DIRECTION INPUT ;
		SHAPE ABUTMENT ;
		PORT
			 LAYER M2 ;
			RECT 0.0098 15.4102 0.0481 15.4478 ;
			 LAYER M3 ;
			RECT 0.0098 15.4102 0.0481 15.5106 ;
			 LAYER V2 ;
			RECT 0.0215 15.4231 0.0364 15.4357 ;
		END

		ANTENNAGATEAREA 0.00027817 ;
		ANTENNADIFFAREA 0.00194719 ;
		ANTENNAPARTIALMETALAREA 0.00195671 ;
	END WENA[19]

	PIN WENA[1]
		USE SIGNAL ;
		DIRECTION INPUT ;
		SHAPE ABUTMENT ;
		PORT
			 LAYER M2 ;
			RECT 0.0098 1.1796 0.0481 1.2173 ;
			 LAYER M3 ;
			RECT 0.0098 1.1796 0.0481 1.28 ;
			 LAYER V2 ;
			RECT 0.0215 1.1925 0.0364 1.2051 ;
		END

		ANTENNAGATEAREA 0.00027817 ;
		ANTENNADIFFAREA 0.00194719 ;
		ANTENNAPARTIALMETALAREA 0.00195671 ;
	END WENA[1]

	PIN WENA[20]
		USE SIGNAL ;
		DIRECTION INPUT ;
		SHAPE ABUTMENT ;
		PORT
			 LAYER M2 ;
			RECT 0.0098 16.2008 0.0481 16.2384 ;
			 LAYER M3 ;
			RECT 0.0098 16.2008 0.0481 16.3012 ;
			 LAYER V2 ;
			RECT 0.0215 16.2137 0.0364 16.2263 ;
		END

		ANTENNAGATEAREA 0.00027817 ;
		ANTENNADIFFAREA 0.00194719 ;
		ANTENNAPARTIALMETALAREA 0.00195671 ;
	END WENA[20]

	PIN WENA[21]
		USE SIGNAL ;
		DIRECTION INPUT ;
		SHAPE ABUTMENT ;
		PORT
			 LAYER M2 ;
			RECT 0.0098 16.9914 0.0481 17.029 ;
			 LAYER M3 ;
			RECT 0.0098 16.9914 0.0481 17.0918 ;
			 LAYER V2 ;
			RECT 0.0215 17.0043 0.0364 17.0169 ;
		END

		ANTENNAGATEAREA 0.00027817 ;
		ANTENNADIFFAREA 0.00194719 ;
		ANTENNAPARTIALMETALAREA 0.00195671 ;
	END WENA[21]

	PIN WENA[22]
		USE SIGNAL ;
		DIRECTION INPUT ;
		SHAPE ABUTMENT ;
		PORT
			 LAYER M2 ;
			RECT 0.0098 17.782 0.0481 17.8196 ;
			 LAYER M3 ;
			RECT 0.0098 17.782 0.0481 17.8824 ;
			 LAYER V2 ;
			RECT 0.0215 17.7949 0.0364 17.8075 ;
		END

		ANTENNAGATEAREA 0.00027817 ;
		ANTENNADIFFAREA 0.00194719 ;
		ANTENNAPARTIALMETALAREA 0.00195671 ;
	END WENA[22]

	PIN WENA[23]
		USE SIGNAL ;
		DIRECTION INPUT ;
		SHAPE ABUTMENT ;
		PORT
			 LAYER M2 ;
			RECT 0.0098 18.5725 0.0481 18.6102 ;
			 LAYER M3 ;
			RECT 0.0098 18.5725 0.0481 18.6729 ;
			 LAYER V2 ;
			RECT 0.0215 18.5855 0.0364 18.598 ;
		END

		ANTENNAGATEAREA 0.00027817 ;
		ANTENNADIFFAREA 0.00194719 ;
		ANTENNAPARTIALMETALAREA 0.00195671 ;
	END WENA[23]

	PIN WENA[24]
		USE SIGNAL ;
		DIRECTION INPUT ;
		SHAPE ABUTMENT ;
		PORT
			 LAYER M2 ;
			RECT 0.0098 19.3631 0.0481 19.4008 ;
			 LAYER M3 ;
			RECT 0.0098 19.3631 0.0481 19.4635 ;
			 LAYER V2 ;
			RECT 0.0215 19.3761 0.0364 19.3886 ;
		END

		ANTENNAGATEAREA 0.00027817 ;
		ANTENNADIFFAREA 0.00194719 ;
		ANTENNAPARTIALMETALAREA 0.00195671 ;
	END WENA[24]

	PIN WENA[25]
		USE SIGNAL ;
		DIRECTION INPUT ;
		SHAPE ABUTMENT ;
		PORT
			 LAYER M2 ;
			RECT 0.0098 20.1537 0.0481 20.1914 ;
			 LAYER M3 ;
			RECT 0.0098 20.1537 0.0481 20.2541 ;
			 LAYER V2 ;
			RECT 0.0215 20.1667 0.0364 20.1792 ;
		END

		ANTENNAGATEAREA 0.00027817 ;
		ANTENNADIFFAREA 0.00194719 ;
		ANTENNAPARTIALMETALAREA 0.00195671 ;
	END WENA[25]

	PIN WENA[26]
		USE SIGNAL ;
		DIRECTION INPUT ;
		SHAPE ABUTMENT ;
		PORT
			 LAYER M2 ;
			RECT 0.0098 20.9443 0.0481 20.982 ;
			 LAYER M3 ;
			RECT 0.0098 20.9443 0.0481 21.0447 ;
			 LAYER V2 ;
			RECT 0.0215 20.9573 0.0364 20.9698 ;
		END

		ANTENNAGATEAREA 0.00027817 ;
		ANTENNADIFFAREA 0.00194719 ;
		ANTENNAPARTIALMETALAREA 0.00195671 ;
	END WENA[26]

	PIN WENA[27]
		USE SIGNAL ;
		DIRECTION INPUT ;
		SHAPE ABUTMENT ;
		PORT
			 LAYER M2 ;
			RECT 0.0098 21.7349 0.0481 21.7725 ;
			 LAYER M3 ;
			RECT 0.0098 21.7349 0.0481 21.8353 ;
			 LAYER V2 ;
			RECT 0.0215 21.7478 0.0364 21.7604 ;
		END

		ANTENNAGATEAREA 0.00027817 ;
		ANTENNADIFFAREA 0.00194719 ;
		ANTENNAPARTIALMETALAREA 0.00195671 ;
	END WENA[27]

	PIN WENA[28]
		USE SIGNAL ;
		DIRECTION INPUT ;
		SHAPE ABUTMENT ;
		PORT
			 LAYER M2 ;
			RECT 0.0098 22.5255 0.0481 22.5631 ;
			 LAYER M3 ;
			RECT 0.0098 22.5255 0.0481 22.6259 ;
			 LAYER V2 ;
			RECT 0.0215 22.5384 0.0364 22.551 ;
		END

		ANTENNAGATEAREA 0.00027817 ;
		ANTENNADIFFAREA 0.00194719 ;
		ANTENNAPARTIALMETALAREA 0.00195671 ;
	END WENA[28]

	PIN WENA[29]
		USE SIGNAL ;
		DIRECTION INPUT ;
		SHAPE ABUTMENT ;
		PORT
			 LAYER M2 ;
			RECT 0.0098 23.3161 0.0481 23.3537 ;
			 LAYER M3 ;
			RECT 0.0098 23.3161 0.0481 23.4165 ;
			 LAYER V2 ;
			RECT 0.0215 23.329 0.0364 23.3416 ;
		END

		ANTENNAGATEAREA 0.00027817 ;
		ANTENNADIFFAREA 0.00194719 ;
		ANTENNAPARTIALMETALAREA 0.00195671 ;
	END WENA[29]

	PIN WENA[2]
		USE SIGNAL ;
		DIRECTION INPUT ;
		SHAPE ABUTMENT ;
		PORT
			 LAYER M2 ;
			RECT 0.0098 1.9702 0.0481 2.0078 ;
			 LAYER M3 ;
			RECT 0.0098 1.9702 0.0481 2.0706 ;
			 LAYER V2 ;
			RECT 0.0215 1.9831 0.0364 1.9957 ;
		END

		ANTENNAGATEAREA 0.00027817 ;
		ANTENNADIFFAREA 0.00194719 ;
		ANTENNAPARTIALMETALAREA 0.00195671 ;
	END WENA[2]

	PIN WENA[30]
		USE SIGNAL ;
		DIRECTION INPUT ;
		SHAPE ABUTMENT ;
		PORT
			 LAYER M2 ;
			RECT 0.0098 24.1067 0.0481 24.1443 ;
			 LAYER M3 ;
			RECT 0.0098 24.1067 0.0481 24.2071 ;
			 LAYER V2 ;
			RECT 0.0215 24.1196 0.0364 24.1322 ;
		END

		ANTENNAGATEAREA 0.00027817 ;
		ANTENNADIFFAREA 0.00194719 ;
		ANTENNAPARTIALMETALAREA 0.00195671 ;
	END WENA[30]

	PIN WENA[31]
		USE SIGNAL ;
		DIRECTION INPUT ;
		SHAPE ABUTMENT ;
		PORT
			 LAYER M2 ;
			RECT 0.0098 24.8973 0.0481 24.9349 ;
			 LAYER M3 ;
			RECT 0.0098 24.8973 0.0481 24.9976 ;
			 LAYER V2 ;
			RECT 0.0215 24.9102 0.0364 24.9227 ;
		END

		ANTENNAGATEAREA 0.00027817 ;
		ANTENNADIFFAREA 0.00194719 ;
		ANTENNAPARTIALMETALAREA 0.00195671 ;
	END WENA[31]

	PIN WENA[32]
		USE SIGNAL ;
		DIRECTION INPUT ;
		SHAPE ABUTMENT ;
		PORT
			 LAYER M2 ;
			RECT 0.0098 25.6878 0.0481 25.7255 ;
			 LAYER M3 ;
			RECT 0.0098 25.6878 0.0481 25.7882 ;
			 LAYER V2 ;
			RECT 0.0215 25.7008 0.0364 25.7133 ;
		END

		ANTENNAGATEAREA 0.00027817 ;
		ANTENNADIFFAREA 0.00194719 ;
		ANTENNAPARTIALMETALAREA 0.00195671 ;
	END WENA[32]

	PIN WENA[33]
		USE SIGNAL ;
		DIRECTION INPUT ;
		SHAPE ABUTMENT ;
		PORT
			 LAYER M2 ;
			RECT 0.0098 35.9216 0.0481 35.9592 ;
			 LAYER M3 ;
			RECT 0.0098 35.8588 0.0481 35.9592 ;
			 LAYER V2 ;
			RECT 0.0215 35.9337 0.0364 35.9463 ;
		END

		ANTENNAGATEAREA 0.00027817 ;
		ANTENNADIFFAREA 0.00194719 ;
		ANTENNAPARTIALMETALAREA 0.00195671 ;
	END WENA[33]

	PIN WENA[34]
		USE SIGNAL ;
		DIRECTION INPUT ;
		SHAPE ABUTMENT ;
		PORT
			 LAYER M2 ;
			RECT 0.0098 36.7122 0.0481 36.7498 ;
			 LAYER M3 ;
			RECT 0.0098 36.6494 0.0481 36.7498 ;
			 LAYER V2 ;
			RECT 0.0215 36.7243 0.0364 36.7369 ;
		END

		ANTENNAGATEAREA 0.00027817 ;
		ANTENNADIFFAREA 0.00194719 ;
		ANTENNAPARTIALMETALAREA 0.00195671 ;
	END WENA[34]

	PIN WENA[35]
		USE SIGNAL ;
		DIRECTION INPUT ;
		SHAPE ABUTMENT ;
		PORT
			 LAYER M2 ;
			RECT 0.0098 37.5027 0.0481 37.5404 ;
			 LAYER M3 ;
			RECT 0.0098 37.44 0.0481 37.5404 ;
			 LAYER V2 ;
			RECT 0.0215 37.5149 0.0364 37.5275 ;
		END

		ANTENNAGATEAREA 0.00027817 ;
		ANTENNADIFFAREA 0.00194719 ;
		ANTENNAPARTIALMETALAREA 0.00195671 ;
	END WENA[35]

	PIN WENA[36]
		USE SIGNAL ;
		DIRECTION INPUT ;
		SHAPE ABUTMENT ;
		PORT
			 LAYER M2 ;
			RECT 0.0098 38.2933 0.0481 38.331 ;
			 LAYER M3 ;
			RECT 0.0098 38.2306 0.0481 38.331 ;
			 LAYER V2 ;
			RECT 0.0215 38.3055 0.0364 38.318 ;
		END

		ANTENNAGATEAREA 0.00027817 ;
		ANTENNADIFFAREA 0.00194719 ;
		ANTENNAPARTIALMETALAREA 0.00195671 ;
	END WENA[36]

	PIN WENA[37]
		USE SIGNAL ;
		DIRECTION INPUT ;
		SHAPE ABUTMENT ;
		PORT
			 LAYER M2 ;
			RECT 0.0098 39.0839 0.0481 39.1216 ;
			 LAYER M3 ;
			RECT 0.0098 39.0212 0.0481 39.1216 ;
			 LAYER V2 ;
			RECT 0.0215 39.0961 0.0364 39.1086 ;
		END

		ANTENNAGATEAREA 0.00027817 ;
		ANTENNADIFFAREA 0.00194719 ;
		ANTENNAPARTIALMETALAREA 0.00195671 ;
	END WENA[37]

	PIN WENA[38]
		USE SIGNAL ;
		DIRECTION INPUT ;
		SHAPE ABUTMENT ;
		PORT
			 LAYER M2 ;
			RECT 0.0098 39.8745 0.0481 39.9122 ;
			 LAYER M3 ;
			RECT 0.0098 39.8118 0.0481 39.9122 ;
			 LAYER V2 ;
			RECT 0.0215 39.8867 0.0364 39.8992 ;
		END

		ANTENNAGATEAREA 0.00027817 ;
		ANTENNADIFFAREA 0.00194719 ;
		ANTENNAPARTIALMETALAREA 0.00195671 ;
	END WENA[38]

	PIN WENA[39]
		USE SIGNAL ;
		DIRECTION INPUT ;
		SHAPE ABUTMENT ;
		PORT
			 LAYER M2 ;
			RECT 0.0098 40.6651 0.0481 40.7027 ;
			 LAYER M3 ;
			RECT 0.0098 40.6024 0.0481 40.7027 ;
			 LAYER V2 ;
			RECT 0.0215 40.6773 0.0364 40.6898 ;
		END

		ANTENNAGATEAREA 0.00027817 ;
		ANTENNADIFFAREA 0.00194719 ;
		ANTENNAPARTIALMETALAREA 0.00195671 ;
	END WENA[39]

	PIN WENA[3]
		USE SIGNAL ;
		DIRECTION INPUT ;
		SHAPE ABUTMENT ;
		PORT
			 LAYER M2 ;
			RECT 0.0098 2.7608 0.0481 2.7984 ;
			 LAYER M3 ;
			RECT 0.0098 2.7608 0.0481 2.8612 ;
			 LAYER V2 ;
			RECT 0.0215 2.7737 0.0364 2.7863 ;
		END

		ANTENNAGATEAREA 0.00027817 ;
		ANTENNADIFFAREA 0.00194719 ;
		ANTENNAPARTIALMETALAREA 0.00195671 ;
	END WENA[3]

	PIN WENA[40]
		USE SIGNAL ;
		DIRECTION INPUT ;
		SHAPE ABUTMENT ;
		PORT
			 LAYER M2 ;
			RECT 0.0098 41.4557 0.0481 41.4933 ;
			 LAYER M3 ;
			RECT 0.0098 41.3929 0.0481 41.4933 ;
			 LAYER V2 ;
			RECT 0.0215 41.4678 0.0364 41.4804 ;
		END

		ANTENNAGATEAREA 0.00027817 ;
		ANTENNADIFFAREA 0.00194719 ;
		ANTENNAPARTIALMETALAREA 0.00195671 ;
	END WENA[40]

	PIN WENA[41]
		USE SIGNAL ;
		DIRECTION INPUT ;
		SHAPE ABUTMENT ;
		PORT
			 LAYER M2 ;
			RECT 0.0098 42.2463 0.0481 42.2839 ;
			 LAYER M3 ;
			RECT 0.0098 42.1835 0.0481 42.2839 ;
			 LAYER V2 ;
			RECT 0.0215 42.2584 0.0364 42.271 ;
		END

		ANTENNAGATEAREA 0.00027817 ;
		ANTENNADIFFAREA 0.00194719 ;
		ANTENNAPARTIALMETALAREA 0.00195671 ;
	END WENA[41]

	PIN WENA[42]
		USE SIGNAL ;
		DIRECTION INPUT ;
		SHAPE ABUTMENT ;
		PORT
			 LAYER M2 ;
			RECT 0.0098 43.0369 0.0481 43.0745 ;
			 LAYER M3 ;
			RECT 0.0098 42.9741 0.0481 43.0745 ;
			 LAYER V2 ;
			RECT 0.0215 43.049 0.0364 43.0616 ;
		END

		ANTENNAGATEAREA 0.00027817 ;
		ANTENNADIFFAREA 0.00194719 ;
		ANTENNAPARTIALMETALAREA 0.00195671 ;
	END WENA[42]

	PIN WENA[43]
		USE SIGNAL ;
		DIRECTION INPUT ;
		SHAPE ABUTMENT ;
		PORT
			 LAYER M2 ;
			RECT 0.0098 43.8275 0.0481 43.8651 ;
			 LAYER M3 ;
			RECT 0.0098 43.7647 0.0481 43.8651 ;
			 LAYER V2 ;
			RECT 0.0215 43.8396 0.0364 43.8522 ;
		END

		ANTENNAGATEAREA 0.00027817 ;
		ANTENNADIFFAREA 0.00194719 ;
		ANTENNAPARTIALMETALAREA 0.00195671 ;
	END WENA[43]

	PIN WENA[44]
		USE SIGNAL ;
		DIRECTION INPUT ;
		SHAPE ABUTMENT ;
		PORT
			 LAYER M2 ;
			RECT 0.0098 44.618 0.0481 44.6557 ;
			 LAYER M3 ;
			RECT 0.0098 44.5553 0.0481 44.6557 ;
			 LAYER V2 ;
			RECT 0.0215 44.6302 0.0364 44.6427 ;
		END

		ANTENNAGATEAREA 0.00027817 ;
		ANTENNADIFFAREA 0.00194719 ;
		ANTENNAPARTIALMETALAREA 0.00195671 ;
	END WENA[44]

	PIN WENA[45]
		USE SIGNAL ;
		DIRECTION INPUT ;
		SHAPE ABUTMENT ;
		PORT
			 LAYER M2 ;
			RECT 0.0098 45.4086 0.0481 45.4463 ;
			 LAYER M3 ;
			RECT 0.0098 45.3459 0.0481 45.4463 ;
			 LAYER V2 ;
			RECT 0.0215 45.4208 0.0364 45.4333 ;
		END

		ANTENNAGATEAREA 0.00027817 ;
		ANTENNADIFFAREA 0.00194719 ;
		ANTENNAPARTIALMETALAREA 0.00195671 ;
	END WENA[45]

	PIN WENA[46]
		USE SIGNAL ;
		DIRECTION INPUT ;
		SHAPE ABUTMENT ;
		PORT
			 LAYER M2 ;
			RECT 0.0098 46.1992 0.0481 46.2369 ;
			 LAYER M3 ;
			RECT 0.0098 46.1365 0.0481 46.2369 ;
			 LAYER V2 ;
			RECT 0.0215 46.2114 0.0364 46.2239 ;
		END

		ANTENNAGATEAREA 0.00027817 ;
		ANTENNADIFFAREA 0.00194719 ;
		ANTENNAPARTIALMETALAREA 0.00195671 ;
	END WENA[46]

	PIN WENA[47]
		USE SIGNAL ;
		DIRECTION INPUT ;
		SHAPE ABUTMENT ;
		PORT
			 LAYER M2 ;
			RECT 0.0098 46.9898 0.0481 47.0275 ;
			 LAYER M3 ;
			RECT 0.0098 46.9271 0.0481 47.0275 ;
			 LAYER V2 ;
			RECT 0.0215 47.002 0.0364 47.0145 ;
		END

		ANTENNAGATEAREA 0.00027817 ;
		ANTENNADIFFAREA 0.00194719 ;
		ANTENNAPARTIALMETALAREA 0.00195671 ;
	END WENA[47]

	PIN WENA[48]
		USE SIGNAL ;
		DIRECTION INPUT ;
		SHAPE ABUTMENT ;
		PORT
			 LAYER M2 ;
			RECT 0.0098 47.7804 0.0481 47.818 ;
			 LAYER M3 ;
			RECT 0.0098 47.7176 0.0481 47.818 ;
			 LAYER V2 ;
			RECT 0.0215 47.7925 0.0364 47.8051 ;
		END

		ANTENNAGATEAREA 0.00027817 ;
		ANTENNADIFFAREA 0.00194719 ;
		ANTENNAPARTIALMETALAREA 0.00195671 ;
	END WENA[48]

	PIN WENA[49]
		USE SIGNAL ;
		DIRECTION INPUT ;
		SHAPE ABUTMENT ;
		PORT
			 LAYER M2 ;
			RECT 0.0098 48.571 0.0481 48.6086 ;
			 LAYER M3 ;
			RECT 0.0098 48.5082 0.0481 48.6086 ;
			 LAYER V2 ;
			RECT 0.0215 48.5831 0.0364 48.5957 ;
		END

		ANTENNAGATEAREA 0.00027817 ;
		ANTENNADIFFAREA 0.00194719 ;
		ANTENNAPARTIALMETALAREA 0.00195671 ;
	END WENA[49]

	PIN WENA[4]
		USE SIGNAL ;
		DIRECTION INPUT ;
		SHAPE ABUTMENT ;
		PORT
			 LAYER M2 ;
			RECT 0.0098 3.5514 0.0481 3.589 ;
			 LAYER M3 ;
			RECT 0.0098 3.5514 0.0481 3.6518 ;
			 LAYER V2 ;
			RECT 0.0215 3.5643 0.0364 3.5769 ;
		END

		ANTENNAGATEAREA 0.00027817 ;
		ANTENNADIFFAREA 0.00194719 ;
		ANTENNAPARTIALMETALAREA 0.00195671 ;
	END WENA[4]

	PIN WENA[50]
		USE SIGNAL ;
		DIRECTION INPUT ;
		SHAPE ABUTMENT ;
		PORT
			 LAYER M2 ;
			RECT 0.0098 49.3616 0.0481 49.3992 ;
			 LAYER M3 ;
			RECT 0.0098 49.2988 0.0481 49.3992 ;
			 LAYER V2 ;
			RECT 0.0215 49.3737 0.0364 49.3863 ;
		END

		ANTENNAGATEAREA 0.00027817 ;
		ANTENNADIFFAREA 0.00194719 ;
		ANTENNAPARTIALMETALAREA 0.00195671 ;
	END WENA[50]

	PIN WENA[51]
		USE SIGNAL ;
		DIRECTION INPUT ;
		SHAPE ABUTMENT ;
		PORT
			 LAYER M2 ;
			RECT 0.0098 50.1522 0.0481 50.1898 ;
			 LAYER M3 ;
			RECT 0.0098 50.0894 0.0481 50.1898 ;
			 LAYER V2 ;
			RECT 0.0215 50.1643 0.0364 50.1769 ;
		END

		ANTENNAGATEAREA 0.00027817 ;
		ANTENNADIFFAREA 0.00194719 ;
		ANTENNAPARTIALMETALAREA 0.00195671 ;
	END WENA[51]

	PIN WENA[52]
		USE SIGNAL ;
		DIRECTION INPUT ;
		SHAPE ABUTMENT ;
		PORT
			 LAYER M2 ;
			RECT 0.0098 50.9427 0.0481 50.9804 ;
			 LAYER M3 ;
			RECT 0.0098 50.88 0.0481 50.9804 ;
			 LAYER V2 ;
			RECT 0.0215 50.9549 0.0364 50.9675 ;
		END

		ANTENNAGATEAREA 0.00027817 ;
		ANTENNADIFFAREA 0.00194719 ;
		ANTENNAPARTIALMETALAREA 0.00195671 ;
	END WENA[52]

	PIN WENA[53]
		USE SIGNAL ;
		DIRECTION INPUT ;
		SHAPE ABUTMENT ;
		PORT
			 LAYER M2 ;
			RECT 0.0098 51.7333 0.0481 51.771 ;
			 LAYER M3 ;
			RECT 0.0098 51.6706 0.0481 51.771 ;
			 LAYER V2 ;
			RECT 0.0215 51.7455 0.0364 51.758 ;
		END

		ANTENNAGATEAREA 0.00027817 ;
		ANTENNADIFFAREA 0.00194719 ;
		ANTENNAPARTIALMETALAREA 0.00195671 ;
	END WENA[53]

	PIN WENA[54]
		USE SIGNAL ;
		DIRECTION INPUT ;
		SHAPE ABUTMENT ;
		PORT
			 LAYER M2 ;
			RECT 0.0098 52.5239 0.0481 52.5616 ;
			 LAYER M3 ;
			RECT 0.0098 52.4612 0.0481 52.5616 ;
			 LAYER V2 ;
			RECT 0.0215 52.5361 0.0364 52.5486 ;
		END

		ANTENNAGATEAREA 0.00027817 ;
		ANTENNADIFFAREA 0.00194719 ;
		ANTENNAPARTIALMETALAREA 0.00195671 ;
	END WENA[54]

	PIN WENA[55]
		USE SIGNAL ;
		DIRECTION INPUT ;
		SHAPE ABUTMENT ;
		PORT
			 LAYER M2 ;
			RECT 0.0098 53.3145 0.0481 53.3522 ;
			 LAYER M3 ;
			RECT 0.0098 53.2518 0.0481 53.3522 ;
			 LAYER V2 ;
			RECT 0.0215 53.3267 0.0364 53.3392 ;
		END

		ANTENNAGATEAREA 0.00027817 ;
		ANTENNADIFFAREA 0.00194719 ;
		ANTENNAPARTIALMETALAREA 0.00195671 ;
	END WENA[55]

	PIN WENA[56]
		USE SIGNAL ;
		DIRECTION INPUT ;
		SHAPE ABUTMENT ;
		PORT
			 LAYER M2 ;
			RECT 0.0098 54.1051 0.0481 54.1427 ;
			 LAYER M3 ;
			RECT 0.0098 54.0424 0.0481 54.1427 ;
			 LAYER V2 ;
			RECT 0.0215 54.1173 0.0364 54.1298 ;
		END

		ANTENNAGATEAREA 0.00027817 ;
		ANTENNADIFFAREA 0.00194719 ;
		ANTENNAPARTIALMETALAREA 0.00195671 ;
	END WENA[56]

	PIN WENA[57]
		USE SIGNAL ;
		DIRECTION INPUT ;
		SHAPE ABUTMENT ;
		PORT
			 LAYER M2 ;
			RECT 0.0098 54.8957 0.0481 54.9333 ;
			 LAYER M3 ;
			RECT 0.0098 54.8329 0.0481 54.9333 ;
			 LAYER V2 ;
			RECT 0.0215 54.9078 0.0364 54.9204 ;
		END

		ANTENNAGATEAREA 0.00027817 ;
		ANTENNADIFFAREA 0.00194719 ;
		ANTENNAPARTIALMETALAREA 0.00195671 ;
	END WENA[57]

	PIN WENA[58]
		USE SIGNAL ;
		DIRECTION INPUT ;
		SHAPE ABUTMENT ;
		PORT
			 LAYER M2 ;
			RECT 0.0098 55.6863 0.0481 55.7239 ;
			 LAYER M3 ;
			RECT 0.0098 55.6235 0.0481 55.7239 ;
			 LAYER V2 ;
			RECT 0.0215 55.6984 0.0364 55.711 ;
		END

		ANTENNAGATEAREA 0.00027817 ;
		ANTENNADIFFAREA 0.00194719 ;
		ANTENNAPARTIALMETALAREA 0.00195671 ;
	END WENA[58]

	PIN WENA[59]
		USE SIGNAL ;
		DIRECTION INPUT ;
		SHAPE ABUTMENT ;
		PORT
			 LAYER M2 ;
			RECT 0.0098 56.4769 0.0481 56.5145 ;
			 LAYER M3 ;
			RECT 0.0098 56.4141 0.0481 56.5145 ;
			 LAYER V2 ;
			RECT 0.0215 56.489 0.0364 56.5016 ;
		END

		ANTENNAGATEAREA 0.00027817 ;
		ANTENNADIFFAREA 0.00194719 ;
		ANTENNAPARTIALMETALAREA 0.00195671 ;
	END WENA[59]

	PIN WENA[5]
		USE SIGNAL ;
		DIRECTION INPUT ;
		SHAPE ABUTMENT ;
		PORT
			 LAYER M2 ;
			RECT 0.0098 4.342 0.0481 4.3796 ;
			 LAYER M3 ;
			RECT 0.0098 4.342 0.0481 4.4424 ;
			 LAYER V2 ;
			RECT 0.0215 4.3549 0.0364 4.3675 ;
		END

		ANTENNAGATEAREA 0.00027817 ;
		ANTENNADIFFAREA 0.00194719 ;
		ANTENNAPARTIALMETALAREA 0.00195671 ;
	END WENA[5]

	PIN WENA[60]
		USE SIGNAL ;
		DIRECTION INPUT ;
		SHAPE ABUTMENT ;
		PORT
			 LAYER M2 ;
			RECT 0.0098 57.2675 0.0481 57.3051 ;
			 LAYER M3 ;
			RECT 0.0098 57.2047 0.0481 57.3051 ;
			 LAYER V2 ;
			RECT 0.0215 57.2796 0.0364 57.2922 ;
		END

		ANTENNAGATEAREA 0.00027817 ;
		ANTENNADIFFAREA 0.00194719 ;
		ANTENNAPARTIALMETALAREA 0.00195671 ;
	END WENA[60]

	PIN WENA[61]
		USE SIGNAL ;
		DIRECTION INPUT ;
		SHAPE ABUTMENT ;
		PORT
			 LAYER M2 ;
			RECT 0.0098 58.058 0.0481 58.0957 ;
			 LAYER M3 ;
			RECT 0.0098 57.9953 0.0481 58.0957 ;
			 LAYER V2 ;
			RECT 0.0215 58.0702 0.0364 58.0827 ;
		END

		ANTENNAGATEAREA 0.00027817 ;
		ANTENNADIFFAREA 0.00194719 ;
		ANTENNAPARTIALMETALAREA 0.00195671 ;
	END WENA[61]

	PIN WENA[62]
		USE SIGNAL ;
		DIRECTION INPUT ;
		SHAPE ABUTMENT ;
		PORT
			 LAYER M2 ;
			RECT 0.0098 58.8486 0.0481 58.8863 ;
			 LAYER M3 ;
			RECT 0.0098 58.7859 0.0481 58.8863 ;
			 LAYER V2 ;
			RECT 0.0215 58.8608 0.0364 58.8733 ;
		END

		ANTENNAGATEAREA 0.00027817 ;
		ANTENNADIFFAREA 0.00194719 ;
		ANTENNAPARTIALMETALAREA 0.00195671 ;
	END WENA[62]

	PIN WENA[63]
		USE SIGNAL ;
		DIRECTION INPUT ;
		SHAPE ABUTMENT ;
		PORT
			 LAYER M2 ;
			RECT 0.0098 59.6392 0.0481 59.6769 ;
			 LAYER M3 ;
			RECT 0.0098 59.5765 0.0481 59.6769 ;
			 LAYER V2 ;
			RECT 0.0215 59.6514 0.0364 59.6639 ;
		END

		ANTENNAGATEAREA 0.00027817 ;
		ANTENNADIFFAREA 0.00194719 ;
		ANTENNAPARTIALMETALAREA 0.00195671 ;
	END WENA[63]

	PIN WENA[64]
		USE SIGNAL ;
		DIRECTION INPUT ;
		SHAPE ABUTMENT ;
		PORT
			 LAYER M2 ;
			RECT 0.0098 60.4298 0.0481 60.4675 ;
			 LAYER M3 ;
			RECT 0.0098 60.3671 0.0481 60.4675 ;
			 LAYER V2 ;
			RECT 0.0215 60.442 0.0364 60.4545 ;
		END

		ANTENNAGATEAREA 0.00027817 ;
		ANTENNADIFFAREA 0.00194719 ;
		ANTENNAPARTIALMETALAREA 0.00195671 ;
	END WENA[64]

	PIN WENA[65]
		USE SIGNAL ;
		DIRECTION INPUT ;
		SHAPE ABUTMENT ;
		PORT
			 LAYER M2 ;
			RECT 0.0098 61.2204 0.0481 61.258 ;
			 LAYER M3 ;
			RECT 0.0098 61.1576 0.0481 61.258 ;
			 LAYER V2 ;
			RECT 0.0215 61.2325 0.0364 61.2451 ;
		END

		ANTENNAGATEAREA 0.00027817 ;
		ANTENNADIFFAREA 0.00194719 ;
		ANTENNAPARTIALMETALAREA 0.00195671 ;
	END WENA[65]

	PIN WENA[6]
		USE SIGNAL ;
		DIRECTION INPUT ;
		SHAPE ABUTMENT ;
		PORT
			 LAYER M2 ;
			RECT 0.0098 5.1325 0.0481 5.1702 ;
			 LAYER M3 ;
			RECT 0.0098 5.1325 0.0481 5.2329 ;
			 LAYER V2 ;
			RECT 0.0215 5.1455 0.0364 5.158 ;
		END

		ANTENNAGATEAREA 0.00027817 ;
		ANTENNADIFFAREA 0.00194719 ;
		ANTENNAPARTIALMETALAREA 0.00195671 ;
	END WENA[6]

	PIN WENA[7]
		USE SIGNAL ;
		DIRECTION INPUT ;
		SHAPE ABUTMENT ;
		PORT
			 LAYER M2 ;
			RECT 0.0098 5.9231 0.0481 5.9608 ;
			 LAYER M3 ;
			RECT 0.0098 5.9231 0.0481 6.0235 ;
			 LAYER V2 ;
			RECT 0.0215 5.9361 0.0364 5.9486 ;
		END

		ANTENNAGATEAREA 0.00027817 ;
		ANTENNADIFFAREA 0.00194719 ;
		ANTENNAPARTIALMETALAREA 0.00195671 ;
	END WENA[7]

	PIN WENA[8]
		USE SIGNAL ;
		DIRECTION INPUT ;
		SHAPE ABUTMENT ;
		PORT
			 LAYER M2 ;
			RECT 0.0098 6.7137 0.0481 6.7514 ;
			 LAYER M3 ;
			RECT 0.0098 6.7137 0.0481 6.8141 ;
			 LAYER V2 ;
			RECT 0.0215 6.7267 0.0364 6.7392 ;
		END

		ANTENNAGATEAREA 0.00027817 ;
		ANTENNADIFFAREA 0.00194719 ;
		ANTENNAPARTIALMETALAREA 0.00195671 ;
	END WENA[8]

	PIN WENA[9]
		USE SIGNAL ;
		DIRECTION INPUT ;
		SHAPE ABUTMENT ;
		PORT
			 LAYER M2 ;
			RECT 0.0098 7.5043 0.0481 7.542 ;
			 LAYER M3 ;
			RECT 0.0098 7.5043 0.0481 7.6047 ;
			 LAYER V2 ;
			RECT 0.0215 7.5173 0.0364 7.5298 ;
		END

		ANTENNAGATEAREA 0.00027817 ;
		ANTENNADIFFAREA 0.00194719 ;
		ANTENNAPARTIALMETALAREA 0.00195671 ;
	END WENA[9]

	PIN WENB[0]
		USE SIGNAL ;
		DIRECTION INPUT ;
		SHAPE ABUTMENT ;
		PORT
			 LAYER M2 ;
			RECT 0.0098 0.2384 0.0481 0.2761 ;
		END

		ANTENNAGATEAREA 0.00027817 ;
		ANTENNADIFFAREA 0.00194719 ;
		ANTENNAPARTIALMETALAREA 0.00195671 ;
	END WENB[0]

	PIN WENB[10]
		USE SIGNAL ;
		DIRECTION INPUT ;
		SHAPE ABUTMENT ;
		PORT
			 LAYER M2 ;
			RECT 0.0098 8.1443 0.0481 8.182 ;
		END

		ANTENNAGATEAREA 0.00027817 ;
		ANTENNADIFFAREA 0.00194719 ;
		ANTENNAPARTIALMETALAREA 0.00195671 ;
	END WENB[10]

	PIN WENB[11]
		USE SIGNAL ;
		DIRECTION INPUT ;
		SHAPE ABUTMENT ;
		PORT
			 LAYER M2 ;
			RECT 0.0098 8.9349 0.0481 8.9725 ;
		END

		ANTENNAGATEAREA 0.00027817 ;
		ANTENNADIFFAREA 0.00194719 ;
		ANTENNAPARTIALMETALAREA 0.00195671 ;
	END WENB[11]

	PIN WENB[12]
		USE SIGNAL ;
		DIRECTION INPUT ;
		SHAPE ABUTMENT ;
		PORT
			 LAYER M2 ;
			RECT 0.0098 9.7255 0.0481 9.7631 ;
		END

		ANTENNAGATEAREA 0.00027817 ;
		ANTENNADIFFAREA 0.00194719 ;
		ANTENNAPARTIALMETALAREA 0.00195671 ;
	END WENB[12]

	PIN WENB[13]
		USE SIGNAL ;
		DIRECTION INPUT ;
		SHAPE ABUTMENT ;
		PORT
			 LAYER M2 ;
			RECT 0.0098 10.5161 0.0481 10.5537 ;
		END

		ANTENNAGATEAREA 0.00027817 ;
		ANTENNADIFFAREA 0.00194719 ;
		ANTENNAPARTIALMETALAREA 0.00195671 ;
	END WENB[13]

	PIN WENB[14]
		USE SIGNAL ;
		DIRECTION INPUT ;
		SHAPE ABUTMENT ;
		PORT
			 LAYER M2 ;
			RECT 0.0098 11.3067 0.0481 11.3443 ;
		END

		ANTENNAGATEAREA 0.00027817 ;
		ANTENNADIFFAREA 0.00194719 ;
		ANTENNAPARTIALMETALAREA 0.00195671 ;
	END WENB[14]

	PIN WENB[15]
		USE SIGNAL ;
		DIRECTION INPUT ;
		SHAPE ABUTMENT ;
		PORT
			 LAYER M2 ;
			RECT 0.0098 12.0973 0.0481 12.1349 ;
		END

		ANTENNAGATEAREA 0.00027817 ;
		ANTENNADIFFAREA 0.00194719 ;
		ANTENNAPARTIALMETALAREA 0.00195671 ;
	END WENB[15]

	PIN WENB[16]
		USE SIGNAL ;
		DIRECTION INPUT ;
		SHAPE ABUTMENT ;
		PORT
			 LAYER M2 ;
			RECT 0.0098 12.8878 0.0481 12.9255 ;
		END

		ANTENNAGATEAREA 0.00027817 ;
		ANTENNADIFFAREA 0.00194719 ;
		ANTENNAPARTIALMETALAREA 0.00195671 ;
	END WENB[16]

	PIN WENB[17]
		USE SIGNAL ;
		DIRECTION INPUT ;
		SHAPE ABUTMENT ;
		PORT
			 LAYER M2 ;
			RECT 0.0098 13.6784 0.0481 13.7161 ;
		END

		ANTENNAGATEAREA 0.00027817 ;
		ANTENNADIFFAREA 0.00194719 ;
		ANTENNAPARTIALMETALAREA 0.00195671 ;
	END WENB[17]

	PIN WENB[18]
		USE SIGNAL ;
		DIRECTION INPUT ;
		SHAPE ABUTMENT ;
		PORT
			 LAYER M2 ;
			RECT 0.0098 14.469 0.0481 14.5067 ;
		END

		ANTENNAGATEAREA 0.00027817 ;
		ANTENNADIFFAREA 0.00194719 ;
		ANTENNAPARTIALMETALAREA 0.00195671 ;
	END WENB[18]

	PIN WENB[19]
		USE SIGNAL ;
		DIRECTION INPUT ;
		SHAPE ABUTMENT ;
		PORT
			 LAYER M2 ;
			RECT 0.0098 15.2596 0.0481 15.2973 ;
		END

		ANTENNAGATEAREA 0.00027817 ;
		ANTENNADIFFAREA 0.00194719 ;
		ANTENNAPARTIALMETALAREA 0.00195671 ;
	END WENB[19]

	PIN WENB[1]
		USE SIGNAL ;
		DIRECTION INPUT ;
		SHAPE ABUTMENT ;
		PORT
			 LAYER M2 ;
			RECT 0.0098 1.029 0.0481 1.0667 ;
		END

		ANTENNAGATEAREA 0.00027817 ;
		ANTENNADIFFAREA 0.00194719 ;
		ANTENNAPARTIALMETALAREA 0.00195671 ;
	END WENB[1]

	PIN WENB[20]
		USE SIGNAL ;
		DIRECTION INPUT ;
		SHAPE ABUTMENT ;
		PORT
			 LAYER M2 ;
			RECT 0.0098 16.0502 0.0481 16.0878 ;
		END

		ANTENNAGATEAREA 0.00027817 ;
		ANTENNADIFFAREA 0.00194719 ;
		ANTENNAPARTIALMETALAREA 0.00195671 ;
	END WENB[20]

	PIN WENB[21]
		USE SIGNAL ;
		DIRECTION INPUT ;
		SHAPE ABUTMENT ;
		PORT
			 LAYER M2 ;
			RECT 0.0098 16.8408 0.0481 16.8784 ;
		END

		ANTENNAGATEAREA 0.00027817 ;
		ANTENNADIFFAREA 0.00194719 ;
		ANTENNAPARTIALMETALAREA 0.00195671 ;
	END WENB[21]

	PIN WENB[22]
		USE SIGNAL ;
		DIRECTION INPUT ;
		SHAPE ABUTMENT ;
		PORT
			 LAYER M2 ;
			RECT 0.0098 17.6314 0.0481 17.669 ;
		END

		ANTENNAGATEAREA 0.00027817 ;
		ANTENNADIFFAREA 0.00194719 ;
		ANTENNAPARTIALMETALAREA 0.00195671 ;
	END WENB[22]

	PIN WENB[23]
		USE SIGNAL ;
		DIRECTION INPUT ;
		SHAPE ABUTMENT ;
		PORT
			 LAYER M2 ;
			RECT 0.0098 18.422 0.0481 18.4596 ;
		END

		ANTENNAGATEAREA 0.00027817 ;
		ANTENNADIFFAREA 0.00194719 ;
		ANTENNAPARTIALMETALAREA 0.00195671 ;
	END WENB[23]

	PIN WENB[24]
		USE SIGNAL ;
		DIRECTION INPUT ;
		SHAPE ABUTMENT ;
		PORT
			 LAYER M2 ;
			RECT 0.0098 19.2125 0.0481 19.2502 ;
		END

		ANTENNAGATEAREA 0.00027817 ;
		ANTENNADIFFAREA 0.00194719 ;
		ANTENNAPARTIALMETALAREA 0.00195671 ;
	END WENB[24]

	PIN WENB[25]
		USE SIGNAL ;
		DIRECTION INPUT ;
		SHAPE ABUTMENT ;
		PORT
			 LAYER M2 ;
			RECT 0.0098 20.0031 0.0481 20.0408 ;
		END

		ANTENNAGATEAREA 0.00027817 ;
		ANTENNADIFFAREA 0.00194719 ;
		ANTENNAPARTIALMETALAREA 0.00195671 ;
	END WENB[25]

	PIN WENB[26]
		USE SIGNAL ;
		DIRECTION INPUT ;
		SHAPE ABUTMENT ;
		PORT
			 LAYER M2 ;
			RECT 0.0098 20.7937 0.0481 20.8314 ;
		END

		ANTENNAGATEAREA 0.00027817 ;
		ANTENNADIFFAREA 0.00194719 ;
		ANTENNAPARTIALMETALAREA 0.00195671 ;
	END WENB[26]

	PIN WENB[27]
		USE SIGNAL ;
		DIRECTION INPUT ;
		SHAPE ABUTMENT ;
		PORT
			 LAYER M2 ;
			RECT 0.0098 21.5843 0.0481 21.622 ;
		END

		ANTENNAGATEAREA 0.00027817 ;
		ANTENNADIFFAREA 0.00194719 ;
		ANTENNAPARTIALMETALAREA 0.00195671 ;
	END WENB[27]

	PIN WENB[28]
		USE SIGNAL ;
		DIRECTION INPUT ;
		SHAPE ABUTMENT ;
		PORT
			 LAYER M2 ;
			RECT 0.0098 22.3749 0.0481 22.4125 ;
		END

		ANTENNAGATEAREA 0.00027817 ;
		ANTENNADIFFAREA 0.00194719 ;
		ANTENNAPARTIALMETALAREA 0.00195671 ;
	END WENB[28]

	PIN WENB[29]
		USE SIGNAL ;
		DIRECTION INPUT ;
		SHAPE ABUTMENT ;
		PORT
			 LAYER M2 ;
			RECT 0.0098 23.1655 0.0481 23.2031 ;
		END

		ANTENNAGATEAREA 0.00027817 ;
		ANTENNADIFFAREA 0.00194719 ;
		ANTENNAPARTIALMETALAREA 0.00195671 ;
	END WENB[29]

	PIN WENB[2]
		USE SIGNAL ;
		DIRECTION INPUT ;
		SHAPE ABUTMENT ;
		PORT
			 LAYER M2 ;
			RECT 0.0098 1.8196 0.0481 1.8573 ;
		END

		ANTENNAGATEAREA 0.00027817 ;
		ANTENNADIFFAREA 0.00194719 ;
		ANTENNAPARTIALMETALAREA 0.00195671 ;
	END WENB[2]

	PIN WENB[30]
		USE SIGNAL ;
		DIRECTION INPUT ;
		SHAPE ABUTMENT ;
		PORT
			 LAYER M2 ;
			RECT 0.0098 23.9561 0.0481 23.9937 ;
		END

		ANTENNAGATEAREA 0.00027817 ;
		ANTENNADIFFAREA 0.00194719 ;
		ANTENNAPARTIALMETALAREA 0.00195671 ;
	END WENB[30]

	PIN WENB[31]
		USE SIGNAL ;
		DIRECTION INPUT ;
		SHAPE ABUTMENT ;
		PORT
			 LAYER M2 ;
			RECT 0.0098 24.7467 0.0481 24.7843 ;
		END

		ANTENNAGATEAREA 0.00027817 ;
		ANTENNADIFFAREA 0.00194719 ;
		ANTENNAPARTIALMETALAREA 0.00195671 ;
	END WENB[31]

	PIN WENB[32]
		USE SIGNAL ;
		DIRECTION INPUT ;
		SHAPE ABUTMENT ;
		PORT
			 LAYER M2 ;
			RECT 0.0098 25.5373 0.0481 25.5749 ;
		END

		ANTENNAGATEAREA 0.00027817 ;
		ANTENNADIFFAREA 0.00194719 ;
		ANTENNAPARTIALMETALAREA 0.00195671 ;
	END WENB[32]

	PIN WENB[33]
		USE SIGNAL ;
		DIRECTION INPUT ;
		SHAPE ABUTMENT ;
		PORT
			 LAYER M2 ;
			RECT 0.0098 36.0722 0.0481 36.1098 ;
		END

		ANTENNAGATEAREA 0.00027817 ;
		ANTENNADIFFAREA 0.00194719 ;
		ANTENNAPARTIALMETALAREA 0.00195671 ;
	END WENB[33]

	PIN WENB[34]
		USE SIGNAL ;
		DIRECTION INPUT ;
		SHAPE ABUTMENT ;
		PORT
			 LAYER M2 ;
			RECT 0.0098 36.8627 0.0481 36.9004 ;
		END

		ANTENNAGATEAREA 0.00027817 ;
		ANTENNADIFFAREA 0.00194719 ;
		ANTENNAPARTIALMETALAREA 0.00195671 ;
	END WENB[34]

	PIN WENB[35]
		USE SIGNAL ;
		DIRECTION INPUT ;
		SHAPE ABUTMENT ;
		PORT
			 LAYER M2 ;
			RECT 0.0098 37.6533 0.0481 37.691 ;
		END

		ANTENNAGATEAREA 0.00027817 ;
		ANTENNADIFFAREA 0.00194719 ;
		ANTENNAPARTIALMETALAREA 0.00195671 ;
	END WENB[35]

	PIN WENB[36]
		USE SIGNAL ;
		DIRECTION INPUT ;
		SHAPE ABUTMENT ;
		PORT
			 LAYER M2 ;
			RECT 0.0098 38.4439 0.0481 38.4816 ;
		END

		ANTENNAGATEAREA 0.00027817 ;
		ANTENNADIFFAREA 0.00194719 ;
		ANTENNAPARTIALMETALAREA 0.00195671 ;
	END WENB[36]

	PIN WENB[37]
		USE SIGNAL ;
		DIRECTION INPUT ;
		SHAPE ABUTMENT ;
		PORT
			 LAYER M2 ;
			RECT 0.0098 39.2345 0.0481 39.2722 ;
		END

		ANTENNAGATEAREA 0.00027817 ;
		ANTENNADIFFAREA 0.00194719 ;
		ANTENNAPARTIALMETALAREA 0.00195671 ;
	END WENB[37]

	PIN WENB[38]
		USE SIGNAL ;
		DIRECTION INPUT ;
		SHAPE ABUTMENT ;
		PORT
			 LAYER M2 ;
			RECT 0.0098 40.0251 0.0481 40.0627 ;
		END

		ANTENNAGATEAREA 0.00027817 ;
		ANTENNADIFFAREA 0.00194719 ;
		ANTENNAPARTIALMETALAREA 0.00195671 ;
	END WENB[38]

	PIN WENB[39]
		USE SIGNAL ;
		DIRECTION INPUT ;
		SHAPE ABUTMENT ;
		PORT
			 LAYER M2 ;
			RECT 0.0098 40.8157 0.0481 40.8533 ;
		END

		ANTENNAGATEAREA 0.00027817 ;
		ANTENNADIFFAREA 0.00194719 ;
		ANTENNAPARTIALMETALAREA 0.00195671 ;
	END WENB[39]

	PIN WENB[3]
		USE SIGNAL ;
		DIRECTION INPUT ;
		SHAPE ABUTMENT ;
		PORT
			 LAYER M2 ;
			RECT 0.0098 2.6102 0.0481 2.6478 ;
		END

		ANTENNAGATEAREA 0.00027817 ;
		ANTENNADIFFAREA 0.00194719 ;
		ANTENNAPARTIALMETALAREA 0.00195671 ;
	END WENB[3]

	PIN WENB[40]
		USE SIGNAL ;
		DIRECTION INPUT ;
		SHAPE ABUTMENT ;
		PORT
			 LAYER M2 ;
			RECT 0.0098 41.6063 0.0481 41.6439 ;
		END

		ANTENNAGATEAREA 0.00027817 ;
		ANTENNADIFFAREA 0.00194719 ;
		ANTENNAPARTIALMETALAREA 0.00195671 ;
	END WENB[40]

	PIN WENB[41]
		USE SIGNAL ;
		DIRECTION INPUT ;
		SHAPE ABUTMENT ;
		PORT
			 LAYER M2 ;
			RECT 0.0098 42.3969 0.0481 42.4345 ;
		END

		ANTENNAGATEAREA 0.00027817 ;
		ANTENNADIFFAREA 0.00194719 ;
		ANTENNAPARTIALMETALAREA 0.00195671 ;
	END WENB[41]

	PIN WENB[42]
		USE SIGNAL ;
		DIRECTION INPUT ;
		SHAPE ABUTMENT ;
		PORT
			 LAYER M2 ;
			RECT 0.0098 43.1875 0.0481 43.2251 ;
		END

		ANTENNAGATEAREA 0.00027817 ;
		ANTENNADIFFAREA 0.00194719 ;
		ANTENNAPARTIALMETALAREA 0.00195671 ;
	END WENB[42]

	PIN WENB[43]
		USE SIGNAL ;
		DIRECTION INPUT ;
		SHAPE ABUTMENT ;
		PORT
			 LAYER M2 ;
			RECT 0.0098 43.978 0.0481 44.0157 ;
		END

		ANTENNAGATEAREA 0.00027817 ;
		ANTENNADIFFAREA 0.00194719 ;
		ANTENNAPARTIALMETALAREA 0.00195671 ;
	END WENB[43]

	PIN WENB[44]
		USE SIGNAL ;
		DIRECTION INPUT ;
		SHAPE ABUTMENT ;
		PORT
			 LAYER M2 ;
			RECT 0.0098 44.7686 0.0481 44.8063 ;
		END

		ANTENNAGATEAREA 0.00027817 ;
		ANTENNADIFFAREA 0.00194719 ;
		ANTENNAPARTIALMETALAREA 0.00195671 ;
	END WENB[44]

	PIN WENB[45]
		USE SIGNAL ;
		DIRECTION INPUT ;
		SHAPE ABUTMENT ;
		PORT
			 LAYER M2 ;
			RECT 0.0098 45.5592 0.0481 45.5969 ;
		END

		ANTENNAGATEAREA 0.00027817 ;
		ANTENNADIFFAREA 0.00194719 ;
		ANTENNAPARTIALMETALAREA 0.00195671 ;
	END WENB[45]

	PIN WENB[46]
		USE SIGNAL ;
		DIRECTION INPUT ;
		SHAPE ABUTMENT ;
		PORT
			 LAYER M2 ;
			RECT 0.0098 46.3498 0.0481 46.3875 ;
		END

		ANTENNAGATEAREA 0.00027817 ;
		ANTENNADIFFAREA 0.00194719 ;
		ANTENNAPARTIALMETALAREA 0.00195671 ;
	END WENB[46]

	PIN WENB[47]
		USE SIGNAL ;
		DIRECTION INPUT ;
		SHAPE ABUTMENT ;
		PORT
			 LAYER M2 ;
			RECT 0.0098 47.1404 0.0481 47.178 ;
		END

		ANTENNAGATEAREA 0.00027817 ;
		ANTENNADIFFAREA 0.00194719 ;
		ANTENNAPARTIALMETALAREA 0.00195671 ;
	END WENB[47]

	PIN WENB[48]
		USE SIGNAL ;
		DIRECTION INPUT ;
		SHAPE ABUTMENT ;
		PORT
			 LAYER M2 ;
			RECT 0.0098 47.931 0.0481 47.9686 ;
		END

		ANTENNAGATEAREA 0.00027817 ;
		ANTENNADIFFAREA 0.00194719 ;
		ANTENNAPARTIALMETALAREA 0.00195671 ;
	END WENB[48]

	PIN WENB[49]
		USE SIGNAL ;
		DIRECTION INPUT ;
		SHAPE ABUTMENT ;
		PORT
			 LAYER M2 ;
			RECT 0.0098 48.7216 0.0481 48.7592 ;
		END

		ANTENNAGATEAREA 0.00027817 ;
		ANTENNADIFFAREA 0.00194719 ;
		ANTENNAPARTIALMETALAREA 0.00195671 ;
	END WENB[49]

	PIN WENB[4]
		USE SIGNAL ;
		DIRECTION INPUT ;
		SHAPE ABUTMENT ;
		PORT
			 LAYER M2 ;
			RECT 0.0098 3.4008 0.0481 3.4384 ;
		END

		ANTENNAGATEAREA 0.00027817 ;
		ANTENNADIFFAREA 0.00194719 ;
		ANTENNAPARTIALMETALAREA 0.00195671 ;
	END WENB[4]

	PIN WENB[50]
		USE SIGNAL ;
		DIRECTION INPUT ;
		SHAPE ABUTMENT ;
		PORT
			 LAYER M2 ;
			RECT 0.0098 49.5122 0.0481 49.5498 ;
		END

		ANTENNAGATEAREA 0.00027817 ;
		ANTENNADIFFAREA 0.00194719 ;
		ANTENNAPARTIALMETALAREA 0.00195671 ;
	END WENB[50]

	PIN WENB[51]
		USE SIGNAL ;
		DIRECTION INPUT ;
		SHAPE ABUTMENT ;
		PORT
			 LAYER M2 ;
			RECT 0.0098 50.3027 0.0481 50.3404 ;
		END

		ANTENNAGATEAREA 0.00027817 ;
		ANTENNADIFFAREA 0.00194719 ;
		ANTENNAPARTIALMETALAREA 0.00195671 ;
	END WENB[51]

	PIN WENB[52]
		USE SIGNAL ;
		DIRECTION INPUT ;
		SHAPE ABUTMENT ;
		PORT
			 LAYER M2 ;
			RECT 0.0098 51.0933 0.0481 51.131 ;
		END

		ANTENNAGATEAREA 0.00027817 ;
		ANTENNADIFFAREA 0.00194719 ;
		ANTENNAPARTIALMETALAREA 0.00195671 ;
	END WENB[52]

	PIN WENB[53]
		USE SIGNAL ;
		DIRECTION INPUT ;
		SHAPE ABUTMENT ;
		PORT
			 LAYER M2 ;
			RECT 0.0098 51.8839 0.0481 51.9216 ;
		END

		ANTENNAGATEAREA 0.00027817 ;
		ANTENNADIFFAREA 0.00194719 ;
		ANTENNAPARTIALMETALAREA 0.00195671 ;
	END WENB[53]

	PIN WENB[54]
		USE SIGNAL ;
		DIRECTION INPUT ;
		SHAPE ABUTMENT ;
		PORT
			 LAYER M2 ;
			RECT 0.0098 52.6745 0.0481 52.7122 ;
		END

		ANTENNAGATEAREA 0.00027817 ;
		ANTENNADIFFAREA 0.00194719 ;
		ANTENNAPARTIALMETALAREA 0.00195671 ;
	END WENB[54]

	PIN WENB[55]
		USE SIGNAL ;
		DIRECTION INPUT ;
		SHAPE ABUTMENT ;
		PORT
			 LAYER M2 ;
			RECT 0.0098 53.4651 0.0481 53.5027 ;
		END

		ANTENNAGATEAREA 0.00027817 ;
		ANTENNADIFFAREA 0.00194719 ;
		ANTENNAPARTIALMETALAREA 0.00195671 ;
	END WENB[55]

	PIN WENB[56]
		USE SIGNAL ;
		DIRECTION INPUT ;
		SHAPE ABUTMENT ;
		PORT
			 LAYER M2 ;
			RECT 0.0098 54.2557 0.0481 54.2933 ;
		END

		ANTENNAGATEAREA 0.00027817 ;
		ANTENNADIFFAREA 0.00194719 ;
		ANTENNAPARTIALMETALAREA 0.00195671 ;
	END WENB[56]

	PIN WENB[57]
		USE SIGNAL ;
		DIRECTION INPUT ;
		SHAPE ABUTMENT ;
		PORT
			 LAYER M2 ;
			RECT 0.0098 55.0463 0.0481 55.0839 ;
		END

		ANTENNAGATEAREA 0.00027817 ;
		ANTENNADIFFAREA 0.00194719 ;
		ANTENNAPARTIALMETALAREA 0.00195671 ;
	END WENB[57]

	PIN WENB[58]
		USE SIGNAL ;
		DIRECTION INPUT ;
		SHAPE ABUTMENT ;
		PORT
			 LAYER M2 ;
			RECT 0.0098 55.8369 0.0481 55.8745 ;
		END

		ANTENNAGATEAREA 0.00027817 ;
		ANTENNADIFFAREA 0.00194719 ;
		ANTENNAPARTIALMETALAREA 0.00195671 ;
	END WENB[58]

	PIN WENB[59]
		USE SIGNAL ;
		DIRECTION INPUT ;
		SHAPE ABUTMENT ;
		PORT
			 LAYER M2 ;
			RECT 0.0098 56.6275 0.0481 56.6651 ;
		END

		ANTENNAGATEAREA 0.00027817 ;
		ANTENNADIFFAREA 0.00194719 ;
		ANTENNAPARTIALMETALAREA 0.00195671 ;
	END WENB[59]

	PIN WENB[5]
		USE SIGNAL ;
		DIRECTION INPUT ;
		SHAPE ABUTMENT ;
		PORT
			 LAYER M2 ;
			RECT 0.0098 4.1914 0.0481 4.229 ;
		END

		ANTENNAGATEAREA 0.00027817 ;
		ANTENNADIFFAREA 0.00194719 ;
		ANTENNAPARTIALMETALAREA 0.00195671 ;
	END WENB[5]

	PIN WENB[60]
		USE SIGNAL ;
		DIRECTION INPUT ;
		SHAPE ABUTMENT ;
		PORT
			 LAYER M2 ;
			RECT 0.0098 57.418 0.0481 57.4557 ;
		END

		ANTENNAGATEAREA 0.00027817 ;
		ANTENNADIFFAREA 0.00194719 ;
		ANTENNAPARTIALMETALAREA 0.00195671 ;
	END WENB[60]

	PIN WENB[61]
		USE SIGNAL ;
		DIRECTION INPUT ;
		SHAPE ABUTMENT ;
		PORT
			 LAYER M2 ;
			RECT 0.0098 58.2086 0.0481 58.2463 ;
		END

		ANTENNAGATEAREA 0.00027817 ;
		ANTENNADIFFAREA 0.00194719 ;
		ANTENNAPARTIALMETALAREA 0.00195671 ;
	END WENB[61]

	PIN WENB[62]
		USE SIGNAL ;
		DIRECTION INPUT ;
		SHAPE ABUTMENT ;
		PORT
			 LAYER M2 ;
			RECT 0.0098 58.9992 0.0481 59.0369 ;
		END

		ANTENNAGATEAREA 0.00027817 ;
		ANTENNADIFFAREA 0.00194719 ;
		ANTENNAPARTIALMETALAREA 0.00195671 ;
	END WENB[62]

	PIN WENB[63]
		USE SIGNAL ;
		DIRECTION INPUT ;
		SHAPE ABUTMENT ;
		PORT
			 LAYER M2 ;
			RECT 0.0098 59.7898 0.0481 59.8275 ;
		END

		ANTENNAGATEAREA 0.00027817 ;
		ANTENNADIFFAREA 0.00194719 ;
		ANTENNAPARTIALMETALAREA 0.00195671 ;
	END WENB[63]

	PIN WENB[64]
		USE SIGNAL ;
		DIRECTION INPUT ;
		SHAPE ABUTMENT ;
		PORT
			 LAYER M2 ;
			RECT 0.0098 60.5804 0.0481 60.618 ;
		END

		ANTENNAGATEAREA 0.00027817 ;
		ANTENNADIFFAREA 0.00194719 ;
		ANTENNAPARTIALMETALAREA 0.00195671 ;
	END WENB[64]

	PIN WENB[65]
		USE SIGNAL ;
		DIRECTION INPUT ;
		SHAPE ABUTMENT ;
		PORT
			 LAYER M2 ;
			RECT 0.0098 61.371 0.0481 61.4086 ;
		END

		ANTENNAGATEAREA 0.00027817 ;
		ANTENNADIFFAREA 0.00194719 ;
		ANTENNAPARTIALMETALAREA 0.00195671 ;
	END WENB[65]

	PIN WENB[6]
		USE SIGNAL ;
		DIRECTION INPUT ;
		SHAPE ABUTMENT ;
		PORT
			 LAYER M2 ;
			RECT 0.0098 4.982 0.0481 5.0196 ;
		END

		ANTENNAGATEAREA 0.00027817 ;
		ANTENNADIFFAREA 0.00194719 ;
		ANTENNAPARTIALMETALAREA 0.00195671 ;
	END WENB[6]

	PIN WENB[7]
		USE SIGNAL ;
		DIRECTION INPUT ;
		SHAPE ABUTMENT ;
		PORT
			 LAYER M2 ;
			RECT 0.0098 5.7725 0.0481 5.8102 ;
		END

		ANTENNAGATEAREA 0.00027817 ;
		ANTENNADIFFAREA 0.00194719 ;
		ANTENNAPARTIALMETALAREA 0.00195671 ;
	END WENB[7]

	PIN WENB[8]
		USE SIGNAL ;
		DIRECTION INPUT ;
		SHAPE ABUTMENT ;
		PORT
			 LAYER M2 ;
			RECT 0.0098 6.5631 0.0481 6.6008 ;
		END

		ANTENNAGATEAREA 0.00027817 ;
		ANTENNADIFFAREA 0.00194719 ;
		ANTENNAPARTIALMETALAREA 0.00195671 ;
	END WENB[8]

	PIN WENB[9]
		USE SIGNAL ;
		DIRECTION INPUT ;
		SHAPE ABUTMENT ;
		PORT
			 LAYER M2 ;
			RECT 0.0098 7.3537 0.0481 7.3914 ;
		END

		ANTENNAGATEAREA 0.00027817 ;
		ANTENNADIFFAREA 0.00194719 ;
		ANTENNAPARTIALMETALAREA 0.00195671 ;
	END WENB[9]

	PIN WENYA[0]
		USE SIGNAL ;
		DIRECTION OUTPUT ;
		SHAPE ABUTMENT ;
		PORT
			 LAYER M2 ;
			RECT 0.0098 0.5396 0.0481 0.5773 ;
			 LAYER M3 ;
			RECT 0.0098 0.5396 0.0481 0.64 ;
			 LAYER V2 ;
			RECT 0.0215 0.5525 0.0364 0.5651 ;
		END

		ANTENNADIFFAREA 0.00194719 ;
		ANTENNAPARTIALMETALAREA 0.00195671 ;
	END WENYA[0]

	PIN WENYA[10]
		USE SIGNAL ;
		DIRECTION OUTPUT ;
		SHAPE ABUTMENT ;
		PORT
			 LAYER M2 ;
			RECT 0.0098 8.4455 0.0481 8.4831 ;
			 LAYER M3 ;
			RECT 0.0098 8.4455 0.0481 8.5459 ;
			 LAYER V2 ;
			RECT 0.0215 8.4584 0.0364 8.471 ;
		END

		ANTENNADIFFAREA 0.00194719 ;
		ANTENNAPARTIALMETALAREA 0.00195671 ;
	END WENYA[10]

	PIN WENYA[11]
		USE SIGNAL ;
		DIRECTION OUTPUT ;
		SHAPE ABUTMENT ;
		PORT
			 LAYER M2 ;
			RECT 0.0098 9.2361 0.0481 9.2737 ;
			 LAYER M3 ;
			RECT 0.0098 9.2361 0.0481 9.3365 ;
			 LAYER V2 ;
			RECT 0.0215 9.249 0.0364 9.2616 ;
		END

		ANTENNADIFFAREA 0.00194719 ;
		ANTENNAPARTIALMETALAREA 0.00195671 ;
	END WENYA[11]

	PIN WENYA[12]
		USE SIGNAL ;
		DIRECTION OUTPUT ;
		SHAPE ABUTMENT ;
		PORT
			 LAYER M2 ;
			RECT 0.0098 10.0267 0.0481 10.0643 ;
			 LAYER M3 ;
			RECT 0.0098 10.0267 0.0481 10.1271 ;
			 LAYER V2 ;
			RECT 0.0215 10.0396 0.0364 10.0522 ;
		END

		ANTENNADIFFAREA 0.00194719 ;
		ANTENNAPARTIALMETALAREA 0.00195671 ;
	END WENYA[12]

	PIN WENYA[13]
		USE SIGNAL ;
		DIRECTION OUTPUT ;
		SHAPE ABUTMENT ;
		PORT
			 LAYER M2 ;
			RECT 0.0098 10.8173 0.0481 10.8549 ;
			 LAYER M3 ;
			RECT 0.0098 10.8173 0.0481 10.9176 ;
			 LAYER V2 ;
			RECT 0.0215 10.8302 0.0364 10.8427 ;
		END

		ANTENNADIFFAREA 0.00194719 ;
		ANTENNAPARTIALMETALAREA 0.00195671 ;
	END WENYA[13]

	PIN WENYA[14]
		USE SIGNAL ;
		DIRECTION OUTPUT ;
		SHAPE ABUTMENT ;
		PORT
			 LAYER M2 ;
			RECT 0.0098 11.6078 0.0481 11.6455 ;
			 LAYER M3 ;
			RECT 0.0098 11.6078 0.0481 11.7082 ;
			 LAYER V2 ;
			RECT 0.0215 11.6208 0.0364 11.6333 ;
		END

		ANTENNADIFFAREA 0.00194719 ;
		ANTENNAPARTIALMETALAREA 0.00195671 ;
	END WENYA[14]

	PIN WENYA[15]
		USE SIGNAL ;
		DIRECTION OUTPUT ;
		SHAPE ABUTMENT ;
		PORT
			 LAYER M2 ;
			RECT 0.0098 12.3984 0.0481 12.4361 ;
			 LAYER M3 ;
			RECT 0.0098 12.3984 0.0481 12.4988 ;
			 LAYER V2 ;
			RECT 0.0215 12.4114 0.0364 12.4239 ;
		END

		ANTENNADIFFAREA 0.00194719 ;
		ANTENNAPARTIALMETALAREA 0.00195671 ;
	END WENYA[15]

	PIN WENYA[16]
		USE SIGNAL ;
		DIRECTION OUTPUT ;
		SHAPE ABUTMENT ;
		PORT
			 LAYER M2 ;
			RECT 0.0098 13.189 0.0481 13.2267 ;
			 LAYER M3 ;
			RECT 0.0098 13.189 0.0481 13.2894 ;
			 LAYER V2 ;
			RECT 0.0215 13.202 0.0364 13.2145 ;
		END

		ANTENNADIFFAREA 0.00194719 ;
		ANTENNAPARTIALMETALAREA 0.00195671 ;
	END WENYA[16]

	PIN WENYA[17]
		USE SIGNAL ;
		DIRECTION OUTPUT ;
		SHAPE ABUTMENT ;
		PORT
			 LAYER M2 ;
			RECT 0.0098 13.9796 0.0481 14.0173 ;
			 LAYER M3 ;
			RECT 0.0098 13.9796 0.0481 14.08 ;
			 LAYER V2 ;
			RECT 0.0215 13.9925 0.0364 14.0051 ;
		END

		ANTENNADIFFAREA 0.00194719 ;
		ANTENNAPARTIALMETALAREA 0.00195671 ;
	END WENYA[17]

	PIN WENYA[18]
		USE SIGNAL ;
		DIRECTION OUTPUT ;
		SHAPE ABUTMENT ;
		PORT
			 LAYER M2 ;
			RECT 0.0098 14.7702 0.0481 14.8078 ;
			 LAYER M3 ;
			RECT 0.0098 14.7702 0.0481 14.8706 ;
			 LAYER V2 ;
			RECT 0.0215 14.7831 0.0364 14.7957 ;
		END

		ANTENNADIFFAREA 0.00194719 ;
		ANTENNAPARTIALMETALAREA 0.00195671 ;
	END WENYA[18]

	PIN WENYA[19]
		USE SIGNAL ;
		DIRECTION OUTPUT ;
		SHAPE ABUTMENT ;
		PORT
			 LAYER M2 ;
			RECT 0.0098 15.5608 0.0481 15.5984 ;
			 LAYER M3 ;
			RECT 0.0098 15.5608 0.0481 15.6612 ;
			 LAYER V2 ;
			RECT 0.0215 15.5737 0.0364 15.5863 ;
		END

		ANTENNADIFFAREA 0.00194719 ;
		ANTENNAPARTIALMETALAREA 0.00195671 ;
	END WENYA[19]

	PIN WENYA[1]
		USE SIGNAL ;
		DIRECTION OUTPUT ;
		SHAPE ABUTMENT ;
		PORT
			 LAYER M2 ;
			RECT 0.0098 1.3302 0.0481 1.3678 ;
			 LAYER M3 ;
			RECT 0.0098 1.3302 0.0481 1.4306 ;
			 LAYER V2 ;
			RECT 0.0215 1.3431 0.0364 1.3557 ;
		END

		ANTENNADIFFAREA 0.00194719 ;
		ANTENNAPARTIALMETALAREA 0.00195671 ;
	END WENYA[1]

	PIN WENYA[20]
		USE SIGNAL ;
		DIRECTION OUTPUT ;
		SHAPE ABUTMENT ;
		PORT
			 LAYER M2 ;
			RECT 0.0098 16.3514 0.0481 16.389 ;
			 LAYER M3 ;
			RECT 0.0098 16.3514 0.0481 16.4518 ;
			 LAYER V2 ;
			RECT 0.0215 16.3643 0.0364 16.3769 ;
		END

		ANTENNADIFFAREA 0.00194719 ;
		ANTENNAPARTIALMETALAREA 0.00195671 ;
	END WENYA[20]

	PIN WENYA[21]
		USE SIGNAL ;
		DIRECTION OUTPUT ;
		SHAPE ABUTMENT ;
		PORT
			 LAYER M2 ;
			RECT 0.0098 17.142 0.0481 17.1796 ;
			 LAYER M3 ;
			RECT 0.0098 17.142 0.0481 17.2424 ;
			 LAYER V2 ;
			RECT 0.0215 17.1549 0.0364 17.1675 ;
		END

		ANTENNADIFFAREA 0.00194719 ;
		ANTENNAPARTIALMETALAREA 0.00195671 ;
	END WENYA[21]

	PIN WENYA[22]
		USE SIGNAL ;
		DIRECTION OUTPUT ;
		SHAPE ABUTMENT ;
		PORT
			 LAYER M2 ;
			RECT 0.0098 17.9325 0.0481 17.9702 ;
			 LAYER M3 ;
			RECT 0.0098 17.9325 0.0481 18.0329 ;
			 LAYER V2 ;
			RECT 0.0215 17.9455 0.0364 17.958 ;
		END

		ANTENNADIFFAREA 0.00194719 ;
		ANTENNAPARTIALMETALAREA 0.00195671 ;
	END WENYA[22]

	PIN WENYA[23]
		USE SIGNAL ;
		DIRECTION OUTPUT ;
		SHAPE ABUTMENT ;
		PORT
			 LAYER M2 ;
			RECT 0.0098 18.7231 0.0481 18.7608 ;
			 LAYER M3 ;
			RECT 0.0098 18.7231 0.0481 18.8235 ;
			 LAYER V2 ;
			RECT 0.0215 18.7361 0.0364 18.7486 ;
		END

		ANTENNADIFFAREA 0.00194719 ;
		ANTENNAPARTIALMETALAREA 0.00195671 ;
	END WENYA[23]

	PIN WENYA[24]
		USE SIGNAL ;
		DIRECTION OUTPUT ;
		SHAPE ABUTMENT ;
		PORT
			 LAYER M2 ;
			RECT 0.0098 19.5137 0.0481 19.5514 ;
			 LAYER M3 ;
			RECT 0.0098 19.5137 0.0481 19.6141 ;
			 LAYER V2 ;
			RECT 0.0215 19.5267 0.0364 19.5392 ;
		END

		ANTENNADIFFAREA 0.00194719 ;
		ANTENNAPARTIALMETALAREA 0.00195671 ;
	END WENYA[24]

	PIN WENYA[25]
		USE SIGNAL ;
		DIRECTION OUTPUT ;
		SHAPE ABUTMENT ;
		PORT
			 LAYER M2 ;
			RECT 0.0098 20.3043 0.0481 20.342 ;
			 LAYER M3 ;
			RECT 0.0098 20.3043 0.0481 20.4047 ;
			 LAYER V2 ;
			RECT 0.0215 20.3173 0.0364 20.3298 ;
		END

		ANTENNADIFFAREA 0.00194719 ;
		ANTENNAPARTIALMETALAREA 0.00195671 ;
	END WENYA[25]

	PIN WENYA[26]
		USE SIGNAL ;
		DIRECTION OUTPUT ;
		SHAPE ABUTMENT ;
		PORT
			 LAYER M2 ;
			RECT 0.0098 21.0949 0.0481 21.1325 ;
			 LAYER M3 ;
			RECT 0.0098 21.0949 0.0481 21.1953 ;
			 LAYER V2 ;
			RECT 0.0215 21.1078 0.0364 21.1204 ;
		END

		ANTENNADIFFAREA 0.00194719 ;
		ANTENNAPARTIALMETALAREA 0.00195671 ;
	END WENYA[26]

	PIN WENYA[27]
		USE SIGNAL ;
		DIRECTION OUTPUT ;
		SHAPE ABUTMENT ;
		PORT
			 LAYER M2 ;
			RECT 0.0098 21.8855 0.0481 21.9231 ;
			 LAYER M3 ;
			RECT 0.0098 21.8855 0.0481 21.9859 ;
			 LAYER V2 ;
			RECT 0.0215 21.8984 0.0364 21.911 ;
		END

		ANTENNADIFFAREA 0.00194719 ;
		ANTENNAPARTIALMETALAREA 0.00195671 ;
	END WENYA[27]

	PIN WENYA[28]
		USE SIGNAL ;
		DIRECTION OUTPUT ;
		SHAPE ABUTMENT ;
		PORT
			 LAYER M2 ;
			RECT 0.0098 22.6761 0.0481 22.7137 ;
			 LAYER M3 ;
			RECT 0.0098 22.6761 0.0481 22.7765 ;
			 LAYER V2 ;
			RECT 0.0215 22.689 0.0364 22.7016 ;
		END

		ANTENNADIFFAREA 0.00194719 ;
		ANTENNAPARTIALMETALAREA 0.00195671 ;
	END WENYA[28]

	PIN WENYA[29]
		USE SIGNAL ;
		DIRECTION OUTPUT ;
		SHAPE ABUTMENT ;
		PORT
			 LAYER M2 ;
			RECT 0.0098 23.4667 0.0481 23.5043 ;
			 LAYER M3 ;
			RECT 0.0098 23.4667 0.0481 23.5671 ;
			 LAYER V2 ;
			RECT 0.0215 23.4796 0.0364 23.4922 ;
		END

		ANTENNADIFFAREA 0.00194719 ;
		ANTENNAPARTIALMETALAREA 0.00195671 ;
	END WENYA[29]

	PIN WENYA[2]
		USE SIGNAL ;
		DIRECTION OUTPUT ;
		SHAPE ABUTMENT ;
		PORT
			 LAYER M2 ;
			RECT 0.0098 2.1208 0.0481 2.1584 ;
			 LAYER M3 ;
			RECT 0.0098 2.1208 0.0481 2.2212 ;
			 LAYER V2 ;
			RECT 0.0215 2.1337 0.0364 2.1463 ;
		END

		ANTENNADIFFAREA 0.00194719 ;
		ANTENNAPARTIALMETALAREA 0.00195671 ;
	END WENYA[2]

	PIN WENYA[30]
		USE SIGNAL ;
		DIRECTION OUTPUT ;
		SHAPE ABUTMENT ;
		PORT
			 LAYER M2 ;
			RECT 0.0098 24.2573 0.0481 24.2949 ;
			 LAYER M3 ;
			RECT 0.0098 24.2573 0.0481 24.3576 ;
			 LAYER V2 ;
			RECT 0.0215 24.2702 0.0364 24.2827 ;
		END

		ANTENNADIFFAREA 0.00194719 ;
		ANTENNAPARTIALMETALAREA 0.00195671 ;
	END WENYA[30]

	PIN WENYA[31]
		USE SIGNAL ;
		DIRECTION OUTPUT ;
		SHAPE ABUTMENT ;
		PORT
			 LAYER M2 ;
			RECT 0.0098 25.0478 0.0481 25.0855 ;
			 LAYER M3 ;
			RECT 0.0098 25.0478 0.0481 25.1482 ;
			 LAYER V2 ;
			RECT 0.0215 25.0608 0.0364 25.0733 ;
		END

		ANTENNADIFFAREA 0.00194719 ;
		ANTENNAPARTIALMETALAREA 0.00195671 ;
	END WENYA[31]

	PIN WENYA[32]
		USE SIGNAL ;
		DIRECTION OUTPUT ;
		SHAPE ABUTMENT ;
		PORT
			 LAYER M2 ;
			RECT 0.0098 25.8384 0.0481 25.8761 ;
			 LAYER M3 ;
			RECT 0.0098 25.8384 0.0481 25.9388 ;
			 LAYER V2 ;
			RECT 0.0215 25.8514 0.0364 25.8639 ;
		END

		ANTENNADIFFAREA 0.00194719 ;
		ANTENNAPARTIALMETALAREA 0.00195671 ;
	END WENYA[32]

	PIN WENYA[33]
		USE SIGNAL ;
		DIRECTION OUTPUT ;
		SHAPE ABUTMENT ;
		PORT
			 LAYER M2 ;
			RECT 0.0098 35.771 0.0481 35.8086 ;
			 LAYER M3 ;
			RECT 0.0098 35.7082 0.0481 35.8086 ;
			 LAYER V2 ;
			RECT 0.0215 35.7831 0.0364 35.7957 ;
		END

		ANTENNADIFFAREA 0.00194719 ;
		ANTENNAPARTIALMETALAREA 0.00195671 ;
	END WENYA[33]

	PIN WENYA[34]
		USE SIGNAL ;
		DIRECTION OUTPUT ;
		SHAPE ABUTMENT ;
		PORT
			 LAYER M2 ;
			RECT 0.0098 36.5616 0.0481 36.5992 ;
			 LAYER M3 ;
			RECT 0.0098 36.4988 0.0481 36.5992 ;
			 LAYER V2 ;
			RECT 0.0215 36.5737 0.0364 36.5863 ;
		END

		ANTENNADIFFAREA 0.00194719 ;
		ANTENNAPARTIALMETALAREA 0.00195671 ;
	END WENYA[34]

	PIN WENYA[35]
		USE SIGNAL ;
		DIRECTION OUTPUT ;
		SHAPE ABUTMENT ;
		PORT
			 LAYER M2 ;
			RECT 0.0098 37.3522 0.0481 37.3898 ;
			 LAYER M3 ;
			RECT 0.0098 37.2894 0.0481 37.3898 ;
			 LAYER V2 ;
			RECT 0.0215 37.3643 0.0364 37.3769 ;
		END

		ANTENNADIFFAREA 0.00194719 ;
		ANTENNAPARTIALMETALAREA 0.00195671 ;
	END WENYA[35]

	PIN WENYA[36]
		USE SIGNAL ;
		DIRECTION OUTPUT ;
		SHAPE ABUTMENT ;
		PORT
			 LAYER M2 ;
			RECT 0.0098 38.1427 0.0481 38.1804 ;
			 LAYER M3 ;
			RECT 0.0098 38.08 0.0481 38.1804 ;
			 LAYER V2 ;
			RECT 0.0215 38.1549 0.0364 38.1675 ;
		END

		ANTENNADIFFAREA 0.00194719 ;
		ANTENNAPARTIALMETALAREA 0.00195671 ;
	END WENYA[36]

	PIN WENYA[37]
		USE SIGNAL ;
		DIRECTION OUTPUT ;
		SHAPE ABUTMENT ;
		PORT
			 LAYER M2 ;
			RECT 0.0098 38.9333 0.0481 38.971 ;
			 LAYER M3 ;
			RECT 0.0098 38.8706 0.0481 38.971 ;
			 LAYER V2 ;
			RECT 0.0215 38.9455 0.0364 38.958 ;
		END

		ANTENNADIFFAREA 0.00194719 ;
		ANTENNAPARTIALMETALAREA 0.00195671 ;
	END WENYA[37]

	PIN WENYA[38]
		USE SIGNAL ;
		DIRECTION OUTPUT ;
		SHAPE ABUTMENT ;
		PORT
			 LAYER M2 ;
			RECT 0.0098 39.7239 0.0481 39.7616 ;
			 LAYER M3 ;
			RECT 0.0098 39.6612 0.0481 39.7616 ;
			 LAYER V2 ;
			RECT 0.0215 39.7361 0.0364 39.7486 ;
		END

		ANTENNADIFFAREA 0.00194719 ;
		ANTENNAPARTIALMETALAREA 0.00195671 ;
	END WENYA[38]

	PIN WENYA[39]
		USE SIGNAL ;
		DIRECTION OUTPUT ;
		SHAPE ABUTMENT ;
		PORT
			 LAYER M2 ;
			RECT 0.0098 40.5145 0.0481 40.5522 ;
			 LAYER M3 ;
			RECT 0.0098 40.4518 0.0481 40.5522 ;
			 LAYER V2 ;
			RECT 0.0215 40.5267 0.0364 40.5392 ;
		END

		ANTENNADIFFAREA 0.00194719 ;
		ANTENNAPARTIALMETALAREA 0.00195671 ;
	END WENYA[39]

	PIN WENYA[3]
		USE SIGNAL ;
		DIRECTION OUTPUT ;
		SHAPE ABUTMENT ;
		PORT
			 LAYER M2 ;
			RECT 0.0098 2.9114 0.0481 2.949 ;
			 LAYER M3 ;
			RECT 0.0098 2.9114 0.0481 3.0118 ;
			 LAYER V2 ;
			RECT 0.0215 2.9243 0.0364 2.9369 ;
		END

		ANTENNADIFFAREA 0.00194719 ;
		ANTENNAPARTIALMETALAREA 0.00195671 ;
	END WENYA[3]

	PIN WENYA[40]
		USE SIGNAL ;
		DIRECTION OUTPUT ;
		SHAPE ABUTMENT ;
		PORT
			 LAYER M2 ;
			RECT 0.0098 41.3051 0.0481 41.3427 ;
			 LAYER M3 ;
			RECT 0.0098 41.2424 0.0481 41.3427 ;
			 LAYER V2 ;
			RECT 0.0215 41.3173 0.0364 41.3298 ;
		END

		ANTENNADIFFAREA 0.00194719 ;
		ANTENNAPARTIALMETALAREA 0.00195671 ;
	END WENYA[40]

	PIN WENYA[41]
		USE SIGNAL ;
		DIRECTION OUTPUT ;
		SHAPE ABUTMENT ;
		PORT
			 LAYER M2 ;
			RECT 0.0098 42.0957 0.0481 42.1333 ;
			 LAYER M3 ;
			RECT 0.0098 42.0329 0.0481 42.1333 ;
			 LAYER V2 ;
			RECT 0.0215 42.1078 0.0364 42.1204 ;
		END

		ANTENNADIFFAREA 0.00194719 ;
		ANTENNAPARTIALMETALAREA 0.00195671 ;
	END WENYA[41]

	PIN WENYA[42]
		USE SIGNAL ;
		DIRECTION OUTPUT ;
		SHAPE ABUTMENT ;
		PORT
			 LAYER M2 ;
			RECT 0.0098 42.8863 0.0481 42.9239 ;
			 LAYER M3 ;
			RECT 0.0098 42.8235 0.0481 42.9239 ;
			 LAYER V2 ;
			RECT 0.0215 42.8984 0.0364 42.911 ;
		END

		ANTENNADIFFAREA 0.00194719 ;
		ANTENNAPARTIALMETALAREA 0.00195671 ;
	END WENYA[42]

	PIN WENYA[43]
		USE SIGNAL ;
		DIRECTION OUTPUT ;
		SHAPE ABUTMENT ;
		PORT
			 LAYER M2 ;
			RECT 0.0098 43.6769 0.0481 43.7145 ;
			 LAYER M3 ;
			RECT 0.0098 43.6141 0.0481 43.7145 ;
			 LAYER V2 ;
			RECT 0.0215 43.689 0.0364 43.7016 ;
		END

		ANTENNADIFFAREA 0.00194719 ;
		ANTENNAPARTIALMETALAREA 0.00195671 ;
	END WENYA[43]

	PIN WENYA[44]
		USE SIGNAL ;
		DIRECTION OUTPUT ;
		SHAPE ABUTMENT ;
		PORT
			 LAYER M2 ;
			RECT 0.0098 44.4675 0.0481 44.5051 ;
			 LAYER M3 ;
			RECT 0.0098 44.4047 0.0481 44.5051 ;
			 LAYER V2 ;
			RECT 0.0215 44.4796 0.0364 44.4922 ;
		END

		ANTENNADIFFAREA 0.00194719 ;
		ANTENNAPARTIALMETALAREA 0.00195671 ;
	END WENYA[44]

	PIN WENYA[45]
		USE SIGNAL ;
		DIRECTION OUTPUT ;
		SHAPE ABUTMENT ;
		PORT
			 LAYER M2 ;
			RECT 0.0098 45.258 0.0481 45.2957 ;
			 LAYER M3 ;
			RECT 0.0098 45.1953 0.0481 45.2957 ;
			 LAYER V2 ;
			RECT 0.0215 45.2702 0.0364 45.2827 ;
		END

		ANTENNADIFFAREA 0.00194719 ;
		ANTENNAPARTIALMETALAREA 0.00195671 ;
	END WENYA[45]

	PIN WENYA[46]
		USE SIGNAL ;
		DIRECTION OUTPUT ;
		SHAPE ABUTMENT ;
		PORT
			 LAYER M2 ;
			RECT 0.0098 46.0486 0.0481 46.0863 ;
			 LAYER M3 ;
			RECT 0.0098 45.9859 0.0481 46.0863 ;
			 LAYER V2 ;
			RECT 0.0215 46.0608 0.0364 46.0733 ;
		END

		ANTENNADIFFAREA 0.00194719 ;
		ANTENNAPARTIALMETALAREA 0.00195671 ;
	END WENYA[46]

	PIN WENYA[47]
		USE SIGNAL ;
		DIRECTION OUTPUT ;
		SHAPE ABUTMENT ;
		PORT
			 LAYER M2 ;
			RECT 0.0098 46.8392 0.0481 46.8769 ;
			 LAYER M3 ;
			RECT 0.0098 46.7765 0.0481 46.8769 ;
			 LAYER V2 ;
			RECT 0.0215 46.8514 0.0364 46.8639 ;
		END

		ANTENNADIFFAREA 0.00194719 ;
		ANTENNAPARTIALMETALAREA 0.00195671 ;
	END WENYA[47]

	PIN WENYA[48]
		USE SIGNAL ;
		DIRECTION OUTPUT ;
		SHAPE ABUTMENT ;
		PORT
			 LAYER M2 ;
			RECT 0.0098 47.6298 0.0481 47.6675 ;
			 LAYER M3 ;
			RECT 0.0098 47.5671 0.0481 47.6675 ;
			 LAYER V2 ;
			RECT 0.0215 47.642 0.0364 47.6545 ;
		END

		ANTENNADIFFAREA 0.00194719 ;
		ANTENNAPARTIALMETALAREA 0.00195671 ;
	END WENYA[48]

	PIN WENYA[49]
		USE SIGNAL ;
		DIRECTION OUTPUT ;
		SHAPE ABUTMENT ;
		PORT
			 LAYER M2 ;
			RECT 0.0098 48.4204 0.0481 48.458 ;
			 LAYER M3 ;
			RECT 0.0098 48.3576 0.0481 48.458 ;
			 LAYER V2 ;
			RECT 0.0215 48.4325 0.0364 48.4451 ;
		END

		ANTENNADIFFAREA 0.00194719 ;
		ANTENNAPARTIALMETALAREA 0.00195671 ;
	END WENYA[49]

	PIN WENYA[4]
		USE SIGNAL ;
		DIRECTION OUTPUT ;
		SHAPE ABUTMENT ;
		PORT
			 LAYER M2 ;
			RECT 0.0098 3.702 0.0481 3.7396 ;
			 LAYER M3 ;
			RECT 0.0098 3.702 0.0481 3.8024 ;
			 LAYER V2 ;
			RECT 0.0215 3.7149 0.0364 3.7275 ;
		END

		ANTENNADIFFAREA 0.00194719 ;
		ANTENNAPARTIALMETALAREA 0.00195671 ;
	END WENYA[4]

	PIN WENYA[50]
		USE SIGNAL ;
		DIRECTION OUTPUT ;
		SHAPE ABUTMENT ;
		PORT
			 LAYER M2 ;
			RECT 0.0098 49.211 0.0481 49.2486 ;
			 LAYER M3 ;
			RECT 0.0098 49.1482 0.0481 49.2486 ;
			 LAYER V2 ;
			RECT 0.0215 49.2231 0.0364 49.2357 ;
		END

		ANTENNADIFFAREA 0.00194719 ;
		ANTENNAPARTIALMETALAREA 0.00195671 ;
	END WENYA[50]

	PIN WENYA[51]
		USE SIGNAL ;
		DIRECTION OUTPUT ;
		SHAPE ABUTMENT ;
		PORT
			 LAYER M2 ;
			RECT 0.0098 50.0016 0.0481 50.0392 ;
			 LAYER M3 ;
			RECT 0.0098 49.9388 0.0481 50.0392 ;
			 LAYER V2 ;
			RECT 0.0215 50.0137 0.0364 50.0263 ;
		END

		ANTENNADIFFAREA 0.00194719 ;
		ANTENNAPARTIALMETALAREA 0.00195671 ;
	END WENYA[51]

	PIN WENYA[52]
		USE SIGNAL ;
		DIRECTION OUTPUT ;
		SHAPE ABUTMENT ;
		PORT
			 LAYER M2 ;
			RECT 0.0098 50.7922 0.0481 50.8298 ;
			 LAYER M3 ;
			RECT 0.0098 50.7294 0.0481 50.8298 ;
			 LAYER V2 ;
			RECT 0.0215 50.8043 0.0364 50.8169 ;
		END

		ANTENNADIFFAREA 0.00194719 ;
		ANTENNAPARTIALMETALAREA 0.00195671 ;
	END WENYA[52]

	PIN WENYA[53]
		USE SIGNAL ;
		DIRECTION OUTPUT ;
		SHAPE ABUTMENT ;
		PORT
			 LAYER M2 ;
			RECT 0.0098 51.5827 0.0481 51.6204 ;
			 LAYER M3 ;
			RECT 0.0098 51.52 0.0481 51.6204 ;
			 LAYER V2 ;
			RECT 0.0215 51.5949 0.0364 51.6075 ;
		END

		ANTENNADIFFAREA 0.00194719 ;
		ANTENNAPARTIALMETALAREA 0.00195671 ;
	END WENYA[53]

	PIN WENYA[54]
		USE SIGNAL ;
		DIRECTION OUTPUT ;
		SHAPE ABUTMENT ;
		PORT
			 LAYER M2 ;
			RECT 0.0098 52.3733 0.0481 52.411 ;
			 LAYER M3 ;
			RECT 0.0098 52.3106 0.0481 52.411 ;
			 LAYER V2 ;
			RECT 0.0215 52.3855 0.0364 52.398 ;
		END

		ANTENNADIFFAREA 0.00194719 ;
		ANTENNAPARTIALMETALAREA 0.00195671 ;
	END WENYA[54]

	PIN WENYA[55]
		USE SIGNAL ;
		DIRECTION OUTPUT ;
		SHAPE ABUTMENT ;
		PORT
			 LAYER M2 ;
			RECT 0.0098 53.1639 0.0481 53.2016 ;
			 LAYER M3 ;
			RECT 0.0098 53.1012 0.0481 53.2016 ;
			 LAYER V2 ;
			RECT 0.0215 53.1761 0.0364 53.1886 ;
		END

		ANTENNADIFFAREA 0.00194719 ;
		ANTENNAPARTIALMETALAREA 0.00195671 ;
	END WENYA[55]

	PIN WENYA[56]
		USE SIGNAL ;
		DIRECTION OUTPUT ;
		SHAPE ABUTMENT ;
		PORT
			 LAYER M2 ;
			RECT 0.0098 53.9545 0.0481 53.9922 ;
			 LAYER M3 ;
			RECT 0.0098 53.8918 0.0481 53.9922 ;
			 LAYER V2 ;
			RECT 0.0215 53.9667 0.0364 53.9792 ;
		END

		ANTENNADIFFAREA 0.00194719 ;
		ANTENNAPARTIALMETALAREA 0.00195671 ;
	END WENYA[56]

	PIN WENYA[57]
		USE SIGNAL ;
		DIRECTION OUTPUT ;
		SHAPE ABUTMENT ;
		PORT
			 LAYER M2 ;
			RECT 0.0098 54.7451 0.0481 54.7827 ;
			 LAYER M3 ;
			RECT 0.0098 54.6824 0.0481 54.7827 ;
			 LAYER V2 ;
			RECT 0.0215 54.7573 0.0364 54.7698 ;
		END

		ANTENNADIFFAREA 0.00194719 ;
		ANTENNAPARTIALMETALAREA 0.00195671 ;
	END WENYA[57]

	PIN WENYA[58]
		USE SIGNAL ;
		DIRECTION OUTPUT ;
		SHAPE ABUTMENT ;
		PORT
			 LAYER M2 ;
			RECT 0.0098 55.5357 0.0481 55.5733 ;
			 LAYER M3 ;
			RECT 0.0098 55.4729 0.0481 55.5733 ;
			 LAYER V2 ;
			RECT 0.0215 55.5478 0.0364 55.5604 ;
		END

		ANTENNADIFFAREA 0.00194719 ;
		ANTENNAPARTIALMETALAREA 0.00195671 ;
	END WENYA[58]

	PIN WENYA[59]
		USE SIGNAL ;
		DIRECTION OUTPUT ;
		SHAPE ABUTMENT ;
		PORT
			 LAYER M2 ;
			RECT 0.0098 56.3263 0.0481 56.3639 ;
			 LAYER M3 ;
			RECT 0.0098 56.2635 0.0481 56.3639 ;
			 LAYER V2 ;
			RECT 0.0215 56.3384 0.0364 56.351 ;
		END

		ANTENNADIFFAREA 0.00194719 ;
		ANTENNAPARTIALMETALAREA 0.00195671 ;
	END WENYA[59]

	PIN WENYA[5]
		USE SIGNAL ;
		DIRECTION OUTPUT ;
		SHAPE ABUTMENT ;
		PORT
			 LAYER M2 ;
			RECT 0.0098 4.4925 0.0481 4.5302 ;
			 LAYER M3 ;
			RECT 0.0098 4.4925 0.0481 4.5929 ;
			 LAYER V2 ;
			RECT 0.0215 4.5055 0.0364 4.518 ;
		END

		ANTENNADIFFAREA 0.00194719 ;
		ANTENNAPARTIALMETALAREA 0.00195671 ;
	END WENYA[5]

	PIN WENYA[60]
		USE SIGNAL ;
		DIRECTION OUTPUT ;
		SHAPE ABUTMENT ;
		PORT
			 LAYER M2 ;
			RECT 0.0098 57.1169 0.0481 57.1545 ;
			 LAYER M3 ;
			RECT 0.0098 57.0541 0.0481 57.1545 ;
			 LAYER V2 ;
			RECT 0.0215 57.129 0.0364 57.1416 ;
		END

		ANTENNADIFFAREA 0.00194719 ;
		ANTENNAPARTIALMETALAREA 0.00195671 ;
	END WENYA[60]

	PIN WENYA[61]
		USE SIGNAL ;
		DIRECTION OUTPUT ;
		SHAPE ABUTMENT ;
		PORT
			 LAYER M2 ;
			RECT 0.0098 57.9075 0.0481 57.9451 ;
			 LAYER M3 ;
			RECT 0.0098 57.8447 0.0481 57.9451 ;
			 LAYER V2 ;
			RECT 0.0215 57.9196 0.0364 57.9322 ;
		END

		ANTENNADIFFAREA 0.00194719 ;
		ANTENNAPARTIALMETALAREA 0.00195671 ;
	END WENYA[61]

	PIN WENYA[62]
		USE SIGNAL ;
		DIRECTION OUTPUT ;
		SHAPE ABUTMENT ;
		PORT
			 LAYER M2 ;
			RECT 0.0098 58.698 0.0481 58.7357 ;
			 LAYER M3 ;
			RECT 0.0098 58.6353 0.0481 58.7357 ;
			 LAYER V2 ;
			RECT 0.0215 58.7102 0.0364 58.7227 ;
		END

		ANTENNADIFFAREA 0.00194719 ;
		ANTENNAPARTIALMETALAREA 0.00195671 ;
	END WENYA[62]

	PIN WENYA[63]
		USE SIGNAL ;
		DIRECTION OUTPUT ;
		SHAPE ABUTMENT ;
		PORT
			 LAYER M2 ;
			RECT 0.0098 59.4886 0.0481 59.5263 ;
			 LAYER M3 ;
			RECT 0.0098 59.4259 0.0481 59.5263 ;
			 LAYER V2 ;
			RECT 0.0215 59.5008 0.0364 59.5133 ;
		END

		ANTENNADIFFAREA 0.00194719 ;
		ANTENNAPARTIALMETALAREA 0.00195671 ;
	END WENYA[63]

	PIN WENYA[64]
		USE SIGNAL ;
		DIRECTION OUTPUT ;
		SHAPE ABUTMENT ;
		PORT
			 LAYER M2 ;
			RECT 0.0098 60.2792 0.0481 60.3169 ;
			 LAYER M3 ;
			RECT 0.0098 60.2165 0.0481 60.3169 ;
			 LAYER V2 ;
			RECT 0.0215 60.2914 0.0364 60.3039 ;
		END

		ANTENNADIFFAREA 0.00194719 ;
		ANTENNAPARTIALMETALAREA 0.00195671 ;
	END WENYA[64]

	PIN WENYA[65]
		USE SIGNAL ;
		DIRECTION OUTPUT ;
		SHAPE ABUTMENT ;
		PORT
			 LAYER M2 ;
			RECT 0.0098 61.0698 0.0481 61.1075 ;
			 LAYER M3 ;
			RECT 0.0098 61.0071 0.0481 61.1075 ;
			 LAYER V2 ;
			RECT 0.0215 61.082 0.0364 61.0945 ;
		END

		ANTENNADIFFAREA 0.00194719 ;
		ANTENNAPARTIALMETALAREA 0.00195671 ;
	END WENYA[65]

	PIN WENYA[6]
		USE SIGNAL ;
		DIRECTION OUTPUT ;
		SHAPE ABUTMENT ;
		PORT
			 LAYER M2 ;
			RECT 0.0098 5.2831 0.0481 5.3208 ;
			 LAYER M3 ;
			RECT 0.0098 5.2831 0.0481 5.3835 ;
			 LAYER V2 ;
			RECT 0.0215 5.2961 0.0364 5.3086 ;
		END

		ANTENNADIFFAREA 0.00194719 ;
		ANTENNAPARTIALMETALAREA 0.00195671 ;
	END WENYA[6]

	PIN WENYA[7]
		USE SIGNAL ;
		DIRECTION OUTPUT ;
		SHAPE ABUTMENT ;
		PORT
			 LAYER M2 ;
			RECT 0.0098 6.0737 0.0481 6.1114 ;
			 LAYER M3 ;
			RECT 0.0098 6.0737 0.0481 6.1741 ;
			 LAYER V2 ;
			RECT 0.0215 6.0867 0.0364 6.0992 ;
		END

		ANTENNADIFFAREA 0.00194719 ;
		ANTENNAPARTIALMETALAREA 0.00195671 ;
	END WENYA[7]

	PIN WENYA[8]
		USE SIGNAL ;
		DIRECTION OUTPUT ;
		SHAPE ABUTMENT ;
		PORT
			 LAYER M2 ;
			RECT 0.0098 6.8643 0.0481 6.902 ;
			 LAYER M3 ;
			RECT 0.0098 6.8643 0.0481 6.9647 ;
			 LAYER V2 ;
			RECT 0.0215 6.8773 0.0364 6.8898 ;
		END

		ANTENNADIFFAREA 0.00194719 ;
		ANTENNAPARTIALMETALAREA 0.00195671 ;
	END WENYA[8]

	PIN WENYA[9]
		USE SIGNAL ;
		DIRECTION OUTPUT ;
		SHAPE ABUTMENT ;
		PORT
			 LAYER M2 ;
			RECT 0.0098 7.6549 0.0481 7.6925 ;
			 LAYER M3 ;
			RECT 0.0098 7.6549 0.0481 7.7553 ;
			 LAYER V2 ;
			RECT 0.0215 7.6678 0.0364 7.6804 ;
		END

		ANTENNADIFFAREA 0.00194719 ;
		ANTENNAPARTIALMETALAREA 0.00195671 ;
	END WENYA[9]

	PIN WENYB[0]
		USE SIGNAL ;
		DIRECTION OUTPUT ;
		SHAPE ABUTMENT ;
		PORT
			 LAYER M2 ;
			RECT 0.0098 0.3012 0.0481 0.3388 ;
		END

		ANTENNADIFFAREA 0.00194719 ;
		ANTENNAPARTIALMETALAREA 0.00195671 ;
	END WENYB[0]

	PIN WENYB[10]
		USE SIGNAL ;
		DIRECTION OUTPUT ;
		SHAPE ABUTMENT ;
		PORT
			 LAYER M2 ;
			RECT 0.0098 8.2071 0.0481 8.2447 ;
		END

		ANTENNADIFFAREA 0.00194719 ;
		ANTENNAPARTIALMETALAREA 0.00195671 ;
	END WENYB[10]

	PIN WENYB[11]
		USE SIGNAL ;
		DIRECTION OUTPUT ;
		SHAPE ABUTMENT ;
		PORT
			 LAYER M2 ;
			RECT 0.0098 8.9976 0.0481 9.0353 ;
		END

		ANTENNADIFFAREA 0.00194719 ;
		ANTENNAPARTIALMETALAREA 0.00195671 ;
	END WENYB[11]

	PIN WENYB[12]
		USE SIGNAL ;
		DIRECTION OUTPUT ;
		SHAPE ABUTMENT ;
		PORT
			 LAYER M2 ;
			RECT 0.0098 9.7882 0.0481 9.8259 ;
		END

		ANTENNADIFFAREA 0.00194719 ;
		ANTENNAPARTIALMETALAREA 0.00195671 ;
	END WENYB[12]

	PIN WENYB[13]
		USE SIGNAL ;
		DIRECTION OUTPUT ;
		SHAPE ABUTMENT ;
		PORT
			 LAYER M2 ;
			RECT 0.0098 10.5788 0.0481 10.6165 ;
		END

		ANTENNADIFFAREA 0.00194719 ;
		ANTENNAPARTIALMETALAREA 0.00195671 ;
	END WENYB[13]

	PIN WENYB[14]
		USE SIGNAL ;
		DIRECTION OUTPUT ;
		SHAPE ABUTMENT ;
		PORT
			 LAYER M2 ;
			RECT 0.0098 11.3694 0.0481 11.4071 ;
		END

		ANTENNADIFFAREA 0.00194719 ;
		ANTENNAPARTIALMETALAREA 0.00195671 ;
	END WENYB[14]

	PIN WENYB[15]
		USE SIGNAL ;
		DIRECTION OUTPUT ;
		SHAPE ABUTMENT ;
		PORT
			 LAYER M2 ;
			RECT 0.0098 12.16 0.0481 12.1976 ;
		END

		ANTENNADIFFAREA 0.00194719 ;
		ANTENNAPARTIALMETALAREA 0.00195671 ;
	END WENYB[15]

	PIN WENYB[16]
		USE SIGNAL ;
		DIRECTION OUTPUT ;
		SHAPE ABUTMENT ;
		PORT
			 LAYER M2 ;
			RECT 0.0098 12.9506 0.0481 12.9882 ;
		END

		ANTENNADIFFAREA 0.00194719 ;
		ANTENNAPARTIALMETALAREA 0.00195671 ;
	END WENYB[16]

	PIN WENYB[17]
		USE SIGNAL ;
		DIRECTION OUTPUT ;
		SHAPE ABUTMENT ;
		PORT
			 LAYER M2 ;
			RECT 0.0098 13.7412 0.0481 13.7788 ;
		END

		ANTENNADIFFAREA 0.00194719 ;
		ANTENNAPARTIALMETALAREA 0.00195671 ;
	END WENYB[17]

	PIN WENYB[18]
		USE SIGNAL ;
		DIRECTION OUTPUT ;
		SHAPE ABUTMENT ;
		PORT
			 LAYER M2 ;
			RECT 0.0098 14.5318 0.0481 14.5694 ;
		END

		ANTENNADIFFAREA 0.00194719 ;
		ANTENNAPARTIALMETALAREA 0.00195671 ;
	END WENYB[18]

	PIN WENYB[19]
		USE SIGNAL ;
		DIRECTION OUTPUT ;
		SHAPE ABUTMENT ;
		PORT
			 LAYER M2 ;
			RECT 0.0098 15.3224 0.0481 15.36 ;
		END

		ANTENNADIFFAREA 0.00194719 ;
		ANTENNAPARTIALMETALAREA 0.00195671 ;
	END WENYB[19]

	PIN WENYB[1]
		USE SIGNAL ;
		DIRECTION OUTPUT ;
		SHAPE ABUTMENT ;
		PORT
			 LAYER M2 ;
			RECT 0.0098 1.0918 0.0481 1.1294 ;
		END

		ANTENNADIFFAREA 0.00194719 ;
		ANTENNAPARTIALMETALAREA 0.00195671 ;
	END WENYB[1]

	PIN WENYB[20]
		USE SIGNAL ;
		DIRECTION OUTPUT ;
		SHAPE ABUTMENT ;
		PORT
			 LAYER M2 ;
			RECT 0.0098 16.1129 0.0481 16.1506 ;
		END

		ANTENNADIFFAREA 0.00194719 ;
		ANTENNAPARTIALMETALAREA 0.00195671 ;
	END WENYB[20]

	PIN WENYB[21]
		USE SIGNAL ;
		DIRECTION OUTPUT ;
		SHAPE ABUTMENT ;
		PORT
			 LAYER M2 ;
			RECT 0.0098 16.9035 0.0481 16.9412 ;
		END

		ANTENNADIFFAREA 0.00194719 ;
		ANTENNAPARTIALMETALAREA 0.00195671 ;
	END WENYB[21]

	PIN WENYB[22]
		USE SIGNAL ;
		DIRECTION OUTPUT ;
		SHAPE ABUTMENT ;
		PORT
			 LAYER M2 ;
			RECT 0.0098 17.6941 0.0481 17.7318 ;
		END

		ANTENNADIFFAREA 0.00194719 ;
		ANTENNAPARTIALMETALAREA 0.00195671 ;
	END WENYB[22]

	PIN WENYB[23]
		USE SIGNAL ;
		DIRECTION OUTPUT ;
		SHAPE ABUTMENT ;
		PORT
			 LAYER M2 ;
			RECT 0.0098 18.4847 0.0481 18.5224 ;
		END

		ANTENNADIFFAREA 0.00194719 ;
		ANTENNAPARTIALMETALAREA 0.00195671 ;
	END WENYB[23]

	PIN WENYB[24]
		USE SIGNAL ;
		DIRECTION OUTPUT ;
		SHAPE ABUTMENT ;
		PORT
			 LAYER M2 ;
			RECT 0.0098 19.2753 0.0481 19.3129 ;
		END

		ANTENNADIFFAREA 0.00194719 ;
		ANTENNAPARTIALMETALAREA 0.00195671 ;
	END WENYB[24]

	PIN WENYB[25]
		USE SIGNAL ;
		DIRECTION OUTPUT ;
		SHAPE ABUTMENT ;
		PORT
			 LAYER M2 ;
			RECT 0.0098 20.0659 0.0481 20.1035 ;
		END

		ANTENNADIFFAREA 0.00194719 ;
		ANTENNAPARTIALMETALAREA 0.00195671 ;
	END WENYB[25]

	PIN WENYB[26]
		USE SIGNAL ;
		DIRECTION OUTPUT ;
		SHAPE ABUTMENT ;
		PORT
			 LAYER M2 ;
			RECT 0.0098 20.8565 0.0481 20.8941 ;
		END

		ANTENNADIFFAREA 0.00194719 ;
		ANTENNAPARTIALMETALAREA 0.00195671 ;
	END WENYB[26]

	PIN WENYB[27]
		USE SIGNAL ;
		DIRECTION OUTPUT ;
		SHAPE ABUTMENT ;
		PORT
			 LAYER M2 ;
			RECT 0.0098 21.6471 0.0481 21.6847 ;
		END

		ANTENNADIFFAREA 0.00194719 ;
		ANTENNAPARTIALMETALAREA 0.00195671 ;
	END WENYB[27]

	PIN WENYB[28]
		USE SIGNAL ;
		DIRECTION OUTPUT ;
		SHAPE ABUTMENT ;
		PORT
			 LAYER M2 ;
			RECT 0.0098 22.4376 0.0481 22.4753 ;
		END

		ANTENNADIFFAREA 0.00194719 ;
		ANTENNAPARTIALMETALAREA 0.00195671 ;
	END WENYB[28]

	PIN WENYB[29]
		USE SIGNAL ;
		DIRECTION OUTPUT ;
		SHAPE ABUTMENT ;
		PORT
			 LAYER M2 ;
			RECT 0.0098 23.2282 0.0481 23.2659 ;
		END

		ANTENNADIFFAREA 0.00194719 ;
		ANTENNAPARTIALMETALAREA 0.00195671 ;
	END WENYB[29]

	PIN WENYB[2]
		USE SIGNAL ;
		DIRECTION OUTPUT ;
		SHAPE ABUTMENT ;
		PORT
			 LAYER M2 ;
			RECT 0.0098 1.8824 0.0481 1.92 ;
		END

		ANTENNADIFFAREA 0.00194719 ;
		ANTENNAPARTIALMETALAREA 0.00195671 ;
	END WENYB[2]

	PIN WENYB[30]
		USE SIGNAL ;
		DIRECTION OUTPUT ;
		SHAPE ABUTMENT ;
		PORT
			 LAYER M2 ;
			RECT 0.0098 24.0188 0.0481 24.0565 ;
		END

		ANTENNADIFFAREA 0.00194719 ;
		ANTENNAPARTIALMETALAREA 0.00195671 ;
	END WENYB[30]

	PIN WENYB[31]
		USE SIGNAL ;
		DIRECTION OUTPUT ;
		SHAPE ABUTMENT ;
		PORT
			 LAYER M2 ;
			RECT 0.0098 24.8094 0.0481 24.8471 ;
		END

		ANTENNADIFFAREA 0.00194719 ;
		ANTENNAPARTIALMETALAREA 0.00195671 ;
	END WENYB[31]

	PIN WENYB[32]
		USE SIGNAL ;
		DIRECTION OUTPUT ;
		SHAPE ABUTMENT ;
		PORT
			 LAYER M2 ;
			RECT 0.0098 25.6 0.0481 25.6376 ;
		END

		ANTENNADIFFAREA 0.00194719 ;
		ANTENNAPARTIALMETALAREA 0.00195671 ;
	END WENYB[32]

	PIN WENYB[33]
		USE SIGNAL ;
		DIRECTION OUTPUT ;
		SHAPE ABUTMENT ;
		PORT
			 LAYER M2 ;
			RECT 0.0098 36.0094 0.0481 36.0471 ;
		END

		ANTENNADIFFAREA 0.00194719 ;
		ANTENNAPARTIALMETALAREA 0.00195671 ;
	END WENYB[33]

	PIN WENYB[34]
		USE SIGNAL ;
		DIRECTION OUTPUT ;
		SHAPE ABUTMENT ;
		PORT
			 LAYER M2 ;
			RECT 0.0098 36.8 0.0481 36.8376 ;
		END

		ANTENNADIFFAREA 0.00194719 ;
		ANTENNAPARTIALMETALAREA 0.00195671 ;
	END WENYB[34]

	PIN WENYB[35]
		USE SIGNAL ;
		DIRECTION OUTPUT ;
		SHAPE ABUTMENT ;
		PORT
			 LAYER M2 ;
			RECT 0.0098 37.5906 0.0481 37.6282 ;
		END

		ANTENNADIFFAREA 0.00194719 ;
		ANTENNAPARTIALMETALAREA 0.00195671 ;
	END WENYB[35]

	PIN WENYB[36]
		USE SIGNAL ;
		DIRECTION OUTPUT ;
		SHAPE ABUTMENT ;
		PORT
			 LAYER M2 ;
			RECT 0.0098 38.3812 0.0481 38.4188 ;
		END

		ANTENNADIFFAREA 0.00194719 ;
		ANTENNAPARTIALMETALAREA 0.00195671 ;
	END WENYB[36]

	PIN WENYB[37]
		USE SIGNAL ;
		DIRECTION OUTPUT ;
		SHAPE ABUTMENT ;
		PORT
			 LAYER M2 ;
			RECT 0.0098 39.1718 0.0481 39.2094 ;
		END

		ANTENNADIFFAREA 0.00194719 ;
		ANTENNAPARTIALMETALAREA 0.00195671 ;
	END WENYB[37]

	PIN WENYB[38]
		USE SIGNAL ;
		DIRECTION OUTPUT ;
		SHAPE ABUTMENT ;
		PORT
			 LAYER M2 ;
			RECT 0.0098 39.9624 0.0481 40 ;
		END

		ANTENNADIFFAREA 0.00194719 ;
		ANTENNAPARTIALMETALAREA 0.00195671 ;
	END WENYB[38]

	PIN WENYB[39]
		USE SIGNAL ;
		DIRECTION OUTPUT ;
		SHAPE ABUTMENT ;
		PORT
			 LAYER M2 ;
			RECT 0.0098 40.7529 0.0481 40.7906 ;
		END

		ANTENNADIFFAREA 0.00194719 ;
		ANTENNAPARTIALMETALAREA 0.00195671 ;
	END WENYB[39]

	PIN WENYB[3]
		USE SIGNAL ;
		DIRECTION OUTPUT ;
		SHAPE ABUTMENT ;
		PORT
			 LAYER M2 ;
			RECT 0.0098 2.6729 0.0481 2.7106 ;
		END

		ANTENNADIFFAREA 0.00194719 ;
		ANTENNAPARTIALMETALAREA 0.00195671 ;
	END WENYB[3]

	PIN WENYB[40]
		USE SIGNAL ;
		DIRECTION OUTPUT ;
		SHAPE ABUTMENT ;
		PORT
			 LAYER M2 ;
			RECT 0.0098 41.5435 0.0481 41.5812 ;
		END

		ANTENNADIFFAREA 0.00194719 ;
		ANTENNAPARTIALMETALAREA 0.00195671 ;
	END WENYB[40]

	PIN WENYB[41]
		USE SIGNAL ;
		DIRECTION OUTPUT ;
		SHAPE ABUTMENT ;
		PORT
			 LAYER M2 ;
			RECT 0.0098 42.3341 0.0481 42.3718 ;
		END

		ANTENNADIFFAREA 0.00194719 ;
		ANTENNAPARTIALMETALAREA 0.00195671 ;
	END WENYB[41]

	PIN WENYB[42]
		USE SIGNAL ;
		DIRECTION OUTPUT ;
		SHAPE ABUTMENT ;
		PORT
			 LAYER M2 ;
			RECT 0.0098 43.1247 0.0481 43.1624 ;
		END

		ANTENNADIFFAREA 0.00194719 ;
		ANTENNAPARTIALMETALAREA 0.00195671 ;
	END WENYB[42]

	PIN WENYB[43]
		USE SIGNAL ;
		DIRECTION OUTPUT ;
		SHAPE ABUTMENT ;
		PORT
			 LAYER M2 ;
			RECT 0.0098 43.9153 0.0481 43.9529 ;
		END

		ANTENNADIFFAREA 0.00194719 ;
		ANTENNAPARTIALMETALAREA 0.00195671 ;
	END WENYB[43]

	PIN WENYB[44]
		USE SIGNAL ;
		DIRECTION OUTPUT ;
		SHAPE ABUTMENT ;
		PORT
			 LAYER M2 ;
			RECT 0.0098 44.7059 0.0481 44.7435 ;
		END

		ANTENNADIFFAREA 0.00194719 ;
		ANTENNAPARTIALMETALAREA 0.00195671 ;
	END WENYB[44]

	PIN WENYB[45]
		USE SIGNAL ;
		DIRECTION OUTPUT ;
		SHAPE ABUTMENT ;
		PORT
			 LAYER M2 ;
			RECT 0.0098 45.4965 0.0481 45.5341 ;
		END

		ANTENNADIFFAREA 0.00194719 ;
		ANTENNAPARTIALMETALAREA 0.00195671 ;
	END WENYB[45]

	PIN WENYB[46]
		USE SIGNAL ;
		DIRECTION OUTPUT ;
		SHAPE ABUTMENT ;
		PORT
			 LAYER M2 ;
			RECT 0.0098 46.2871 0.0481 46.3247 ;
		END

		ANTENNADIFFAREA 0.00194719 ;
		ANTENNAPARTIALMETALAREA 0.00195671 ;
	END WENYB[46]

	PIN WENYB[47]
		USE SIGNAL ;
		DIRECTION OUTPUT ;
		SHAPE ABUTMENT ;
		PORT
			 LAYER M2 ;
			RECT 0.0098 47.0776 0.0481 47.1153 ;
		END

		ANTENNADIFFAREA 0.00194719 ;
		ANTENNAPARTIALMETALAREA 0.00195671 ;
	END WENYB[47]

	PIN WENYB[48]
		USE SIGNAL ;
		DIRECTION OUTPUT ;
		SHAPE ABUTMENT ;
		PORT
			 LAYER M2 ;
			RECT 0.0098 47.8682 0.0481 47.9059 ;
		END

		ANTENNADIFFAREA 0.00194719 ;
		ANTENNAPARTIALMETALAREA 0.00195671 ;
	END WENYB[48]

	PIN WENYB[49]
		USE SIGNAL ;
		DIRECTION OUTPUT ;
		SHAPE ABUTMENT ;
		PORT
			 LAYER M2 ;
			RECT 0.0098 48.6588 0.0481 48.6965 ;
		END

		ANTENNADIFFAREA 0.00194719 ;
		ANTENNAPARTIALMETALAREA 0.00195671 ;
	END WENYB[49]

	PIN WENYB[4]
		USE SIGNAL ;
		DIRECTION OUTPUT ;
		SHAPE ABUTMENT ;
		PORT
			 LAYER M2 ;
			RECT 0.0098 3.4635 0.0481 3.5012 ;
		END

		ANTENNADIFFAREA 0.00194719 ;
		ANTENNAPARTIALMETALAREA 0.00195671 ;
	END WENYB[4]

	PIN WENYB[50]
		USE SIGNAL ;
		DIRECTION OUTPUT ;
		SHAPE ABUTMENT ;
		PORT
			 LAYER M2 ;
			RECT 0.0098 49.4494 0.0481 49.4871 ;
		END

		ANTENNADIFFAREA 0.00194719 ;
		ANTENNAPARTIALMETALAREA 0.00195671 ;
	END WENYB[50]

	PIN WENYB[51]
		USE SIGNAL ;
		DIRECTION OUTPUT ;
		SHAPE ABUTMENT ;
		PORT
			 LAYER M2 ;
			RECT 0.0098 50.24 0.0481 50.2776 ;
		END

		ANTENNADIFFAREA 0.00194719 ;
		ANTENNAPARTIALMETALAREA 0.00195671 ;
	END WENYB[51]

	PIN WENYB[52]
		USE SIGNAL ;
		DIRECTION OUTPUT ;
		SHAPE ABUTMENT ;
		PORT
			 LAYER M2 ;
			RECT 0.0098 51.0306 0.0481 51.0682 ;
		END

		ANTENNADIFFAREA 0.00194719 ;
		ANTENNAPARTIALMETALAREA 0.00195671 ;
	END WENYB[52]

	PIN WENYB[53]
		USE SIGNAL ;
		DIRECTION OUTPUT ;
		SHAPE ABUTMENT ;
		PORT
			 LAYER M2 ;
			RECT 0.0098 51.8212 0.0481 51.8588 ;
		END

		ANTENNADIFFAREA 0.00194719 ;
		ANTENNAPARTIALMETALAREA 0.00195671 ;
	END WENYB[53]

	PIN WENYB[54]
		USE SIGNAL ;
		DIRECTION OUTPUT ;
		SHAPE ABUTMENT ;
		PORT
			 LAYER M2 ;
			RECT 0.0098 52.6118 0.0481 52.6494 ;
		END

		ANTENNADIFFAREA 0.00194719 ;
		ANTENNAPARTIALMETALAREA 0.00195671 ;
	END WENYB[54]

	PIN WENYB[55]
		USE SIGNAL ;
		DIRECTION OUTPUT ;
		SHAPE ABUTMENT ;
		PORT
			 LAYER M2 ;
			RECT 0.0098 53.4024 0.0481 53.44 ;
		END

		ANTENNADIFFAREA 0.00194719 ;
		ANTENNAPARTIALMETALAREA 0.00195671 ;
	END WENYB[55]

	PIN WENYB[56]
		USE SIGNAL ;
		DIRECTION OUTPUT ;
		SHAPE ABUTMENT ;
		PORT
			 LAYER M2 ;
			RECT 0.0098 54.1929 0.0481 54.2306 ;
		END

		ANTENNADIFFAREA 0.00194719 ;
		ANTENNAPARTIALMETALAREA 0.00195671 ;
	END WENYB[56]

	PIN WENYB[57]
		USE SIGNAL ;
		DIRECTION OUTPUT ;
		SHAPE ABUTMENT ;
		PORT
			 LAYER M2 ;
			RECT 0.0098 54.9835 0.0481 55.0212 ;
		END

		ANTENNADIFFAREA 0.00194719 ;
		ANTENNAPARTIALMETALAREA 0.00195671 ;
	END WENYB[57]

	PIN WENYB[58]
		USE SIGNAL ;
		DIRECTION OUTPUT ;
		SHAPE ABUTMENT ;
		PORT
			 LAYER M2 ;
			RECT 0.0098 55.7741 0.0481 55.8118 ;
		END

		ANTENNADIFFAREA 0.00194719 ;
		ANTENNAPARTIALMETALAREA 0.00195671 ;
	END WENYB[58]

	PIN WENYB[59]
		USE SIGNAL ;
		DIRECTION OUTPUT ;
		SHAPE ABUTMENT ;
		PORT
			 LAYER M2 ;
			RECT 0.0098 56.5647 0.0481 56.6024 ;
		END

		ANTENNADIFFAREA 0.00194719 ;
		ANTENNAPARTIALMETALAREA 0.00195671 ;
	END WENYB[59]

	PIN WENYB[5]
		USE SIGNAL ;
		DIRECTION OUTPUT ;
		SHAPE ABUTMENT ;
		PORT
			 LAYER M2 ;
			RECT 0.0098 4.2541 0.0481 4.2918 ;
		END

		ANTENNADIFFAREA 0.00194719 ;
		ANTENNAPARTIALMETALAREA 0.00195671 ;
	END WENYB[5]

	PIN WENYB[60]
		USE SIGNAL ;
		DIRECTION OUTPUT ;
		SHAPE ABUTMENT ;
		PORT
			 LAYER M2 ;
			RECT 0.0098 57.3553 0.0481 57.3929 ;
		END

		ANTENNADIFFAREA 0.00194719 ;
		ANTENNAPARTIALMETALAREA 0.00195671 ;
	END WENYB[60]

	PIN WENYB[61]
		USE SIGNAL ;
		DIRECTION OUTPUT ;
		SHAPE ABUTMENT ;
		PORT
			 LAYER M2 ;
			RECT 0.0098 58.1459 0.0481 58.1835 ;
		END

		ANTENNADIFFAREA 0.00194719 ;
		ANTENNAPARTIALMETALAREA 0.00195671 ;
	END WENYB[61]

	PIN WENYB[62]
		USE SIGNAL ;
		DIRECTION OUTPUT ;
		SHAPE ABUTMENT ;
		PORT
			 LAYER M2 ;
			RECT 0.0098 58.9365 0.0481 58.9741 ;
		END

		ANTENNADIFFAREA 0.00194719 ;
		ANTENNAPARTIALMETALAREA 0.00195671 ;
	END WENYB[62]

	PIN WENYB[63]
		USE SIGNAL ;
		DIRECTION OUTPUT ;
		SHAPE ABUTMENT ;
		PORT
			 LAYER M2 ;
			RECT 0.0098 59.7271 0.0481 59.7647 ;
		END

		ANTENNADIFFAREA 0.00194719 ;
		ANTENNAPARTIALMETALAREA 0.00195671 ;
	END WENYB[63]

	PIN WENYB[64]
		USE SIGNAL ;
		DIRECTION OUTPUT ;
		SHAPE ABUTMENT ;
		PORT
			 LAYER M2 ;
			RECT 0.0098 60.5176 0.0481 60.5553 ;
		END

		ANTENNADIFFAREA 0.00194719 ;
		ANTENNAPARTIALMETALAREA 0.00195671 ;
	END WENYB[64]

	PIN WENYB[65]
		USE SIGNAL ;
		DIRECTION OUTPUT ;
		SHAPE ABUTMENT ;
		PORT
			 LAYER M2 ;
			RECT 0.0098 61.3082 0.0481 61.3459 ;
		END

		ANTENNADIFFAREA 0.00194719 ;
		ANTENNAPARTIALMETALAREA 0.00195671 ;
	END WENYB[65]

	PIN WENYB[6]
		USE SIGNAL ;
		DIRECTION OUTPUT ;
		SHAPE ABUTMENT ;
		PORT
			 LAYER M2 ;
			RECT 0.0098 5.0447 0.0481 5.0824 ;
		END

		ANTENNADIFFAREA 0.00194719 ;
		ANTENNAPARTIALMETALAREA 0.00195671 ;
	END WENYB[6]

	PIN WENYB[7]
		USE SIGNAL ;
		DIRECTION OUTPUT ;
		SHAPE ABUTMENT ;
		PORT
			 LAYER M2 ;
			RECT 0.0098 5.8353 0.0481 5.8729 ;
		END

		ANTENNADIFFAREA 0.00194719 ;
		ANTENNAPARTIALMETALAREA 0.00195671 ;
	END WENYB[7]

	PIN WENYB[8]
		USE SIGNAL ;
		DIRECTION OUTPUT ;
		SHAPE ABUTMENT ;
		PORT
			 LAYER M2 ;
			RECT 0.0098 6.6259 0.0481 6.6635 ;
		END

		ANTENNADIFFAREA 0.00194719 ;
		ANTENNAPARTIALMETALAREA 0.00195671 ;
	END WENYB[8]

	PIN WENYB[9]
		USE SIGNAL ;
		DIRECTION OUTPUT ;
		SHAPE ABUTMENT ;
		PORT
			 LAYER M2 ;
			RECT 0.0098 7.4165 0.0481 7.4541 ;
		END

		ANTENNADIFFAREA 0.00194719 ;
		ANTENNAPARTIALMETALAREA 0.00195671 ;
	END WENYB[9]

	OBS
		 LAYER M1 SPACING 0.012 ;
		RECT 0 0 31.521 61.6471 ;
		 LAYER M2 SPACING 0.012 ;
		RECT 0.133 0 31.521 61.6471 ;
		RECT 0 0 0.133 0.069 ;
		RECT 0 0.2071 0.133 0.2196 ;
		RECT 0 0.3576 0.133 0.3702 ;
		RECT 0 0.5082 0.133 0.5208 ;
		RECT 0 0.7843 0.133 0.822 ;
		RECT 0 0.96 0.133 1.0102 ;
		RECT 0 1.1482 0.133 1.1608 ;
		RECT 0 1.2988 0.133 1.3114 ;
		RECT 0 1.5749 0.133 1.6125 ;
		RECT 0 1.7506 0.133 1.8008 ;
		RECT 0 1.9388 0.133 1.9514 ;
		RECT 0 2.0894 0.133 2.102 ;
		RECT 0 2.3655 0.133 2.4031 ;
		RECT 0 2.5412 0.133 2.5914 ;
		RECT 0 2.7294 0.133 2.742 ;
		RECT 0 2.88 0.133 2.8925 ;
		RECT 0 3.1561 0.133 3.1937 ;
		RECT 0 3.3318 0.133 3.382 ;
		RECT 0 3.52 0.133 3.5325 ;
		RECT 0 3.6706 0.133 3.6831 ;
		RECT 0 3.9467 0.133 3.9843 ;
		RECT 0 4.1224 0.133 4.1725 ;
		RECT 0 4.3106 0.133 4.3231 ;
		RECT 0 4.4612 0.133 4.4737 ;
		RECT 0 4.7373 0.133 4.7749 ;
		RECT 0 4.9129 0.133 4.9631 ;
		RECT 0 5.1012 0.133 5.1137 ;
		RECT 0 5.2518 0.133 5.2643 ;
		RECT 0 5.5278 0.133 5.5655 ;
		RECT 0 5.7035 0.133 5.7537 ;
		RECT 0 5.8918 0.133 5.9043 ;
		RECT 0 6.0424 0.133 6.0549 ;
		RECT 0 6.3184 0.133 6.3561 ;
		RECT 0 6.4941 0.133 6.5443 ;
		RECT 0 6.6824 0.133 6.6949 ;
		RECT 0 6.8329 0.133 6.8455 ;
		RECT 0 7.109 0.133 7.1467 ;
		RECT 0 7.2847 0.133 7.3349 ;
		RECT 0 7.4729 0.133 7.4855 ;
		RECT 0 7.6235 0.133 7.6361 ;
		RECT 0 7.8996 0.133 7.9373 ;
		RECT 0 8.0753 0.133 8.1255 ;
		RECT 0 8.2635 0.133 8.2761 ;
		RECT 0 8.4141 0.133 8.4267 ;
		RECT 0 8.6902 0.133 8.7278 ;
		RECT 0 8.8659 0.133 8.9161 ;
		RECT 0 9.0541 0.133 9.0667 ;
		RECT 0 9.2047 0.133 9.2173 ;
		RECT 0 9.4808 0.133 9.5184 ;
		RECT 0 9.6565 0.133 9.7067 ;
		RECT 0 9.8447 0.133 9.8573 ;
		RECT 0 9.9953 0.133 10.0078 ;
		RECT 0 10.2714 0.133 10.309 ;
		RECT 0 10.4471 0.133 10.4973 ;
		RECT 0 10.6353 0.133 10.6478 ;
		RECT 0 10.7859 0.133 10.7984 ;
		RECT 0 11.062 0.133 11.0996 ;
		RECT 0 11.2376 0.133 11.2878 ;
		RECT 0 11.4259 0.133 11.4384 ;
		RECT 0 11.5765 0.133 11.589 ;
		RECT 0 11.8525 0.133 11.8902 ;
		RECT 0 12.0282 0.133 12.0784 ;
		RECT 0 12.2165 0.133 12.229 ;
		RECT 0 12.3671 0.133 12.3796 ;
		RECT 0 12.6431 0.133 12.6808 ;
		RECT 0 12.8188 0.133 12.869 ;
		RECT 0 13.0071 0.133 13.0196 ;
		RECT 0 13.1576 0.133 13.1702 ;
		RECT 0 13.4337 0.133 13.4714 ;
		RECT 0 13.6094 0.133 13.6596 ;
		RECT 0 13.7976 0.133 13.8102 ;
		RECT 0 13.9482 0.133 13.9608 ;
		RECT 0 14.2243 0.133 14.262 ;
		RECT 0 14.4 0.133 14.4502 ;
		RECT 0 14.5882 0.133 14.6008 ;
		RECT 0 14.7388 0.133 14.7514 ;
		RECT 0 15.0149 0.133 15.0525 ;
		RECT 0 15.1906 0.133 15.2408 ;
		RECT 0 15.3788 0.133 15.3914 ;
		RECT 0 15.5294 0.133 15.542 ;
		RECT 0 15.8055 0.133 15.8431 ;
		RECT 0 15.9812 0.133 16.0314 ;
		RECT 0 16.1694 0.133 16.182 ;
		RECT 0 16.32 0.133 16.3325 ;
		RECT 0 16.5961 0.133 16.6337 ;
		RECT 0 16.7718 0.133 16.822 ;
		RECT 0 16.96 0.133 16.9725 ;
		RECT 0 17.1106 0.133 17.1231 ;
		RECT 0 17.3867 0.133 17.4243 ;
		RECT 0 17.5624 0.133 17.6125 ;
		RECT 0 17.7506 0.133 17.7631 ;
		RECT 0 17.9012 0.133 17.9137 ;
		RECT 0 18.1773 0.133 18.2149 ;
		RECT 0 18.3529 0.133 18.4031 ;
		RECT 0 18.5412 0.133 18.5537 ;
		RECT 0 18.6918 0.133 18.7043 ;
		RECT 0 18.9678 0.133 19.0055 ;
		RECT 0 19.1435 0.133 19.1937 ;
		RECT 0 19.3318 0.133 19.3443 ;
		RECT 0 19.4824 0.133 19.4949 ;
		RECT 0 19.7584 0.133 19.7961 ;
		RECT 0 19.9341 0.133 19.9843 ;
		RECT 0 20.1224 0.133 20.1349 ;
		RECT 0 20.2729 0.133 20.2855 ;
		RECT 0 20.549 0.133 20.5867 ;
		RECT 0 20.7247 0.133 20.7749 ;
		RECT 0 20.9129 0.133 20.9255 ;
		RECT 0 21.0635 0.133 21.0761 ;
		RECT 0 21.3396 0.133 21.3773 ;
		RECT 0 21.5153 0.133 21.5655 ;
		RECT 0 21.7035 0.133 21.7161 ;
		RECT 0 21.8541 0.133 21.8667 ;
		RECT 0 22.1302 0.133 22.1678 ;
		RECT 0 22.3059 0.133 22.3561 ;
		RECT 0 22.4941 0.133 22.5067 ;
		RECT 0 22.6447 0.133 22.6573 ;
		RECT 0 22.9208 0.133 22.9584 ;
		RECT 0 23.0965 0.133 23.1467 ;
		RECT 0 23.2847 0.133 23.2973 ;
		RECT 0 23.4353 0.133 23.4478 ;
		RECT 0 23.7114 0.133 23.749 ;
		RECT 0 23.8871 0.133 23.9373 ;
		RECT 0 24.0753 0.133 24.0878 ;
		RECT 0 24.2259 0.133 24.2384 ;
		RECT 0 24.502 0.133 24.5396 ;
		RECT 0 24.6776 0.133 24.7278 ;
		RECT 0 24.8659 0.133 24.8784 ;
		RECT 0 25.0165 0.133 25.029 ;
		RECT 0 25.2925 0.133 25.3302 ;
		RECT 0 25.4682 0.133 25.5184 ;
		RECT 0 25.6565 0.133 25.669 ;
		RECT 0 25.8071 0.133 25.8196 ;
		RECT 0 26.0831 0.133 26.1208 ;
		RECT 0 26.2588 0.133 27.1498 ;
		RECT 0 27.2878 0.133 27.3004 ;
		RECT 0.0714 27.3004 0.133 27.451 ;
		RECT 0 27.4384 0.133 27.451 ;
		RECT 0.0714 27.451 0.133 27.6016 ;
		RECT 0 27.589 0.133 27.6016 ;
		RECT 0 27.7396 0.133 28.0533 ;
		RECT 0 28.1914 0.133 28.2039 ;
		RECT 0 28.342 0.133 28.3545 ;
		RECT 0 28.869 0.133 29.0573 ;
		RECT 0 29.1953 0.133 29.2078 ;
		RECT 0 29.3459 0.133 29.3584 ;
		RECT 0 29.622 0.133 29.6345 ;
		RECT 0 29.7725 0.133 30.0863 ;
		RECT 0 30.2243 0.133 30.2369 ;
		RECT 0 30.6259 0.133 31.1655 ;
		RECT 0 31.3035 0.133 31.4165 ;
		RECT 0 31.68 0.133 31.6925 ;
		RECT 0 32.2071 0.133 32.2196 ;
		RECT 0 32.7341 0.133 32.7467 ;
		RECT 0 33.2612 0.133 33.2737 ;
		RECT 0 33.7882 0.133 34.0518 ;
		RECT 0 34.1898 0.133 34.2024 ;
		RECT 0 34.3404 0.133 34.3529 ;
		RECT 0 34.491 0.133 35.3882 ;
		RECT 0 35.5263 0.133 35.5639 ;
		RECT 0 35.8275 0.133 35.84 ;
		RECT 0 35.978 0.133 35.9906 ;
		RECT 0 36.1286 0.133 36.1788 ;
		RECT 0 36.3169 0.133 36.3545 ;
		RECT 0 36.618 0.133 36.6306 ;
		RECT 0 36.7686 0.133 36.7812 ;
		RECT 0 36.9192 0.133 36.9694 ;
		RECT 0 37.1075 0.133 37.1451 ;
		RECT 0 37.4086 0.133 37.4212 ;
		RECT 0 37.5592 0.133 37.5718 ;
		RECT 0 37.7098 0.133 37.76 ;
		RECT 0 37.898 0.133 37.9357 ;
		RECT 0 38.1992 0.133 38.2118 ;
		RECT 0 38.3498 0.133 38.3624 ;
		RECT 0 38.5004 0.133 38.5506 ;
		RECT 0 38.6886 0.133 38.7263 ;
		RECT 0 38.9898 0.133 39.0024 ;
		RECT 0 39.1404 0.133 39.1529 ;
		RECT 0 39.291 0.133 39.3412 ;
		RECT 0 39.4792 0.133 39.5169 ;
		RECT 0 39.7804 0.133 39.7929 ;
		RECT 0 39.931 0.133 39.9435 ;
		RECT 0 40.0816 0.133 40.1318 ;
		RECT 0 40.2698 0.133 40.3075 ;
		RECT 0 40.571 0.133 40.5835 ;
		RECT 0 40.7216 0.133 40.7341 ;
		RECT 0 40.8722 0.133 40.9224 ;
		RECT 0 41.0604 0.133 41.098 ;
		RECT 0 41.3616 0.133 41.3741 ;
		RECT 0 41.5122 0.133 41.5247 ;
		RECT 0 41.6627 0.133 41.7129 ;
		RECT 0 41.851 0.133 41.8886 ;
		RECT 0 42.1522 0.133 42.1647 ;
		RECT 0 42.3027 0.133 42.3153 ;
		RECT 0 42.4533 0.133 42.5035 ;
		RECT 0 42.6416 0.133 42.6792 ;
		RECT 0 42.9427 0.133 42.9553 ;
		RECT 0 43.0933 0.133 43.1059 ;
		RECT 0 43.2439 0.133 43.2941 ;
		RECT 0 43.4322 0.133 43.4698 ;
		RECT 0 43.7333 0.133 43.7459 ;
		RECT 0 43.8839 0.133 43.8965 ;
		RECT 0 44.0345 0.133 44.0847 ;
		RECT 0 44.2227 0.133 44.2604 ;
		RECT 0 44.5239 0.133 44.5365 ;
		RECT 0 44.6745 0.133 44.6871 ;
		RECT 0 44.8251 0.133 44.8753 ;
		RECT 0 45.0133 0.133 45.051 ;
		RECT 0 45.3145 0.133 45.3271 ;
		RECT 0 45.4651 0.133 45.4776 ;
		RECT 0 45.6157 0.133 45.6659 ;
		RECT 0 45.8039 0.133 45.8416 ;
		RECT 0 46.1051 0.133 46.1176 ;
		RECT 0 46.2557 0.133 46.2682 ;
		RECT 0 46.4063 0.133 46.4565 ;
		RECT 0 46.5945 0.133 46.6322 ;
		RECT 0 46.8957 0.133 46.9082 ;
		RECT 0 47.0463 0.133 47.0588 ;
		RECT 0 47.1969 0.133 47.2471 ;
		RECT 0 47.3851 0.133 47.4227 ;
		RECT 0 47.6863 0.133 47.6988 ;
		RECT 0 47.8369 0.133 47.8494 ;
		RECT 0 47.9875 0.133 48.0376 ;
		RECT 0 48.1757 0.133 48.2133 ;
		RECT 0 48.4769 0.133 48.4894 ;
		RECT 0 48.6275 0.133 48.64 ;
		RECT 0 48.778 0.133 48.8282 ;
		RECT 0 48.9663 0.133 49.0039 ;
		RECT 0 49.2675 0.133 49.28 ;
		RECT 0 49.418 0.133 49.4306 ;
		RECT 0 49.5686 0.133 49.6188 ;
		RECT 0 49.7569 0.133 49.7945 ;
		RECT 0 50.058 0.133 50.0706 ;
		RECT 0 50.2086 0.133 50.2212 ;
		RECT 0 50.3592 0.133 50.4094 ;
		RECT 0 50.5475 0.133 50.5851 ;
		RECT 0 50.8486 0.133 50.8612 ;
		RECT 0 50.9992 0.133 51.0118 ;
		RECT 0 51.1498 0.133 51.2 ;
		RECT 0 51.338 0.133 51.3757 ;
		RECT 0 51.6392 0.133 51.6518 ;
		RECT 0 51.7898 0.133 51.8024 ;
		RECT 0 51.9404 0.133 51.9906 ;
		RECT 0 52.1286 0.133 52.1663 ;
		RECT 0 52.4298 0.133 52.4424 ;
		RECT 0 52.5804 0.133 52.5929 ;
		RECT 0 52.731 0.133 52.7812 ;
		RECT 0 52.9192 0.133 52.9569 ;
		RECT 0 53.2204 0.133 53.2329 ;
		RECT 0 53.371 0.133 53.3835 ;
		RECT 0 53.5216 0.133 53.5718 ;
		RECT 0 53.7098 0.133 53.7475 ;
		RECT 0 54.011 0.133 54.0235 ;
		RECT 0 54.1616 0.133 54.1741 ;
		RECT 0 54.3122 0.133 54.3624 ;
		RECT 0 54.5004 0.133 54.538 ;
		RECT 0 54.8016 0.133 54.8141 ;
		RECT 0 54.9522 0.133 54.9647 ;
		RECT 0 55.1027 0.133 55.1529 ;
		RECT 0 55.291 0.133 55.3286 ;
		RECT 0 55.5922 0.133 55.6047 ;
		RECT 0 55.7427 0.133 55.7553 ;
		RECT 0 55.8933 0.133 55.9435 ;
		RECT 0 56.0816 0.133 56.1192 ;
		RECT 0 56.3827 0.133 56.3953 ;
		RECT 0 56.5333 0.133 56.5459 ;
		RECT 0 56.6839 0.133 56.7341 ;
		RECT 0 56.8722 0.133 56.9098 ;
		RECT 0 57.1733 0.133 57.1859 ;
		RECT 0 57.3239 0.133 57.3365 ;
		RECT 0 57.4745 0.133 57.5247 ;
		RECT 0 57.6627 0.133 57.7004 ;
		RECT 0 57.9639 0.133 57.9765 ;
		RECT 0 58.1145 0.133 58.1271 ;
		RECT 0 58.2651 0.133 58.3153 ;
		RECT 0 58.4533 0.133 58.491 ;
		RECT 0 58.7545 0.133 58.7671 ;
		RECT 0 58.9051 0.133 58.9176 ;
		RECT 0 59.0557 0.133 59.1059 ;
		RECT 0 59.2439 0.133 59.2816 ;
		RECT 0 59.5451 0.133 59.5576 ;
		RECT 0 59.6957 0.133 59.7082 ;
		RECT 0 59.8463 0.133 59.8965 ;
		RECT 0 60.0345 0.133 60.0722 ;
		RECT 0 60.3357 0.133 60.3482 ;
		RECT 0 60.4863 0.133 60.4988 ;
		RECT 0 60.6369 0.133 60.6871 ;
		RECT 0 60.8251 0.133 60.8627 ;
		RECT 0 61.1263 0.133 61.1388 ;
		RECT 0 61.2769 0.133 61.2894 ;
		RECT 0 61.4275 0.133 61.44 ;
		RECT 0 61.578 0.133 61.6471 ;
		 LAYER M2 ;
		RECT 0.0714 0.2384 0.1097 0.3388 ;
		RECT 0.0714 0.8408 0.1097 0.9412 ;
		RECT 0.0714 1.029 0.1097 1.1294 ;
		RECT 0.0714 1.6314 0.1097 1.7318 ;
		RECT 0.0714 1.8196 0.1097 1.92 ;
		RECT 0.0714 2.422 0.1097 2.5224 ;
		RECT 0.0714 2.6102 0.1097 2.7106 ;
		RECT 0.0714 3.2125 0.1097 3.3129 ;
		RECT 0.0714 3.4008 0.1097 3.5012 ;
		RECT 0.0714 4.0031 0.1097 4.1035 ;
		RECT 0.0714 4.1914 0.1097 4.2918 ;
		RECT 0.0714 4.7937 0.1097 4.8941 ;
		RECT 0.0714 4.982 0.1097 5.0824 ;
		RECT 0.0714 5.5843 0.1097 5.6847 ;
		RECT 0.0714 5.7725 0.1097 5.8729 ;
		RECT 0.0714 6.3749 0.1097 6.4753 ;
		RECT 0.0714 6.5631 0.1097 6.6635 ;
		RECT 0.0714 7.1655 0.1097 7.2659 ;
		RECT 0.0714 7.3537 0.1097 7.4541 ;
		RECT 0.0714 7.9561 0.1097 8.0565 ;
		RECT 0.0714 8.1443 0.1097 8.2447 ;
		RECT 0.0714 8.7467 0.1097 8.8471 ;
		RECT 0.0714 8.9349 0.1097 9.0353 ;
		RECT 0.0714 9.5373 0.1097 9.6376 ;
		RECT 0.0714 9.7255 0.1097 9.8259 ;
		RECT 0.0714 10.3278 0.1097 10.4282 ;
		RECT 0.0714 10.5161 0.1097 10.6165 ;
		RECT 0.0714 11.1184 0.1097 11.2188 ;
		RECT 0.0714 11.3067 0.1097 11.4071 ;
		RECT 0.0714 11.909 0.1097 12.0094 ;
		RECT 0.0714 12.0973 0.1097 12.1976 ;
		RECT 0.0714 12.6996 0.1097 12.8 ;
		RECT 0.0714 12.8878 0.1097 12.9882 ;
		RECT 0.0714 13.4902 0.1097 13.5906 ;
		RECT 0.0714 13.6784 0.1097 13.7788 ;
		RECT 0.0714 14.2808 0.1097 14.3812 ;
		RECT 0.0714 14.469 0.1097 14.5694 ;
		RECT 0.0714 15.0714 0.1097 15.1718 ;
		RECT 0.0714 15.2596 0.1097 15.36 ;
		RECT 0.0714 15.862 0.1097 15.9624 ;
		RECT 0.0714 16.0502 0.1097 16.1506 ;
		RECT 0.0714 16.6525 0.1097 16.7529 ;
		RECT 0.0714 16.8408 0.1097 16.9412 ;
		RECT 0.0714 17.4431 0.1097 17.5435 ;
		RECT 0.0714 17.6314 0.1097 17.7318 ;
		RECT 0.0714 18.2337 0.1097 18.3341 ;
		RECT 0.0714 18.422 0.1097 18.5224 ;
		RECT 0.0714 19.0243 0.1097 19.1247 ;
		RECT 0.0714 19.2125 0.1097 19.3129 ;
		RECT 0.0714 19.8149 0.1097 19.9153 ;
		RECT 0.0714 20.0031 0.1097 20.1035 ;
		RECT 0.0714 20.6055 0.1097 20.7059 ;
		RECT 0.0714 20.7937 0.1097 20.8941 ;
		RECT 0.0714 21.3961 0.1097 21.4965 ;
		RECT 0.0714 21.5843 0.1097 21.6847 ;
		RECT 0.0714 22.1867 0.1097 22.2871 ;
		RECT 0.0714 22.3749 0.1097 22.4753 ;
		RECT 0.0714 22.9773 0.1097 23.0776 ;
		RECT 0.0714 23.1655 0.1097 23.2659 ;
		RECT 0.0714 23.7678 0.1097 23.8682 ;
		RECT 0.0714 23.9561 0.1097 24.0565 ;
		RECT 0.0714 24.5584 0.1097 24.6588 ;
		RECT 0.0714 24.7467 0.1097 24.8471 ;
		RECT 0.0714 25.349 0.1097 25.4494 ;
		RECT 0.0714 25.5373 0.1097 25.6376 ;
		RECT 0.0714 26.1396 0.1097 26.24 ;
		RECT 0.0714 27.6204 0.1097 27.7208 ;
		RECT 0.0714 28.0722 0.1097 28.1725 ;
		RECT 0.0714 28.2227 0.1097 28.3231 ;
		RECT 0.0714 28.6243 0.1097 28.7247 ;
		RECT 0.0714 29.0761 0.1097 29.1765 ;
		RECT 0.0714 29.2267 0.1097 29.3271 ;
		RECT 0.0714 29.5027 0.1097 29.6031 ;
		RECT 0.0714 29.6533 0.1097 29.7537 ;
		RECT 0.0714 30.1051 0.1097 30.2055 ;
		RECT 0.0714 30.2557 0.1097 30.3561 ;
		RECT 0.0714 30.3812 0.1097 30.4816 ;
		RECT 0.0714 30.5067 0.1097 30.6071 ;
		RECT 0.0714 31.1843 0.1097 31.2847 ;
		RECT 0.0714 31.4353 0.1097 31.5357 ;
		RECT 0.0714 31.5608 0.1097 31.6612 ;
		RECT 0.0714 31.7114 0.1097 31.8118 ;
		RECT 0.0714 31.8369 0.1097 31.9373 ;
		RECT 0.0714 31.9624 0.1097 32.0627 ;
		RECT 0.0714 32.0878 0.1097 32.1882 ;
		RECT 0.0714 32.2384 0.1097 32.3388 ;
		RECT 0.0714 32.3639 0.1097 32.4643 ;
		RECT 0.0714 32.4894 0.1097 32.5898 ;
		RECT 0.0714 32.6149 0.1097 32.7153 ;
		RECT 0.0714 32.7655 0.1097 32.8659 ;
		RECT 0.0714 32.891 0.1097 32.9914 ;
		RECT 0.0714 33.0165 0.1097 33.1169 ;
		RECT 0.0714 33.142 0.1097 33.2424 ;
		RECT 0.0714 33.2925 0.1097 33.3929 ;
		RECT 0.0714 33.418 0.1097 33.5184 ;
		RECT 0.0714 33.5435 0.1097 33.6439 ;
		RECT 0.0714 33.669 0.1097 33.7694 ;
		RECT 0.0714 34.0706 0.1097 34.171 ;
		RECT 0.0714 34.2212 0.1097 34.3216 ;
		RECT 0.0714 34.3718 0.1097 34.4722 ;
		RECT 0.0714 35.4071 0.1097 35.5075 ;
		RECT 0.0714 36.0094 0.1097 36.1098 ;
		RECT 0.0714 36.1976 0.1097 36.298 ;
		RECT 0.0714 36.8 0.1097 36.9004 ;
		RECT 0.0714 36.9882 0.1097 37.0886 ;
		RECT 0.0714 37.5906 0.1097 37.691 ;
		RECT 0.0714 37.7788 0.1097 37.8792 ;
		RECT 0.0714 38.3812 0.1097 38.4816 ;
		RECT 0.0714 38.5694 0.1097 38.6698 ;
		RECT 0.0714 39.1718 0.1097 39.2722 ;
		RECT 0.0714 39.36 0.1097 39.4604 ;
		RECT 0.0714 39.9624 0.1097 40.0627 ;
		RECT 0.0714 40.1506 0.1097 40.251 ;
		RECT 0.0714 40.7529 0.1097 40.8533 ;
		RECT 0.0714 40.9412 0.1097 41.0416 ;
		RECT 0.0714 41.5435 0.1097 41.6439 ;
		RECT 0.0714 41.7318 0.1097 41.8322 ;
		RECT 0.0714 42.3341 0.1097 42.4345 ;
		RECT 0.0714 42.5224 0.1097 42.6227 ;
		RECT 0.0714 43.1247 0.1097 43.2251 ;
		RECT 0.0714 43.3129 0.1097 43.4133 ;
		RECT 0.0714 43.9153 0.1097 44.0157 ;
		RECT 0.0714 44.1035 0.1097 44.2039 ;
		RECT 0.0714 44.7059 0.1097 44.8063 ;
		RECT 0.0714 44.8941 0.1097 44.9945 ;
		RECT 0.0714 45.4965 0.1097 45.5969 ;
		RECT 0.0714 45.6847 0.1097 45.7851 ;
		RECT 0.0714 46.2871 0.1097 46.3875 ;
		RECT 0.0714 46.4753 0.1097 46.5757 ;
		RECT 0.0714 47.0776 0.1097 47.178 ;
		RECT 0.0714 47.2659 0.1097 47.3663 ;
		RECT 0.0714 47.8682 0.1097 47.9686 ;
		RECT 0.0714 48.0565 0.1097 48.1569 ;
		RECT 0.0714 48.6588 0.1097 48.7592 ;
		RECT 0.0714 48.8471 0.1097 48.9475 ;
		RECT 0.0714 49.4494 0.1097 49.5498 ;
		RECT 0.0714 49.6376 0.1097 49.738 ;
		RECT 0.0714 50.24 0.1097 50.3404 ;
		RECT 0.0714 50.4282 0.1097 50.5286 ;
		RECT 0.0714 51.0306 0.1097 51.131 ;
		RECT 0.0714 51.2188 0.1097 51.3192 ;
		RECT 0.0714 51.8212 0.1097 51.9216 ;
		RECT 0.0714 52.0094 0.1097 52.1098 ;
		RECT 0.0714 52.6118 0.1097 52.7122 ;
		RECT 0.0714 52.8 0.1097 52.9004 ;
		RECT 0.0714 53.4024 0.1097 53.5027 ;
		RECT 0.0714 53.5906 0.1097 53.691 ;
		RECT 0.0714 54.1929 0.1097 54.2933 ;
		RECT 0.0714 54.3812 0.1097 54.4816 ;
		RECT 0.0714 54.9835 0.1097 55.0839 ;
		RECT 0.0714 55.1718 0.1097 55.2722 ;
		RECT 0.0714 55.7741 0.1097 55.8745 ;
		RECT 0.0714 55.9624 0.1097 56.0627 ;
		RECT 0.0714 56.5647 0.1097 56.6651 ;
		RECT 0.0714 56.7529 0.1097 56.8533 ;
		RECT 0.0714 57.3553 0.1097 57.4557 ;
		RECT 0.0714 57.5435 0.1097 57.6439 ;
		RECT 0.0714 58.1459 0.1097 58.2463 ;
		RECT 0.0714 58.3341 0.1097 58.4345 ;
		RECT 0.0714 58.9365 0.1097 59.0369 ;
		RECT 0.0714 59.1247 0.1097 59.2251 ;
		RECT 0.0714 59.7271 0.1097 59.8275 ;
		RECT 0.0714 59.9153 0.1097 60.0157 ;
		RECT 0.0714 60.5176 0.1097 60.618 ;
		RECT 0.0714 60.7059 0.1097 60.8063 ;
		RECT 0.0714 61.3082 0.1097 61.4086 ;
		RECT 0.0098 27.2314 0.0481 27.269 ;
		RECT 0.0098 27.771 0.0481 27.8086 ;
		RECT 0.0098 29.5655 0.0481 29.6031 ;
		RECT 0.0098 29.8039 0.0481 29.8416 ;
		RECT 0.0098 29.8667 0.0481 29.9043 ;
		RECT 0.0098 29.9545 0.0481 29.9922 ;
		RECT 0.0098 30.0173 0.0481 30.0549 ;
		RECT 0.0098 30.6573 0.0481 30.6949 ;
		RECT 0.0098 30.72 0.0481 30.7576 ;
		RECT 0.0098 30.7827 0.0481 30.8204 ;
		RECT 0.0098 30.8455 0.0481 30.8831 ;
		RECT 0.0098 30.9082 0.0481 30.9459 ;
		RECT 0.0098 27.8337 0.0481 27.8714 ;
		RECT 0.0098 30.971 0.0481 31.0086 ;
		RECT 0.0098 31.0337 0.0481 31.0714 ;
		RECT 0.0098 31.0965 0.0481 31.1341 ;
		RECT 0.0098 31.1843 0.0481 31.222 ;
		RECT 0.0098 31.2471 0.0481 31.2847 ;
		RECT 0.0098 31.3098 0.0481 31.3475 ;
		RECT 0.0098 31.3725 0.0481 31.4102 ;
		RECT 0.0098 31.5608 0.0481 31.5984 ;
		RECT 0.0098 33.8196 0.0481 33.8573 ;
		RECT 0.0098 33.8824 0.0481 33.92 ;
		RECT 0.0098 27.9216 0.0481 27.9592 ;
		RECT 0.0098 33.9451 0.0481 33.9827 ;
		RECT 0.0098 34.0078 0.0481 34.0455 ;
		RECT 0.0098 34.2212 0.0481 34.2588 ;
		RECT 0.0098 27.9843 0.0481 28.022 ;
		RECT 0.0714 28.9255 0.1097 28.9631 ;
		RECT 0.0098 28.9882 0.0481 29.0259 ;
		RECT 0.0098 29.2267 0.0481 29.2643 ;
		RECT 0.0098 29.2894 0.0481 29.3271 ;
		RECT 0.0098 29.3773 0.0481 29.4149 ;
		 LAYER M2 SPACING 0.012 ;
		RECT 0.0714 0.2384 0.1097 0.3388 ;
		RECT 0.0714 0.8408 0.1097 0.9412 ;
		RECT 0.0714 1.029 0.1097 1.1294 ;
		RECT 0.0714 1.6314 0.1097 1.7318 ;
		RECT 0.0714 1.8196 0.1097 1.92 ;
		RECT 0.0714 2.422 0.1097 2.5224 ;
		RECT 0.0714 2.6102 0.1097 2.7106 ;
		RECT 0.0714 3.2125 0.1097 3.3129 ;
		RECT 0.0714 3.4008 0.1097 3.5012 ;
		RECT 0.0714 4.0031 0.1097 4.1035 ;
		RECT 0.0714 4.1914 0.1097 4.2918 ;
		RECT 0.0714 4.7937 0.1097 4.8941 ;
		RECT 0.0714 4.982 0.1097 5.0824 ;
		RECT 0.0714 5.5843 0.1097 5.6847 ;
		RECT 0.0714 5.7725 0.1097 5.8729 ;
		RECT 0.0714 6.3749 0.1097 6.4753 ;
		RECT 0.0714 6.5631 0.1097 6.6635 ;
		RECT 0.0714 7.1655 0.1097 7.2659 ;
		RECT 0.0714 7.3537 0.1097 7.4541 ;
		RECT 0.0714 7.9561 0.1097 8.0565 ;
		RECT 0.0714 8.1443 0.1097 8.2447 ;
		RECT 0.0714 8.7467 0.1097 8.8471 ;
		RECT 0.0714 8.9349 0.1097 9.0353 ;
		RECT 0.0714 9.5373 0.1097 9.6376 ;
		RECT 0.0714 9.7255 0.1097 9.8259 ;
		RECT 0.0714 10.3278 0.1097 10.4282 ;
		RECT 0.0714 10.5161 0.1097 10.6165 ;
		RECT 0.0714 11.1184 0.1097 11.2188 ;
		RECT 0.0714 11.3067 0.1097 11.4071 ;
		RECT 0.0714 11.909 0.1097 12.0094 ;
		RECT 0.0714 12.0973 0.1097 12.1976 ;
		RECT 0.0714 12.6996 0.1097 12.8 ;
		RECT 0.0714 12.8878 0.1097 12.9882 ;
		RECT 0.0714 13.4902 0.1097 13.5906 ;
		RECT 0.0714 13.6784 0.1097 13.7788 ;
		RECT 0.0714 14.2808 0.1097 14.3812 ;
		RECT 0.0714 14.469 0.1097 14.5694 ;
		RECT 0.0714 15.0714 0.1097 15.1718 ;
		RECT 0.0714 15.2596 0.1097 15.36 ;
		RECT 0.0714 15.862 0.1097 15.9624 ;
		RECT 0.0714 16.0502 0.1097 16.1506 ;
		RECT 0.0714 16.6525 0.1097 16.7529 ;
		RECT 0.0714 16.8408 0.1097 16.9412 ;
		RECT 0.0714 17.4431 0.1097 17.5435 ;
		RECT 0.0714 17.6314 0.1097 17.7318 ;
		RECT 0.0714 18.2337 0.1097 18.3341 ;
		RECT 0.0714 18.422 0.1097 18.5224 ;
		RECT 0.0714 19.0243 0.1097 19.1247 ;
		RECT 0.0714 19.2125 0.1097 19.3129 ;
		RECT 0.0714 19.8149 0.1097 19.9153 ;
		RECT 0.0714 20.0031 0.1097 20.1035 ;
		RECT 0.0714 20.6055 0.1097 20.7059 ;
		RECT 0.0714 20.7937 0.1097 20.8941 ;
		RECT 0.0714 21.3961 0.1097 21.4965 ;
		RECT 0.0714 21.5843 0.1097 21.6847 ;
		RECT 0.0714 22.1867 0.1097 22.2871 ;
		RECT 0.0714 22.3749 0.1097 22.4753 ;
		RECT 0.0714 22.9773 0.1097 23.0776 ;
		RECT 0.0714 23.1655 0.1097 23.2659 ;
		RECT 0.0714 23.7678 0.1097 23.8682 ;
		RECT 0.0714 23.9561 0.1097 24.0565 ;
		RECT 0.0714 24.5584 0.1097 24.6588 ;
		RECT 0.0714 24.7467 0.1097 24.8471 ;
		RECT 0.0714 25.349 0.1097 25.4494 ;
		RECT 0.0714 25.5373 0.1097 25.6376 ;
		RECT 0.0714 26.1396 0.1097 26.24 ;
		RECT 0.0714 27.6204 0.1097 27.7208 ;
		RECT 0.0714 28.0722 0.1097 28.1725 ;
		RECT 0.0714 28.2227 0.1097 28.3231 ;
		RECT 0.0714 28.6243 0.1097 28.7247 ;
		RECT 0.0714 29.0761 0.1097 29.1765 ;
		RECT 0.0714 29.2267 0.1097 29.3271 ;
		RECT 0.0714 29.5027 0.1097 29.6031 ;
		RECT 0.0714 29.6533 0.1097 29.7537 ;
		RECT 0.0714 30.1051 0.1097 30.2055 ;
		RECT 0.0714 30.2557 0.1097 30.3561 ;
		RECT 0.0714 30.3812 0.1097 30.4816 ;
		RECT 0.0714 30.5067 0.1097 30.6071 ;
		RECT 0.0714 31.1843 0.1097 31.2847 ;
		RECT 0.0714 31.4353 0.1097 31.5357 ;
		RECT 0.0714 31.5608 0.1097 31.6612 ;
		RECT 0.0714 31.7114 0.1097 31.8118 ;
		RECT 0.0714 31.8369 0.1097 31.9373 ;
		RECT 0.0714 31.9624 0.1097 32.0627 ;
		RECT 0.0714 32.0878 0.1097 32.1882 ;
		RECT 0.0714 32.2384 0.1097 32.3388 ;
		RECT 0.0714 32.3639 0.1097 32.4643 ;
		RECT 0.0714 32.4894 0.1097 32.5898 ;
		RECT 0.0714 32.6149 0.1097 32.7153 ;
		RECT 0.0714 32.7655 0.1097 32.8659 ;
		RECT 0.0714 32.891 0.1097 32.9914 ;
		RECT 0.0714 33.0165 0.1097 33.1169 ;
		RECT 0.0714 33.142 0.1097 33.2424 ;
		RECT 0.0714 33.2925 0.1097 33.3929 ;
		RECT 0.0714 33.418 0.1097 33.5184 ;
		RECT 0.0714 33.5435 0.1097 33.6439 ;
		RECT 0.0714 33.669 0.1097 33.7694 ;
		RECT 0.0714 34.0706 0.1097 34.171 ;
		RECT 0.0714 34.2212 0.1097 34.3216 ;
		RECT 0.0714 34.3718 0.1097 34.4722 ;
		RECT 0.0714 35.4071 0.1097 35.5075 ;
		RECT 0.0714 36.0094 0.1097 36.1098 ;
		RECT 0.0714 36.1976 0.1097 36.298 ;
		RECT 0.0714 36.8 0.1097 36.9004 ;
		RECT 0.0714 36.9882 0.1097 37.0886 ;
		RECT 0.0714 37.5906 0.1097 37.691 ;
		RECT 0.0714 37.7788 0.1097 37.8792 ;
		RECT 0.0714 38.3812 0.1097 38.4816 ;
		RECT 0.0714 38.5694 0.1097 38.6698 ;
		RECT 0.0714 39.1718 0.1097 39.2722 ;
		RECT 0.0714 39.36 0.1097 39.4604 ;
		RECT 0.0714 39.9624 0.1097 40.0627 ;
		RECT 0.0714 40.1506 0.1097 40.251 ;
		RECT 0.0714 40.7529 0.1097 40.8533 ;
		RECT 0.0714 40.9412 0.1097 41.0416 ;
		RECT 0.0714 41.5435 0.1097 41.6439 ;
		RECT 0.0714 41.7318 0.1097 41.8322 ;
		RECT 0.0714 42.3341 0.1097 42.4345 ;
		RECT 0.0714 42.5224 0.1097 42.6227 ;
		RECT 0.0714 43.1247 0.1097 43.2251 ;
		RECT 0.0714 43.3129 0.1097 43.4133 ;
		RECT 0.0714 43.9153 0.1097 44.0157 ;
		RECT 0.0714 44.1035 0.1097 44.2039 ;
		RECT 0.0714 44.7059 0.1097 44.8063 ;
		RECT 0.0714 44.8941 0.1097 44.9945 ;
		RECT 0.0714 45.4965 0.1097 45.5969 ;
		RECT 0.0714 45.6847 0.1097 45.7851 ;
		RECT 0.0714 46.2871 0.1097 46.3875 ;
		RECT 0.0714 46.4753 0.1097 46.5757 ;
		RECT 0.0714 47.0776 0.1097 47.178 ;
		RECT 0.0714 47.2659 0.1097 47.3663 ;
		RECT 0.0714 47.8682 0.1097 47.9686 ;
		RECT 0.0714 48.0565 0.1097 48.1569 ;
		RECT 0.0714 48.6588 0.1097 48.7592 ;
		RECT 0.0714 48.8471 0.1097 48.9475 ;
		RECT 0.0714 49.4494 0.1097 49.5498 ;
		RECT 0.0714 49.6376 0.1097 49.738 ;
		RECT 0.0714 50.24 0.1097 50.3404 ;
		RECT 0.0714 50.4282 0.1097 50.5286 ;
		RECT 0.0714 51.0306 0.1097 51.131 ;
		RECT 0.0714 51.2188 0.1097 51.3192 ;
		RECT 0.0714 51.8212 0.1097 51.9216 ;
		RECT 0.0714 52.0094 0.1097 52.1098 ;
		RECT 0.0714 52.6118 0.1097 52.7122 ;
		RECT 0.0714 52.8 0.1097 52.9004 ;
		RECT 0.0714 53.4024 0.1097 53.5027 ;
		RECT 0.0714 53.5906 0.1097 53.691 ;
		RECT 0.0714 54.1929 0.1097 54.2933 ;
		RECT 0.0714 54.3812 0.1097 54.4816 ;
		RECT 0.0714 54.9835 0.1097 55.0839 ;
		RECT 0.0714 55.1718 0.1097 55.2722 ;
		RECT 0.0714 55.7741 0.1097 55.8745 ;
		RECT 0.0714 55.9624 0.1097 56.0627 ;
		RECT 0.0714 56.5647 0.1097 56.6651 ;
		RECT 0.0714 56.7529 0.1097 56.8533 ;
		RECT 0.0714 57.3553 0.1097 57.4557 ;
		RECT 0.0714 57.5435 0.1097 57.6439 ;
		RECT 0.0714 58.1459 0.1097 58.2463 ;
		RECT 0.0714 58.3341 0.1097 58.4345 ;
		RECT 0.0714 58.9365 0.1097 59.0369 ;
		RECT 0.0714 59.1247 0.1097 59.2251 ;
		RECT 0.0714 59.7271 0.1097 59.8275 ;
		RECT 0.0714 59.9153 0.1097 60.0157 ;
		RECT 0.0714 60.5176 0.1097 60.618 ;
		RECT 0.0714 60.7059 0.1097 60.8063 ;
		RECT 0.0714 61.3082 0.1097 61.4086 ;
		RECT 0.0098 27.2314 0.0481 27.269 ;
		RECT 0.0098 27.771 0.0481 27.8086 ;
		RECT 0.0098 29.5655 0.0481 29.6031 ;
		RECT 0.0098 29.8039 0.0481 29.8416 ;
		RECT 0.0098 29.8667 0.0481 29.9043 ;
		RECT 0.0098 29.9545 0.0481 29.9922 ;
		RECT 0.0098 30.0173 0.0481 30.0549 ;
		RECT 0.0098 30.6573 0.0481 30.6949 ;
		RECT 0.0098 30.72 0.0481 30.7576 ;
		RECT 0.0098 30.7827 0.0481 30.8204 ;
		RECT 0.0098 30.8455 0.0481 30.8831 ;
		RECT 0.0098 30.9082 0.0481 30.9459 ;
		RECT 0.0098 27.8337 0.0481 27.8714 ;
		RECT 0.0098 30.971 0.0481 31.0086 ;
		RECT 0.0098 31.0337 0.0481 31.0714 ;
		RECT 0.0098 31.0965 0.0481 31.1341 ;
		RECT 0.0098 31.1843 0.0481 31.222 ;
		RECT 0.0098 31.2471 0.0481 31.2847 ;
		RECT 0.0098 31.3098 0.0481 31.3475 ;
		RECT 0.0098 31.3725 0.0481 31.4102 ;
		RECT 0.0098 31.5608 0.0481 31.5984 ;
		RECT 0.0098 33.8196 0.0481 33.8573 ;
		RECT 0.0098 33.8824 0.0481 33.92 ;
		RECT 0.0098 27.9216 0.0481 27.9592 ;
		RECT 0.0098 33.9451 0.0481 33.9827 ;
		RECT 0.0098 34.0078 0.0481 34.0455 ;
		RECT 0.0098 34.2212 0.0481 34.2588 ;
		RECT 0.0098 27.9843 0.0481 28.022 ;
		RECT 0.0714 28.9255 0.1097 28.9631 ;
		RECT 0.0098 28.9882 0.0481 29.0259 ;
		RECT 0.0098 29.2267 0.0481 29.2643 ;
		RECT 0.0098 29.2894 0.0481 29.3271 ;
		RECT 0.0098 29.3773 0.0481 29.4149 ;
		 LAYER M3 SPACING 0.012 ;
		RECT 0.133 0 31.521 61.6471 ;
		RECT 0 0 0.133 0.069 ;
		RECT 0 0.2071 0.133 0.2196 ;
		RECT 0 0.3576 0.133 0.3702 ;
		RECT 0 0.5082 0.133 0.5208 ;
		RECT 0 0.7843 0.133 0.822 ;
		RECT 0 0.96 0.133 1.0102 ;
		RECT 0 1.1482 0.133 1.1608 ;
		RECT 0 1.2988 0.133 1.3114 ;
		RECT 0 1.5749 0.133 1.6125 ;
		RECT 0 1.7506 0.133 1.8008 ;
		RECT 0 1.9388 0.133 1.9514 ;
		RECT 0 2.0894 0.133 2.102 ;
		RECT 0 2.3655 0.133 2.4031 ;
		RECT 0 2.5412 0.133 2.5914 ;
		RECT 0 2.7294 0.133 2.742 ;
		RECT 0 2.88 0.133 2.8925 ;
		RECT 0 3.1561 0.133 3.1937 ;
		RECT 0 3.3318 0.133 3.382 ;
		RECT 0 3.52 0.133 3.5325 ;
		RECT 0 3.6706 0.133 3.6831 ;
		RECT 0 3.9467 0.133 3.9843 ;
		RECT 0 4.1224 0.133 4.1725 ;
		RECT 0 4.3106 0.133 4.3231 ;
		RECT 0 4.4612 0.133 4.4737 ;
		RECT 0 4.7373 0.133 4.7749 ;
		RECT 0 4.9129 0.133 4.9631 ;
		RECT 0 5.1012 0.133 5.1137 ;
		RECT 0 5.2518 0.133 5.2643 ;
		RECT 0 5.5278 0.133 5.5655 ;
		RECT 0 5.7035 0.133 5.7537 ;
		RECT 0 5.8918 0.133 5.9043 ;
		RECT 0 6.0424 0.133 6.0549 ;
		RECT 0 6.3184 0.133 6.3561 ;
		RECT 0 6.4941 0.133 6.5443 ;
		RECT 0 6.6824 0.133 6.6949 ;
		RECT 0 6.8329 0.133 6.8455 ;
		RECT 0 7.109 0.133 7.1467 ;
		RECT 0 7.2847 0.133 7.3349 ;
		RECT 0 7.4729 0.133 7.4855 ;
		RECT 0 7.6235 0.133 7.6361 ;
		RECT 0 7.8996 0.133 7.9373 ;
		RECT 0 8.0753 0.133 8.1255 ;
		RECT 0 8.2635 0.133 8.2761 ;
		RECT 0 8.4141 0.133 8.4267 ;
		RECT 0 8.6902 0.133 8.7278 ;
		RECT 0 8.8659 0.133 8.9161 ;
		RECT 0 9.0541 0.133 9.0667 ;
		RECT 0 9.2047 0.133 9.2173 ;
		RECT 0 9.4808 0.133 9.5184 ;
		RECT 0 9.6565 0.133 9.7067 ;
		RECT 0 9.8447 0.133 9.8573 ;
		RECT 0 9.9953 0.133 10.0078 ;
		RECT 0 10.2714 0.133 10.309 ;
		RECT 0 10.4471 0.133 10.4973 ;
		RECT 0 10.6353 0.133 10.6478 ;
		RECT 0 10.7859 0.133 10.7984 ;
		RECT 0 11.062 0.133 11.0996 ;
		RECT 0 11.2376 0.133 11.2878 ;
		RECT 0 11.4259 0.133 11.4384 ;
		RECT 0 11.5765 0.133 11.589 ;
		RECT 0 11.8525 0.133 11.8902 ;
		RECT 0 12.0282 0.133 12.0784 ;
		RECT 0 12.2165 0.133 12.229 ;
		RECT 0 12.3671 0.133 12.3796 ;
		RECT 0 12.6431 0.133 12.6808 ;
		RECT 0 12.8188 0.133 12.869 ;
		RECT 0 13.0071 0.133 13.0196 ;
		RECT 0 13.1576 0.133 13.1702 ;
		RECT 0 13.4337 0.133 13.4714 ;
		RECT 0 13.6094 0.133 13.6596 ;
		RECT 0 13.7976 0.133 13.8102 ;
		RECT 0 13.9482 0.133 13.9608 ;
		RECT 0 14.2243 0.133 14.262 ;
		RECT 0 14.4 0.133 14.4502 ;
		RECT 0 14.5882 0.133 14.6008 ;
		RECT 0 14.7388 0.133 14.7514 ;
		RECT 0 15.0149 0.133 15.0525 ;
		RECT 0 15.1906 0.133 15.2408 ;
		RECT 0 15.3788 0.133 15.3914 ;
		RECT 0 15.5294 0.133 15.542 ;
		RECT 0 15.8055 0.133 15.8431 ;
		RECT 0 15.9812 0.133 16.0314 ;
		RECT 0 16.1694 0.133 16.182 ;
		RECT 0 16.32 0.133 16.3325 ;
		RECT 0 16.5961 0.133 16.6337 ;
		RECT 0 16.7718 0.133 16.822 ;
		RECT 0 16.96 0.133 16.9725 ;
		RECT 0 17.1106 0.133 17.1231 ;
		RECT 0 17.3867 0.133 17.4243 ;
		RECT 0 17.5624 0.133 17.6125 ;
		RECT 0 17.7506 0.133 17.7631 ;
		RECT 0 17.9012 0.133 17.9137 ;
		RECT 0 18.1773 0.133 18.2149 ;
		RECT 0 18.3529 0.133 18.4031 ;
		RECT 0 18.5412 0.133 18.5537 ;
		RECT 0 18.6918 0.133 18.7043 ;
		RECT 0 18.9678 0.133 19.0055 ;
		RECT 0 19.1435 0.133 19.1937 ;
		RECT 0 19.3318 0.133 19.3443 ;
		RECT 0 19.4824 0.133 19.4949 ;
		RECT 0 19.7584 0.133 19.7961 ;
		RECT 0 19.9341 0.133 19.9843 ;
		RECT 0 20.1224 0.133 20.1349 ;
		RECT 0 20.2729 0.133 20.2855 ;
		RECT 0 20.549 0.133 20.5867 ;
		RECT 0 20.7247 0.133 20.7749 ;
		RECT 0 20.9129 0.133 20.9255 ;
		RECT 0 21.0635 0.133 21.0761 ;
		RECT 0 21.3396 0.133 21.3773 ;
		RECT 0 21.5153 0.133 21.5655 ;
		RECT 0 21.7035 0.133 21.7161 ;
		RECT 0 21.8541 0.133 21.8667 ;
		RECT 0 22.1302 0.133 22.1678 ;
		RECT 0 22.3059 0.133 22.3561 ;
		RECT 0 22.4941 0.133 22.5067 ;
		RECT 0 22.6447 0.133 22.6573 ;
		RECT 0 22.9208 0.133 22.9584 ;
		RECT 0 23.0965 0.133 23.1467 ;
		RECT 0 23.2847 0.133 23.2973 ;
		RECT 0 23.4353 0.133 23.4478 ;
		RECT 0 23.7114 0.133 23.749 ;
		RECT 0 23.8871 0.133 23.9373 ;
		RECT 0 24.0753 0.133 24.0878 ;
		RECT 0 24.2259 0.133 24.2384 ;
		RECT 0 24.502 0.133 24.5396 ;
		RECT 0 24.6776 0.133 24.7278 ;
		RECT 0 24.8659 0.133 24.8784 ;
		RECT 0 25.0165 0.133 25.029 ;
		RECT 0 25.2925 0.133 25.3302 ;
		RECT 0 25.4682 0.133 25.5184 ;
		RECT 0 25.6565 0.133 25.669 ;
		RECT 0 25.8071 0.133 25.8196 ;
		RECT 0 26.0831 0.133 26.1208 ;
		RECT 0 26.2588 0.133 27.1498 ;
		RECT 0 27.2878 0.133 27.3004 ;
		RECT 0.0714 27.3004 0.133 27.451 ;
		RECT 0 27.4384 0.133 27.451 ;
		RECT 0.0714 27.451 0.133 27.6016 ;
		RECT 0 27.589 0.133 27.6016 ;
		RECT 0 27.7396 0.133 28.0533 ;
		RECT 0 28.1914 0.133 28.2039 ;
		RECT 0 28.342 0.133 28.3545 ;
		RECT 0 28.869 0.133 29.0573 ;
		RECT 0 29.1953 0.133 29.2078 ;
		RECT 0 29.3459 0.133 29.3584 ;
		RECT 0 29.622 0.133 29.6345 ;
		RECT 0 29.7725 0.133 30.0863 ;
		RECT 0 30.2243 0.133 30.2369 ;
		RECT 0 30.6259 0.133 31.1655 ;
		RECT 0 31.3035 0.133 31.4165 ;
		RECT 0 31.68 0.133 31.6925 ;
		RECT 0 32.2071 0.133 32.2196 ;
		RECT 0 32.7341 0.133 32.7467 ;
		RECT 0 33.2612 0.133 33.2737 ;
		RECT 0 33.7882 0.133 34.0518 ;
		RECT 0 34.1898 0.133 34.2024 ;
		RECT 0 34.3404 0.133 34.3529 ;
		RECT 0 34.491 0.133 35.3882 ;
		RECT 0 35.5263 0.133 35.5639 ;
		RECT 0 35.8275 0.133 35.84 ;
		RECT 0 35.978 0.133 35.9906 ;
		RECT 0 36.1286 0.133 36.1788 ;
		RECT 0 36.3169 0.133 36.3545 ;
		RECT 0 36.618 0.133 36.6306 ;
		RECT 0 36.7686 0.133 36.7812 ;
		RECT 0 36.9192 0.133 36.9694 ;
		RECT 0 37.1075 0.133 37.1451 ;
		RECT 0 37.4086 0.133 37.4212 ;
		RECT 0 37.5592 0.133 37.5718 ;
		RECT 0 37.7098 0.133 37.76 ;
		RECT 0 37.898 0.133 37.9357 ;
		RECT 0 38.1992 0.133 38.2118 ;
		RECT 0 38.3498 0.133 38.3624 ;
		RECT 0 38.5004 0.133 38.5506 ;
		RECT 0 38.6886 0.133 38.7263 ;
		RECT 0 38.9898 0.133 39.0024 ;
		RECT 0 39.1404 0.133 39.1529 ;
		RECT 0 39.291 0.133 39.3412 ;
		RECT 0 39.4792 0.133 39.5169 ;
		RECT 0 39.7804 0.133 39.7929 ;
		RECT 0 39.931 0.133 39.9435 ;
		RECT 0 40.0816 0.133 40.1318 ;
		RECT 0 40.2698 0.133 40.3075 ;
		RECT 0 40.571 0.133 40.5835 ;
		RECT 0 40.7216 0.133 40.7341 ;
		RECT 0 40.8722 0.133 40.9224 ;
		RECT 0 41.0604 0.133 41.098 ;
		RECT 0 41.3616 0.133 41.3741 ;
		RECT 0 41.5122 0.133 41.5247 ;
		RECT 0 41.6627 0.133 41.7129 ;
		RECT 0 41.851 0.133 41.8886 ;
		RECT 0 42.1522 0.133 42.1647 ;
		RECT 0 42.3027 0.133 42.3153 ;
		RECT 0 42.4533 0.133 42.5035 ;
		RECT 0 42.6416 0.133 42.6792 ;
		RECT 0 42.9427 0.133 42.9553 ;
		RECT 0 43.0933 0.133 43.1059 ;
		RECT 0 43.2439 0.133 43.2941 ;
		RECT 0 43.4322 0.133 43.4698 ;
		RECT 0 43.7333 0.133 43.7459 ;
		RECT 0 43.8839 0.133 43.8965 ;
		RECT 0 44.0345 0.133 44.0847 ;
		RECT 0 44.2227 0.133 44.2604 ;
		RECT 0 44.5239 0.133 44.5365 ;
		RECT 0 44.6745 0.133 44.6871 ;
		RECT 0 44.8251 0.133 44.8753 ;
		RECT 0 45.0133 0.133 45.051 ;
		RECT 0 45.3145 0.133 45.3271 ;
		RECT 0 45.4651 0.133 45.4776 ;
		RECT 0 45.6157 0.133 45.6659 ;
		RECT 0 45.8039 0.133 45.8416 ;
		RECT 0 46.1051 0.133 46.1176 ;
		RECT 0 46.2557 0.133 46.2682 ;
		RECT 0 46.4063 0.133 46.4565 ;
		RECT 0 46.5945 0.133 46.6322 ;
		RECT 0 46.8957 0.133 46.9082 ;
		RECT 0 47.0463 0.133 47.0588 ;
		RECT 0 47.1969 0.133 47.2471 ;
		RECT 0 47.3851 0.133 47.4227 ;
		RECT 0 47.6863 0.133 47.6988 ;
		RECT 0 47.8369 0.133 47.8494 ;
		RECT 0 47.9875 0.133 48.0376 ;
		RECT 0 48.1757 0.133 48.2133 ;
		RECT 0 48.4769 0.133 48.4894 ;
		RECT 0 48.6275 0.133 48.64 ;
		RECT 0 48.778 0.133 48.8282 ;
		RECT 0 48.9663 0.133 49.0039 ;
		RECT 0 49.2675 0.133 49.28 ;
		RECT 0 49.418 0.133 49.4306 ;
		RECT 0 49.5686 0.133 49.6188 ;
		RECT 0 49.7569 0.133 49.7945 ;
		RECT 0 50.058 0.133 50.0706 ;
		RECT 0 50.2086 0.133 50.2212 ;
		RECT 0 50.3592 0.133 50.4094 ;
		RECT 0 50.5475 0.133 50.5851 ;
		RECT 0 50.8486 0.133 50.8612 ;
		RECT 0 50.9992 0.133 51.0118 ;
		RECT 0 51.1498 0.133 51.2 ;
		RECT 0 51.338 0.133 51.3757 ;
		RECT 0 51.6392 0.133 51.6518 ;
		RECT 0 51.7898 0.133 51.8024 ;
		RECT 0 51.9404 0.133 51.9906 ;
		RECT 0 52.1286 0.133 52.1663 ;
		RECT 0 52.4298 0.133 52.4424 ;
		RECT 0 52.5804 0.133 52.5929 ;
		RECT 0 52.731 0.133 52.7812 ;
		RECT 0 52.9192 0.133 52.9569 ;
		RECT 0 53.2204 0.133 53.2329 ;
		RECT 0 53.371 0.133 53.3835 ;
		RECT 0 53.5216 0.133 53.5718 ;
		RECT 0 53.7098 0.133 53.7475 ;
		RECT 0 54.011 0.133 54.0235 ;
		RECT 0 54.1616 0.133 54.1741 ;
		RECT 0 54.3122 0.133 54.3624 ;
		RECT 0 54.5004 0.133 54.538 ;
		RECT 0 54.8016 0.133 54.8141 ;
		RECT 0 54.9522 0.133 54.9647 ;
		RECT 0 55.1027 0.133 55.1529 ;
		RECT 0 55.291 0.133 55.3286 ;
		RECT 0 55.5922 0.133 55.6047 ;
		RECT 0 55.7427 0.133 55.7553 ;
		RECT 0 55.8933 0.133 55.9435 ;
		RECT 0 56.0816 0.133 56.1192 ;
		RECT 0 56.3827 0.133 56.3953 ;
		RECT 0 56.5333 0.133 56.5459 ;
		RECT 0 56.6839 0.133 56.7341 ;
		RECT 0 56.8722 0.133 56.9098 ;
		RECT 0 57.1733 0.133 57.1859 ;
		RECT 0 57.3239 0.133 57.3365 ;
		RECT 0 57.4745 0.133 57.5247 ;
		RECT 0 57.6627 0.133 57.7004 ;
		RECT 0 57.9639 0.133 57.9765 ;
		RECT 0 58.1145 0.133 58.1271 ;
		RECT 0 58.2651 0.133 58.3153 ;
		RECT 0 58.4533 0.133 58.491 ;
		RECT 0 58.7545 0.133 58.7671 ;
		RECT 0 58.9051 0.133 58.9176 ;
		RECT 0 59.0557 0.133 59.1059 ;
		RECT 0 59.2439 0.133 59.2816 ;
		RECT 0 59.5451 0.133 59.5576 ;
		RECT 0 59.6957 0.133 59.7082 ;
		RECT 0 59.8463 0.133 59.8965 ;
		RECT 0 60.0345 0.133 60.0722 ;
		RECT 0 60.3357 0.133 60.3482 ;
		RECT 0 60.4863 0.133 60.4988 ;
		RECT 0 60.6369 0.133 60.6871 ;
		RECT 0 60.8251 0.133 60.8627 ;
		RECT 0 61.1263 0.133 61.1388 ;
		RECT 0 61.2769 0.133 61.2894 ;
		RECT 0 61.4275 0.133 61.44 ;
		RECT 0 61.578 0.133 61.6471 ;
		 LAYER M3 ;
		RECT 0.0098 27.1686 0.0481 27.269 ;
		RECT 0.0714 27.771 0.1097 27.8714 ;
		RECT 0.0714 27.9216 0.1097 28.022 ;
		RECT 0.0714 28.6243 0.1097 28.7247 ;
		RECT 0.0098 28.9255 0.0481 29.0259 ;
		RECT 0.0714 28.9255 0.1097 29.0259 ;
		RECT 0.0098 29.3773 0.0481 29.4776 ;
		RECT 0.0714 29.8039 0.1097 29.9043 ;
		RECT 0.0714 29.9545 0.1097 30.0549 ;
		RECT 0.0714 30.6573 0.1097 30.7576 ;
		RECT 0.0714 30.7827 0.1097 30.8831 ;
		RECT 0.0714 30.9082 0.1097 31.0086 ;
		RECT 0.0714 31.0337 0.1097 31.1341 ;
		RECT 0.0714 31.3098 0.1097 31.4102 ;
		RECT 0.0714 33.8196 0.1097 33.92 ;
		RECT 0.0714 33.9451 0.1097 34.0455 ;
		 LAYER M3 SPACING 0.012 ;
		RECT 0.0098 27.1686 0.0481 27.269 ;
		RECT 0.0714 27.771 0.1097 27.8714 ;
		RECT 0.0714 27.9216 0.1097 28.022 ;
		RECT 0.0714 28.6243 0.1097 28.7247 ;
		RECT 0.0098 28.9255 0.0481 29.0259 ;
		RECT 0.0714 28.9255 0.1097 29.0259 ;
		RECT 0.0098 29.3773 0.0481 29.4776 ;
		RECT 0.0714 29.8039 0.1097 29.9043 ;
		RECT 0.0714 29.9545 0.1097 30.0549 ;
		RECT 0.0714 30.6573 0.1097 30.7576 ;
		RECT 0.0714 30.7827 0.1097 30.8831 ;
		RECT 0.0714 30.9082 0.1097 31.0086 ;
		RECT 0.0714 31.0337 0.1097 31.1341 ;
		RECT 0.0714 31.3098 0.1097 31.4102 ;
		RECT 0.0714 33.8196 0.1097 33.92 ;
		RECT 0.0714 33.9451 0.1097 34.0455 ;
		 LAYER M4 SPACING 0.018 ;
		RECT 0.2105 0.3984 31.374 0.8439 ;
		RECT 31.374 0.3984 31.521 0.8439 ;
		RECT 0.2105 1.189 31.374 1.6345 ;
		RECT 31.374 1.189 31.521 1.6345 ;
		RECT 0.2105 1.9796 31.374 2.4251 ;
		RECT 31.374 1.9796 31.521 2.4251 ;
		RECT 0.2105 2.7702 31.374 3.2157 ;
		RECT 31.374 2.7702 31.521 3.2157 ;
		RECT 0.2105 3.5608 31.374 4.0063 ;
		RECT 31.374 3.5608 31.521 4.0063 ;
		RECT 0.2105 4.3514 31.374 4.7969 ;
		RECT 31.374 4.3514 31.521 4.7969 ;
		RECT 0.2105 5.142 31.374 5.5875 ;
		RECT 31.374 5.142 31.521 5.5875 ;
		RECT 0.2105 5.9325 31.374 6.378 ;
		RECT 31.374 5.9325 31.521 6.378 ;
		RECT 0.2105 6.7231 31.374 7.1686 ;
		RECT 31.374 6.7231 31.521 7.1686 ;
		RECT 0.2105 7.5137 31.374 7.9592 ;
		RECT 31.374 7.5137 31.521 7.9592 ;
		RECT 0.2105 8.3043 31.374 8.7498 ;
		RECT 31.374 8.3043 31.521 8.7498 ;
		RECT 0.2105 9.0949 31.374 9.5404 ;
		RECT 31.374 9.0949 31.521 9.5404 ;
		RECT 0.2105 9.8855 31.374 10.331 ;
		RECT 31.374 9.8855 31.521 10.331 ;
		RECT 0.2105 10.6761 31.374 11.1216 ;
		RECT 31.374 10.6761 31.521 11.1216 ;
		RECT 0.2105 11.4667 31.374 11.9122 ;
		RECT 31.374 11.4667 31.521 11.9122 ;
		RECT 0.2105 12.2573 31.374 12.7027 ;
		RECT 31.374 12.2573 31.521 12.7027 ;
		RECT 0.2105 13.0478 31.374 13.4933 ;
		RECT 31.374 13.0478 31.521 13.4933 ;
		RECT 0.2105 13.8384 31.374 14.2839 ;
		RECT 31.374 13.8384 31.521 14.2839 ;
		RECT 0.2105 14.629 31.374 15.0745 ;
		RECT 31.374 14.629 31.521 15.0745 ;
		RECT 0.2105 15.4196 31.374 15.8651 ;
		RECT 31.374 15.4196 31.521 15.8651 ;
		RECT 0.2105 16.2102 31.374 16.6557 ;
		RECT 31.374 16.2102 31.521 16.6557 ;
		RECT 0.2105 17.0008 31.374 17.4463 ;
		RECT 31.374 17.0008 31.521 17.4463 ;
		RECT 0.2105 17.7914 31.374 18.2369 ;
		RECT 31.374 17.7914 31.521 18.2369 ;
		RECT 0.2105 18.582 31.374 19.0275 ;
		RECT 31.374 18.582 31.521 19.0275 ;
		RECT 0.2105 19.3725 31.374 19.818 ;
		RECT 31.374 19.3725 31.521 19.818 ;
		RECT 0.2105 20.1631 31.374 20.6086 ;
		RECT 31.374 20.1631 31.521 20.6086 ;
		RECT 0.2105 20.9537 31.374 21.3992 ;
		RECT 31.374 20.9537 31.521 21.3992 ;
		RECT 0.2105 21.7443 31.374 22.1898 ;
		RECT 31.374 21.7443 31.521 22.1898 ;
		RECT 0.2105 22.5349 31.374 22.9804 ;
		RECT 31.374 22.5349 31.521 22.9804 ;
		RECT 0.2105 23.3255 31.374 23.771 ;
		RECT 31.374 23.3255 31.521 23.771 ;
		RECT 0.2105 24.1161 31.374 24.5616 ;
		RECT 31.374 24.1161 31.521 24.5616 ;
		RECT 0.2105 24.9067 31.374 25.3522 ;
		RECT 31.374 24.9067 31.521 25.3522 ;
		RECT 0.2105 25.6973 31.374 26.1427 ;
		RECT 31.374 25.6973 31.521 26.1427 ;
		RECT 0.2105 26.4878 31.374 26.9333 ;
		RECT 31.374 26.4878 31.521 26.9333 ;
		RECT 0.2105 27.4667 31.374 27.6031 ;
		RECT 31.374 27.4667 31.521 27.6031 ;
		RECT 0.2105 27.7914 31.374 27.8949 ;
		RECT 31.374 27.7914 31.521 27.8949 ;
		RECT 0.2105 28.0831 31.374 28.422 ;
		RECT 31.374 28.0831 31.521 28.422 ;
		RECT 0.2105 28.6102 31.374 28.949 ;
		RECT 31.374 28.6102 31.521 28.949 ;
		RECT 0.2105 29.1373 31.374 29.4761 ;
		RECT 31.374 29.1373 31.521 29.4761 ;
		RECT 0.2105 29.6643 31.374 30.0031 ;
		RECT 31.374 29.6643 31.521 30.0031 ;
		RECT 0.2105 30.1914 31.374 31.0573 ;
		RECT 31.374 30.1914 31.521 31.0573 ;
		RECT 0.2105 31.2455 31.374 32.1114 ;
		RECT 31.374 31.2455 31.521 32.1114 ;
		RECT 0.2105 32.2996 31.374 32.6384 ;
		RECT 31.374 32.2996 31.521 32.6384 ;
		RECT 0.2105 32.8267 31.374 33.1655 ;
		RECT 31.374 32.8267 31.521 33.1655 ;
		RECT 0.2105 33.3537 31.374 33.6925 ;
		RECT 31.374 33.3537 31.521 33.6925 ;
		RECT 0.2105 34.251 31.374 34.3373 ;
		RECT 31.374 34.251 31.521 34.3373 ;
		RECT 0.2105 34.7137 31.374 35.1592 ;
		RECT 31.374 34.7137 31.521 35.1592 ;
		RECT 0.2105 35.5043 31.374 35.9498 ;
		RECT 31.374 35.5043 31.521 35.9498 ;
		RECT 0.2105 36.2949 31.374 36.7404 ;
		RECT 31.374 36.2949 31.521 36.7404 ;
		RECT 0.2105 37.0855 31.374 37.531 ;
		RECT 31.374 37.0855 31.521 37.531 ;
		RECT 0.2105 37.8761 31.374 38.3216 ;
		RECT 31.374 37.8761 31.521 38.3216 ;
		RECT 0.2105 38.6667 31.374 39.1122 ;
		RECT 31.374 38.6667 31.521 39.1122 ;
		RECT 0.2105 39.4573 31.374 39.9027 ;
		RECT 31.374 39.4573 31.521 39.9027 ;
		RECT 0.2105 40.2478 31.374 40.6933 ;
		RECT 31.374 40.2478 31.521 40.6933 ;
		RECT 0.2105 41.0384 31.374 41.4839 ;
		RECT 31.374 41.0384 31.521 41.4839 ;
		RECT 0.2105 41.829 31.374 42.2745 ;
		RECT 31.374 41.829 31.521 42.2745 ;
		RECT 0.2105 42.6196 31.374 43.0651 ;
		RECT 31.374 42.6196 31.521 43.0651 ;
		RECT 0.2105 43.4102 31.374 43.8557 ;
		RECT 31.374 43.4102 31.521 43.8557 ;
		RECT 0.2105 44.2008 31.374 44.6463 ;
		RECT 31.374 44.2008 31.521 44.6463 ;
		RECT 0.2105 44.9914 31.374 45.4369 ;
		RECT 31.374 44.9914 31.521 45.4369 ;
		RECT 0.2105 45.782 31.374 46.2275 ;
		RECT 31.374 45.782 31.521 46.2275 ;
		RECT 0.2105 46.5725 31.374 47.018 ;
		RECT 31.374 46.5725 31.521 47.018 ;
		RECT 0.2105 47.3631 31.374 47.8086 ;
		RECT 31.374 47.3631 31.521 47.8086 ;
		RECT 0.2105 48.1537 31.374 48.5992 ;
		RECT 31.374 48.1537 31.521 48.5992 ;
		RECT 0.2105 48.9443 31.374 49.3898 ;
		RECT 31.374 48.9443 31.521 49.3898 ;
		RECT 0.2105 49.7349 31.374 50.1804 ;
		RECT 31.374 49.7349 31.521 50.1804 ;
		RECT 0.2105 50.5255 31.374 50.971 ;
		RECT 31.374 50.5255 31.521 50.971 ;
		RECT 0.2105 51.3161 31.374 51.7616 ;
		RECT 31.374 51.3161 31.521 51.7616 ;
		RECT 0.2105 52.1067 31.374 52.5522 ;
		RECT 31.374 52.1067 31.521 52.5522 ;
		RECT 0.2105 52.8973 31.374 53.3427 ;
		RECT 31.374 52.8973 31.521 53.3427 ;
		RECT 0.2105 53.6878 31.374 54.1333 ;
		RECT 31.374 53.6878 31.521 54.1333 ;
		RECT 0.2105 54.4784 31.374 54.9239 ;
		RECT 31.374 54.4784 31.521 54.9239 ;
		RECT 0.2105 55.269 31.374 55.7145 ;
		RECT 31.374 55.269 31.521 55.7145 ;
		RECT 0.2105 56.0596 31.374 56.5051 ;
		RECT 31.374 56.0596 31.521 56.5051 ;
		RECT 0.2105 56.8502 31.374 57.2957 ;
		RECT 31.374 56.8502 31.521 57.2957 ;
		RECT 0.2105 57.6408 31.374 58.0863 ;
		RECT 31.374 57.6408 31.521 58.0863 ;
		RECT 0.2105 58.4314 31.374 58.8769 ;
		RECT 31.374 58.4314 31.521 58.8769 ;
		RECT 0.2105 59.222 31.374 59.6675 ;
		RECT 31.374 59.222 31.521 59.6675 ;
		RECT 0.2105 60.0125 31.374 60.458 ;
		RECT 31.374 60.0125 31.521 60.458 ;
		RECT 0.2105 60.8031 31.374 61.2486 ;
		RECT 31.374 60.8031 31.521 61.2486 ;
		 LAYER M4 ;
		RECT 0.2105 0 31.374 0.022 ;
		RECT 31.374 0 31.521 0.022 ;
		RECT 0.2105 34.0376 31.374 34.0627 ;
		RECT 31.374 34.0376 31.521 34.0627 ;
		RECT 0.2105 61.6251 31.374 61.6471 ;
		RECT 31.374 61.6251 31.521 61.6471 ;
		 LAYER M4 SPACING 0.018 ;
		RECT 0.2105 0 31.374 0.022 ;
		RECT 31.374 0 31.521 0.022 ;
		RECT 0.2105 34.0376 31.374 34.0627 ;
		RECT 31.374 34.0376 31.521 34.0627 ;
		RECT 0.2105 61.6251 31.374 61.6471 ;
		RECT 31.374 61.6251 31.521 61.6471 ;
		 LAYER V1 SPACING 0 ;
		RECT 0 0 31.521 61.6471 ;
		 LAYER V2 SPACING 0 ;
		RECT 0.1097 0 31.521 61.6471 ;
		RECT 0 0 0.1097 0.0878 ;
		RECT 0 0.1882 0.1097 0.2384 ;
		RECT 0 0.2384 0.0098 0.3388 ;
		RECT 0 0.3388 0.1097 0.389 ;
		RECT 0 0.4894 0.1097 0.5396 ;
		RECT 0 0.64 0.1097 0.6651 ;
		RECT 0 0.7655 0.1097 0.8408 ;
		RECT 0 0.8408 0.0098 0.9412 ;
		RECT 0 0.9412 0.1097 1.029 ;
		RECT 0 1.029 0.0098 1.1294 ;
		RECT 0 1.1294 0.1097 1.1796 ;
		RECT 0 1.28 0.1097 1.3302 ;
		RECT 0 1.4306 0.1097 1.4557 ;
		RECT 0 1.5561 0.1097 1.6314 ;
		RECT 0 1.6314 0.0098 1.7318 ;
		RECT 0 1.7318 0.1097 1.8196 ;
		RECT 0 1.8196 0.0098 1.92 ;
		RECT 0 1.92 0.1097 1.9702 ;
		RECT 0 2.0706 0.1097 2.1208 ;
		RECT 0 2.2212 0.1097 2.2463 ;
		RECT 0 2.3467 0.1097 2.422 ;
		RECT 0 2.422 0.0098 2.5224 ;
		RECT 0 2.5224 0.1097 2.6102 ;
		RECT 0 2.6102 0.0098 2.7106 ;
		RECT 0 2.7106 0.1097 2.7608 ;
		RECT 0 2.8612 0.1097 2.9114 ;
		RECT 0 3.0118 0.1097 3.0369 ;
		RECT 0 3.1373 0.1097 3.2125 ;
		RECT 0 3.2125 0.0098 3.3129 ;
		RECT 0 3.3129 0.1097 3.4008 ;
		RECT 0 3.4008 0.0098 3.5012 ;
		RECT 0 3.5012 0.1097 3.5514 ;
		RECT 0 3.6518 0.1097 3.702 ;
		RECT 0 3.8024 0.1097 3.8275 ;
		RECT 0 3.9278 0.1097 4.0031 ;
		RECT 0 4.0031 0.0098 4.1035 ;
		RECT 0 4.1035 0.1097 4.1914 ;
		RECT 0 4.1914 0.0098 4.2918 ;
		RECT 0 4.2918 0.1097 4.342 ;
		RECT 0 4.4424 0.1097 4.4925 ;
		RECT 0 4.5929 0.1097 4.618 ;
		RECT 0 4.7184 0.1097 4.7937 ;
		RECT 0 4.7937 0.0098 4.8941 ;
		RECT 0 4.8941 0.1097 4.982 ;
		RECT 0 4.982 0.0098 5.0824 ;
		RECT 0 5.0824 0.1097 5.1325 ;
		RECT 0 5.2329 0.1097 5.2831 ;
		RECT 0 5.3835 0.1097 5.4086 ;
		RECT 0 5.509 0.1097 5.5843 ;
		RECT 0 5.5843 0.0098 5.6847 ;
		RECT 0 5.6847 0.1097 5.7725 ;
		RECT 0 5.7725 0.0098 5.8729 ;
		RECT 0 5.8729 0.1097 5.9231 ;
		RECT 0 6.0235 0.1097 6.0737 ;
		RECT 0 6.1741 0.1097 6.1992 ;
		RECT 0 6.2996 0.1097 6.3749 ;
		RECT 0 6.3749 0.0098 6.4753 ;
		RECT 0 6.4753 0.1097 6.5631 ;
		RECT 0 6.5631 0.0098 6.6635 ;
		RECT 0 6.6635 0.1097 6.7137 ;
		RECT 0 6.8141 0.1097 6.8643 ;
		RECT 0 6.9647 0.1097 6.9898 ;
		RECT 0 7.0902 0.1097 7.1655 ;
		RECT 0 7.1655 0.0098 7.2659 ;
		RECT 0 7.2659 0.1097 7.3537 ;
		RECT 0 7.3537 0.0098 7.4541 ;
		RECT 0 7.4541 0.1097 7.5043 ;
		RECT 0 7.6047 0.1097 7.6549 ;
		RECT 0 7.7553 0.1097 7.7804 ;
		RECT 0 7.8808 0.1097 7.9561 ;
		RECT 0 7.9561 0.0098 8.0565 ;
		RECT 0 8.0565 0.1097 8.1443 ;
		RECT 0 8.1443 0.0098 8.2447 ;
		RECT 0 8.2447 0.1097 8.2949 ;
		RECT 0 8.3953 0.1097 8.4455 ;
		RECT 0 8.5459 0.1097 8.571 ;
		RECT 0 8.6714 0.1097 8.7467 ;
		RECT 0 8.7467 0.0098 8.8471 ;
		RECT 0 8.8471 0.1097 8.9349 ;
		RECT 0 8.9349 0.0098 9.0353 ;
		RECT 0 9.0353 0.1097 9.0855 ;
		RECT 0 9.1859 0.1097 9.2361 ;
		RECT 0 9.3365 0.1097 9.3616 ;
		RECT 0 9.462 0.1097 9.5373 ;
		RECT 0 9.5373 0.0098 9.6376 ;
		RECT 0 9.6376 0.1097 9.7255 ;
		RECT 0 9.7255 0.0098 9.8259 ;
		RECT 0 9.8259 0.1097 9.8761 ;
		RECT 0 9.9765 0.1097 10.0267 ;
		RECT 0 10.1271 0.1097 10.1522 ;
		RECT 0 10.2525 0.1097 10.3278 ;
		RECT 0 10.3278 0.0098 10.4282 ;
		RECT 0 10.4282 0.1097 10.5161 ;
		RECT 0 10.5161 0.0098 10.6165 ;
		RECT 0 10.6165 0.1097 10.6667 ;
		RECT 0 10.7671 0.1097 10.8173 ;
		RECT 0 10.9176 0.1097 10.9427 ;
		RECT 0 11.0431 0.1097 11.1184 ;
		RECT 0 11.1184 0.0098 11.2188 ;
		RECT 0 11.2188 0.1097 11.3067 ;
		RECT 0 11.3067 0.0098 11.4071 ;
		RECT 0 11.4071 0.1097 11.4573 ;
		RECT 0 11.5576 0.1097 11.6078 ;
		RECT 0 11.7082 0.1097 11.7333 ;
		RECT 0 11.8337 0.1097 11.909 ;
		RECT 0 11.909 0.0098 12.0094 ;
		RECT 0 12.0094 0.1097 12.0973 ;
		RECT 0 12.0973 0.0098 12.1976 ;
		RECT 0 12.1976 0.1097 12.2478 ;
		RECT 0 12.3482 0.1097 12.3984 ;
		RECT 0 12.4988 0.1097 12.5239 ;
		RECT 0 12.6243 0.1097 12.6996 ;
		RECT 0 12.6996 0.0098 12.8 ;
		RECT 0 12.8 0.1097 12.8878 ;
		RECT 0 12.8878 0.0098 12.9882 ;
		RECT 0 12.9882 0.1097 13.0384 ;
		RECT 0 13.1388 0.1097 13.189 ;
		RECT 0 13.2894 0.1097 13.3145 ;
		RECT 0 13.4149 0.1097 13.4902 ;
		RECT 0 13.4902 0.0098 13.5906 ;
		RECT 0 13.5906 0.1097 13.6784 ;
		RECT 0 13.6784 0.0098 13.7788 ;
		RECT 0 13.7788 0.1097 13.829 ;
		RECT 0 13.9294 0.1097 13.9796 ;
		RECT 0 14.08 0.1097 14.1051 ;
		RECT 0 14.2055 0.1097 14.2808 ;
		RECT 0 14.2808 0.0098 14.3812 ;
		RECT 0 14.3812 0.1097 14.469 ;
		RECT 0 14.469 0.0098 14.5694 ;
		RECT 0 14.5694 0.1097 14.6196 ;
		RECT 0 14.72 0.1097 14.7702 ;
		RECT 0 14.8706 0.1097 14.8957 ;
		RECT 0 14.9961 0.1097 15.0714 ;
		RECT 0 15.0714 0.0098 15.1718 ;
		RECT 0 15.1718 0.1097 15.2596 ;
		RECT 0 15.2596 0.0098 15.36 ;
		RECT 0 15.36 0.1097 15.4102 ;
		RECT 0 15.5106 0.1097 15.5608 ;
		RECT 0 15.6612 0.1097 15.6863 ;
		RECT 0 15.7867 0.1097 15.862 ;
		RECT 0 15.862 0.0098 15.9624 ;
		RECT 0 15.9624 0.1097 16.0502 ;
		RECT 0 16.0502 0.0098 16.1506 ;
		RECT 0 16.1506 0.1097 16.2008 ;
		RECT 0 16.3012 0.1097 16.3514 ;
		RECT 0 16.4518 0.1097 16.4769 ;
		RECT 0 16.5773 0.1097 16.6525 ;
		RECT 0 16.6525 0.0098 16.7529 ;
		RECT 0 16.7529 0.1097 16.8408 ;
		RECT 0 16.8408 0.0098 16.9412 ;
		RECT 0 16.9412 0.1097 16.9914 ;
		RECT 0 17.0918 0.1097 17.142 ;
		RECT 0 17.2424 0.1097 17.2675 ;
		RECT 0 17.3678 0.1097 17.4431 ;
		RECT 0 17.4431 0.0098 17.5435 ;
		RECT 0 17.5435 0.1097 17.6314 ;
		RECT 0 17.6314 0.0098 17.7318 ;
		RECT 0 17.7318 0.1097 17.782 ;
		RECT 0 17.8824 0.1097 17.9325 ;
		RECT 0 18.0329 0.1097 18.058 ;
		RECT 0 18.1584 0.1097 18.2337 ;
		RECT 0 18.2337 0.0098 18.3341 ;
		RECT 0 18.3341 0.1097 18.422 ;
		RECT 0 18.422 0.0098 18.5224 ;
		RECT 0 18.5224 0.1097 18.5725 ;
		RECT 0 18.6729 0.1097 18.7231 ;
		RECT 0 18.8235 0.1097 18.8486 ;
		RECT 0 18.949 0.1097 19.0243 ;
		RECT 0 19.0243 0.0098 19.1247 ;
		RECT 0 19.1247 0.1097 19.2125 ;
		RECT 0 19.2125 0.0098 19.3129 ;
		RECT 0 19.3129 0.1097 19.3631 ;
		RECT 0 19.4635 0.1097 19.5137 ;
		RECT 0 19.6141 0.1097 19.6392 ;
		RECT 0 19.7396 0.1097 19.8149 ;
		RECT 0 19.8149 0.0098 19.9153 ;
		RECT 0 19.9153 0.1097 20.0031 ;
		RECT 0 20.0031 0.0098 20.1035 ;
		RECT 0 20.1035 0.1097 20.1537 ;
		RECT 0 20.2541 0.1097 20.3043 ;
		RECT 0 20.4047 0.1097 20.4298 ;
		RECT 0 20.5302 0.1097 20.6055 ;
		RECT 0 20.6055 0.0098 20.7059 ;
		RECT 0 20.7059 0.1097 20.7937 ;
		RECT 0 20.7937 0.0098 20.8941 ;
		RECT 0 20.8941 0.1097 20.9443 ;
		RECT 0 21.0447 0.1097 21.0949 ;
		RECT 0 21.1953 0.1097 21.2204 ;
		RECT 0 21.3208 0.1097 21.3961 ;
		RECT 0 21.3961 0.0098 21.4965 ;
		RECT 0 21.4965 0.1097 21.5843 ;
		RECT 0 21.5843 0.0098 21.6847 ;
		RECT 0 21.6847 0.1097 21.7349 ;
		RECT 0 21.8353 0.1097 21.8855 ;
		RECT 0 21.9859 0.1097 22.011 ;
		RECT 0 22.1114 0.1097 22.1867 ;
		RECT 0 22.1867 0.0098 22.2871 ;
		RECT 0 22.2871 0.1097 22.3749 ;
		RECT 0 22.3749 0.0098 22.4753 ;
		RECT 0 22.4753 0.1097 22.5255 ;
		RECT 0 22.6259 0.1097 22.6761 ;
		RECT 0 22.7765 0.1097 22.8016 ;
		RECT 0 22.902 0.1097 22.9773 ;
		RECT 0 22.9773 0.0098 23.0776 ;
		RECT 0 23.0776 0.1097 23.1655 ;
		RECT 0 23.1655 0.0098 23.2659 ;
		RECT 0 23.2659 0.1097 23.3161 ;
		RECT 0 23.4165 0.1097 23.4667 ;
		RECT 0 23.5671 0.1097 23.5922 ;
		RECT 0 23.6925 0.1097 23.7678 ;
		RECT 0 23.7678 0.0098 23.8682 ;
		RECT 0 23.8682 0.1097 23.9561 ;
		RECT 0 23.9561 0.0098 24.0565 ;
		RECT 0 24.0565 0.1097 24.1067 ;
		RECT 0 24.2071 0.1097 24.2573 ;
		RECT 0 24.3576 0.1097 24.3827 ;
		RECT 0 24.4831 0.1097 24.5584 ;
		RECT 0 24.5584 0.0098 24.6588 ;
		RECT 0 24.6588 0.1097 24.7467 ;
		RECT 0 24.7467 0.0098 24.8471 ;
		RECT 0 24.8471 0.1097 24.8973 ;
		RECT 0 24.9976 0.1097 25.0478 ;
		RECT 0 25.1482 0.1097 25.1733 ;
		RECT 0 25.2737 0.1097 25.349 ;
		RECT 0 25.349 0.0098 25.4494 ;
		RECT 0 25.4494 0.1097 25.5373 ;
		RECT 0 25.5373 0.0098 25.6376 ;
		RECT 0 25.6376 0.1097 25.6878 ;
		RECT 0 25.7882 0.1097 25.8384 ;
		RECT 0 25.9388 0.1097 25.9639 ;
		RECT 0 26.0643 0.1097 26.1396 ;
		RECT 0 26.1396 0.0098 26.24 ;
		RECT 0 26.24 0.1097 27.1686 ;
		RECT 0 27.269 0.1097 27.3192 ;
		RECT 0 27.4196 0.1097 27.4698 ;
		RECT 0 27.5702 0.1097 27.6204 ;
		RECT 0 27.6204 0.0098 27.7208 ;
		RECT 0 27.7208 0.1097 28.0722 ;
		RECT 0 28.0722 0.0098 28.1725 ;
		RECT 0 28.1725 0.1097 28.2227 ;
		RECT 0 28.2227 0.0098 28.3231 ;
		RECT 0 28.3231 0.1097 28.3733 ;
		RECT 0 28.4737 0.1097 28.4988 ;
		RECT 0 28.5992 0.1097 28.6243 ;
		RECT 0 28.6243 0.0098 28.7247 ;
		RECT 0 28.7247 0.1097 28.7498 ;
		RECT 0 28.8502 0.1097 29.0761 ;
		RECT 0 29.0761 0.0098 29.1765 ;
		RECT 0 29.1765 0.1097 29.2267 ;
		RECT 0 29.2267 0.0098 29.3271 ;
		RECT 0 29.3271 0.1097 29.3773 ;
		RECT 0 29.4776 0.1097 29.5027 ;
		RECT 0 29.5027 0.0098 29.6031 ;
		RECT 0 29.6031 0.1097 29.6533 ;
		RECT 0 29.6533 0.0098 29.7537 ;
		RECT 0 29.7537 0.1097 30.1051 ;
		RECT 0 30.1051 0.0098 30.2055 ;
		RECT 0 30.2055 0.1097 30.2557 ;
		RECT 0 30.2557 0.0098 30.3561 ;
		RECT 0 30.3561 0.1097 30.3812 ;
		RECT 0 30.3812 0.0098 30.4816 ;
		RECT 0 30.4816 0.1097 30.5067 ;
		RECT 0 30.5067 0.0098 30.6071 ;
		RECT 0 30.6071 0.1097 31.1843 ;
		RECT 0 31.1843 0.0098 31.2847 ;
		RECT 0 31.2847 0.1097 31.4353 ;
		RECT 0 31.4353 0.0098 31.5357 ;
		RECT 0 31.5357 0.1097 31.5608 ;
		RECT 0 31.5608 0.0098 31.6612 ;
		RECT 0 31.6612 0.1097 31.7114 ;
		RECT 0 31.7114 0.0098 31.8118 ;
		RECT 0 31.8118 0.1097 31.8369 ;
		RECT 0 31.8369 0.0098 31.9373 ;
		RECT 0 31.9373 0.1097 31.9624 ;
		RECT 0 31.9624 0.0098 32.0627 ;
		RECT 0 32.0627 0.1097 32.0878 ;
		RECT 0 32.0878 0.0098 32.1882 ;
		RECT 0 32.1882 0.1097 32.2384 ;
		RECT 0 32.2384 0.0098 32.3388 ;
		RECT 0 32.3388 0.1097 32.3639 ;
		RECT 0 32.3639 0.0098 32.4643 ;
		RECT 0 32.4643 0.1097 32.4894 ;
		RECT 0 32.4894 0.0098 32.5898 ;
		RECT 0 32.5898 0.1097 32.6149 ;
		RECT 0 32.6149 0.0098 32.7153 ;
		RECT 0 32.7153 0.1097 32.7655 ;
		RECT 0 32.7655 0.0098 32.8659 ;
		RECT 0 32.8659 0.1097 32.891 ;
		RECT 0 32.891 0.0098 32.9914 ;
		RECT 0 32.9914 0.1097 33.0165 ;
		RECT 0 33.0165 0.0098 33.1169 ;
		RECT 0 33.1169 0.1097 33.142 ;
		RECT 0 33.142 0.0098 33.2424 ;
		RECT 0 33.2424 0.1097 33.2925 ;
		RECT 0 33.2925 0.0098 33.3929 ;
		RECT 0 33.3929 0.1097 33.418 ;
		RECT 0 33.418 0.0098 33.5184 ;
		RECT 0 33.5184 0.1097 33.5435 ;
		RECT 0 33.5435 0.0098 33.6439 ;
		RECT 0 33.6439 0.1097 33.669 ;
		RECT 0 33.669 0.0098 33.7694 ;
		RECT 0 33.7694 0.1097 34.0706 ;
		RECT 0 34.0706 0.0098 34.171 ;
		RECT 0 34.171 0.1097 34.2212 ;
		RECT 0 34.2212 0.0098 34.3216 ;
		RECT 0 34.3216 0.1097 34.3718 ;
		RECT 0 34.3718 0.0098 34.4722 ;
		RECT 0 34.4722 0.1097 35.4071 ;
		RECT 0 35.4071 0.0098 35.5075 ;
		RECT 0 35.5075 0.1097 35.5827 ;
		RECT 0 35.6831 0.1097 35.7082 ;
		RECT 0 35.8086 0.1097 35.8588 ;
		RECT 0 35.9592 0.1097 36.0094 ;
		RECT 0 36.0094 0.0098 36.1098 ;
		RECT 0 36.1098 0.1097 36.1976 ;
		RECT 0 36.1976 0.0098 36.298 ;
		RECT 0 36.298 0.1097 36.3733 ;
		RECT 0 36.4737 0.1097 36.4988 ;
		RECT 0 36.5992 0.1097 36.6494 ;
		RECT 0 36.7498 0.1097 36.8 ;
		RECT 0 36.8 0.0098 36.9004 ;
		RECT 0 36.9004 0.1097 36.9882 ;
		RECT 0 36.9882 0.0098 37.0886 ;
		RECT 0 37.0886 0.1097 37.1639 ;
		RECT 0 37.2643 0.1097 37.2894 ;
		RECT 0 37.3898 0.1097 37.44 ;
		RECT 0 37.5404 0.1097 37.5906 ;
		RECT 0 37.5906 0.0098 37.691 ;
		RECT 0 37.691 0.1097 37.7788 ;
		RECT 0 37.7788 0.0098 37.8792 ;
		RECT 0 37.8792 0.1097 37.9545 ;
		RECT 0 38.0549 0.1097 38.08 ;
		RECT 0 38.1804 0.1097 38.2306 ;
		RECT 0 38.331 0.1097 38.3812 ;
		RECT 0 38.3812 0.0098 38.4816 ;
		RECT 0 38.4816 0.1097 38.5694 ;
		RECT 0 38.5694 0.0098 38.6698 ;
		RECT 0 38.6698 0.1097 38.7451 ;
		RECT 0 38.8455 0.1097 38.8706 ;
		RECT 0 38.971 0.1097 39.0212 ;
		RECT 0 39.1216 0.1097 39.1718 ;
		RECT 0 39.1718 0.0098 39.2722 ;
		RECT 0 39.2722 0.1097 39.36 ;
		RECT 0 39.36 0.0098 39.4604 ;
		RECT 0 39.4604 0.1097 39.5357 ;
		RECT 0 39.6361 0.1097 39.6612 ;
		RECT 0 39.7616 0.1097 39.8118 ;
		RECT 0 39.9122 0.1097 39.9624 ;
		RECT 0 39.9624 0.0098 40.0627 ;
		RECT 0 40.0627 0.1097 40.1506 ;
		RECT 0 40.1506 0.0098 40.251 ;
		RECT 0 40.251 0.1097 40.3263 ;
		RECT 0 40.4267 0.1097 40.4518 ;
		RECT 0 40.5522 0.1097 40.6024 ;
		RECT 0 40.7027 0.1097 40.7529 ;
		RECT 0 40.7529 0.0098 40.8533 ;
		RECT 0 40.8533 0.1097 40.9412 ;
		RECT 0 40.9412 0.0098 41.0416 ;
		RECT 0 41.0416 0.1097 41.1169 ;
		RECT 0 41.2173 0.1097 41.2424 ;
		RECT 0 41.3427 0.1097 41.3929 ;
		RECT 0 41.4933 0.1097 41.5435 ;
		RECT 0 41.5435 0.0098 41.6439 ;
		RECT 0 41.6439 0.1097 41.7318 ;
		RECT 0 41.7318 0.0098 41.8322 ;
		RECT 0 41.8322 0.1097 41.9075 ;
		RECT 0 42.0078 0.1097 42.0329 ;
		RECT 0 42.1333 0.1097 42.1835 ;
		RECT 0 42.2839 0.1097 42.3341 ;
		RECT 0 42.3341 0.0098 42.4345 ;
		RECT 0 42.4345 0.1097 42.5224 ;
		RECT 0 42.5224 0.0098 42.6227 ;
		RECT 0 42.6227 0.1097 42.698 ;
		RECT 0 42.7984 0.1097 42.8235 ;
		RECT 0 42.9239 0.1097 42.9741 ;
		RECT 0 43.0745 0.1097 43.1247 ;
		RECT 0 43.1247 0.0098 43.2251 ;
		RECT 0 43.2251 0.1097 43.3129 ;
		RECT 0 43.3129 0.0098 43.4133 ;
		RECT 0 43.4133 0.1097 43.4886 ;
		RECT 0 43.589 0.1097 43.6141 ;
		RECT 0 43.7145 0.1097 43.7647 ;
		RECT 0 43.8651 0.1097 43.9153 ;
		RECT 0 43.9153 0.0098 44.0157 ;
		RECT 0 44.0157 0.1097 44.1035 ;
		RECT 0 44.1035 0.0098 44.2039 ;
		RECT 0 44.2039 0.1097 44.2792 ;
		RECT 0 44.3796 0.1097 44.4047 ;
		RECT 0 44.5051 0.1097 44.5553 ;
		RECT 0 44.6557 0.1097 44.7059 ;
		RECT 0 44.7059 0.0098 44.8063 ;
		RECT 0 44.8063 0.1097 44.8941 ;
		RECT 0 44.8941 0.0098 44.9945 ;
		RECT 0 44.9945 0.1097 45.0698 ;
		RECT 0 45.1702 0.1097 45.1953 ;
		RECT 0 45.2957 0.1097 45.3459 ;
		RECT 0 45.4463 0.1097 45.4965 ;
		RECT 0 45.4965 0.0098 45.5969 ;
		RECT 0 45.5969 0.1097 45.6847 ;
		RECT 0 45.6847 0.0098 45.7851 ;
		RECT 0 45.7851 0.1097 45.8604 ;
		RECT 0 45.9608 0.1097 45.9859 ;
		RECT 0 46.0863 0.1097 46.1365 ;
		RECT 0 46.2369 0.1097 46.2871 ;
		RECT 0 46.2871 0.0098 46.3875 ;
		RECT 0 46.3875 0.1097 46.4753 ;
		RECT 0 46.4753 0.0098 46.5757 ;
		RECT 0 46.5757 0.1097 46.651 ;
		RECT 0 46.7514 0.1097 46.7765 ;
		RECT 0 46.8769 0.1097 46.9271 ;
		RECT 0 47.0275 0.1097 47.0776 ;
		RECT 0 47.0776 0.0098 47.178 ;
		RECT 0 47.178 0.1097 47.2659 ;
		RECT 0 47.2659 0.0098 47.3663 ;
		RECT 0 47.3663 0.1097 47.4416 ;
		RECT 0 47.542 0.1097 47.5671 ;
		RECT 0 47.6675 0.1097 47.7176 ;
		RECT 0 47.818 0.1097 47.8682 ;
		RECT 0 47.8682 0.0098 47.9686 ;
		RECT 0 47.9686 0.1097 48.0565 ;
		RECT 0 48.0565 0.0098 48.1569 ;
		RECT 0 48.1569 0.1097 48.2322 ;
		RECT 0 48.3325 0.1097 48.3576 ;
		RECT 0 48.458 0.1097 48.5082 ;
		RECT 0 48.6086 0.1097 48.6588 ;
		RECT 0 48.6588 0.0098 48.7592 ;
		RECT 0 48.7592 0.1097 48.8471 ;
		RECT 0 48.8471 0.0098 48.9475 ;
		RECT 0 48.9475 0.1097 49.0227 ;
		RECT 0 49.1231 0.1097 49.1482 ;
		RECT 0 49.2486 0.1097 49.2988 ;
		RECT 0 49.3992 0.1097 49.4494 ;
		RECT 0 49.4494 0.0098 49.5498 ;
		RECT 0 49.5498 0.1097 49.6376 ;
		RECT 0 49.6376 0.0098 49.738 ;
		RECT 0 49.738 0.1097 49.8133 ;
		RECT 0 49.9137 0.1097 49.9388 ;
		RECT 0 50.0392 0.1097 50.0894 ;
		RECT 0 50.1898 0.1097 50.24 ;
		RECT 0 50.24 0.0098 50.3404 ;
		RECT 0 50.3404 0.1097 50.4282 ;
		RECT 0 50.4282 0.0098 50.5286 ;
		RECT 0 50.5286 0.1097 50.6039 ;
		RECT 0 50.7043 0.1097 50.7294 ;
		RECT 0 50.8298 0.1097 50.88 ;
		RECT 0 50.9804 0.1097 51.0306 ;
		RECT 0 51.0306 0.0098 51.131 ;
		RECT 0 51.131 0.1097 51.2188 ;
		RECT 0 51.2188 0.0098 51.3192 ;
		RECT 0 51.3192 0.1097 51.3945 ;
		RECT 0 51.4949 0.1097 51.52 ;
		RECT 0 51.6204 0.1097 51.6706 ;
		RECT 0 51.771 0.1097 51.8212 ;
		RECT 0 51.8212 0.0098 51.9216 ;
		RECT 0 51.9216 0.1097 52.0094 ;
		RECT 0 52.0094 0.0098 52.1098 ;
		RECT 0 52.1098 0.1097 52.1851 ;
		RECT 0 52.2855 0.1097 52.3106 ;
		RECT 0 52.411 0.1097 52.4612 ;
		RECT 0 52.5616 0.1097 52.6118 ;
		RECT 0 52.6118 0.0098 52.7122 ;
		RECT 0 52.7122 0.1097 52.8 ;
		RECT 0 52.8 0.0098 52.9004 ;
		RECT 0 52.9004 0.1097 52.9757 ;
		RECT 0 53.0761 0.1097 53.1012 ;
		RECT 0 53.2016 0.1097 53.2518 ;
		RECT 0 53.3522 0.1097 53.4024 ;
		RECT 0 53.4024 0.0098 53.5027 ;
		RECT 0 53.5027 0.1097 53.5906 ;
		RECT 0 53.5906 0.0098 53.691 ;
		RECT 0 53.691 0.1097 53.7663 ;
		RECT 0 53.8667 0.1097 53.8918 ;
		RECT 0 53.9922 0.1097 54.0424 ;
		RECT 0 54.1427 0.1097 54.1929 ;
		RECT 0 54.1929 0.0098 54.2933 ;
		RECT 0 54.2933 0.1097 54.3812 ;
		RECT 0 54.3812 0.0098 54.4816 ;
		RECT 0 54.4816 0.1097 54.5569 ;
		RECT 0 54.6573 0.1097 54.6824 ;
		RECT 0 54.7827 0.1097 54.8329 ;
		RECT 0 54.9333 0.1097 54.9835 ;
		RECT 0 54.9835 0.0098 55.0839 ;
		RECT 0 55.0839 0.1097 55.1718 ;
		RECT 0 55.1718 0.0098 55.2722 ;
		RECT 0 55.2722 0.1097 55.3475 ;
		RECT 0 55.4478 0.1097 55.4729 ;
		RECT 0 55.5733 0.1097 55.6235 ;
		RECT 0 55.7239 0.1097 55.7741 ;
		RECT 0 55.7741 0.0098 55.8745 ;
		RECT 0 55.8745 0.1097 55.9624 ;
		RECT 0 55.9624 0.0098 56.0627 ;
		RECT 0 56.0627 0.1097 56.138 ;
		RECT 0 56.2384 0.1097 56.2635 ;
		RECT 0 56.3639 0.1097 56.4141 ;
		RECT 0 56.5145 0.1097 56.5647 ;
		RECT 0 56.5647 0.0098 56.6651 ;
		RECT 0 56.6651 0.1097 56.7529 ;
		RECT 0 56.7529 0.0098 56.8533 ;
		RECT 0 56.8533 0.1097 56.9286 ;
		RECT 0 57.029 0.1097 57.0541 ;
		RECT 0 57.1545 0.1097 57.2047 ;
		RECT 0 57.3051 0.1097 57.3553 ;
		RECT 0 57.3553 0.0098 57.4557 ;
		RECT 0 57.4557 0.1097 57.5435 ;
		RECT 0 57.5435 0.0098 57.6439 ;
		RECT 0 57.6439 0.1097 57.7192 ;
		RECT 0 57.8196 0.1097 57.8447 ;
		RECT 0 57.9451 0.1097 57.9953 ;
		RECT 0 58.0957 0.1097 58.1459 ;
		RECT 0 58.1459 0.0098 58.2463 ;
		RECT 0 58.2463 0.1097 58.3341 ;
		RECT 0 58.3341 0.0098 58.4345 ;
		RECT 0 58.4345 0.1097 58.5098 ;
		RECT 0 58.6102 0.1097 58.6353 ;
		RECT 0 58.7357 0.1097 58.7859 ;
		RECT 0 58.8863 0.1097 58.9365 ;
		RECT 0 58.9365 0.0098 59.0369 ;
		RECT 0 59.0369 0.1097 59.1247 ;
		RECT 0 59.1247 0.0098 59.2251 ;
		RECT 0 59.2251 0.1097 59.3004 ;
		RECT 0 59.4008 0.1097 59.4259 ;
		RECT 0 59.5263 0.1097 59.5765 ;
		RECT 0 59.6769 0.1097 59.7271 ;
		RECT 0 59.7271 0.0098 59.8275 ;
		RECT 0 59.8275 0.1097 59.9153 ;
		RECT 0 59.9153 0.0098 60.0157 ;
		RECT 0 60.0157 0.1097 60.091 ;
		RECT 0 60.1914 0.1097 60.2165 ;
		RECT 0 60.3169 0.1097 60.3671 ;
		RECT 0 60.4675 0.1097 60.5176 ;
		RECT 0 60.5176 0.0098 60.618 ;
		RECT 0 60.618 0.1097 60.7059 ;
		RECT 0 60.7059 0.0098 60.8063 ;
		RECT 0 60.8063 0.1097 60.8816 ;
		RECT 0 60.982 0.1097 61.0071 ;
		RECT 0 61.1075 0.1097 61.1576 ;
		RECT 0 61.258 0.1097 61.3082 ;
		RECT 0 61.3082 0.0098 61.4086 ;
		RECT 0 61.4086 0.1097 61.4588 ;
		RECT 0 61.5592 0.1097 61.6471 ;
		 LAYER V2 ;
		RECT 0.0481 27.3192 0.1097 27.4698 ;
		RECT 0.0481 27.4698 0.1097 27.6204 ;
		RECT 0.0215 27.2435 0.0364 27.2561 ;
		RECT 0.0831 27.6647 0.098 27.6773 ;
		RECT 0.0831 27.8153 0.098 27.8278 ;
		RECT 0.0831 27.9659 0.098 27.9784 ;
		RECT 0.0831 28.1165 0.098 28.129 ;
		RECT 0.0831 28.2671 0.098 28.2796 ;
		RECT 0.0831 28.6686 0.098 28.6812 ;
		RECT 0.0831 28.9376 0.098 28.9502 ;
		RECT 0.0215 29.0004 0.0364 29.0129 ;
		RECT 0.0831 29.1204 0.098 29.1329 ;
		RECT 0.0831 29.271 0.098 29.2835 ;
		RECT 0.0215 29.3902 0.0364 29.4027 ;
		RECT 0.0831 29.5471 0.098 29.5596 ;
		RECT 0.0831 29.6976 0.098 29.7102 ;
		RECT 0.0831 29.8482 0.098 29.8608 ;
		RECT 0.0831 29.9988 0.098 30.0114 ;
		RECT 0.0831 30.1494 0.098 30.162 ;
		RECT 0.0831 30.3 0.098 30.3125 ;
		RECT 0.0831 30.4255 0.098 30.438 ;
		RECT 0.0831 30.551 0.098 30.5635 ;
		RECT 0.0831 30.7016 0.098 30.7141 ;
		RECT 0.0831 30.8271 0.098 30.8396 ;
		RECT 0.0831 30.9525 0.098 30.9651 ;
		RECT 0.0831 31.078 0.098 31.0906 ;
		RECT 0.0831 31.2286 0.098 31.2412 ;
		RECT 0.0831 31.3541 0.098 31.3667 ;
		RECT 0.0831 31.4796 0.098 31.4922 ;
		RECT 0.0831 31.6051 0.098 31.6176 ;
		RECT 0.0831 31.7557 0.098 31.7682 ;
		RECT 0.0831 31.8812 0.098 31.8937 ;
		RECT 0.0831 32.0067 0.098 32.0192 ;
		RECT 0.0831 32.1322 0.098 32.1447 ;
		RECT 0.0831 32.2827 0.098 32.2953 ;
		RECT 0.0831 32.4082 0.098 32.4208 ;
		RECT 0.0831 32.5337 0.098 32.5463 ;
		RECT 0.0831 32.6592 0.098 32.6718 ;
		RECT 0.0831 32.8098 0.098 32.8224 ;
		RECT 0.0831 32.9353 0.098 32.9478 ;
		RECT 0.0831 33.0608 0.098 33.0733 ;
		RECT 0.0831 33.1863 0.098 33.1988 ;
		RECT 0.0831 33.3369 0.098 33.3494 ;
		RECT 0.0831 33.4624 0.098 33.4749 ;
		RECT 0.0831 33.5878 0.098 33.6004 ;
		RECT 0.0831 33.7133 0.098 33.7259 ;
		RECT 0.0831 33.8639 0.098 33.8765 ;
		RECT 0.0831 33.9894 0.098 34.002 ;
		RECT 0.0831 34.1149 0.098 34.1275 ;
		RECT 0.0831 34.2655 0.098 34.278 ;
		RECT 0.0831 34.4161 0.098 34.4286 ;
		RECT 0.0831 1.0733 0.098 1.0859 ;
		RECT 0.0831 1.6757 0.098 1.6882 ;
		RECT 0.0831 8.1886 0.098 8.2012 ;
		RECT 0.0831 8.791 0.098 8.8035 ;
		RECT 0.0831 8.9792 0.098 8.9918 ;
		RECT 0.0831 9.5816 0.098 9.5941 ;
		RECT 0.0831 9.7698 0.098 9.7824 ;
		RECT 0.0831 10.3722 0.098 10.3847 ;
		RECT 0.0831 10.5604 0.098 10.5729 ;
		RECT 0.0831 11.1627 0.098 11.1753 ;
		RECT 0.0831 11.351 0.098 11.3635 ;
		RECT 0.0831 11.9533 0.098 11.9659 ;
		RECT 0.0831 12.1416 0.098 12.1541 ;
		RECT 0.0831 12.7439 0.098 12.7565 ;
		RECT 0.0831 12.9322 0.098 12.9447 ;
		RECT 0.0831 13.5345 0.098 13.5471 ;
		RECT 0.0831 13.7227 0.098 13.7353 ;
		RECT 0.0831 14.3251 0.098 14.3376 ;
		RECT 0.0831 14.5133 0.098 14.5259 ;
		RECT 0.0831 15.1157 0.098 15.1282 ;
		RECT 0.0831 15.3039 0.098 15.3165 ;
		RECT 0.0831 15.9063 0.098 15.9188 ;
		RECT 0.0831 1.8639 0.098 1.8765 ;
		RECT 0.0831 2.4663 0.098 2.4788 ;
		RECT 0.0831 16.0945 0.098 16.1071 ;
		RECT 0.0831 16.6969 0.098 16.7094 ;
		RECT 0.0831 16.8851 0.098 16.8976 ;
		RECT 0.0831 17.4875 0.098 17.5 ;
		RECT 0.0831 17.6757 0.098 17.6882 ;
		RECT 0.0831 18.278 0.098 18.2906 ;
		RECT 0.0831 18.4663 0.098 18.4788 ;
		RECT 0.0831 19.0686 0.098 19.0812 ;
		RECT 0.0831 19.2569 0.098 19.2694 ;
		RECT 0.0831 19.8592 0.098 19.8718 ;
		RECT 0.0831 20.0475 0.098 20.06 ;
		RECT 0.0831 20.6498 0.098 20.6624 ;
		RECT 0.0831 20.838 0.098 20.8506 ;
		RECT 0.0831 21.4404 0.098 21.4529 ;
		RECT 0.0831 21.6286 0.098 21.6412 ;
		RECT 0.0831 22.231 0.098 22.2435 ;
		RECT 0.0831 22.4192 0.098 22.4318 ;
		RECT 0.0831 23.0216 0.098 23.0341 ;
		RECT 0.0831 23.2098 0.098 23.2224 ;
		RECT 0.0831 23.8122 0.098 23.8247 ;
		RECT 0.0831 2.6545 0.098 2.6671 ;
		RECT 0.0831 3.2569 0.098 3.2694 ;
		RECT 0.0831 24.0004 0.098 24.0129 ;
		RECT 0.0831 24.6027 0.098 24.6153 ;
		RECT 0.0831 24.791 0.098 24.8035 ;
		RECT 0.0831 25.3933 0.098 25.4059 ;
		RECT 0.0831 3.4451 0.098 3.4576 ;
		RECT 0.0831 4.0475 0.098 4.06 ;
		RECT 0.0831 4.2357 0.098 4.2482 ;
		RECT 0.0831 4.838 0.098 4.8506 ;
		RECT 0.0831 5.0263 0.098 5.0388 ;
		RECT 0.0831 5.6286 0.098 5.6412 ;
		RECT 0.0831 5.8169 0.098 5.8294 ;
		RECT 0.0831 6.4192 0.098 6.4318 ;
		RECT 0.0831 6.6075 0.098 6.62 ;
		RECT 0.0831 7.2098 0.098 7.2224 ;
		RECT 0.0831 7.398 0.098 7.4106 ;
		RECT 0.0831 8.0004 0.098 8.0129 ;
		RECT 0.0831 0.2827 0.098 0.2953 ;
		RECT 0.0831 0.8851 0.098 0.8976 ;
		RECT 0.0831 25.5816 0.098 25.5941 ;
		RECT 0.0831 26.1839 0.098 26.1965 ;
		RECT 0.0831 43.1682 0.098 43.1808 ;
		RECT 0.0831 42.5659 0.098 42.5784 ;
		RECT 0.0831 43.9588 0.098 43.9714 ;
		RECT 0.0831 43.3565 0.098 43.369 ;
		RECT 0.0831 44.7494 0.098 44.762 ;
		RECT 0.0831 44.1471 0.098 44.1596 ;
		RECT 0.0831 45.54 0.098 45.5525 ;
		RECT 0.0831 44.9376 0.098 44.9502 ;
		RECT 0.0831 46.3306 0.098 46.3431 ;
		RECT 0.0831 45.7282 0.098 45.7408 ;
		RECT 0.0831 47.1212 0.098 47.1337 ;
		RECT 0.0831 46.5188 0.098 46.5314 ;
		RECT 0.0831 47.9118 0.098 47.9243 ;
		RECT 0.0831 47.3094 0.098 47.322 ;
		RECT 0.0831 48.7024 0.098 48.7149 ;
		RECT 0.0831 48.1 0.098 48.1125 ;
		RECT 0.0831 49.4929 0.098 49.5055 ;
		RECT 0.0831 48.8906 0.098 48.9031 ;
		RECT 0.0831 50.2835 0.098 50.2961 ;
		RECT 0.0831 49.6812 0.098 49.6937 ;
		RECT 0.0831 36.8435 0.098 36.8561 ;
		RECT 0.0831 36.2412 0.098 36.2537 ;
		RECT 0.0831 51.0741 0.098 51.0867 ;
		RECT 0.0831 50.4718 0.098 50.4843 ;
		RECT 0.0831 51.8647 0.098 51.8773 ;
		RECT 0.0831 51.2624 0.098 51.2749 ;
		RECT 0.0831 52.6553 0.098 52.6678 ;
		RECT 0.0831 52.0529 0.098 52.0655 ;
		RECT 0.0831 53.4459 0.098 53.4584 ;
		RECT 0.0831 52.8435 0.098 52.8561 ;
		RECT 0.0831 54.2365 0.098 54.249 ;
		RECT 0.0831 53.6341 0.098 53.6467 ;
		RECT 0.0831 55.0271 0.098 55.0396 ;
		RECT 0.0831 54.4247 0.098 54.4373 ;
		RECT 0.0831 55.8176 0.098 55.8302 ;
		RECT 0.0831 55.2153 0.098 55.2278 ;
		RECT 0.0831 56.6082 0.098 56.6208 ;
		RECT 0.0831 56.0059 0.098 56.0184 ;
		RECT 0.0831 57.3988 0.098 57.4114 ;
		RECT 0.0831 56.7965 0.098 56.809 ;
		RECT 0.0831 58.1894 0.098 58.202 ;
		RECT 0.0831 57.5871 0.098 57.5996 ;
		RECT 0.0831 37.6341 0.098 37.6467 ;
		RECT 0.0831 37.0318 0.098 37.0443 ;
		RECT 0.0831 58.98 0.098 58.9925 ;
		RECT 0.0831 58.3776 0.098 58.3902 ;
		RECT 0.0831 59.7706 0.098 59.7831 ;
		RECT 0.0831 59.1682 0.098 59.1808 ;
		RECT 0.0831 60.5612 0.098 60.5737 ;
		RECT 0.0831 59.9588 0.098 59.9714 ;
		RECT 0.0831 38.4247 0.098 38.4373 ;
		RECT 0.0831 37.8224 0.098 37.8349 ;
		RECT 0.0831 39.2153 0.098 39.2278 ;
		RECT 0.0831 38.6129 0.098 38.6255 ;
		RECT 0.0831 40.0059 0.098 40.0184 ;
		RECT 0.0831 39.4035 0.098 39.4161 ;
		RECT 0.0831 40.7965 0.098 40.809 ;
		RECT 0.0831 40.1941 0.098 40.2067 ;
		RECT 0.0831 41.5871 0.098 41.5996 ;
		RECT 0.0831 40.9847 0.098 40.9973 ;
		RECT 0.0831 42.3776 0.098 42.3902 ;
		RECT 0.0831 41.7753 0.098 41.7878 ;
		RECT 0.0831 36.0529 0.098 36.0655 ;
		RECT 0.0831 35.4506 0.098 35.4631 ;
		RECT 0.0831 61.3518 0.098 61.3643 ;
		RECT 0.0831 60.7494 0.098 60.762 ;
		 LAYER V2 SPACING 0 ;
		RECT 0.0481 27.3192 0.1097 27.4698 ;
		RECT 0.0481 27.4698 0.1097 27.6204 ;
		RECT 0.0215 27.2435 0.0364 27.2561 ;
		RECT 0.0831 27.6647 0.098 27.6773 ;
		RECT 0.0831 27.8153 0.098 27.8278 ;
		RECT 0.0831 27.9659 0.098 27.9784 ;
		RECT 0.0831 28.1165 0.098 28.129 ;
		RECT 0.0831 28.2671 0.098 28.2796 ;
		RECT 0.0831 28.6686 0.098 28.6812 ;
		RECT 0.0831 28.9376 0.098 28.9502 ;
		RECT 0.0215 29.0004 0.0364 29.0129 ;
		RECT 0.0831 29.1204 0.098 29.1329 ;
		RECT 0.0831 29.271 0.098 29.2835 ;
		RECT 0.0215 29.3902 0.0364 29.4027 ;
		RECT 0.0831 29.5471 0.098 29.5596 ;
		RECT 0.0831 29.6976 0.098 29.7102 ;
		RECT 0.0831 29.8482 0.098 29.8608 ;
		RECT 0.0831 29.9988 0.098 30.0114 ;
		RECT 0.0831 30.1494 0.098 30.162 ;
		RECT 0.0831 30.3 0.098 30.3125 ;
		RECT 0.0831 30.4255 0.098 30.438 ;
		RECT 0.0831 30.551 0.098 30.5635 ;
		RECT 0.0831 30.7016 0.098 30.7141 ;
		RECT 0.0831 30.8271 0.098 30.8396 ;
		RECT 0.0831 30.9525 0.098 30.9651 ;
		RECT 0.0831 31.078 0.098 31.0906 ;
		RECT 0.0831 31.2286 0.098 31.2412 ;
		RECT 0.0831 31.3541 0.098 31.3667 ;
		RECT 0.0831 31.4796 0.098 31.4922 ;
		RECT 0.0831 31.6051 0.098 31.6176 ;
		RECT 0.0831 31.7557 0.098 31.7682 ;
		RECT 0.0831 31.8812 0.098 31.8937 ;
		RECT 0.0831 32.0067 0.098 32.0192 ;
		RECT 0.0831 32.1322 0.098 32.1447 ;
		RECT 0.0831 32.2827 0.098 32.2953 ;
		RECT 0.0831 32.4082 0.098 32.4208 ;
		RECT 0.0831 32.5337 0.098 32.5463 ;
		RECT 0.0831 32.6592 0.098 32.6718 ;
		RECT 0.0831 32.8098 0.098 32.8224 ;
		RECT 0.0831 32.9353 0.098 32.9478 ;
		RECT 0.0831 33.0608 0.098 33.0733 ;
		RECT 0.0831 33.1863 0.098 33.1988 ;
		RECT 0.0831 33.3369 0.098 33.3494 ;
		RECT 0.0831 33.4624 0.098 33.4749 ;
		RECT 0.0831 33.5878 0.098 33.6004 ;
		RECT 0.0831 33.7133 0.098 33.7259 ;
		RECT 0.0831 33.8639 0.098 33.8765 ;
		RECT 0.0831 33.9894 0.098 34.002 ;
		RECT 0.0831 34.1149 0.098 34.1275 ;
		RECT 0.0831 34.2655 0.098 34.278 ;
		RECT 0.0831 34.4161 0.098 34.4286 ;
		RECT 0.0831 1.0733 0.098 1.0859 ;
		RECT 0.0831 1.6757 0.098 1.6882 ;
		RECT 0.0831 8.1886 0.098 8.2012 ;
		RECT 0.0831 8.791 0.098 8.8035 ;
		RECT 0.0831 8.9792 0.098 8.9918 ;
		RECT 0.0831 9.5816 0.098 9.5941 ;
		RECT 0.0831 9.7698 0.098 9.7824 ;
		RECT 0.0831 10.3722 0.098 10.3847 ;
		RECT 0.0831 10.5604 0.098 10.5729 ;
		RECT 0.0831 11.1627 0.098 11.1753 ;
		RECT 0.0831 11.351 0.098 11.3635 ;
		RECT 0.0831 11.9533 0.098 11.9659 ;
		RECT 0.0831 12.1416 0.098 12.1541 ;
		RECT 0.0831 12.7439 0.098 12.7565 ;
		RECT 0.0831 12.9322 0.098 12.9447 ;
		RECT 0.0831 13.5345 0.098 13.5471 ;
		RECT 0.0831 13.7227 0.098 13.7353 ;
		RECT 0.0831 14.3251 0.098 14.3376 ;
		RECT 0.0831 14.5133 0.098 14.5259 ;
		RECT 0.0831 15.1157 0.098 15.1282 ;
		RECT 0.0831 15.3039 0.098 15.3165 ;
		RECT 0.0831 15.9063 0.098 15.9188 ;
		RECT 0.0831 1.8639 0.098 1.8765 ;
		RECT 0.0831 2.4663 0.098 2.4788 ;
		RECT 0.0831 16.0945 0.098 16.1071 ;
		RECT 0.0831 16.6969 0.098 16.7094 ;
		RECT 0.0831 16.8851 0.098 16.8976 ;
		RECT 0.0831 17.4875 0.098 17.5 ;
		RECT 0.0831 17.6757 0.098 17.6882 ;
		RECT 0.0831 18.278 0.098 18.2906 ;
		RECT 0.0831 18.4663 0.098 18.4788 ;
		RECT 0.0831 19.0686 0.098 19.0812 ;
		RECT 0.0831 19.2569 0.098 19.2694 ;
		RECT 0.0831 19.8592 0.098 19.8718 ;
		RECT 0.0831 20.0475 0.098 20.06 ;
		RECT 0.0831 20.6498 0.098 20.6624 ;
		RECT 0.0831 20.838 0.098 20.8506 ;
		RECT 0.0831 21.4404 0.098 21.4529 ;
		RECT 0.0831 21.6286 0.098 21.6412 ;
		RECT 0.0831 22.231 0.098 22.2435 ;
		RECT 0.0831 22.4192 0.098 22.4318 ;
		RECT 0.0831 23.0216 0.098 23.0341 ;
		RECT 0.0831 23.2098 0.098 23.2224 ;
		RECT 0.0831 23.8122 0.098 23.8247 ;
		RECT 0.0831 2.6545 0.098 2.6671 ;
		RECT 0.0831 3.2569 0.098 3.2694 ;
		RECT 0.0831 24.0004 0.098 24.0129 ;
		RECT 0.0831 24.6027 0.098 24.6153 ;
		RECT 0.0831 24.791 0.098 24.8035 ;
		RECT 0.0831 25.3933 0.098 25.4059 ;
		RECT 0.0831 3.4451 0.098 3.4576 ;
		RECT 0.0831 4.0475 0.098 4.06 ;
		RECT 0.0831 4.2357 0.098 4.2482 ;
		RECT 0.0831 4.838 0.098 4.8506 ;
		RECT 0.0831 5.0263 0.098 5.0388 ;
		RECT 0.0831 5.6286 0.098 5.6412 ;
		RECT 0.0831 5.8169 0.098 5.8294 ;
		RECT 0.0831 6.4192 0.098 6.4318 ;
		RECT 0.0831 6.6075 0.098 6.62 ;
		RECT 0.0831 7.2098 0.098 7.2224 ;
		RECT 0.0831 7.398 0.098 7.4106 ;
		RECT 0.0831 8.0004 0.098 8.0129 ;
		RECT 0.0831 0.2827 0.098 0.2953 ;
		RECT 0.0831 0.8851 0.098 0.8976 ;
		RECT 0.0831 25.5816 0.098 25.5941 ;
		RECT 0.0831 26.1839 0.098 26.1965 ;
		RECT 0.0831 43.1682 0.098 43.1808 ;
		RECT 0.0831 42.5659 0.098 42.5784 ;
		RECT 0.0831 43.9588 0.098 43.9714 ;
		RECT 0.0831 43.3565 0.098 43.369 ;
		RECT 0.0831 44.7494 0.098 44.762 ;
		RECT 0.0831 44.1471 0.098 44.1596 ;
		RECT 0.0831 45.54 0.098 45.5525 ;
		RECT 0.0831 44.9376 0.098 44.9502 ;
		RECT 0.0831 46.3306 0.098 46.3431 ;
		RECT 0.0831 45.7282 0.098 45.7408 ;
		RECT 0.0831 47.1212 0.098 47.1337 ;
		RECT 0.0831 46.5188 0.098 46.5314 ;
		RECT 0.0831 47.9118 0.098 47.9243 ;
		RECT 0.0831 47.3094 0.098 47.322 ;
		RECT 0.0831 48.7024 0.098 48.7149 ;
		RECT 0.0831 48.1 0.098 48.1125 ;
		RECT 0.0831 49.4929 0.098 49.5055 ;
		RECT 0.0831 48.8906 0.098 48.9031 ;
		RECT 0.0831 50.2835 0.098 50.2961 ;
		RECT 0.0831 49.6812 0.098 49.6937 ;
		RECT 0.0831 36.8435 0.098 36.8561 ;
		RECT 0.0831 36.2412 0.098 36.2537 ;
		RECT 0.0831 51.0741 0.098 51.0867 ;
		RECT 0.0831 50.4718 0.098 50.4843 ;
		RECT 0.0831 51.8647 0.098 51.8773 ;
		RECT 0.0831 51.2624 0.098 51.2749 ;
		RECT 0.0831 52.6553 0.098 52.6678 ;
		RECT 0.0831 52.0529 0.098 52.0655 ;
		RECT 0.0831 53.4459 0.098 53.4584 ;
		RECT 0.0831 52.8435 0.098 52.8561 ;
		RECT 0.0831 54.2365 0.098 54.249 ;
		RECT 0.0831 53.6341 0.098 53.6467 ;
		RECT 0.0831 55.0271 0.098 55.0396 ;
		RECT 0.0831 54.4247 0.098 54.4373 ;
		RECT 0.0831 55.8176 0.098 55.8302 ;
		RECT 0.0831 55.2153 0.098 55.2278 ;
		RECT 0.0831 56.6082 0.098 56.6208 ;
		RECT 0.0831 56.0059 0.098 56.0184 ;
		RECT 0.0831 57.3988 0.098 57.4114 ;
		RECT 0.0831 56.7965 0.098 56.809 ;
		RECT 0.0831 58.1894 0.098 58.202 ;
		RECT 0.0831 57.5871 0.098 57.5996 ;
		RECT 0.0831 37.6341 0.098 37.6467 ;
		RECT 0.0831 37.0318 0.098 37.0443 ;
		RECT 0.0831 58.98 0.098 58.9925 ;
		RECT 0.0831 58.3776 0.098 58.3902 ;
		RECT 0.0831 59.7706 0.098 59.7831 ;
		RECT 0.0831 59.1682 0.098 59.1808 ;
		RECT 0.0831 60.5612 0.098 60.5737 ;
		RECT 0.0831 59.9588 0.098 59.9714 ;
		RECT 0.0831 38.4247 0.098 38.4373 ;
		RECT 0.0831 37.8224 0.098 37.8349 ;
		RECT 0.0831 39.2153 0.098 39.2278 ;
		RECT 0.0831 38.6129 0.098 38.6255 ;
		RECT 0.0831 40.0059 0.098 40.0184 ;
		RECT 0.0831 39.4035 0.098 39.4161 ;
		RECT 0.0831 40.7965 0.098 40.809 ;
		RECT 0.0831 40.1941 0.098 40.2067 ;
		RECT 0.0831 41.5871 0.098 41.5996 ;
		RECT 0.0831 40.9847 0.098 40.9973 ;
		RECT 0.0831 42.3776 0.098 42.3902 ;
		RECT 0.0831 41.7753 0.098 41.7878 ;
		RECT 0.0831 36.0529 0.098 36.0655 ;
		RECT 0.0831 35.4506 0.098 35.4631 ;
		RECT 0.0831 61.3518 0.098 61.3643 ;
		RECT 0.0831 60.7494 0.098 60.762 ;
	END

END HDDP_1024X66M4B1

END LIBRARY

